VERSION 5.7 ;
  NOWIREEXTENSIONATPIN ON ;
  DIVIDERCHAR "/" ;
  BUSBITCHARS "[]" ;
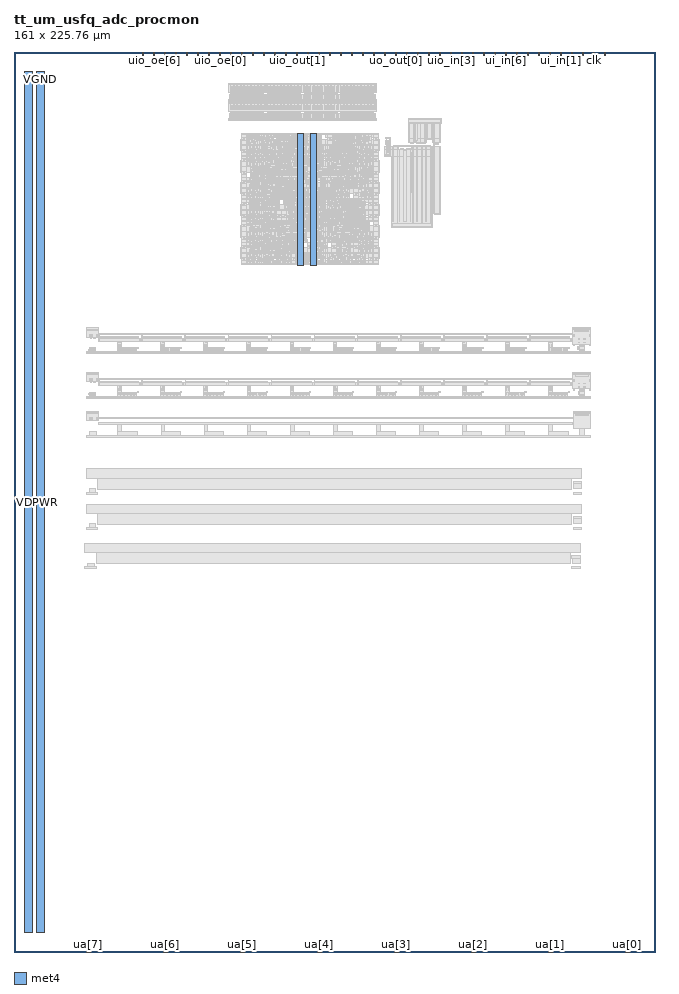
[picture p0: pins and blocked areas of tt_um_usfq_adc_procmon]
MACRO tt_um_usfq_adc_procmon
  CLASS BLOCK ;
  FOREIGN tt_um_usfq_adc_procmon ;
  ORIGIN 1.600 0.000 ;
  SIZE 161.000 BY 225.760 ;
  PIN VGND
    USE GROUND ;
    PORT
      LAYER met4 ;
        RECT 69.495 172.315 71.095 205.435 ;
    END
    PORT
      LAYER met4 ;
        RECT 4.000 5.000 6.000 220.760 ;
    END
  END VGND
  PIN VDPWR
    ANTENNAGATEAREA 171.431000 ;
    ANTENNADIFFAREA 286.977448 ;
    PORT
      LAYER met4 ;
        RECT 72.795 172.315 74.395 205.435 ;
    END
    PORT
      LAYER met4 ;
        RECT 1.000 5.000 3.000 220.760 ;
    END
  END VDPWR
  PIN uo_out[7]
    ANTENNADIFFAREA 0.222600 ;
    PORT
      LAYER met4 ;
        RECT 74.830 224.760 75.130 225.760 ;
    END
  END uo_out[7]
  PIN uo_out[6]
    ANTENNADIFFAREA 0.222600 ;
    PORT
      LAYER met4 ;
        RECT 77.590 224.760 77.890 225.760 ;
    END
  END uo_out[6]
  PIN uo_out[5]
    ANTENNADIFFAREA 0.222600 ;
    PORT
      LAYER met4 ;
        RECT 80.350 224.760 80.650 225.760 ;
    END
  END uo_out[5]
  PIN uo_out[4]
    ANTENNADIFFAREA 0.222600 ;
    PORT
      LAYER met4 ;
        RECT 83.110 224.760 83.410 225.760 ;
    END
  END uo_out[4]
  PIN uo_out[3]
    ANTENNADIFFAREA 0.222600 ;
    PORT
      LAYER met4 ;
        RECT 85.870 224.760 86.170 225.760 ;
    END
  END uo_out[3]
  PIN uo_out[2]
    ANTENNADIFFAREA 0.222600 ;
    PORT
      LAYER met4 ;
        RECT 88.630 224.760 88.930 225.760 ;
    END
  END uo_out[2]
  PIN uo_out[1]
    PORT
      LAYER met4 ;
        RECT 91.390 224.760 91.690 225.760 ;
    END
  END uo_out[1]
  PIN uo_out[0]
    PORT
      LAYER met4 ;
        RECT 94.150 224.760 94.450 225.760 ;
    END
  END uo_out[0]
  PIN uio_out[7]
    ANTENNADIFFAREA 4.233600 ;
    PORT
      LAYER met4 ;
        RECT 52.750 224.760 53.050 225.760 ;
    END
  END uio_out[7]
  PIN uio_out[6]
    ANTENNADIFFAREA 4.233600 ;
    PORT
      LAYER met4 ;
        RECT 55.510 224.760 55.810 225.760 ;
    END
  END uio_out[6]
  PIN uio_out[5]
    ANTENNADIFFAREA 4.233600 ;
    PORT
      LAYER met4 ;
        RECT 58.270 224.760 58.570 225.760 ;
    END
  END uio_out[5]
  PIN uio_out[4]
    ANTENNADIFFAREA 4.233600 ;
    PORT
      LAYER met4 ;
        RECT 61.030 224.760 61.330 225.760 ;
    END
  END uio_out[4]
  PIN uio_out[3]
    ANTENNADIFFAREA 4.233600 ;
    PORT
      LAYER met4 ;
        RECT 63.790 224.760 64.090 225.760 ;
    END
  END uio_out[3]
  PIN uio_out[2]
    ANTENNADIFFAREA 4.233600 ;
    PORT
      LAYER met4 ;
        RECT 66.550 224.760 66.850 225.760 ;
    END
  END uio_out[2]
  PIN uio_out[1]
    ANTENNADIFFAREA 4.936500 ;
    PORT
      LAYER met4 ;
        RECT 69.310 224.760 69.610 225.760 ;
    END
  END uio_out[1]
  PIN uio_out[0]
    ANTENNADIFFAREA 4.233600 ;
    PORT
      LAYER met4 ;
        RECT 72.070 224.760 72.370 225.760 ;
    END
  END uio_out[0]
  PIN uio_oe[7]
    ANTENNAGATEAREA 20.500000 ;
    ANTENNADIFFAREA 80.059700 ;
    PORT
      LAYER met4 ;
        RECT 30.670 224.760 30.970 225.760 ;
    END
  END uio_oe[7]
  PIN uio_oe[6]
    ANTENNAGATEAREA 20.500000 ;
    ANTENNADIFFAREA 80.059700 ;
    PORT
      LAYER met4 ;
        RECT 33.430 224.760 33.730 225.760 ;
    END
  END uio_oe[6]
  PIN uio_oe[5]
    ANTENNAGATEAREA 20.500000 ;
    ANTENNADIFFAREA 80.059700 ;
    PORT
      LAYER met4 ;
        RECT 36.190 224.760 36.490 225.760 ;
    END
  END uio_oe[5]
  PIN uio_oe[4]
    ANTENNAGATEAREA 20.500000 ;
    ANTENNADIFFAREA 80.059700 ;
    PORT
      LAYER met4 ;
        RECT 38.950 224.760 39.250 225.760 ;
    END
  END uio_oe[4]
  PIN uio_oe[3]
    ANTENNAGATEAREA 20.500000 ;
    ANTENNADIFFAREA 80.059700 ;
    PORT
      LAYER met4 ;
        RECT 41.710 224.760 42.010 225.760 ;
    END
  END uio_oe[3]
  PIN uio_oe[2]
    ANTENNAGATEAREA 20.500000 ;
    ANTENNADIFFAREA 80.059700 ;
    PORT
      LAYER met4 ;
        RECT 44.470 224.760 44.770 225.760 ;
    END
  END uio_oe[2]
  PIN uio_oe[1]
    ANTENNAGATEAREA 20.500000 ;
    ANTENNADIFFAREA 80.059700 ;
    PORT
      LAYER met4 ;
        RECT 47.230 224.760 47.530 225.760 ;
    END
  END uio_oe[1]
  PIN uio_oe[0]
    ANTENNAGATEAREA 20.500000 ;
    ANTENNADIFFAREA 80.059700 ;
    PORT
      LAYER met4 ;
        RECT 49.990 224.760 50.290 225.760 ;
    END
  END uio_oe[0]
  PIN uio_in[7]
    PORT
      LAYER met4 ;
        RECT 96.910 224.760 97.210 225.760 ;
    END
  END uio_in[7]
  PIN uio_in[6]
    PORT
      LAYER met4 ;
        RECT 99.670 224.760 99.970 225.760 ;
    END
  END uio_in[6]
  PIN uio_in[5]
    PORT
      LAYER met4 ;
        RECT 102.430 224.760 102.730 225.760 ;
    END
  END uio_in[5]
  PIN uio_in[4]
    PORT
      LAYER met4 ;
        RECT 105.190 224.760 105.490 225.760 ;
    END
  END uio_in[4]
  PIN uio_in[3]
    PORT
      LAYER met4 ;
        RECT 107.950 224.760 108.250 225.760 ;
    END
  END uio_in[3]
  PIN uio_in[2]
    PORT
      LAYER met4 ;
        RECT 110.710 224.760 111.010 225.760 ;
    END
  END uio_in[2]
  PIN uio_in[1]
    PORT
      LAYER met4 ;
        RECT 113.470 224.760 113.770 225.760 ;
    END
  END uio_in[1]
  PIN uio_in[0]
    PORT
      LAYER met4 ;
        RECT 116.230 224.760 116.530 225.760 ;
    END
  END uio_in[0]
  PIN ui_in[7]
    ANTENNAGATEAREA 1.431000 ;
    PORT
      LAYER met4 ;
        RECT 118.990 224.760 119.290 225.760 ;
    END
  END ui_in[7]
  PIN ui_in[6]
    PORT
      LAYER met4 ;
        RECT 121.750 224.760 122.050 225.760 ;
    END
  END ui_in[6]
  PIN ui_in[5]
    PORT
      LAYER met4 ;
        RECT 124.510 224.760 124.810 225.760 ;
    END
  END ui_in[5]
  PIN ui_in[4]
    PORT
      LAYER met4 ;
        RECT 127.270 224.760 127.570 225.760 ;
    END
  END ui_in[4]
  PIN ui_in[3]
    PORT
      LAYER met4 ;
        RECT 130.030 224.760 130.330 225.760 ;
    END
  END ui_in[3]
  PIN ui_in[2]
    PORT
      LAYER met4 ;
        RECT 132.790 224.760 133.090 225.760 ;
    END
  END ui_in[2]
  PIN ui_in[1]
    PORT
      LAYER met4 ;
        RECT 135.550 224.760 135.850 225.760 ;
    END
  END ui_in[1]
  PIN ui_in[0]
    PORT
      LAYER met4 ;
        RECT 138.310 224.760 138.610 225.760 ;
    END
  END ui_in[0]
  PIN ua[7]
    PORT
      LAYER met4 ;
        RECT 16.570 0.000 17.470 1.000 ;
    END
  END ua[7]
  PIN ua[5]
    PORT
      LAYER met4 ;
        RECT 55.210 0.000 56.110 1.000 ;
    END
  END ua[5]
  PIN ua[4]
    PORT
      LAYER met4 ;
        RECT 74.530 0.000 75.430 1.000 ;
    END
  END ua[4]
  PIN ua[3]
    PORT
      LAYER met4 ;
        RECT 93.850 0.000 94.750 1.000 ;
    END
  END ua[3]
  PIN ua[2]
    PORT
      LAYER met4 ;
        RECT 113.170 0.000 114.070 1.000 ;
    END
  END ua[2]
  PIN ua[1]
    ANTENNAGATEAREA 15.929999 ;
    PORT
      LAYER met4 ;
        RECT 132.490 0.000 133.390 1.000 ;
    END
  END ua[1]
  PIN ua[0]
    ANTENNAGATEAREA 16.056000 ;
    PORT
      LAYER met4 ;
        RECT 151.810 0.000 152.710 1.000 ;
    END
  END ua[0]
  PIN rst_n
    PORT
      LAYER met4 ;
        RECT 141.070 224.760 141.370 225.760 ;
    END
  END rst_n
  PIN ena
    PORT
      LAYER met4 ;
        RECT 146.590 224.760 146.890 225.760 ;
    END
  END ena
  PIN clk
    PORT
      LAYER met4 ;
        RECT 143.830 224.760 144.130 225.760 ;
    END
  END clk
  PIN ua[6]
    PORT
      LAYER met4 ;
        RECT 35.890 0.000 36.790 1.000 ;
    END
  END ua[6]
  OBS
      LAYER nwell ;
        RECT 52.250 215.580 89.410 217.955 ;
      LAYER pwell ;
        RECT 52.435 213.765 89.145 214.990 ;
        RECT 52.300 213.255 89.360 213.765 ;
      LAYER nwell ;
        RECT 52.250 210.870 89.410 213.245 ;
      LAYER pwell ;
        RECT 52.435 209.055 89.145 210.280 ;
        RECT 52.300 208.545 89.360 209.055 ;
        RECT 97.290 207.920 105.520 209.070 ;
        RECT 55.560 205.090 55.730 205.280 ;
        RECT 60.165 205.090 60.335 205.280 ;
        RECT 75.335 205.090 75.505 205.280 ;
        RECT 78.100 205.090 78.270 205.280 ;
        RECT 84.545 205.090 84.715 205.280 ;
        RECT 89.600 205.090 89.770 205.280 ;
        RECT 55.420 204.410 75.650 205.090 ;
        RECT 77.040 205.005 89.910 205.090 ;
        RECT 76.590 204.410 89.910 205.005 ;
        RECT 55.420 204.280 64.140 204.410 ;
        RECT 56.800 204.220 64.140 204.280 ;
        RECT 56.800 204.180 62.935 204.220 ;
        RECT 67.675 204.190 68.585 204.410 ;
        RECT 70.120 204.180 71.890 204.410 ;
        RECT 72.735 204.180 75.125 204.410 ;
        RECT 76.590 204.280 87.315 204.410 ;
        RECT 88.540 204.280 89.910 204.410 ;
        RECT 76.590 204.220 77.020 204.280 ;
        RECT 78.420 204.180 87.315 204.280 ;
        RECT 97.355 204.140 105.505 207.920 ;
      LAYER nwell ;
        RECT 55.225 201.060 90.105 203.890 ;
      LAYER pwell ;
        RECT 91.590 202.630 92.960 203.650 ;
        RECT 97.355 203.150 101.785 204.140 ;
        RECT 103.465 202.950 105.505 204.140 ;
      LAYER nwell ;
        RECT 91.405 201.340 94.885 202.040 ;
        RECT 98.125 201.340 103.255 202.040 ;
      LAYER pwell ;
        RECT 57.555 200.670 59.945 200.770 ;
        RECT 55.420 200.540 59.945 200.670 ;
        RECT 62.325 200.540 66.010 200.770 ;
        RECT 67.545 200.540 68.455 200.760 ;
        RECT 71.985 200.670 87.775 200.770 ;
        RECT 71.985 200.540 89.910 200.670 ;
        RECT 55.420 198.970 89.910 200.540 ;
      LAYER nwell ;
        RECT 91.405 199.665 103.255 201.340 ;
      LAYER pwell ;
        RECT 55.420 198.840 62.330 198.970 ;
        RECT 57.555 198.740 62.330 198.840 ;
        RECT 63.865 198.750 64.775 198.970 ;
        RECT 68.380 198.740 70.150 198.970 ;
        RECT 71.685 198.750 72.595 198.970 ;
        RECT 76.590 198.780 78.890 198.970 ;
        RECT 77.120 198.740 78.890 198.780 ;
        RECT 80.425 198.750 81.335 198.970 ;
        RECT 85.385 198.840 89.910 198.970 ;
        RECT 85.385 198.740 87.775 198.840 ;
      LAYER nwell ;
        RECT 55.225 195.620 90.105 198.450 ;
      LAYER pwell ;
        RECT 57.720 195.290 63.560 195.330 ;
        RECT 55.420 194.210 56.790 195.230 ;
        RECT 57.720 195.100 64.140 195.290 ;
        RECT 67.675 195.100 68.585 195.320 ;
        RECT 70.120 195.230 71.890 195.330 ;
        RECT 73.440 195.230 75.210 195.330 ;
        RECT 70.120 195.100 75.210 195.230 ;
        RECT 76.745 195.100 77.655 195.320 ;
        RECT 81.180 195.230 88.520 195.330 ;
        RECT 81.180 195.100 89.910 195.230 ;
        RECT 57.720 194.210 89.910 195.100 ;
        RECT 55.420 193.530 89.910 194.210 ;
        RECT 55.420 193.400 59.110 193.530 ;
        RECT 57.340 193.300 59.110 193.400 ;
        RECT 60.645 193.310 61.555 193.530 ;
        RECT 65.210 193.300 74.205 193.530 ;
        RECT 75.210 193.400 89.910 193.530 ;
        RECT 75.210 193.340 86.395 193.400 ;
        RECT 75.210 193.300 76.560 193.340 ;
        RECT 77.650 193.300 86.395 193.340 ;
      LAYER nwell ;
        RECT 55.225 190.180 90.105 193.010 ;
      LAYER pwell ;
        RECT 57.555 189.790 59.945 189.890 ;
        RECT 55.420 189.660 59.945 189.790 ;
        RECT 62.325 189.660 82.025 189.890 ;
        RECT 85.615 189.790 88.005 189.890 ;
        RECT 55.420 188.980 82.550 189.660 ;
        RECT 55.420 188.090 65.070 188.980 ;
        RECT 66.080 188.770 82.550 188.980 ;
        RECT 83.480 188.770 89.910 189.790 ;
        RECT 66.080 188.090 89.910 188.770 ;
        RECT 55.420 187.960 59.110 188.090 ;
        RECT 57.340 187.860 59.110 187.960 ;
        RECT 60.645 187.870 61.555 188.090 ;
        RECT 66.080 187.860 67.850 188.090 ;
        RECT 69.385 187.870 70.295 188.090 ;
        RECT 74.380 187.960 89.910 188.090 ;
        RECT 74.380 187.900 86.540 187.960 ;
        RECT 74.380 187.860 76.570 187.900 ;
        RECT 77.565 187.860 86.540 187.900 ;
      LAYER nwell ;
        RECT 55.225 184.740 90.105 187.570 ;
      LAYER pwell ;
        RECT 57.555 184.410 63.690 184.450 ;
        RECT 57.555 184.350 64.140 184.410 ;
        RECT 67.000 184.350 68.770 184.450 ;
        RECT 55.420 184.220 68.770 184.350 ;
        RECT 70.305 184.220 71.215 184.440 ;
        RECT 74.870 184.350 86.690 184.450 ;
        RECT 74.870 184.220 89.910 184.350 ;
        RECT 55.420 183.350 89.910 184.220 ;
        RECT 55.420 182.650 87.600 183.350 ;
        RECT 55.420 182.520 59.110 182.650 ;
        RECT 57.340 182.420 59.110 182.520 ;
        RECT 60.645 182.430 61.555 182.650 ;
        RECT 65.160 182.420 66.930 182.650 ;
        RECT 68.465 182.430 69.375 182.650 ;
        RECT 73.360 182.420 80.270 182.650 ;
        RECT 81.805 182.430 82.715 182.650 ;
        RECT 86.250 182.420 87.600 182.650 ;
        RECT 88.540 182.520 89.910 183.350 ;
      LAYER nwell ;
        RECT 55.225 179.300 90.105 182.130 ;
        RECT 93.125 181.730 103.255 199.665 ;
      LAYER pwell ;
        RECT 103.465 185.335 105.505 201.995 ;
        RECT 57.555 178.910 66.010 179.010 ;
        RECT 55.420 178.780 66.010 178.910 ;
        RECT 67.545 178.780 68.455 179.000 ;
        RECT 72.900 178.780 78.890 179.010 ;
        RECT 80.425 178.780 81.335 179.000 ;
        RECT 85.385 178.910 87.775 179.010 ;
        RECT 85.385 178.780 89.910 178.910 ;
        RECT 55.420 178.100 71.970 178.780 ;
        RECT 72.900 178.100 89.910 178.780 ;
        RECT 55.420 177.210 70.900 178.100 ;
        RECT 72.900 177.890 77.020 178.100 ;
        RECT 55.420 177.080 59.110 177.210 ;
        RECT 57.340 176.980 59.110 177.080 ;
        RECT 60.645 176.990 61.555 177.210 ;
        RECT 65.080 176.980 70.900 177.210 ;
        RECT 71.980 177.080 77.020 177.890 ;
        RECT 77.960 177.210 89.910 178.100 ;
        RECT 77.960 177.080 79.330 177.210 ;
        RECT 81.995 177.080 89.910 177.210 ;
        RECT 73.360 177.020 77.020 177.080 ;
        RECT 73.360 176.980 76.560 177.020 ;
        RECT 81.995 176.980 82.915 177.080 ;
        RECT 85.385 176.980 87.775 177.080 ;
      LAYER nwell ;
        RECT 55.225 173.860 90.105 176.690 ;
      LAYER pwell ;
        RECT 57.555 173.530 63.690 173.570 ;
        RECT 64.685 173.530 67.075 173.570 ;
        RECT 57.555 173.470 67.075 173.530 ;
        RECT 70.600 173.470 86.690 173.570 ;
        RECT 55.420 172.745 89.910 173.470 ;
        RECT 55.420 172.660 63.205 172.745 ;
        RECT 64.160 172.660 89.910 172.745 ;
        RECT 55.560 172.470 55.730 172.660 ;
        RECT 60.155 172.470 60.325 172.660 ;
        RECT 64.305 172.470 64.475 172.660 ;
        RECT 68.900 172.470 69.070 172.660 ;
        RECT 70.280 172.470 70.450 172.660 ;
        RECT 88.220 172.470 88.390 172.660 ;
        RECT 89.600 172.470 89.770 172.660 ;
      LAYER nwell ;
        RECT 16.640 154.240 19.475 156.540 ;
      LAYER pwell ;
        RECT 19.485 153.250 138.375 153.930 ;
        RECT 24.410 151.555 25.350 153.250 ;
        RECT 35.220 151.555 36.160 153.250 ;
        RECT 46.030 151.555 46.970 153.250 ;
        RECT 56.840 151.555 57.780 153.250 ;
        RECT 67.650 151.555 68.590 153.250 ;
        RECT 78.460 151.555 79.400 153.250 ;
        RECT 89.270 151.555 90.210 153.250 ;
        RECT 100.080 151.555 101.020 153.250 ;
        RECT 110.890 151.555 111.830 153.250 ;
        RECT 121.700 151.555 122.640 153.250 ;
        RECT 132.510 151.555 133.450 153.250 ;
      LAYER nwell ;
        RECT 138.585 152.440 143.075 156.540 ;
      LAYER pwell ;
        RECT 17.390 150.590 18.920 151.550 ;
        RECT 24.410 150.590 29.220 151.555 ;
        RECT 35.220 150.590 40.030 151.555 ;
        RECT 46.030 150.590 50.840 151.555 ;
        RECT 56.840 150.590 61.650 151.555 ;
        RECT 67.650 150.590 72.460 151.555 ;
        RECT 78.460 150.590 83.270 151.555 ;
        RECT 89.270 150.590 94.080 151.555 ;
        RECT 100.080 150.590 104.890 151.555 ;
        RECT 110.890 150.590 115.700 151.555 ;
        RECT 121.700 150.590 126.510 151.555 ;
        RECT 132.510 150.590 137.320 151.555 ;
        RECT 140.145 150.590 141.515 152.230 ;
        RECT 16.635 150.080 143.080 150.590 ;
      LAYER nwell ;
        RECT 16.665 143.065 19.500 145.365 ;
      LAYER pwell ;
        RECT 19.510 142.075 138.400 142.755 ;
        RECT 24.435 140.380 25.375 142.075 ;
        RECT 35.245 140.380 36.185 142.075 ;
        RECT 46.055 140.380 46.995 142.075 ;
        RECT 56.865 140.380 57.805 142.075 ;
        RECT 67.675 140.380 68.615 142.075 ;
        RECT 78.485 140.380 79.425 142.075 ;
        RECT 89.295 140.380 90.235 142.075 ;
        RECT 100.105 140.380 101.045 142.075 ;
        RECT 110.915 140.380 111.855 142.075 ;
        RECT 121.725 140.380 122.665 142.075 ;
        RECT 132.535 140.380 133.475 142.075 ;
      LAYER nwell ;
        RECT 138.610 141.265 143.100 145.365 ;
      LAYER pwell ;
        RECT 17.415 139.415 18.945 140.375 ;
        RECT 24.435 139.415 29.245 140.380 ;
        RECT 35.245 139.415 40.055 140.380 ;
        RECT 46.055 139.415 50.865 140.380 ;
        RECT 56.865 139.415 61.675 140.380 ;
        RECT 67.675 139.415 72.485 140.380 ;
        RECT 78.485 139.415 83.295 140.380 ;
        RECT 89.295 139.415 94.105 140.380 ;
        RECT 100.105 139.415 104.915 140.380 ;
        RECT 110.915 139.415 115.725 140.380 ;
        RECT 121.725 139.415 126.535 140.380 ;
        RECT 132.535 139.415 137.345 140.380 ;
        RECT 140.170 139.415 141.540 141.055 ;
        RECT 16.660 138.905 143.105 139.415 ;
      LAYER nwell ;
        RECT 16.695 133.230 19.530 135.530 ;
      LAYER pwell ;
        RECT 19.540 132.240 138.430 132.920 ;
        RECT 24.465 130.545 25.405 132.240 ;
        RECT 35.275 130.545 36.215 132.240 ;
        RECT 46.085 130.545 47.025 132.240 ;
        RECT 56.895 130.545 57.835 132.240 ;
        RECT 67.705 130.545 68.645 132.240 ;
        RECT 78.515 130.545 79.455 132.240 ;
        RECT 89.325 130.545 90.265 132.240 ;
        RECT 100.135 130.545 101.075 132.240 ;
        RECT 110.945 130.545 111.885 132.240 ;
        RECT 121.755 130.545 122.695 132.240 ;
        RECT 132.565 130.545 133.505 132.240 ;
      LAYER nwell ;
        RECT 138.640 131.430 143.130 135.530 ;
      LAYER pwell ;
        RECT 17.445 129.580 18.975 130.540 ;
        RECT 24.465 129.580 29.275 130.545 ;
        RECT 35.275 129.580 40.085 130.545 ;
        RECT 46.085 129.580 50.895 130.545 ;
        RECT 56.895 129.580 61.705 130.545 ;
        RECT 67.705 129.580 72.515 130.545 ;
        RECT 78.515 129.580 83.325 130.545 ;
        RECT 89.325 129.580 94.135 130.545 ;
        RECT 100.135 129.580 104.945 130.545 ;
        RECT 110.945 129.580 115.755 130.545 ;
        RECT 121.755 129.580 126.565 130.545 ;
        RECT 132.565 129.580 137.375 130.545 ;
        RECT 140.200 129.580 141.570 131.220 ;
        RECT 16.690 129.070 143.135 129.580 ;
      LAYER nwell ;
        RECT 16.580 118.890 140.870 121.190 ;
        RECT 19.375 118.740 140.870 118.890 ;
      LAYER pwell ;
        RECT 17.330 115.240 18.860 116.200 ;
      LAYER nwell ;
        RECT 19.375 115.990 138.365 118.740 ;
      LAYER pwell ;
        RECT 138.750 117.460 140.820 118.140 ;
        RECT 138.790 116.180 140.780 117.460 ;
        RECT 16.575 114.730 19.415 115.240 ;
        RECT 138.735 114.730 140.835 115.240 ;
      LAYER nwell ;
        RECT 16.565 110.075 140.855 112.375 ;
        RECT 19.360 109.925 140.855 110.075 ;
      LAYER pwell ;
        RECT 17.315 106.425 18.845 107.385 ;
      LAYER nwell ;
        RECT 19.360 107.175 138.350 109.925 ;
      LAYER pwell ;
        RECT 138.735 108.645 140.805 109.325 ;
        RECT 138.775 107.365 140.765 108.645 ;
        RECT 16.560 105.915 19.400 106.425 ;
        RECT 138.720 105.915 140.820 106.425 ;
      LAYER nwell ;
        RECT 16.195 100.240 140.485 102.540 ;
        RECT 18.990 100.090 140.485 100.240 ;
      LAYER pwell ;
        RECT 16.945 96.590 18.475 97.550 ;
      LAYER nwell ;
        RECT 18.990 97.340 137.980 100.090 ;
      LAYER pwell ;
        RECT 138.365 98.810 140.435 99.490 ;
        RECT 138.405 97.530 140.395 98.810 ;
        RECT 16.190 96.080 19.030 96.590 ;
        RECT 138.350 96.080 140.450 96.590 ;
      LAYER li1 ;
        RECT 52.430 217.525 89.230 217.775 ;
        RECT 52.605 215.930 52.775 217.525 ;
        RECT 53.035 215.930 53.205 217.060 ;
        RECT 53.465 215.930 53.635 217.525 ;
        RECT 53.895 215.930 54.065 217.060 ;
        RECT 54.325 215.930 54.495 217.525 ;
        RECT 54.755 215.930 54.925 217.060 ;
        RECT 55.185 215.930 55.355 217.525 ;
        RECT 55.615 215.930 55.785 217.060 ;
        RECT 56.045 215.930 56.215 217.525 ;
        RECT 56.475 215.930 56.645 217.060 ;
        RECT 56.905 215.930 57.075 217.525 ;
        RECT 57.335 215.930 57.505 217.060 ;
        RECT 57.765 215.930 57.935 217.525 ;
        RECT 58.195 215.930 58.365 217.060 ;
        RECT 58.625 215.930 58.795 217.525 ;
        RECT 59.055 215.930 59.225 217.060 ;
        RECT 59.485 215.930 59.655 217.525 ;
        RECT 59.915 215.930 60.085 217.060 ;
        RECT 60.345 215.930 60.515 217.525 ;
        RECT 60.775 215.930 60.945 217.060 ;
        RECT 61.205 215.930 61.375 217.525 ;
        RECT 61.805 215.930 61.975 217.525 ;
        RECT 62.235 215.930 62.405 217.060 ;
        RECT 62.665 215.930 62.835 217.525 ;
        RECT 63.095 215.930 63.265 217.060 ;
        RECT 63.525 215.930 63.695 217.525 ;
        RECT 63.955 215.930 64.125 217.060 ;
        RECT 64.385 215.930 64.555 217.525 ;
        RECT 64.815 215.930 64.985 217.060 ;
        RECT 65.245 215.930 65.415 217.525 ;
        RECT 65.675 215.930 65.845 217.060 ;
        RECT 66.105 215.930 66.275 217.525 ;
        RECT 66.535 215.930 66.705 217.060 ;
        RECT 66.965 215.930 67.135 217.525 ;
        RECT 67.395 215.930 67.565 217.060 ;
        RECT 67.825 215.930 67.995 217.525 ;
        RECT 68.255 215.930 68.425 217.060 ;
        RECT 68.685 215.930 68.855 217.525 ;
        RECT 69.115 215.930 69.285 217.060 ;
        RECT 69.545 215.930 69.715 217.525 ;
        RECT 69.975 215.930 70.145 217.060 ;
        RECT 70.405 215.930 70.575 217.525 ;
        RECT 71.005 215.930 71.175 217.525 ;
        RECT 71.435 215.930 71.605 217.060 ;
        RECT 71.865 215.930 72.035 217.525 ;
        RECT 72.295 215.930 72.465 217.060 ;
        RECT 72.725 215.930 72.895 217.525 ;
        RECT 73.155 215.930 73.325 217.060 ;
        RECT 73.585 215.930 73.755 217.525 ;
        RECT 74.015 215.930 74.185 217.060 ;
        RECT 74.445 215.930 74.615 217.525 ;
        RECT 74.875 215.930 75.045 217.060 ;
        RECT 75.305 215.930 75.475 217.525 ;
        RECT 75.735 215.930 75.905 217.060 ;
        RECT 76.165 215.930 76.335 217.525 ;
        RECT 76.595 215.930 76.765 217.060 ;
        RECT 77.025 215.930 77.195 217.525 ;
        RECT 77.455 215.930 77.625 217.060 ;
        RECT 77.885 215.930 78.055 217.525 ;
        RECT 78.315 215.930 78.485 217.060 ;
        RECT 78.745 215.930 78.915 217.525 ;
        RECT 79.175 215.930 79.345 217.060 ;
        RECT 79.605 215.930 79.775 217.525 ;
        RECT 80.205 215.930 80.375 217.525 ;
        RECT 80.635 215.930 80.805 217.060 ;
        RECT 81.065 215.930 81.235 217.525 ;
        RECT 81.495 215.930 81.665 217.060 ;
        RECT 81.925 215.930 82.095 217.525 ;
        RECT 82.355 215.930 82.525 217.060 ;
        RECT 82.785 215.930 82.955 217.525 ;
        RECT 83.215 215.930 83.385 217.060 ;
        RECT 83.645 215.930 83.815 217.525 ;
        RECT 84.075 215.930 84.245 217.060 ;
        RECT 84.505 215.930 84.675 217.525 ;
        RECT 84.935 215.930 85.105 217.060 ;
        RECT 85.365 215.930 85.535 217.525 ;
        RECT 85.795 215.930 85.965 217.060 ;
        RECT 86.225 215.930 86.395 217.525 ;
        RECT 86.655 215.930 86.825 217.060 ;
        RECT 87.085 215.930 87.255 217.525 ;
        RECT 87.515 215.930 87.685 217.060 ;
        RECT 87.945 215.930 88.115 217.525 ;
        RECT 88.375 215.930 88.545 217.060 ;
        RECT 88.805 215.930 88.975 217.525 ;
        RECT 52.800 215.390 61.025 215.560 ;
        RECT 62.000 215.390 70.225 215.560 ;
        RECT 71.200 215.390 79.425 215.560 ;
        RECT 80.400 215.390 88.625 215.560 ;
        RECT 52.955 215.050 54.145 215.220 ;
        RECT 62.155 215.050 63.345 215.220 ;
        RECT 71.355 215.050 72.545 215.220 ;
        RECT 80.555 215.050 81.745 215.220 ;
        RECT 52.605 213.635 52.775 214.860 ;
        RECT 53.035 214.100 53.205 214.860 ;
        RECT 53.465 213.635 53.635 214.860 ;
        RECT 53.895 214.100 54.065 214.860 ;
        RECT 54.325 213.635 54.495 214.860 ;
        RECT 54.755 214.100 54.925 214.860 ;
        RECT 55.185 213.635 55.355 214.860 ;
        RECT 55.615 214.100 55.785 214.860 ;
        RECT 56.045 213.635 56.215 214.860 ;
        RECT 56.475 214.100 56.645 214.860 ;
        RECT 56.905 213.635 57.075 214.860 ;
        RECT 57.335 214.100 57.505 214.860 ;
        RECT 57.765 213.635 57.935 214.860 ;
        RECT 58.195 214.100 58.365 214.860 ;
        RECT 58.625 213.635 58.795 214.860 ;
        RECT 59.055 214.100 59.225 214.860 ;
        RECT 59.485 213.635 59.655 214.860 ;
        RECT 59.915 214.100 60.085 214.860 ;
        RECT 60.345 213.635 60.515 214.860 ;
        RECT 60.775 214.100 60.945 214.860 ;
        RECT 61.205 213.635 61.375 214.860 ;
        RECT 61.805 213.635 61.975 214.860 ;
        RECT 62.235 214.100 62.405 214.860 ;
        RECT 62.665 213.635 62.835 214.860 ;
        RECT 63.095 214.100 63.265 214.860 ;
        RECT 63.525 213.635 63.695 214.860 ;
        RECT 63.955 214.100 64.125 214.860 ;
        RECT 64.385 213.635 64.555 214.860 ;
        RECT 64.815 214.100 64.985 214.860 ;
        RECT 65.245 213.635 65.415 214.860 ;
        RECT 65.675 214.100 65.845 214.860 ;
        RECT 66.105 213.635 66.275 214.860 ;
        RECT 66.535 214.100 66.705 214.860 ;
        RECT 66.965 213.635 67.135 214.860 ;
        RECT 67.395 214.100 67.565 214.860 ;
        RECT 67.825 213.635 67.995 214.860 ;
        RECT 68.255 214.100 68.425 214.860 ;
        RECT 68.685 213.635 68.855 214.860 ;
        RECT 69.115 214.100 69.285 214.860 ;
        RECT 69.545 213.635 69.715 214.860 ;
        RECT 69.975 214.100 70.145 214.860 ;
        RECT 70.405 213.635 70.575 214.860 ;
        RECT 71.005 213.635 71.175 214.860 ;
        RECT 71.435 214.100 71.605 214.860 ;
        RECT 71.865 213.635 72.035 214.860 ;
        RECT 72.295 214.100 72.465 214.860 ;
        RECT 72.725 213.635 72.895 214.860 ;
        RECT 73.155 214.100 73.325 214.860 ;
        RECT 73.585 213.635 73.755 214.860 ;
        RECT 74.015 214.100 74.185 214.860 ;
        RECT 74.445 213.635 74.615 214.860 ;
        RECT 74.875 214.100 75.045 214.860 ;
        RECT 75.305 213.635 75.475 214.860 ;
        RECT 75.735 214.100 75.905 214.860 ;
        RECT 76.165 213.635 76.335 214.860 ;
        RECT 76.595 214.100 76.765 214.860 ;
        RECT 77.025 213.635 77.195 214.860 ;
        RECT 77.455 214.100 77.625 214.860 ;
        RECT 77.885 213.635 78.055 214.860 ;
        RECT 78.315 214.100 78.485 214.860 ;
        RECT 78.745 213.635 78.915 214.860 ;
        RECT 79.175 214.100 79.345 214.860 ;
        RECT 79.605 213.635 79.775 214.860 ;
        RECT 80.205 213.635 80.375 214.860 ;
        RECT 80.635 214.100 80.805 214.860 ;
        RECT 81.065 213.635 81.235 214.860 ;
        RECT 81.495 214.100 81.665 214.860 ;
        RECT 81.925 213.635 82.095 214.860 ;
        RECT 82.355 214.100 82.525 214.860 ;
        RECT 82.785 213.635 82.955 214.860 ;
        RECT 83.215 214.100 83.385 214.860 ;
        RECT 83.645 213.635 83.815 214.860 ;
        RECT 84.075 214.100 84.245 214.860 ;
        RECT 84.505 213.635 84.675 214.860 ;
        RECT 84.935 214.100 85.105 214.860 ;
        RECT 85.365 213.635 85.535 214.860 ;
        RECT 85.795 214.100 85.965 214.860 ;
        RECT 86.225 213.635 86.395 214.860 ;
        RECT 86.655 214.100 86.825 214.860 ;
        RECT 87.085 213.635 87.255 214.860 ;
        RECT 87.515 214.100 87.685 214.860 ;
        RECT 87.945 213.635 88.115 214.860 ;
        RECT 88.375 214.100 88.545 214.860 ;
        RECT 88.805 213.635 88.975 214.860 ;
        RECT 52.430 213.385 89.230 213.635 ;
        RECT 52.430 212.815 89.230 213.065 ;
        RECT 52.605 211.220 52.775 212.815 ;
        RECT 53.035 211.220 53.205 212.350 ;
        RECT 53.465 211.220 53.635 212.815 ;
        RECT 53.895 211.220 54.065 212.350 ;
        RECT 54.325 211.220 54.495 212.815 ;
        RECT 54.755 211.220 54.925 212.350 ;
        RECT 55.185 211.220 55.355 212.815 ;
        RECT 55.615 211.220 55.785 212.350 ;
        RECT 56.045 211.220 56.215 212.815 ;
        RECT 56.475 211.220 56.645 212.350 ;
        RECT 56.905 211.220 57.075 212.815 ;
        RECT 57.335 211.220 57.505 212.350 ;
        RECT 57.765 211.220 57.935 212.815 ;
        RECT 58.195 211.220 58.365 212.350 ;
        RECT 58.625 211.220 58.795 212.815 ;
        RECT 59.055 211.220 59.225 212.350 ;
        RECT 59.485 211.220 59.655 212.815 ;
        RECT 59.915 211.220 60.085 212.350 ;
        RECT 60.345 211.220 60.515 212.815 ;
        RECT 60.775 211.220 60.945 212.350 ;
        RECT 61.205 211.220 61.375 212.815 ;
        RECT 61.805 211.220 61.975 212.815 ;
        RECT 62.235 211.220 62.405 212.350 ;
        RECT 62.665 211.220 62.835 212.815 ;
        RECT 63.095 211.220 63.265 212.350 ;
        RECT 63.525 211.220 63.695 212.815 ;
        RECT 63.955 211.220 64.125 212.350 ;
        RECT 64.385 211.220 64.555 212.815 ;
        RECT 64.815 211.220 64.985 212.350 ;
        RECT 65.245 211.220 65.415 212.815 ;
        RECT 65.675 211.220 65.845 212.350 ;
        RECT 66.105 211.220 66.275 212.815 ;
        RECT 66.535 211.220 66.705 212.350 ;
        RECT 66.965 211.220 67.135 212.815 ;
        RECT 67.395 211.220 67.565 212.350 ;
        RECT 67.825 211.220 67.995 212.815 ;
        RECT 68.255 211.220 68.425 212.350 ;
        RECT 68.685 211.220 68.855 212.815 ;
        RECT 69.115 211.220 69.285 212.350 ;
        RECT 69.545 211.220 69.715 212.815 ;
        RECT 69.975 211.220 70.145 212.350 ;
        RECT 70.405 211.220 70.575 212.815 ;
        RECT 71.005 211.220 71.175 212.815 ;
        RECT 71.435 211.220 71.605 212.350 ;
        RECT 71.865 211.220 72.035 212.815 ;
        RECT 72.295 211.220 72.465 212.350 ;
        RECT 72.725 211.220 72.895 212.815 ;
        RECT 73.155 211.220 73.325 212.350 ;
        RECT 73.585 211.220 73.755 212.815 ;
        RECT 74.015 211.220 74.185 212.350 ;
        RECT 74.445 211.220 74.615 212.815 ;
        RECT 74.875 211.220 75.045 212.350 ;
        RECT 75.305 211.220 75.475 212.815 ;
        RECT 75.735 211.220 75.905 212.350 ;
        RECT 76.165 211.220 76.335 212.815 ;
        RECT 76.595 211.220 76.765 212.350 ;
        RECT 77.025 211.220 77.195 212.815 ;
        RECT 77.455 211.220 77.625 212.350 ;
        RECT 77.885 211.220 78.055 212.815 ;
        RECT 78.315 211.220 78.485 212.350 ;
        RECT 78.745 211.220 78.915 212.815 ;
        RECT 79.175 211.220 79.345 212.350 ;
        RECT 79.605 211.220 79.775 212.815 ;
        RECT 80.205 211.220 80.375 212.815 ;
        RECT 80.635 211.220 80.805 212.350 ;
        RECT 81.065 211.220 81.235 212.815 ;
        RECT 81.495 211.220 81.665 212.350 ;
        RECT 81.925 211.220 82.095 212.815 ;
        RECT 82.355 211.220 82.525 212.350 ;
        RECT 82.785 211.220 82.955 212.815 ;
        RECT 83.215 211.220 83.385 212.350 ;
        RECT 83.645 211.220 83.815 212.815 ;
        RECT 84.075 211.220 84.245 212.350 ;
        RECT 84.505 211.220 84.675 212.815 ;
        RECT 84.935 211.220 85.105 212.350 ;
        RECT 85.365 211.220 85.535 212.815 ;
        RECT 85.795 211.220 85.965 212.350 ;
        RECT 86.225 211.220 86.395 212.815 ;
        RECT 86.655 211.220 86.825 212.350 ;
        RECT 87.085 211.220 87.255 212.815 ;
        RECT 87.515 211.220 87.685 212.350 ;
        RECT 87.945 211.220 88.115 212.815 ;
        RECT 88.375 211.220 88.545 212.350 ;
        RECT 88.805 211.220 88.975 212.815 ;
        RECT 52.800 210.680 61.025 210.850 ;
        RECT 62.000 210.680 70.225 210.850 ;
        RECT 71.200 210.680 79.425 210.850 ;
        RECT 80.400 210.680 88.625 210.850 ;
        RECT 52.955 210.340 54.145 210.510 ;
        RECT 62.155 210.340 63.345 210.510 ;
        RECT 71.355 210.340 72.545 210.510 ;
        RECT 80.555 210.340 81.745 210.510 ;
        RECT 52.605 208.925 52.775 210.150 ;
        RECT 53.035 209.390 53.205 210.150 ;
        RECT 53.465 208.925 53.635 210.150 ;
        RECT 53.895 209.390 54.065 210.150 ;
        RECT 54.325 208.925 54.495 210.150 ;
        RECT 54.755 209.390 54.925 210.150 ;
        RECT 55.185 208.925 55.355 210.150 ;
        RECT 55.615 209.390 55.785 210.150 ;
        RECT 56.045 208.925 56.215 210.150 ;
        RECT 56.475 209.390 56.645 210.150 ;
        RECT 56.905 208.925 57.075 210.150 ;
        RECT 57.335 209.390 57.505 210.150 ;
        RECT 57.765 208.925 57.935 210.150 ;
        RECT 58.195 209.390 58.365 210.150 ;
        RECT 58.625 208.925 58.795 210.150 ;
        RECT 59.055 209.390 59.225 210.150 ;
        RECT 59.485 208.925 59.655 210.150 ;
        RECT 59.915 209.390 60.085 210.150 ;
        RECT 60.345 208.925 60.515 210.150 ;
        RECT 60.775 209.390 60.945 210.150 ;
        RECT 61.205 208.925 61.375 210.150 ;
        RECT 61.805 208.925 61.975 210.150 ;
        RECT 62.235 209.390 62.405 210.150 ;
        RECT 62.665 208.925 62.835 210.150 ;
        RECT 63.095 209.390 63.265 210.150 ;
        RECT 63.525 208.925 63.695 210.150 ;
        RECT 63.955 209.390 64.125 210.150 ;
        RECT 64.385 208.925 64.555 210.150 ;
        RECT 64.815 209.390 64.985 210.150 ;
        RECT 65.245 208.925 65.415 210.150 ;
        RECT 65.675 209.390 65.845 210.150 ;
        RECT 66.105 208.925 66.275 210.150 ;
        RECT 66.535 209.390 66.705 210.150 ;
        RECT 66.965 208.925 67.135 210.150 ;
        RECT 67.395 209.390 67.565 210.150 ;
        RECT 67.825 208.925 67.995 210.150 ;
        RECT 68.255 209.390 68.425 210.150 ;
        RECT 68.685 208.925 68.855 210.150 ;
        RECT 69.115 209.390 69.285 210.150 ;
        RECT 69.545 208.925 69.715 210.150 ;
        RECT 69.975 209.390 70.145 210.150 ;
        RECT 70.405 208.925 70.575 210.150 ;
        RECT 71.005 208.925 71.175 210.150 ;
        RECT 71.435 209.390 71.605 210.150 ;
        RECT 71.865 208.925 72.035 210.150 ;
        RECT 72.295 209.390 72.465 210.150 ;
        RECT 72.725 208.925 72.895 210.150 ;
        RECT 73.155 209.390 73.325 210.150 ;
        RECT 73.585 208.925 73.755 210.150 ;
        RECT 74.015 209.390 74.185 210.150 ;
        RECT 74.445 208.925 74.615 210.150 ;
        RECT 74.875 209.390 75.045 210.150 ;
        RECT 75.305 208.925 75.475 210.150 ;
        RECT 75.735 209.390 75.905 210.150 ;
        RECT 76.165 208.925 76.335 210.150 ;
        RECT 76.595 209.390 76.765 210.150 ;
        RECT 77.025 208.925 77.195 210.150 ;
        RECT 77.455 209.390 77.625 210.150 ;
        RECT 77.885 208.925 78.055 210.150 ;
        RECT 78.315 209.390 78.485 210.150 ;
        RECT 78.745 208.925 78.915 210.150 ;
        RECT 79.175 209.390 79.345 210.150 ;
        RECT 79.605 208.925 79.775 210.150 ;
        RECT 80.205 208.925 80.375 210.150 ;
        RECT 80.635 209.390 80.805 210.150 ;
        RECT 81.065 208.925 81.235 210.150 ;
        RECT 81.495 209.390 81.665 210.150 ;
        RECT 81.925 208.925 82.095 210.150 ;
        RECT 82.355 209.390 82.525 210.150 ;
        RECT 82.785 208.925 82.955 210.150 ;
        RECT 83.215 209.390 83.385 210.150 ;
        RECT 83.645 208.925 83.815 210.150 ;
        RECT 84.075 209.390 84.245 210.150 ;
        RECT 84.505 208.925 84.675 210.150 ;
        RECT 84.935 209.390 85.105 210.150 ;
        RECT 85.365 208.925 85.535 210.150 ;
        RECT 85.795 209.390 85.965 210.150 ;
        RECT 86.225 208.925 86.395 210.150 ;
        RECT 86.655 209.390 86.825 210.150 ;
        RECT 87.085 208.925 87.255 210.150 ;
        RECT 87.515 209.390 87.685 210.150 ;
        RECT 87.945 208.925 88.115 210.150 ;
        RECT 88.375 209.390 88.545 210.150 ;
        RECT 88.805 208.925 88.975 210.150 ;
        RECT 52.430 208.675 89.230 208.925 ;
        RECT 97.460 208.050 105.350 208.940 ;
        RECT 97.525 207.665 97.695 207.780 ;
        RECT 97.525 205.535 97.700 207.665 ;
        RECT 55.415 205.110 89.915 205.280 ;
        RECT 55.500 204.360 56.710 205.110 ;
        RECT 55.500 203.820 56.020 204.360 ;
        RECT 56.900 204.310 57.140 205.110 ;
        RECT 56.190 203.650 56.710 204.190 ;
        RECT 55.500 202.560 56.710 203.650 ;
        RECT 56.885 202.560 57.140 203.560 ;
        RECT 57.325 202.730 57.570 204.940 ;
        RECT 57.740 204.730 58.070 205.110 ;
        RECT 58.260 204.560 58.590 204.940 ;
        RECT 59.140 204.730 59.470 205.110 ;
        RECT 57.740 204.355 58.590 204.560 ;
        RECT 58.760 204.560 58.970 204.730 ;
        RECT 59.640 204.560 59.915 204.700 ;
        RECT 58.760 204.370 59.915 204.560 ;
        RECT 60.100 204.460 60.425 204.940 ;
        RECT 60.595 204.630 60.925 205.110 ;
        RECT 57.740 203.865 58.070 204.355 ;
        RECT 60.100 204.290 61.020 204.460 ;
        RECT 61.190 204.340 61.660 204.940 ;
        RECT 57.900 203.410 58.070 203.865 ;
        RECT 58.240 203.580 58.650 204.185 ;
        RECT 58.820 203.795 59.405 204.170 ;
        RECT 59.200 203.750 59.405 203.795 ;
        RECT 59.200 203.580 59.410 203.750 ;
        RECT 59.660 203.745 59.920 204.200 ;
        RECT 60.670 204.170 61.020 204.290 ;
        RECT 60.100 203.875 60.500 204.120 ;
        RECT 60.670 203.900 61.120 204.170 ;
        RECT 61.485 204.120 61.660 204.340 ;
        RECT 61.830 204.460 62.080 204.940 ;
        RECT 62.255 204.630 62.860 205.110 ;
        RECT 63.030 204.555 63.610 204.940 ;
        RECT 61.830 204.290 62.780 204.460 ;
        RECT 62.610 204.205 62.780 204.290 ;
        RECT 61.485 203.945 62.435 204.120 ;
        RECT 60.670 203.705 61.020 203.900 ;
        RECT 57.900 203.190 59.020 203.410 ;
        RECT 59.200 203.210 59.405 203.580 ;
        RECT 57.740 202.560 58.590 203.010 ;
        RECT 58.760 202.730 59.020 203.190 ;
        RECT 59.590 202.560 59.915 203.545 ;
        RECT 60.100 203.535 61.020 203.705 ;
        RECT 60.100 202.730 60.445 203.535 ;
        RECT 61.485 203.405 61.660 203.945 ;
        RECT 62.610 203.870 63.065 204.205 ;
        RECT 62.610 203.700 62.780 203.870 ;
        RECT 60.615 202.560 60.940 203.365 ;
        RECT 61.210 202.730 61.660 203.405 ;
        RECT 61.830 203.530 62.780 203.700 ;
        RECT 63.245 203.630 63.610 204.555 ;
        RECT 63.780 204.385 64.070 205.110 ;
        RECT 64.330 204.560 64.500 204.850 ;
        RECT 64.670 204.730 65.000 205.110 ;
        RECT 64.330 204.390 64.995 204.560 ;
        RECT 61.830 202.730 62.080 203.530 ;
        RECT 62.250 202.560 62.860 203.360 ;
        RECT 63.050 202.730 63.610 203.630 ;
        RECT 63.780 202.560 64.070 203.725 ;
        RECT 64.245 203.570 64.595 204.220 ;
        RECT 64.765 203.400 64.995 204.390 ;
        RECT 64.330 203.230 64.995 203.400 ;
        RECT 64.330 202.730 64.500 203.230 ;
        RECT 64.670 202.560 65.000 203.060 ;
        RECT 65.170 202.730 65.355 204.850 ;
        RECT 65.610 204.650 65.860 205.110 ;
        RECT 66.030 204.660 66.365 204.830 ;
        RECT 66.560 204.660 67.235 204.830 ;
        RECT 66.030 204.520 66.200 204.660 ;
        RECT 65.525 203.530 65.805 204.480 ;
        RECT 65.975 204.390 66.200 204.520 ;
        RECT 65.975 203.285 66.145 204.390 ;
        RECT 66.370 204.240 66.895 204.460 ;
        RECT 66.315 203.475 66.555 204.070 ;
        RECT 66.725 203.540 66.895 204.240 ;
        RECT 67.065 203.880 67.235 204.660 ;
        RECT 67.555 204.610 67.925 205.110 ;
        RECT 68.105 204.660 68.510 204.830 ;
        RECT 68.680 204.660 69.465 204.830 ;
        RECT 68.105 204.430 68.275 204.660 ;
        RECT 67.445 204.130 68.275 204.430 ;
        RECT 68.660 204.160 69.125 204.490 ;
        RECT 67.445 204.100 67.645 204.130 ;
        RECT 67.765 203.880 67.935 203.950 ;
        RECT 67.065 203.710 67.935 203.880 ;
        RECT 67.425 203.620 67.935 203.710 ;
        RECT 65.975 203.155 66.280 203.285 ;
        RECT 66.725 203.175 67.255 203.540 ;
        RECT 65.595 202.560 65.860 203.020 ;
        RECT 66.030 202.730 66.280 203.155 ;
        RECT 67.425 203.005 67.595 203.620 ;
        RECT 66.490 202.835 67.595 203.005 ;
        RECT 67.765 202.560 67.935 203.360 ;
        RECT 68.105 203.060 68.275 204.130 ;
        RECT 68.445 203.230 68.635 203.950 ;
        RECT 68.805 203.200 69.125 204.160 ;
        RECT 69.295 204.200 69.465 204.660 ;
        RECT 69.740 204.580 69.950 205.110 ;
        RECT 70.210 204.370 70.540 204.895 ;
        RECT 70.710 204.500 70.880 205.110 ;
        RECT 71.050 204.455 71.380 204.890 ;
        RECT 71.550 204.595 71.720 205.110 ;
        RECT 72.060 204.555 72.640 204.940 ;
        RECT 72.810 204.630 73.415 205.110 ;
        RECT 71.050 204.370 71.430 204.455 ;
        RECT 70.340 204.200 70.540 204.370 ;
        RECT 71.205 204.330 71.430 204.370 ;
        RECT 69.295 203.870 70.170 204.200 ;
        RECT 70.340 203.870 71.090 204.200 ;
        RECT 68.105 202.730 68.355 203.060 ;
        RECT 69.295 203.030 69.465 203.870 ;
        RECT 70.340 203.665 70.530 203.870 ;
        RECT 71.260 203.750 71.430 204.330 ;
        RECT 71.215 203.700 71.430 203.750 ;
        RECT 69.635 203.290 70.530 203.665 ;
        RECT 71.040 203.620 71.430 203.700 ;
        RECT 72.060 203.630 72.425 204.555 ;
        RECT 73.590 204.460 73.840 204.940 ;
        RECT 72.890 204.290 73.840 204.460 ;
        RECT 74.010 204.340 74.480 204.940 ;
        RECT 74.745 204.630 75.075 205.110 ;
        RECT 75.245 204.460 75.570 204.940 ;
        RECT 72.890 204.205 73.060 204.290 ;
        RECT 72.605 203.870 73.060 204.205 ;
        RECT 74.010 204.120 74.185 204.340 ;
        RECT 74.650 204.290 75.570 204.460 ;
        RECT 76.660 204.385 76.950 205.110 ;
        RECT 77.120 204.360 78.330 205.110 ;
        RECT 78.520 204.720 79.695 204.940 ;
        RECT 74.650 204.170 75.000 204.290 ;
        RECT 73.235 203.945 74.185 204.120 ;
        RECT 72.890 203.700 73.060 203.870 ;
        RECT 68.580 202.860 69.465 203.030 ;
        RECT 69.645 202.560 69.960 203.060 ;
        RECT 70.190 202.730 70.530 203.290 ;
        RECT 70.700 202.560 70.870 203.570 ;
        RECT 71.040 202.775 71.370 203.620 ;
        RECT 71.540 202.560 71.710 203.475 ;
        RECT 72.060 202.730 72.620 203.630 ;
        RECT 72.890 203.530 73.840 203.700 ;
        RECT 72.810 202.560 73.420 203.360 ;
        RECT 73.590 202.730 73.840 203.530 ;
        RECT 74.010 203.405 74.185 203.945 ;
        RECT 74.550 203.900 75.000 204.170 ;
        RECT 74.650 203.705 75.000 203.900 ;
        RECT 75.170 203.875 75.570 204.120 ;
        RECT 74.650 203.535 75.570 203.705 ;
        RECT 74.010 202.730 74.460 203.405 ;
        RECT 74.730 202.560 75.055 203.365 ;
        RECT 75.225 202.730 75.570 203.535 ;
        RECT 76.660 202.560 76.950 203.725 ;
        RECT 77.120 203.650 77.640 204.190 ;
        RECT 77.810 203.820 78.330 204.360 ;
        RECT 78.500 204.300 79.275 204.550 ;
        RECT 79.445 204.470 79.695 204.720 ;
        RECT 79.865 204.640 80.035 205.110 ;
        RECT 80.205 204.470 80.535 204.940 ;
        RECT 77.120 202.560 78.330 203.650 ;
        RECT 78.500 203.410 78.730 204.300 ;
        RECT 79.445 204.290 80.535 204.470 ;
        RECT 80.845 204.290 81.015 205.110 ;
        RECT 81.185 204.470 81.515 204.940 ;
        RECT 81.685 204.640 81.855 205.110 ;
        RECT 82.025 204.470 82.390 204.940 ;
        RECT 82.560 204.640 82.730 205.110 ;
        RECT 83.000 204.720 84.310 204.890 ;
        RECT 83.420 204.470 83.750 204.550 ;
        RECT 81.185 204.290 83.750 204.470 ;
        RECT 78.900 203.910 79.375 204.120 ;
        RECT 79.670 203.920 81.120 204.120 ;
        RECT 79.205 203.750 79.375 203.910 ;
        RECT 81.345 203.910 82.370 204.120 ;
        RECT 83.050 203.950 83.710 204.120 ;
        RECT 81.345 203.750 81.515 203.910 ;
        RECT 79.205 203.580 81.515 203.750 ;
        RECT 83.050 203.740 83.220 203.950 ;
        RECT 83.920 203.780 84.310 204.720 ;
        RECT 84.480 204.460 84.805 204.940 ;
        RECT 84.975 204.630 85.305 205.110 ;
        RECT 84.480 204.290 85.400 204.460 ;
        RECT 85.570 204.340 86.040 204.940 ;
        RECT 85.050 204.170 85.400 204.290 ;
        RECT 84.480 203.875 84.880 204.120 ;
        RECT 85.050 203.900 85.500 204.170 ;
        RECT 85.865 204.120 86.040 204.340 ;
        RECT 86.210 204.460 86.460 204.940 ;
        RECT 86.635 204.630 87.240 205.110 ;
        RECT 87.410 204.555 87.990 204.940 ;
        RECT 86.210 204.290 87.160 204.460 ;
        RECT 86.990 204.205 87.160 204.290 ;
        RECT 85.865 203.945 86.815 204.120 ;
        RECT 81.725 203.570 83.220 203.740 ;
        RECT 83.460 203.570 84.310 203.780 ;
        RECT 85.050 203.705 85.400 203.900 ;
        RECT 81.725 203.410 81.895 203.570 ;
        RECT 78.500 203.240 81.895 203.410 ;
        RECT 83.460 203.400 83.710 203.570 ;
        RECT 84.480 203.535 85.400 203.705 ;
        RECT 78.500 203.230 80.495 203.240 ;
        RECT 78.500 202.730 78.815 203.230 ;
        RECT 78.985 202.560 79.235 203.060 ;
        RECT 79.405 202.730 79.655 203.230 ;
        RECT 79.825 202.560 80.075 203.060 ;
        RECT 80.245 202.730 80.495 203.230 ;
        RECT 82.140 203.230 83.710 203.400 ;
        RECT 82.140 203.070 82.350 203.230 ;
        RECT 83.460 203.070 83.710 203.230 ;
        RECT 80.805 202.730 81.055 203.070 ;
        RECT 81.225 202.560 81.475 203.060 ;
        RECT 81.645 202.900 81.970 203.070 ;
        RECT 82.520 202.900 82.770 203.060 ;
        RECT 81.645 202.730 82.770 202.900 ;
        RECT 83.040 202.560 83.290 203.060 ;
        RECT 83.880 202.560 84.310 203.400 ;
        RECT 84.480 202.730 84.825 203.535 ;
        RECT 85.865 203.405 86.040 203.945 ;
        RECT 86.990 203.870 87.445 204.205 ;
        RECT 86.990 203.700 87.160 203.870 ;
        RECT 84.995 202.560 85.320 203.365 ;
        RECT 85.590 202.730 86.040 203.405 ;
        RECT 86.210 203.530 87.160 203.700 ;
        RECT 87.625 203.630 87.990 204.555 ;
        RECT 88.620 204.360 89.830 205.110 ;
        RECT 86.210 202.730 86.460 203.530 ;
        RECT 86.630 202.560 87.240 203.360 ;
        RECT 87.430 202.730 87.990 203.630 ;
        RECT 88.620 203.650 89.140 204.190 ;
        RECT 89.310 203.820 89.830 204.360 ;
        RECT 91.585 203.985 92.965 204.235 ;
        RECT 88.620 202.560 89.830 203.650 ;
        RECT 91.760 202.760 91.930 203.985 ;
        RECT 92.190 202.760 92.360 203.520 ;
        RECT 92.620 202.760 92.790 203.985 ;
        RECT 97.525 203.280 97.695 205.535 ;
        RECT 98.655 203.280 98.825 208.050 ;
        RECT 99.185 207.705 99.355 207.780 ;
        RECT 99.185 203.575 99.515 207.705 ;
        RECT 99.185 203.280 99.355 203.575 ;
        RECT 100.315 203.280 100.485 208.050 ;
        RECT 101.445 203.070 101.615 207.780 ;
        RECT 101.975 207.655 102.145 207.780 ;
        RECT 101.975 204.445 102.175 207.655 ;
        RECT 101.975 204.270 102.145 204.445 ;
        RECT 103.105 204.270 103.275 208.050 ;
        RECT 103.635 204.095 103.805 207.780 ;
        RECT 102.905 204.060 103.805 204.095 ;
        RECT 102.200 203.830 103.805 204.060 ;
        RECT 102.905 203.765 103.805 203.830 ;
        RECT 97.750 202.840 98.600 203.070 ;
        RECT 99.410 202.840 101.615 203.070 ;
        RECT 103.635 202.860 103.805 203.765 ;
        RECT 105.165 203.080 105.335 208.050 ;
        RECT 103.635 202.630 104.975 202.860 ;
        RECT 55.415 202.390 89.915 202.560 ;
        RECT 91.955 202.400 92.870 202.570 ;
        RECT 55.500 201.300 56.710 202.390 ;
        RECT 55.500 200.590 56.020 201.130 ;
        RECT 56.190 200.760 56.710 201.300 ;
        RECT 56.880 201.320 57.440 202.220 ;
        RECT 57.630 201.590 58.240 202.390 ;
        RECT 58.410 201.420 58.660 202.220 ;
        RECT 55.500 199.840 56.710 200.590 ;
        RECT 56.880 200.395 57.245 201.320 ;
        RECT 57.710 201.250 58.660 201.420 ;
        RECT 58.830 201.545 59.280 202.220 ;
        RECT 59.550 201.585 59.875 202.390 ;
        RECT 57.710 201.080 57.880 201.250 ;
        RECT 57.425 200.745 57.880 201.080 ;
        RECT 58.830 201.005 59.005 201.545 ;
        RECT 60.045 201.415 60.390 202.220 ;
        RECT 60.650 201.770 60.820 202.200 ;
        RECT 60.990 201.940 61.320 202.390 ;
        RECT 60.650 201.540 61.330 201.770 ;
        RECT 59.470 201.245 60.390 201.415 ;
        RECT 59.470 201.050 59.820 201.245 ;
        RECT 58.055 200.830 59.005 201.005 ;
        RECT 57.710 200.660 57.880 200.745 ;
        RECT 57.710 200.490 58.660 200.660 ;
        RECT 56.880 200.010 57.460 200.395 ;
        RECT 57.630 199.840 58.235 200.320 ;
        RECT 58.410 200.010 58.660 200.490 ;
        RECT 58.830 200.610 59.005 200.830 ;
        RECT 59.370 200.780 59.820 201.050 ;
        RECT 59.990 200.830 60.390 201.075 ;
        RECT 59.470 200.660 59.820 200.780 ;
        RECT 60.625 200.690 60.925 201.370 ;
        RECT 58.830 200.010 59.300 200.610 ;
        RECT 59.470 200.490 60.390 200.660 ;
        RECT 60.620 200.520 60.925 200.690 ;
        RECT 61.095 200.890 61.330 201.540 ;
        RECT 61.520 201.230 61.805 202.175 ;
        RECT 61.985 201.920 62.670 202.390 ;
        RECT 61.980 201.400 62.675 201.710 ;
        RECT 62.850 201.335 63.155 202.120 ;
        RECT 63.340 201.435 63.610 202.390 ;
        RECT 61.520 201.080 62.380 201.230 ;
        RECT 61.520 201.060 62.810 201.080 ;
        RECT 61.095 200.560 61.650 200.890 ;
        RECT 61.820 200.700 62.810 201.060 ;
        RECT 59.565 199.840 59.895 200.320 ;
        RECT 60.065 200.010 60.390 200.490 ;
        RECT 61.095 200.410 61.310 200.560 ;
        RECT 60.570 199.840 60.900 200.345 ;
        RECT 61.070 200.035 61.310 200.410 ;
        RECT 61.820 200.365 61.990 200.700 ;
        RECT 62.980 200.530 63.155 201.335 ;
        RECT 63.780 201.225 64.070 202.390 ;
        RECT 64.420 201.475 64.590 202.390 ;
        RECT 64.760 201.330 65.090 202.175 ;
        RECT 65.260 201.380 65.430 202.390 ;
        RECT 65.600 201.660 65.940 202.220 ;
        RECT 66.170 201.890 66.485 202.390 ;
        RECT 66.665 201.920 67.550 202.090 ;
        RECT 64.700 201.250 65.090 201.330 ;
        RECT 65.600 201.285 66.495 201.660 ;
        RECT 64.700 201.200 64.915 201.250 ;
        RECT 64.700 200.620 64.870 201.200 ;
        RECT 65.600 201.080 65.790 201.285 ;
        RECT 66.665 201.080 66.835 201.920 ;
        RECT 67.775 201.890 68.025 202.220 ;
        RECT 65.040 200.750 65.790 201.080 ;
        RECT 65.960 200.750 66.835 201.080 ;
        RECT 64.700 200.580 64.925 200.620 ;
        RECT 65.590 200.580 65.790 200.750 ;
        RECT 61.590 200.170 61.990 200.365 ;
        RECT 61.590 200.025 61.760 200.170 ;
        RECT 62.350 199.840 62.750 200.335 ;
        RECT 62.920 200.010 63.155 200.530 ;
        RECT 63.340 199.840 63.610 200.475 ;
        RECT 63.780 199.840 64.070 200.565 ;
        RECT 64.700 200.495 65.080 200.580 ;
        RECT 64.410 199.840 64.580 200.355 ;
        RECT 64.750 200.060 65.080 200.495 ;
        RECT 65.250 199.840 65.420 200.450 ;
        RECT 65.590 200.055 65.920 200.580 ;
        RECT 66.180 199.840 66.390 200.370 ;
        RECT 66.665 200.290 66.835 200.750 ;
        RECT 67.005 200.790 67.325 201.750 ;
        RECT 67.495 201.000 67.685 201.720 ;
        RECT 67.855 200.820 68.025 201.890 ;
        RECT 68.195 201.590 68.365 202.390 ;
        RECT 68.535 201.945 69.640 202.115 ;
        RECT 68.535 201.330 68.705 201.945 ;
        RECT 69.850 201.795 70.100 202.220 ;
        RECT 70.270 201.930 70.535 202.390 ;
        RECT 68.875 201.410 69.405 201.775 ;
        RECT 69.850 201.665 70.155 201.795 ;
        RECT 68.195 201.240 68.705 201.330 ;
        RECT 68.195 201.070 69.065 201.240 ;
        RECT 68.195 201.000 68.365 201.070 ;
        RECT 68.485 200.820 68.685 200.850 ;
        RECT 67.005 200.460 67.470 200.790 ;
        RECT 67.855 200.520 68.685 200.820 ;
        RECT 67.855 200.290 68.025 200.520 ;
        RECT 66.665 200.120 67.450 200.290 ;
        RECT 67.620 200.120 68.025 200.290 ;
        RECT 68.205 199.840 68.575 200.340 ;
        RECT 68.895 200.290 69.065 201.070 ;
        RECT 69.235 200.710 69.405 201.410 ;
        RECT 69.575 200.880 69.815 201.475 ;
        RECT 69.235 200.490 69.760 200.710 ;
        RECT 69.985 200.560 70.155 201.665 ;
        RECT 69.930 200.430 70.155 200.560 ;
        RECT 70.325 200.470 70.605 201.420 ;
        RECT 69.930 200.290 70.100 200.430 ;
        RECT 68.895 200.120 69.570 200.290 ;
        RECT 69.765 200.120 70.100 200.290 ;
        RECT 70.270 199.840 70.520 200.300 ;
        RECT 70.775 200.100 70.960 202.220 ;
        RECT 71.130 201.890 71.460 202.390 ;
        RECT 71.630 201.720 71.800 202.220 ;
        RECT 71.135 201.550 71.800 201.720 ;
        RECT 71.135 200.560 71.365 201.550 ;
        RECT 72.155 201.420 72.325 201.670 ;
        RECT 72.560 201.630 72.890 202.390 ;
        RECT 71.535 200.730 71.885 201.380 ;
        RECT 72.155 201.250 72.840 201.420 ;
        RECT 72.060 200.750 72.500 201.080 ;
        RECT 72.670 201.000 72.840 201.250 ;
        RECT 73.060 201.370 73.230 202.220 ;
        RECT 73.445 201.550 73.695 202.390 ;
        RECT 73.930 202.050 75.010 202.220 ;
        RECT 73.930 201.550 74.210 202.050 ;
        RECT 74.380 201.370 74.625 201.880 ;
        RECT 73.060 201.200 74.625 201.370 ;
        RECT 74.840 201.420 75.010 202.050 ;
        RECT 75.180 201.590 75.510 202.390 ;
        RECT 75.680 201.420 75.955 202.220 ;
        RECT 74.840 201.210 75.955 201.420 ;
        RECT 76.660 201.250 76.920 202.390 ;
        RECT 77.090 201.420 77.420 202.220 ;
        RECT 77.590 201.590 77.760 202.390 ;
        RECT 77.930 201.420 78.260 202.220 ;
        RECT 78.430 201.590 78.685 202.390 ;
        RECT 78.960 201.720 79.275 202.220 ;
        RECT 79.445 201.890 79.695 202.390 ;
        RECT 79.865 201.720 80.115 202.220 ;
        RECT 80.285 201.890 80.535 202.390 ;
        RECT 80.705 201.720 80.955 202.220 ;
        RECT 81.265 201.880 81.515 202.220 ;
        RECT 81.685 201.890 81.935 202.390 ;
        RECT 82.105 202.050 83.230 202.220 ;
        RECT 82.105 201.880 82.430 202.050 ;
        RECT 82.980 201.890 83.230 202.050 ;
        RECT 83.500 201.890 83.750 202.390 ;
        RECT 78.960 201.710 80.955 201.720 ;
        RECT 82.600 201.720 82.810 201.880 ;
        RECT 83.920 201.720 84.170 201.880 ;
        RECT 78.960 201.540 82.355 201.710 ;
        RECT 82.600 201.550 84.170 201.720 ;
        RECT 84.340 201.550 84.770 202.390 ;
        RECT 77.090 201.250 78.790 201.420 ;
        RECT 72.670 200.830 73.310 201.000 ;
        RECT 72.670 200.580 72.840 200.830 ;
        RECT 73.500 200.660 73.755 201.200 ;
        RECT 73.925 200.830 75.065 201.030 ;
        RECT 75.235 200.830 76.030 201.030 ;
        RECT 76.660 200.830 77.420 201.080 ;
        RECT 77.590 200.830 78.340 201.080 ;
        RECT 78.510 200.660 78.790 201.250 ;
        RECT 71.135 200.390 71.800 200.560 ;
        RECT 71.130 199.840 71.460 200.220 ;
        RECT 71.630 200.100 71.800 200.390 ;
        RECT 72.155 199.840 72.325 200.580 ;
        RECT 72.575 200.200 72.840 200.580 ;
        RECT 73.050 200.230 73.330 200.660 ;
        RECT 73.500 200.400 73.830 200.660 ;
        RECT 74.000 200.480 75.955 200.660 ;
        RECT 74.000 200.230 74.250 200.480 ;
        RECT 73.050 200.010 74.250 200.230 ;
        RECT 74.420 199.840 74.590 200.310 ;
        RECT 74.760 200.010 75.090 200.480 ;
        RECT 75.260 199.840 75.430 200.310 ;
        RECT 75.600 200.020 75.955 200.480 ;
        RECT 76.660 200.470 77.760 200.640 ;
        RECT 76.660 200.010 77.000 200.470 ;
        RECT 77.170 199.840 77.340 200.300 ;
        RECT 77.510 200.220 77.760 200.470 ;
        RECT 77.930 200.410 78.790 200.660 ;
        RECT 78.960 200.650 79.190 201.540 ;
        RECT 82.185 201.380 82.355 201.540 ;
        RECT 83.920 201.380 84.170 201.550 ;
        RECT 84.940 201.415 85.285 202.220 ;
        RECT 85.455 201.585 85.780 202.390 ;
        RECT 86.050 201.545 86.500 202.220 ;
        RECT 79.665 201.200 81.975 201.370 ;
        RECT 82.185 201.210 83.680 201.380 ;
        RECT 79.665 201.040 79.835 201.200 ;
        RECT 79.360 200.830 79.835 201.040 ;
        RECT 81.805 201.040 81.975 201.200 ;
        RECT 80.130 200.830 81.580 201.030 ;
        RECT 81.805 200.830 82.830 201.040 ;
        RECT 83.510 201.000 83.680 201.210 ;
        RECT 83.920 201.170 84.770 201.380 ;
        RECT 84.940 201.245 85.860 201.415 ;
        RECT 83.510 200.830 84.170 201.000 ;
        RECT 78.960 200.400 79.735 200.650 ;
        RECT 79.905 200.480 80.995 200.660 ;
        RECT 78.350 200.220 78.680 200.240 ;
        RECT 79.905 200.230 80.155 200.480 ;
        RECT 77.510 200.010 78.680 200.220 ;
        RECT 78.980 200.010 80.155 200.230 ;
        RECT 80.325 199.840 80.495 200.310 ;
        RECT 80.665 200.010 80.995 200.480 ;
        RECT 81.305 199.840 81.475 200.660 ;
        RECT 81.645 200.480 84.210 200.660 ;
        RECT 81.645 200.010 81.975 200.480 ;
        RECT 82.145 199.840 82.315 200.310 ;
        RECT 82.485 200.010 82.850 200.480 ;
        RECT 83.880 200.400 84.210 200.480 ;
        RECT 83.020 199.840 83.190 200.310 ;
        RECT 84.380 200.230 84.770 201.170 ;
        RECT 84.940 200.830 85.340 201.075 ;
        RECT 85.510 201.050 85.860 201.245 ;
        RECT 85.510 200.780 85.960 201.050 ;
        RECT 86.325 201.005 86.500 201.545 ;
        RECT 86.670 201.420 86.920 202.220 ;
        RECT 87.090 201.590 87.700 202.390 ;
        RECT 86.670 201.250 87.620 201.420 ;
        RECT 87.890 201.320 88.450 202.220 ;
        RECT 87.450 201.080 87.620 201.250 ;
        RECT 86.325 200.830 87.275 201.005 ;
        RECT 85.510 200.660 85.860 200.780 ;
        RECT 83.460 200.060 84.770 200.230 ;
        RECT 84.940 200.490 85.860 200.660 ;
        RECT 86.325 200.610 86.500 200.830 ;
        RECT 87.450 200.745 87.905 201.080 ;
        RECT 87.450 200.660 87.620 200.745 ;
        RECT 84.940 200.010 85.265 200.490 ;
        RECT 85.435 199.840 85.765 200.320 ;
        RECT 86.030 200.010 86.500 200.610 ;
        RECT 86.670 200.490 87.620 200.660 ;
        RECT 86.670 200.010 86.920 200.490 ;
        RECT 88.085 200.395 88.450 201.320 ;
        RECT 88.620 201.300 89.830 202.390 ;
        RECT 93.590 202.070 102.810 202.300 ;
        RECT 88.620 200.760 89.140 201.300 ;
        RECT 89.310 200.590 89.830 201.130 ;
        RECT 87.095 199.840 87.700 200.320 ;
        RECT 87.870 200.010 88.450 200.395 ;
        RECT 88.620 199.840 89.830 200.590 ;
        RECT 91.760 200.095 91.930 201.690 ;
        RECT 92.190 200.560 92.360 201.690 ;
        RECT 92.620 200.095 92.790 201.690 ;
        RECT 93.365 200.775 93.535 201.860 ;
        RECT 91.585 199.845 92.965 200.095 ;
        RECT 55.415 199.670 89.915 199.840 ;
        RECT 55.500 198.920 56.710 199.670 ;
        RECT 56.880 199.115 57.460 199.500 ;
        RECT 57.630 199.190 58.235 199.670 ;
        RECT 55.500 198.380 56.020 198.920 ;
        RECT 56.190 198.210 56.710 198.750 ;
        RECT 55.500 197.120 56.710 198.210 ;
        RECT 56.880 198.190 57.245 199.115 ;
        RECT 58.410 199.020 58.660 199.500 ;
        RECT 57.710 198.850 58.660 199.020 ;
        RECT 58.830 198.900 59.300 199.500 ;
        RECT 59.565 199.190 59.895 199.670 ;
        RECT 60.065 199.020 60.390 199.500 ;
        RECT 60.730 199.155 60.900 199.670 ;
        RECT 57.710 198.765 57.880 198.850 ;
        RECT 57.425 198.430 57.880 198.765 ;
        RECT 58.830 198.680 59.005 198.900 ;
        RECT 59.470 198.850 60.390 199.020 ;
        RECT 61.070 199.015 61.400 199.450 ;
        RECT 61.570 199.060 61.740 199.670 ;
        RECT 61.020 198.930 61.400 199.015 ;
        RECT 61.910 198.930 62.240 199.455 ;
        RECT 62.500 199.140 62.710 199.670 ;
        RECT 62.985 199.220 63.770 199.390 ;
        RECT 63.940 199.220 64.345 199.390 ;
        RECT 61.020 198.890 61.245 198.930 ;
        RECT 59.470 198.730 59.820 198.850 ;
        RECT 58.055 198.505 59.005 198.680 ;
        RECT 57.710 198.260 57.880 198.430 ;
        RECT 56.880 197.290 57.440 198.190 ;
        RECT 57.710 198.090 58.660 198.260 ;
        RECT 57.630 197.120 58.240 197.920 ;
        RECT 58.410 197.290 58.660 198.090 ;
        RECT 58.830 197.965 59.005 198.505 ;
        RECT 59.370 198.460 59.820 198.730 ;
        RECT 59.470 198.265 59.820 198.460 ;
        RECT 59.990 198.435 60.390 198.680 ;
        RECT 61.020 198.310 61.190 198.890 ;
        RECT 61.910 198.760 62.110 198.930 ;
        RECT 62.985 198.760 63.155 199.220 ;
        RECT 61.360 198.430 62.110 198.760 ;
        RECT 62.280 198.430 63.155 198.760 ;
        RECT 59.470 198.095 60.390 198.265 ;
        RECT 61.020 198.260 61.235 198.310 ;
        RECT 61.020 198.180 61.410 198.260 ;
        RECT 58.830 197.290 59.280 197.965 ;
        RECT 59.550 197.120 59.875 197.925 ;
        RECT 60.045 197.290 60.390 198.095 ;
        RECT 60.740 197.120 60.910 198.035 ;
        RECT 61.080 197.335 61.410 198.180 ;
        RECT 61.920 198.225 62.110 198.430 ;
        RECT 61.580 197.120 61.750 198.130 ;
        RECT 61.920 197.850 62.815 198.225 ;
        RECT 61.920 197.290 62.260 197.850 ;
        RECT 62.490 197.120 62.805 197.620 ;
        RECT 62.985 197.590 63.155 198.430 ;
        RECT 63.325 198.720 63.790 199.050 ;
        RECT 64.175 198.990 64.345 199.220 ;
        RECT 64.525 199.170 64.895 199.670 ;
        RECT 65.215 199.220 65.890 199.390 ;
        RECT 66.085 199.220 66.420 199.390 ;
        RECT 63.325 197.760 63.645 198.720 ;
        RECT 64.175 198.690 65.005 198.990 ;
        RECT 63.815 197.790 64.005 198.510 ;
        RECT 64.175 197.620 64.345 198.690 ;
        RECT 64.805 198.660 65.005 198.690 ;
        RECT 64.515 198.440 64.685 198.510 ;
        RECT 65.215 198.440 65.385 199.220 ;
        RECT 66.250 199.080 66.420 199.220 ;
        RECT 66.590 199.210 66.840 199.670 ;
        RECT 64.515 198.270 65.385 198.440 ;
        RECT 65.555 198.800 66.080 199.020 ;
        RECT 66.250 198.950 66.475 199.080 ;
        RECT 64.515 198.180 65.025 198.270 ;
        RECT 62.985 197.420 63.870 197.590 ;
        RECT 64.095 197.290 64.345 197.620 ;
        RECT 64.515 197.120 64.685 197.920 ;
        RECT 64.855 197.565 65.025 198.180 ;
        RECT 65.555 198.100 65.725 198.800 ;
        RECT 65.195 197.735 65.725 198.100 ;
        RECT 65.895 198.035 66.135 198.630 ;
        RECT 66.305 197.845 66.475 198.950 ;
        RECT 66.645 198.090 66.925 199.040 ;
        RECT 66.170 197.715 66.475 197.845 ;
        RECT 64.855 197.395 65.960 197.565 ;
        RECT 66.170 197.290 66.420 197.715 ;
        RECT 66.590 197.120 66.855 197.580 ;
        RECT 67.095 197.290 67.280 199.410 ;
        RECT 67.450 199.290 67.780 199.670 ;
        RECT 67.950 199.120 68.120 199.410 ;
        RECT 68.550 199.155 68.720 199.670 ;
        RECT 67.455 198.950 68.120 199.120 ;
        RECT 68.890 199.015 69.220 199.450 ;
        RECT 69.390 199.060 69.560 199.670 ;
        RECT 67.455 197.960 67.685 198.950 ;
        RECT 68.840 198.930 69.220 199.015 ;
        RECT 69.730 198.930 70.060 199.455 ;
        RECT 70.320 199.140 70.530 199.670 ;
        RECT 70.805 199.220 71.590 199.390 ;
        RECT 71.760 199.220 72.165 199.390 ;
        RECT 68.840 198.890 69.065 198.930 ;
        RECT 67.855 198.130 68.205 198.780 ;
        RECT 68.840 198.310 69.010 198.890 ;
        RECT 69.730 198.760 69.930 198.930 ;
        RECT 70.805 198.760 70.975 199.220 ;
        RECT 69.180 198.430 69.930 198.760 ;
        RECT 70.100 198.430 70.975 198.760 ;
        RECT 68.840 198.260 69.055 198.310 ;
        RECT 68.840 198.180 69.230 198.260 ;
        RECT 67.455 197.790 68.120 197.960 ;
        RECT 67.450 197.120 67.780 197.620 ;
        RECT 67.950 197.290 68.120 197.790 ;
        RECT 68.560 197.120 68.730 198.035 ;
        RECT 68.900 197.335 69.230 198.180 ;
        RECT 69.740 198.225 69.930 198.430 ;
        RECT 69.400 197.120 69.570 198.130 ;
        RECT 69.740 197.850 70.635 198.225 ;
        RECT 69.740 197.290 70.080 197.850 ;
        RECT 70.310 197.120 70.625 197.620 ;
        RECT 70.805 197.590 70.975 198.430 ;
        RECT 71.145 198.720 71.610 199.050 ;
        RECT 71.995 198.990 72.165 199.220 ;
        RECT 72.345 199.170 72.715 199.670 ;
        RECT 73.035 199.220 73.710 199.390 ;
        RECT 73.905 199.220 74.240 199.390 ;
        RECT 71.145 197.760 71.465 198.720 ;
        RECT 71.995 198.690 72.825 198.990 ;
        RECT 71.635 197.790 71.825 198.510 ;
        RECT 71.995 197.620 72.165 198.690 ;
        RECT 72.625 198.660 72.825 198.690 ;
        RECT 72.335 198.440 72.505 198.510 ;
        RECT 73.035 198.440 73.205 199.220 ;
        RECT 74.070 199.080 74.240 199.220 ;
        RECT 74.410 199.210 74.660 199.670 ;
        RECT 72.335 198.270 73.205 198.440 ;
        RECT 73.375 198.800 73.900 199.020 ;
        RECT 74.070 198.950 74.295 199.080 ;
        RECT 72.335 198.180 72.845 198.270 ;
        RECT 70.805 197.420 71.690 197.590 ;
        RECT 71.915 197.290 72.165 197.620 ;
        RECT 72.335 197.120 72.505 197.920 ;
        RECT 72.675 197.565 72.845 198.180 ;
        RECT 73.375 198.100 73.545 198.800 ;
        RECT 73.015 197.735 73.545 198.100 ;
        RECT 73.715 198.035 73.955 198.630 ;
        RECT 74.125 197.845 74.295 198.950 ;
        RECT 74.465 198.090 74.745 199.040 ;
        RECT 73.990 197.715 74.295 197.845 ;
        RECT 72.675 197.395 73.780 197.565 ;
        RECT 73.990 197.290 74.240 197.715 ;
        RECT 74.410 197.120 74.675 197.580 ;
        RECT 74.915 197.290 75.100 199.410 ;
        RECT 75.270 199.290 75.600 199.670 ;
        RECT 75.770 199.120 75.940 199.410 ;
        RECT 75.275 198.950 75.940 199.120 ;
        RECT 75.275 197.960 75.505 198.950 ;
        RECT 76.660 198.945 76.950 199.670 ;
        RECT 77.290 199.155 77.460 199.670 ;
        RECT 77.630 199.015 77.960 199.450 ;
        RECT 78.130 199.060 78.300 199.670 ;
        RECT 77.580 198.930 77.960 199.015 ;
        RECT 78.470 198.930 78.800 199.455 ;
        RECT 79.060 199.140 79.270 199.670 ;
        RECT 79.545 199.220 80.330 199.390 ;
        RECT 80.500 199.220 80.905 199.390 ;
        RECT 77.580 198.890 77.805 198.930 ;
        RECT 75.675 198.130 76.025 198.780 ;
        RECT 77.580 198.310 77.750 198.890 ;
        RECT 78.470 198.760 78.670 198.930 ;
        RECT 79.545 198.760 79.715 199.220 ;
        RECT 77.920 198.430 78.670 198.760 ;
        RECT 78.840 198.430 79.715 198.760 ;
        RECT 75.275 197.790 75.940 197.960 ;
        RECT 75.270 197.120 75.600 197.620 ;
        RECT 75.770 197.290 75.940 197.790 ;
        RECT 76.660 197.120 76.950 198.285 ;
        RECT 77.580 198.260 77.795 198.310 ;
        RECT 77.580 198.180 77.970 198.260 ;
        RECT 77.300 197.120 77.470 198.035 ;
        RECT 77.640 197.335 77.970 198.180 ;
        RECT 78.480 198.225 78.670 198.430 ;
        RECT 78.140 197.120 78.310 198.130 ;
        RECT 78.480 197.850 79.375 198.225 ;
        RECT 78.480 197.290 78.820 197.850 ;
        RECT 79.050 197.120 79.365 197.620 ;
        RECT 79.545 197.590 79.715 198.430 ;
        RECT 79.885 198.720 80.350 199.050 ;
        RECT 80.735 198.990 80.905 199.220 ;
        RECT 81.085 199.170 81.455 199.670 ;
        RECT 81.775 199.220 82.450 199.390 ;
        RECT 82.645 199.220 82.980 199.390 ;
        RECT 79.885 197.760 80.205 198.720 ;
        RECT 80.735 198.690 81.565 198.990 ;
        RECT 80.375 197.790 80.565 198.510 ;
        RECT 80.735 197.620 80.905 198.690 ;
        RECT 81.365 198.660 81.565 198.690 ;
        RECT 81.075 198.440 81.245 198.510 ;
        RECT 81.775 198.440 81.945 199.220 ;
        RECT 82.810 199.080 82.980 199.220 ;
        RECT 83.150 199.210 83.400 199.670 ;
        RECT 81.075 198.270 81.945 198.440 ;
        RECT 82.115 198.800 82.640 199.020 ;
        RECT 82.810 198.950 83.035 199.080 ;
        RECT 81.075 198.180 81.585 198.270 ;
        RECT 79.545 197.420 80.430 197.590 ;
        RECT 80.655 197.290 80.905 197.620 ;
        RECT 81.075 197.120 81.245 197.920 ;
        RECT 81.415 197.565 81.585 198.180 ;
        RECT 82.115 198.100 82.285 198.800 ;
        RECT 81.755 197.735 82.285 198.100 ;
        RECT 82.455 198.035 82.695 198.630 ;
        RECT 82.865 197.845 83.035 198.950 ;
        RECT 83.205 198.090 83.485 199.040 ;
        RECT 82.730 197.715 83.035 197.845 ;
        RECT 81.415 197.395 82.520 197.565 ;
        RECT 82.730 197.290 82.980 197.715 ;
        RECT 83.150 197.120 83.415 197.580 ;
        RECT 83.655 197.290 83.840 199.410 ;
        RECT 84.010 199.290 84.340 199.670 ;
        RECT 84.510 199.120 84.680 199.410 ;
        RECT 84.015 198.950 84.680 199.120 ;
        RECT 84.940 199.020 85.265 199.500 ;
        RECT 85.435 199.190 85.765 199.670 ;
        RECT 84.015 197.960 84.245 198.950 ;
        RECT 84.940 198.850 85.860 199.020 ;
        RECT 86.030 198.900 86.500 199.500 ;
        RECT 84.415 198.130 84.765 198.780 ;
        RECT 85.510 198.730 85.860 198.850 ;
        RECT 84.940 198.435 85.340 198.680 ;
        RECT 85.510 198.460 85.960 198.730 ;
        RECT 86.325 198.680 86.500 198.900 ;
        RECT 86.670 199.020 86.920 199.500 ;
        RECT 87.095 199.190 87.700 199.670 ;
        RECT 87.870 199.115 88.450 199.500 ;
        RECT 86.670 198.850 87.620 199.020 ;
        RECT 87.450 198.765 87.620 198.850 ;
        RECT 86.325 198.505 87.275 198.680 ;
        RECT 85.510 198.265 85.860 198.460 ;
        RECT 84.940 198.095 85.860 198.265 ;
        RECT 84.015 197.790 84.680 197.960 ;
        RECT 84.010 197.120 84.340 197.620 ;
        RECT 84.510 197.290 84.680 197.790 ;
        RECT 84.940 197.290 85.285 198.095 ;
        RECT 86.325 197.965 86.500 198.505 ;
        RECT 87.450 198.430 87.905 198.765 ;
        RECT 87.450 198.260 87.620 198.430 ;
        RECT 85.455 197.120 85.780 197.925 ;
        RECT 86.050 197.290 86.500 197.965 ;
        RECT 86.670 198.090 87.620 198.260 ;
        RECT 88.085 198.190 88.450 199.115 ;
        RECT 88.620 198.920 89.830 199.670 ;
        RECT 86.670 197.290 86.920 198.090 ;
        RECT 87.090 197.120 87.700 197.920 ;
        RECT 87.890 197.290 88.450 198.190 ;
        RECT 88.620 198.210 89.140 198.750 ;
        RECT 89.310 198.380 89.830 198.920 ;
        RECT 88.620 197.120 89.830 198.210 ;
        RECT 55.415 196.950 89.915 197.120 ;
        RECT 55.500 195.860 56.710 196.950 ;
        RECT 55.500 195.150 56.020 195.690 ;
        RECT 56.190 195.320 56.710 195.860 ;
        RECT 57.800 196.280 58.115 196.780 ;
        RECT 58.285 196.450 58.535 196.950 ;
        RECT 58.705 196.280 58.955 196.780 ;
        RECT 59.125 196.450 59.375 196.950 ;
        RECT 59.545 196.280 59.795 196.780 ;
        RECT 60.105 196.440 60.355 196.780 ;
        RECT 60.525 196.450 60.775 196.950 ;
        RECT 60.945 196.610 62.070 196.780 ;
        RECT 60.945 196.440 61.270 196.610 ;
        RECT 61.820 196.450 62.070 196.610 ;
        RECT 62.340 196.450 62.590 196.950 ;
        RECT 57.800 196.270 59.795 196.280 ;
        RECT 61.440 196.280 61.650 196.440 ;
        RECT 62.760 196.280 63.010 196.440 ;
        RECT 57.800 196.100 61.195 196.270 ;
        RECT 61.440 196.110 63.010 196.280 ;
        RECT 63.180 196.110 63.610 196.950 ;
        RECT 57.800 195.210 58.030 196.100 ;
        RECT 61.025 195.940 61.195 196.100 ;
        RECT 62.760 195.940 63.010 196.110 ;
        RECT 58.505 195.760 60.815 195.930 ;
        RECT 61.025 195.770 62.520 195.940 ;
        RECT 58.505 195.600 58.675 195.760 ;
        RECT 58.200 195.390 58.675 195.600 ;
        RECT 60.645 195.600 60.815 195.760 ;
        RECT 58.970 195.390 60.420 195.590 ;
        RECT 60.645 195.390 61.670 195.600 ;
        RECT 62.350 195.560 62.520 195.770 ;
        RECT 62.760 195.730 63.610 195.940 ;
        RECT 63.780 195.785 64.070 196.950 ;
        RECT 64.330 196.280 64.500 196.780 ;
        RECT 64.670 196.450 65.000 196.950 ;
        RECT 64.330 196.110 64.995 196.280 ;
        RECT 62.350 195.390 63.010 195.560 ;
        RECT 55.500 194.400 56.710 195.150 ;
        RECT 57.800 194.960 58.575 195.210 ;
        RECT 58.745 195.040 59.835 195.220 ;
        RECT 58.745 194.790 58.995 195.040 ;
        RECT 57.820 194.570 58.995 194.790 ;
        RECT 59.165 194.400 59.335 194.870 ;
        RECT 59.505 194.570 59.835 195.040 ;
        RECT 60.145 194.400 60.315 195.220 ;
        RECT 60.485 195.040 63.050 195.220 ;
        RECT 60.485 194.570 60.815 195.040 ;
        RECT 60.985 194.400 61.155 194.870 ;
        RECT 61.325 194.570 61.690 195.040 ;
        RECT 62.720 194.960 63.050 195.040 ;
        RECT 61.860 194.400 62.030 194.870 ;
        RECT 63.220 194.790 63.610 195.730 ;
        RECT 64.245 195.290 64.595 195.940 ;
        RECT 62.300 194.620 63.610 194.790 ;
        RECT 63.780 194.400 64.070 195.125 ;
        RECT 64.765 195.120 64.995 196.110 ;
        RECT 64.330 194.950 64.995 195.120 ;
        RECT 64.330 194.660 64.500 194.950 ;
        RECT 64.670 194.400 65.000 194.780 ;
        RECT 65.170 194.660 65.355 196.780 ;
        RECT 65.595 196.490 65.860 196.950 ;
        RECT 66.030 196.355 66.280 196.780 ;
        RECT 66.490 196.505 67.595 196.675 ;
        RECT 65.975 196.225 66.280 196.355 ;
        RECT 65.525 195.030 65.805 195.980 ;
        RECT 65.975 195.120 66.145 196.225 ;
        RECT 66.315 195.440 66.555 196.035 ;
        RECT 66.725 195.970 67.255 196.335 ;
        RECT 66.725 195.270 66.895 195.970 ;
        RECT 67.425 195.890 67.595 196.505 ;
        RECT 67.765 196.150 67.935 196.950 ;
        RECT 68.105 196.450 68.355 196.780 ;
        RECT 68.580 196.480 69.465 196.650 ;
        RECT 67.425 195.800 67.935 195.890 ;
        RECT 65.975 194.990 66.200 195.120 ;
        RECT 66.370 195.050 66.895 195.270 ;
        RECT 67.065 195.630 67.935 195.800 ;
        RECT 65.610 194.400 65.860 194.860 ;
        RECT 66.030 194.850 66.200 194.990 ;
        RECT 67.065 194.850 67.235 195.630 ;
        RECT 67.765 195.560 67.935 195.630 ;
        RECT 67.445 195.380 67.645 195.410 ;
        RECT 68.105 195.380 68.275 196.450 ;
        RECT 68.445 195.560 68.635 196.280 ;
        RECT 67.445 195.080 68.275 195.380 ;
        RECT 68.805 195.350 69.125 196.310 ;
        RECT 66.030 194.680 66.365 194.850 ;
        RECT 66.560 194.680 67.235 194.850 ;
        RECT 67.555 194.400 67.925 194.900 ;
        RECT 68.105 194.850 68.275 195.080 ;
        RECT 68.660 195.020 69.125 195.350 ;
        RECT 69.295 195.640 69.465 196.480 ;
        RECT 69.645 196.450 69.960 196.950 ;
        RECT 70.190 196.220 70.530 196.780 ;
        RECT 69.635 195.845 70.530 196.220 ;
        RECT 70.700 195.940 70.870 196.950 ;
        RECT 70.340 195.640 70.530 195.845 ;
        RECT 71.040 195.890 71.370 196.735 ;
        RECT 71.540 196.035 71.710 196.950 ;
        RECT 71.040 195.810 71.430 195.890 ;
        RECT 71.215 195.760 71.430 195.810 ;
        RECT 69.295 195.310 70.170 195.640 ;
        RECT 70.340 195.310 71.090 195.640 ;
        RECT 69.295 194.850 69.465 195.310 ;
        RECT 70.340 195.140 70.540 195.310 ;
        RECT 71.260 195.180 71.430 195.760 ;
        RECT 72.060 195.860 73.270 196.950 ;
        RECT 73.620 196.035 73.790 196.950 ;
        RECT 73.960 195.890 74.290 196.735 ;
        RECT 74.460 195.940 74.630 196.950 ;
        RECT 74.800 196.220 75.140 196.780 ;
        RECT 75.370 196.450 75.685 196.950 ;
        RECT 75.865 196.480 76.750 196.650 ;
        RECT 72.060 195.320 72.580 195.860 ;
        RECT 73.900 195.810 74.290 195.890 ;
        RECT 74.800 195.845 75.695 196.220 ;
        RECT 73.900 195.760 74.115 195.810 ;
        RECT 71.205 195.140 71.430 195.180 ;
        RECT 72.750 195.150 73.270 195.690 ;
        RECT 68.105 194.680 68.510 194.850 ;
        RECT 68.680 194.680 69.465 194.850 ;
        RECT 69.740 194.400 69.950 194.930 ;
        RECT 70.210 194.615 70.540 195.140 ;
        RECT 71.050 195.055 71.430 195.140 ;
        RECT 70.710 194.400 70.880 195.010 ;
        RECT 71.050 194.620 71.380 195.055 ;
        RECT 71.550 194.400 71.720 194.915 ;
        RECT 72.060 194.400 73.270 195.150 ;
        RECT 73.900 195.180 74.070 195.760 ;
        RECT 74.800 195.640 74.990 195.845 ;
        RECT 75.865 195.640 76.035 196.480 ;
        RECT 76.975 196.450 77.225 196.780 ;
        RECT 74.240 195.310 74.990 195.640 ;
        RECT 75.160 195.310 76.035 195.640 ;
        RECT 73.900 195.140 74.125 195.180 ;
        RECT 74.790 195.140 74.990 195.310 ;
        RECT 73.900 195.055 74.280 195.140 ;
        RECT 73.610 194.400 73.780 194.915 ;
        RECT 73.950 194.620 74.280 195.055 ;
        RECT 74.450 194.400 74.620 195.010 ;
        RECT 74.790 194.615 75.120 195.140 ;
        RECT 75.380 194.400 75.590 194.930 ;
        RECT 75.865 194.850 76.035 195.310 ;
        RECT 76.205 195.350 76.525 196.310 ;
        RECT 76.695 195.560 76.885 196.280 ;
        RECT 77.055 195.380 77.225 196.450 ;
        RECT 77.395 196.150 77.565 196.950 ;
        RECT 77.735 196.505 78.840 196.675 ;
        RECT 77.735 195.890 77.905 196.505 ;
        RECT 79.050 196.355 79.300 196.780 ;
        RECT 79.470 196.490 79.735 196.950 ;
        RECT 78.075 195.970 78.605 196.335 ;
        RECT 79.050 196.225 79.355 196.355 ;
        RECT 77.395 195.800 77.905 195.890 ;
        RECT 77.395 195.630 78.265 195.800 ;
        RECT 77.395 195.560 77.565 195.630 ;
        RECT 77.685 195.380 77.885 195.410 ;
        RECT 76.205 195.020 76.670 195.350 ;
        RECT 77.055 195.080 77.885 195.380 ;
        RECT 77.055 194.850 77.225 195.080 ;
        RECT 75.865 194.680 76.650 194.850 ;
        RECT 76.820 194.680 77.225 194.850 ;
        RECT 77.405 194.400 77.775 194.900 ;
        RECT 78.095 194.850 78.265 195.630 ;
        RECT 78.435 195.270 78.605 195.970 ;
        RECT 78.775 195.440 79.015 196.035 ;
        RECT 78.435 195.050 78.960 195.270 ;
        RECT 79.185 195.120 79.355 196.225 ;
        RECT 79.130 194.990 79.355 195.120 ;
        RECT 79.525 195.030 79.805 195.980 ;
        RECT 79.130 194.850 79.300 194.990 ;
        RECT 78.095 194.680 78.770 194.850 ;
        RECT 78.965 194.680 79.300 194.850 ;
        RECT 79.470 194.400 79.720 194.860 ;
        RECT 79.975 194.660 80.160 196.780 ;
        RECT 80.330 196.450 80.660 196.950 ;
        RECT 80.830 196.280 81.000 196.780 ;
        RECT 80.335 196.110 81.000 196.280 ;
        RECT 80.335 195.120 80.565 196.110 ;
        RECT 81.260 195.980 81.550 196.780 ;
        RECT 81.720 196.150 81.955 196.950 ;
        RECT 82.140 196.610 83.675 196.780 ;
        RECT 82.140 195.980 82.470 196.610 ;
        RECT 80.735 195.290 81.085 195.940 ;
        RECT 81.260 195.810 82.470 195.980 ;
        RECT 81.260 195.310 81.505 195.640 ;
        RECT 81.675 195.140 81.845 195.810 ;
        RECT 82.640 195.640 82.875 196.385 ;
        RECT 82.015 195.310 82.415 195.640 ;
        RECT 82.585 195.310 82.875 195.640 ;
        RECT 83.065 195.640 83.335 196.385 ;
        RECT 83.505 195.980 83.675 196.610 ;
        RECT 83.845 196.150 84.240 196.950 ;
        RECT 83.505 195.810 84.240 195.980 ;
        RECT 83.065 195.310 83.395 195.640 ;
        RECT 83.565 195.310 83.900 195.640 ;
        RECT 84.070 195.310 84.240 195.810 ;
        RECT 84.410 195.630 84.765 196.780 ;
        RECT 84.935 195.800 85.230 196.950 ;
        RECT 85.425 195.980 85.725 196.175 ;
        RECT 85.895 196.150 86.150 196.950 ;
        RECT 86.350 196.320 86.680 196.780 ;
        RECT 86.850 196.490 87.425 196.950 ;
        RECT 87.595 196.320 87.950 196.780 ;
        RECT 86.350 196.150 87.950 196.320 ;
        RECT 86.840 196.100 87.125 196.150 ;
        RECT 85.425 195.810 86.675 195.980 ;
        RECT 84.410 195.370 85.230 195.630 ;
        RECT 84.410 195.310 84.765 195.370 ;
        RECT 80.335 194.950 81.000 195.120 ;
        RECT 80.330 194.400 80.660 194.780 ;
        RECT 80.830 194.660 81.000 194.950 ;
        RECT 81.260 194.570 81.845 195.140 ;
        RECT 82.095 194.970 83.480 195.140 ;
        RECT 82.095 194.625 82.425 194.970 ;
        RECT 82.640 194.400 83.015 194.800 ;
        RECT 83.195 194.625 83.480 194.970 ;
        RECT 83.650 194.400 84.320 195.140 ;
        RECT 84.490 194.570 84.765 195.310 ;
        RECT 84.935 194.400 85.230 195.200 ;
        RECT 85.425 195.155 85.595 195.810 ;
        RECT 85.770 195.310 86.115 195.640 ;
        RECT 86.345 195.390 86.675 195.810 ;
        RECT 86.845 195.220 87.125 196.100 ;
        RECT 87.305 195.590 87.495 195.970 ;
        RECT 87.675 195.810 87.950 196.150 ;
        RECT 88.120 195.810 88.450 196.950 ;
        RECT 88.620 195.860 89.830 196.950 ;
        RECT 87.300 195.420 88.450 195.590 ;
        RECT 87.305 195.390 88.450 195.420 ;
        RECT 88.620 195.320 89.140 195.860 ;
        RECT 85.425 194.825 85.660 195.155 ;
        RECT 85.830 194.400 86.160 195.140 ;
        RECT 86.395 194.780 86.670 195.220 ;
        RECT 86.845 195.120 87.170 195.220 ;
        RECT 86.840 194.950 87.170 195.120 ;
        RECT 87.340 195.010 88.450 195.220 ;
        RECT 89.310 195.150 89.830 195.690 ;
        RECT 87.340 194.780 87.590 195.010 ;
        RECT 86.395 194.570 87.590 194.780 ;
        RECT 87.760 194.400 87.930 194.840 ;
        RECT 88.100 194.570 88.450 195.010 ;
        RECT 88.620 194.400 89.830 195.150 ;
        RECT 55.415 194.230 89.915 194.400 ;
        RECT 55.500 193.480 56.710 194.230 ;
        RECT 57.510 193.715 57.680 194.230 ;
        RECT 57.850 193.575 58.180 194.010 ;
        RECT 58.350 193.620 58.520 194.230 ;
        RECT 57.800 193.490 58.180 193.575 ;
        RECT 58.690 193.490 59.020 194.015 ;
        RECT 59.280 193.700 59.490 194.230 ;
        RECT 59.765 193.780 60.550 193.950 ;
        RECT 60.720 193.780 61.125 193.950 ;
        RECT 55.500 192.940 56.020 193.480 ;
        RECT 57.800 193.450 58.025 193.490 ;
        RECT 56.190 192.770 56.710 193.310 ;
        RECT 55.500 191.680 56.710 192.770 ;
        RECT 57.800 192.870 57.970 193.450 ;
        RECT 58.690 193.320 58.890 193.490 ;
        RECT 59.765 193.320 59.935 193.780 ;
        RECT 58.140 192.990 58.890 193.320 ;
        RECT 59.060 192.990 59.935 193.320 ;
        RECT 57.800 192.820 58.015 192.870 ;
        RECT 57.800 192.740 58.190 192.820 ;
        RECT 57.520 191.680 57.690 192.595 ;
        RECT 57.860 191.895 58.190 192.740 ;
        RECT 58.700 192.785 58.890 192.990 ;
        RECT 58.360 191.680 58.530 192.690 ;
        RECT 58.700 192.410 59.595 192.785 ;
        RECT 58.700 191.850 59.040 192.410 ;
        RECT 59.270 191.680 59.585 192.180 ;
        RECT 59.765 192.150 59.935 192.990 ;
        RECT 60.105 193.280 60.570 193.610 ;
        RECT 60.955 193.550 61.125 193.780 ;
        RECT 61.305 193.730 61.675 194.230 ;
        RECT 61.995 193.780 62.670 193.950 ;
        RECT 62.865 193.780 63.200 193.950 ;
        RECT 60.105 192.320 60.425 193.280 ;
        RECT 60.955 193.250 61.785 193.550 ;
        RECT 60.595 192.350 60.785 193.070 ;
        RECT 60.955 192.180 61.125 193.250 ;
        RECT 61.585 193.220 61.785 193.250 ;
        RECT 61.295 193.000 61.465 193.070 ;
        RECT 61.995 193.000 62.165 193.780 ;
        RECT 63.030 193.640 63.200 193.780 ;
        RECT 63.370 193.770 63.620 194.230 ;
        RECT 61.295 192.830 62.165 193.000 ;
        RECT 62.335 193.360 62.860 193.580 ;
        RECT 63.030 193.510 63.255 193.640 ;
        RECT 61.295 192.740 61.805 192.830 ;
        RECT 59.765 191.980 60.650 192.150 ;
        RECT 60.875 191.850 61.125 192.180 ;
        RECT 61.295 191.680 61.465 192.480 ;
        RECT 61.635 192.125 61.805 192.740 ;
        RECT 62.335 192.660 62.505 193.360 ;
        RECT 61.975 192.295 62.505 192.660 ;
        RECT 62.675 192.595 62.915 193.190 ;
        RECT 63.085 192.405 63.255 193.510 ;
        RECT 63.425 192.650 63.705 193.600 ;
        RECT 62.950 192.275 63.255 192.405 ;
        RECT 61.635 191.955 62.740 192.125 ;
        RECT 62.950 191.850 63.200 192.275 ;
        RECT 63.370 191.680 63.635 192.140 ;
        RECT 63.875 191.850 64.060 193.970 ;
        RECT 64.230 193.850 64.560 194.230 ;
        RECT 64.730 193.680 64.900 193.970 ;
        RECT 64.235 193.510 64.900 193.680 ;
        RECT 65.160 193.840 66.470 194.010 ;
        RECT 64.235 192.520 64.465 193.510 ;
        RECT 64.635 192.690 64.985 193.340 ;
        RECT 65.160 192.900 65.550 193.840 ;
        RECT 66.740 193.760 66.910 194.230 ;
        RECT 65.720 193.590 66.050 193.670 ;
        RECT 67.080 193.590 67.445 194.060 ;
        RECT 67.615 193.760 67.785 194.230 ;
        RECT 67.955 193.590 68.285 194.060 ;
        RECT 65.720 193.410 68.285 193.590 ;
        RECT 68.455 193.410 68.625 194.230 ;
        RECT 68.935 193.590 69.265 194.060 ;
        RECT 69.435 193.760 69.605 194.230 ;
        RECT 69.775 193.840 70.950 194.060 ;
        RECT 69.775 193.590 70.025 193.840 ;
        RECT 71.140 193.675 71.720 194.060 ;
        RECT 71.890 193.750 72.495 194.230 ;
        RECT 68.935 193.410 70.025 193.590 ;
        RECT 70.195 193.420 70.970 193.670 ;
        RECT 65.760 193.070 66.420 193.240 ;
        RECT 65.160 192.690 66.010 192.900 ;
        RECT 66.250 192.860 66.420 193.070 ;
        RECT 67.100 193.030 68.125 193.240 ;
        RECT 68.350 193.040 69.800 193.240 ;
        RECT 67.955 192.870 68.125 193.030 ;
        RECT 70.095 193.030 70.570 193.240 ;
        RECT 70.095 192.870 70.265 193.030 ;
        RECT 66.250 192.690 67.745 192.860 ;
        RECT 67.955 192.700 70.265 192.870 ;
        RECT 65.760 192.520 66.010 192.690 ;
        RECT 67.575 192.530 67.745 192.690 ;
        RECT 70.740 192.530 70.970 193.420 ;
        RECT 64.235 192.350 64.900 192.520 ;
        RECT 64.230 191.680 64.560 192.180 ;
        RECT 64.730 191.850 64.900 192.350 ;
        RECT 65.160 191.680 65.590 192.520 ;
        RECT 65.760 192.350 67.330 192.520 ;
        RECT 67.575 192.360 70.970 192.530 ;
        RECT 65.760 192.190 66.010 192.350 ;
        RECT 67.120 192.190 67.330 192.350 ;
        RECT 68.975 192.350 70.970 192.360 ;
        RECT 66.180 191.680 66.430 192.180 ;
        RECT 66.700 192.020 66.950 192.180 ;
        RECT 67.500 192.020 67.825 192.190 ;
        RECT 66.700 191.850 67.825 192.020 ;
        RECT 67.995 191.680 68.245 192.180 ;
        RECT 68.415 191.850 68.665 192.190 ;
        RECT 68.975 191.850 69.225 192.350 ;
        RECT 69.395 191.680 69.645 192.180 ;
        RECT 69.815 191.850 70.065 192.350 ;
        RECT 70.235 191.680 70.485 192.180 ;
        RECT 70.655 191.850 70.970 192.350 ;
        RECT 71.140 192.750 71.505 193.675 ;
        RECT 72.670 193.580 72.920 194.060 ;
        RECT 71.970 193.410 72.920 193.580 ;
        RECT 73.090 193.460 73.560 194.060 ;
        RECT 73.825 193.750 74.155 194.230 ;
        RECT 74.325 193.580 74.650 194.060 ;
        RECT 71.970 193.325 72.140 193.410 ;
        RECT 71.685 192.990 72.140 193.325 ;
        RECT 73.090 193.240 73.265 193.460 ;
        RECT 73.730 193.410 74.650 193.580 ;
        RECT 75.340 193.410 75.550 194.230 ;
        RECT 75.720 193.430 76.050 194.060 ;
        RECT 73.730 193.290 74.080 193.410 ;
        RECT 72.315 193.065 73.265 193.240 ;
        RECT 71.970 192.820 72.140 192.990 ;
        RECT 71.140 191.850 71.700 192.750 ;
        RECT 71.970 192.650 72.920 192.820 ;
        RECT 71.890 191.680 72.500 192.480 ;
        RECT 72.670 191.850 72.920 192.650 ;
        RECT 73.090 192.525 73.265 193.065 ;
        RECT 73.630 193.020 74.080 193.290 ;
        RECT 73.730 192.825 74.080 193.020 ;
        RECT 74.250 192.995 74.650 193.240 ;
        RECT 75.720 192.830 75.970 193.430 ;
        RECT 76.220 193.410 76.450 194.230 ;
        RECT 76.660 193.505 76.950 194.230 ;
        RECT 77.820 193.760 77.990 194.230 ;
        RECT 78.660 193.760 78.830 194.230 ;
        RECT 79.095 193.840 80.325 194.060 ;
        RECT 78.160 193.590 78.490 193.670 ;
        RECT 79.520 193.590 79.850 193.670 ;
        RECT 77.580 193.410 79.850 193.590 ;
        RECT 80.075 193.590 80.325 193.840 ;
        RECT 80.495 193.760 80.665 194.230 ;
        RECT 80.835 193.590 81.165 194.060 ;
        RECT 81.435 193.760 81.605 194.230 ;
        RECT 80.075 193.410 81.165 193.590 ;
        RECT 81.775 193.590 82.105 194.060 ;
        RECT 82.275 193.760 82.445 194.230 ;
        RECT 82.615 193.590 82.945 194.060 ;
        RECT 83.115 193.760 83.285 194.230 ;
        RECT 81.775 193.410 83.355 193.590 ;
        RECT 83.560 193.580 83.885 194.060 ;
        RECT 84.055 193.750 84.385 194.230 ;
        RECT 83.560 193.410 84.480 193.580 ;
        RECT 84.650 193.460 85.120 194.060 ;
        RECT 76.140 192.990 76.470 193.240 ;
        RECT 77.580 192.900 77.990 193.410 ;
        RECT 79.020 193.380 79.190 193.410 ;
        RECT 78.200 193.070 78.860 193.240 ;
        RECT 73.730 192.655 74.650 192.825 ;
        RECT 73.090 191.850 73.540 192.525 ;
        RECT 73.810 191.680 74.135 192.485 ;
        RECT 74.305 191.850 74.650 192.655 ;
        RECT 75.340 191.680 75.550 192.820 ;
        RECT 75.720 191.850 76.050 192.830 ;
        RECT 76.220 191.680 76.450 192.820 ;
        RECT 76.660 191.680 76.950 192.845 ;
        RECT 77.580 192.690 78.450 192.900 ;
        RECT 78.690 192.870 78.860 193.070 ;
        RECT 79.385 193.040 80.055 193.240 ;
        RECT 80.245 193.040 81.765 193.240 ;
        RECT 81.935 193.040 82.430 193.240 ;
        RECT 82.600 193.040 82.930 193.240 ;
        RECT 81.595 192.870 81.765 193.040 ;
        RECT 82.600 192.870 82.770 193.040 ;
        RECT 78.690 192.700 81.425 192.870 ;
        RECT 81.595 192.700 82.770 192.870 ;
        RECT 77.780 192.020 78.030 192.520 ;
        RECT 78.200 192.190 78.450 192.690 ;
        RECT 81.255 192.530 81.425 192.700 ;
        RECT 83.185 192.530 83.355 193.410 ;
        RECT 84.130 193.290 84.480 193.410 ;
        RECT 83.560 192.995 83.960 193.240 ;
        RECT 84.130 193.020 84.580 193.290 ;
        RECT 84.945 193.240 85.120 193.460 ;
        RECT 85.290 193.580 85.540 194.060 ;
        RECT 85.715 193.750 86.320 194.230 ;
        RECT 86.490 193.675 87.070 194.060 ;
        RECT 85.290 193.410 86.240 193.580 ;
        RECT 86.070 193.325 86.240 193.410 ;
        RECT 84.945 193.065 85.895 193.240 ;
        RECT 84.130 192.825 84.480 193.020 ;
        RECT 78.620 192.360 81.085 192.530 ;
        RECT 81.255 192.360 83.355 192.530 ;
        RECT 83.560 192.655 84.480 192.825 ;
        RECT 78.620 192.020 79.390 192.360 ;
        RECT 77.780 191.850 79.390 192.020 ;
        RECT 79.560 191.680 79.865 192.180 ;
        RECT 80.035 191.850 80.285 192.360 ;
        RECT 80.875 192.190 81.085 192.360 ;
        RECT 81.815 192.190 82.065 192.360 ;
        RECT 80.455 191.680 80.705 192.180 ;
        RECT 80.875 191.850 81.190 192.190 ;
        RECT 82.240 192.180 82.410 192.190 ;
        RECT 83.160 192.180 83.330 192.190 ;
        RECT 81.395 192.020 81.645 192.180 ;
        RECT 82.235 192.020 82.485 192.180 ;
        RECT 81.395 191.850 82.485 192.020 ;
        RECT 82.655 191.680 82.905 192.180 ;
        RECT 83.075 191.850 83.355 192.180 ;
        RECT 83.560 191.850 83.905 192.655 ;
        RECT 84.945 192.525 85.120 193.065 ;
        RECT 86.070 192.990 86.525 193.325 ;
        RECT 86.070 192.820 86.240 192.990 ;
        RECT 84.075 191.680 84.400 192.485 ;
        RECT 84.670 191.850 85.120 192.525 ;
        RECT 85.290 192.650 86.240 192.820 ;
        RECT 86.705 192.750 87.070 193.675 ;
        RECT 87.240 193.480 88.450 194.230 ;
        RECT 88.620 193.480 89.830 194.230 ;
        RECT 85.290 191.850 85.540 192.650 ;
        RECT 85.710 191.680 86.320 192.480 ;
        RECT 86.510 191.850 87.070 192.750 ;
        RECT 87.240 192.770 87.760 193.310 ;
        RECT 87.930 192.940 88.450 193.480 ;
        RECT 88.620 192.770 89.140 193.310 ;
        RECT 89.310 192.940 89.830 193.480 ;
        RECT 87.240 191.680 88.450 192.770 ;
        RECT 88.620 191.680 89.830 192.770 ;
        RECT 55.415 191.510 89.915 191.680 ;
        RECT 55.500 190.420 56.710 191.510 ;
        RECT 55.500 189.710 56.020 190.250 ;
        RECT 56.190 189.880 56.710 190.420 ;
        RECT 56.880 190.440 57.440 191.340 ;
        RECT 57.630 190.710 58.240 191.510 ;
        RECT 58.410 190.540 58.660 191.340 ;
        RECT 55.500 188.960 56.710 189.710 ;
        RECT 56.880 189.515 57.245 190.440 ;
        RECT 57.710 190.370 58.660 190.540 ;
        RECT 58.830 190.665 59.280 191.340 ;
        RECT 59.550 190.705 59.875 191.510 ;
        RECT 57.710 190.200 57.880 190.370 ;
        RECT 57.425 189.865 57.880 190.200 ;
        RECT 58.830 190.125 59.005 190.665 ;
        RECT 60.045 190.535 60.390 191.340 ;
        RECT 60.650 190.890 60.820 191.320 ;
        RECT 60.990 191.060 61.320 191.510 ;
        RECT 60.650 190.660 61.330 190.890 ;
        RECT 59.470 190.365 60.390 190.535 ;
        RECT 59.470 190.170 59.820 190.365 ;
        RECT 60.620 190.320 60.925 190.490 ;
        RECT 58.055 189.950 59.005 190.125 ;
        RECT 57.710 189.780 57.880 189.865 ;
        RECT 57.710 189.610 58.660 189.780 ;
        RECT 56.880 189.130 57.460 189.515 ;
        RECT 57.630 188.960 58.235 189.440 ;
        RECT 58.410 189.130 58.660 189.610 ;
        RECT 58.830 189.730 59.005 189.950 ;
        RECT 59.370 189.900 59.820 190.170 ;
        RECT 59.990 189.950 60.390 190.195 ;
        RECT 59.470 189.780 59.820 189.900 ;
        RECT 58.830 189.130 59.300 189.730 ;
        RECT 59.470 189.610 60.390 189.780 ;
        RECT 60.625 189.640 60.925 190.320 ;
        RECT 61.095 190.010 61.330 190.660 ;
        RECT 61.520 190.350 61.805 191.295 ;
        RECT 61.985 191.040 62.670 191.510 ;
        RECT 61.980 190.520 62.675 190.830 ;
        RECT 62.850 190.455 63.155 191.240 ;
        RECT 63.340 190.555 63.610 191.510 ;
        RECT 61.520 190.200 62.380 190.350 ;
        RECT 61.520 190.180 62.810 190.200 ;
        RECT 61.095 189.680 61.650 190.010 ;
        RECT 61.820 189.820 62.810 190.180 ;
        RECT 59.565 188.960 59.895 189.440 ;
        RECT 60.065 189.130 60.390 189.610 ;
        RECT 61.095 189.530 61.310 189.680 ;
        RECT 60.570 188.960 60.900 189.465 ;
        RECT 61.070 189.155 61.310 189.530 ;
        RECT 61.820 189.485 61.990 189.820 ;
        RECT 62.980 189.650 63.155 190.455 ;
        RECT 63.780 190.345 64.070 191.510 ;
        RECT 64.275 191.010 64.555 191.340 ;
        RECT 64.725 191.010 64.975 191.510 ;
        RECT 65.145 191.170 66.235 191.340 ;
        RECT 65.145 191.010 65.395 191.170 ;
        RECT 65.985 191.010 66.235 191.170 ;
        RECT 64.300 191.000 64.470 191.010 ;
        RECT 65.220 191.000 65.390 191.010 ;
        RECT 66.440 191.000 66.755 191.340 ;
        RECT 66.925 191.010 67.175 191.510 ;
        RECT 65.565 190.830 65.815 191.000 ;
        RECT 66.545 190.830 66.755 191.000 ;
        RECT 67.345 190.830 67.595 191.340 ;
        RECT 67.765 191.010 68.070 191.510 ;
        RECT 68.240 191.170 69.850 191.340 ;
        RECT 68.240 190.830 69.010 191.170 ;
        RECT 64.275 190.660 66.375 190.830 ;
        RECT 66.545 190.660 69.010 190.830 ;
        RECT 64.275 189.780 64.445 190.660 ;
        RECT 66.205 190.490 66.375 190.660 ;
        RECT 69.180 190.500 69.430 191.000 ;
        RECT 69.600 190.670 69.850 191.170 ;
        RECT 70.260 191.170 71.400 191.340 ;
        RECT 70.260 190.710 70.560 191.170 ;
        RECT 70.730 190.540 71.060 191.000 ;
        RECT 64.860 190.320 66.035 190.490 ;
        RECT 66.205 190.320 68.940 190.490 ;
        RECT 64.860 190.150 65.030 190.320 ;
        RECT 65.865 190.150 66.035 190.320 ;
        RECT 64.700 189.950 65.030 190.150 ;
        RECT 65.200 189.950 65.695 190.150 ;
        RECT 65.865 189.950 67.385 190.150 ;
        RECT 67.575 189.950 68.245 190.150 ;
        RECT 68.770 190.120 68.940 190.320 ;
        RECT 69.180 190.290 70.050 190.500 ;
        RECT 68.770 189.950 69.430 190.120 ;
        RECT 69.640 189.780 70.050 190.290 ;
        RECT 61.590 189.290 61.990 189.485 ;
        RECT 61.590 189.145 61.760 189.290 ;
        RECT 62.350 188.960 62.750 189.455 ;
        RECT 62.920 189.130 63.155 189.650 ;
        RECT 63.340 188.960 63.610 189.595 ;
        RECT 63.780 188.960 64.070 189.685 ;
        RECT 64.275 189.600 65.855 189.780 ;
        RECT 64.345 188.960 64.515 189.430 ;
        RECT 64.685 189.130 65.015 189.600 ;
        RECT 65.185 188.960 65.355 189.430 ;
        RECT 65.525 189.130 65.855 189.600 ;
        RECT 66.465 189.600 67.555 189.780 ;
        RECT 66.025 188.960 66.195 189.430 ;
        RECT 66.465 189.130 66.795 189.600 ;
        RECT 66.965 188.960 67.135 189.430 ;
        RECT 67.305 189.350 67.555 189.600 ;
        RECT 67.780 189.600 70.050 189.780 ;
        RECT 70.300 190.320 71.060 190.540 ;
        RECT 71.230 190.540 71.400 191.170 ;
        RECT 71.570 190.710 71.900 191.510 ;
        RECT 72.070 190.540 72.345 191.340 ;
        RECT 73.180 191.170 74.790 191.340 ;
        RECT 73.180 190.670 73.430 191.170 ;
        RECT 71.230 190.330 72.345 190.540 ;
        RECT 73.600 190.500 73.850 191.000 ;
        RECT 74.020 190.830 74.790 191.170 ;
        RECT 74.960 191.010 75.265 191.510 ;
        RECT 75.435 190.830 75.685 191.340 ;
        RECT 75.855 191.010 76.105 191.510 ;
        RECT 76.275 191.000 76.590 191.340 ;
        RECT 76.795 191.170 77.885 191.340 ;
        RECT 76.795 191.010 77.045 191.170 ;
        RECT 77.635 191.010 77.885 191.170 ;
        RECT 78.055 191.010 78.305 191.510 ;
        RECT 78.475 191.010 78.755 191.340 ;
        RECT 77.640 191.000 77.810 191.010 ;
        RECT 78.560 191.000 78.730 191.010 ;
        RECT 76.275 190.830 76.485 191.000 ;
        RECT 77.215 190.830 77.465 191.000 ;
        RECT 74.020 190.660 76.485 190.830 ;
        RECT 76.655 190.660 78.755 190.830 ;
        RECT 70.300 189.780 70.515 190.320 ;
        RECT 72.980 190.290 73.850 190.500 ;
        RECT 76.655 190.490 76.825 190.660 ;
        RECT 74.090 190.320 76.825 190.490 ;
        RECT 76.995 190.320 78.170 190.490 ;
        RECT 70.685 189.950 71.455 190.150 ;
        RECT 71.625 189.950 72.345 190.150 ;
        RECT 72.980 189.780 73.390 190.290 ;
        RECT 74.090 190.120 74.260 190.320 ;
        RECT 76.995 190.150 77.165 190.320 ;
        RECT 78.000 190.150 78.170 190.320 ;
        RECT 73.600 189.950 74.260 190.120 ;
        RECT 74.785 189.950 75.455 190.150 ;
        RECT 75.645 189.950 77.165 190.150 ;
        RECT 77.335 189.950 77.830 190.150 ;
        RECT 78.000 189.950 78.330 190.150 ;
        RECT 78.585 189.780 78.755 190.660 ;
        RECT 70.300 189.610 71.900 189.780 ;
        RECT 70.730 189.600 71.900 189.610 ;
        RECT 67.780 189.520 68.110 189.600 ;
        RECT 69.140 189.520 69.470 189.600 ;
        RECT 67.305 189.130 68.535 189.350 ;
        RECT 68.800 188.960 68.970 189.430 ;
        RECT 69.640 188.960 69.810 189.430 ;
        RECT 70.270 188.960 70.560 189.430 ;
        RECT 70.730 189.130 71.060 189.600 ;
        RECT 71.230 188.960 71.400 189.430 ;
        RECT 71.570 189.130 71.900 189.600 ;
        RECT 72.070 188.960 72.345 189.780 ;
        RECT 72.980 189.600 75.250 189.780 ;
        RECT 73.560 189.520 73.890 189.600 ;
        RECT 74.920 189.520 75.250 189.600 ;
        RECT 75.475 189.600 76.565 189.780 ;
        RECT 73.220 188.960 73.390 189.430 ;
        RECT 74.060 188.960 74.230 189.430 ;
        RECT 75.475 189.350 75.725 189.600 ;
        RECT 74.495 189.130 75.725 189.350 ;
        RECT 75.895 188.960 76.065 189.430 ;
        RECT 76.235 189.130 76.565 189.600 ;
        RECT 77.175 189.600 78.755 189.780 ;
        RECT 78.960 190.440 79.520 191.340 ;
        RECT 79.710 190.710 80.320 191.510 ;
        RECT 80.490 190.540 80.740 191.340 ;
        RECT 76.835 188.960 77.005 189.430 ;
        RECT 77.175 189.130 77.505 189.600 ;
        RECT 77.675 188.960 77.845 189.430 ;
        RECT 78.015 189.130 78.345 189.600 ;
        RECT 78.960 189.515 79.325 190.440 ;
        RECT 79.790 190.370 80.740 190.540 ;
        RECT 80.910 190.665 81.360 191.340 ;
        RECT 81.630 190.705 81.955 191.510 ;
        RECT 79.790 190.200 79.960 190.370 ;
        RECT 79.505 189.865 79.960 190.200 ;
        RECT 80.910 190.125 81.085 190.665 ;
        RECT 82.125 190.535 82.470 191.340 ;
        RECT 81.550 190.365 82.470 190.535 ;
        RECT 83.560 190.420 84.770 191.510 ;
        RECT 84.940 190.440 85.500 191.340 ;
        RECT 85.690 190.710 86.300 191.510 ;
        RECT 86.470 190.540 86.720 191.340 ;
        RECT 81.550 190.170 81.900 190.365 ;
        RECT 80.135 189.950 81.085 190.125 ;
        RECT 79.790 189.780 79.960 189.865 ;
        RECT 79.790 189.610 80.740 189.780 ;
        RECT 78.515 188.960 78.685 189.430 ;
        RECT 78.960 189.130 79.540 189.515 ;
        RECT 79.710 188.960 80.315 189.440 ;
        RECT 80.490 189.130 80.740 189.610 ;
        RECT 80.910 189.730 81.085 189.950 ;
        RECT 81.450 189.900 81.900 190.170 ;
        RECT 82.070 189.950 82.470 190.195 ;
        RECT 81.550 189.780 81.900 189.900 ;
        RECT 83.560 189.880 84.080 190.420 ;
        RECT 80.910 189.130 81.380 189.730 ;
        RECT 81.550 189.610 82.470 189.780 ;
        RECT 84.250 189.710 84.770 190.250 ;
        RECT 81.645 188.960 81.975 189.440 ;
        RECT 82.145 189.130 82.470 189.610 ;
        RECT 83.560 188.960 84.770 189.710 ;
        RECT 84.940 189.515 85.305 190.440 ;
        RECT 85.770 190.370 86.720 190.540 ;
        RECT 86.890 190.665 87.340 191.340 ;
        RECT 87.610 190.705 87.935 191.510 ;
        RECT 85.770 190.200 85.940 190.370 ;
        RECT 85.485 189.865 85.940 190.200 ;
        RECT 86.890 190.125 87.065 190.665 ;
        RECT 88.105 190.535 88.450 191.340 ;
        RECT 87.530 190.365 88.450 190.535 ;
        RECT 88.620 190.420 89.830 191.510 ;
        RECT 87.530 190.170 87.880 190.365 ;
        RECT 86.115 189.950 87.065 190.125 ;
        RECT 85.770 189.780 85.940 189.865 ;
        RECT 85.770 189.610 86.720 189.780 ;
        RECT 84.940 189.130 85.520 189.515 ;
        RECT 85.690 188.960 86.295 189.440 ;
        RECT 86.470 189.130 86.720 189.610 ;
        RECT 86.890 189.730 87.065 189.950 ;
        RECT 87.430 189.900 87.880 190.170 ;
        RECT 88.050 189.950 88.450 190.195 ;
        RECT 87.530 189.780 87.880 189.900 ;
        RECT 88.620 189.880 89.140 190.420 ;
        RECT 86.890 189.130 87.360 189.730 ;
        RECT 87.530 189.610 88.450 189.780 ;
        RECT 89.310 189.710 89.830 190.250 ;
        RECT 87.625 188.960 87.955 189.440 ;
        RECT 88.125 189.130 88.450 189.610 ;
        RECT 88.620 188.960 89.830 189.710 ;
        RECT 55.415 188.790 89.915 188.960 ;
        RECT 55.500 188.040 56.710 188.790 ;
        RECT 57.510 188.275 57.680 188.790 ;
        RECT 57.850 188.135 58.180 188.570 ;
        RECT 58.350 188.180 58.520 188.790 ;
        RECT 57.800 188.050 58.180 188.135 ;
        RECT 58.690 188.050 59.020 188.575 ;
        RECT 59.280 188.260 59.490 188.790 ;
        RECT 59.765 188.340 60.550 188.510 ;
        RECT 60.720 188.340 61.125 188.510 ;
        RECT 55.500 187.500 56.020 188.040 ;
        RECT 57.800 188.010 58.025 188.050 ;
        RECT 56.190 187.330 56.710 187.870 ;
        RECT 55.500 186.240 56.710 187.330 ;
        RECT 57.800 187.430 57.970 188.010 ;
        RECT 58.690 187.880 58.890 188.050 ;
        RECT 59.765 187.880 59.935 188.340 ;
        RECT 58.140 187.550 58.890 187.880 ;
        RECT 59.060 187.550 59.935 187.880 ;
        RECT 57.800 187.380 58.015 187.430 ;
        RECT 57.800 187.300 58.190 187.380 ;
        RECT 57.520 186.240 57.690 187.155 ;
        RECT 57.860 186.455 58.190 187.300 ;
        RECT 58.700 187.345 58.890 187.550 ;
        RECT 58.360 186.240 58.530 187.250 ;
        RECT 58.700 186.970 59.595 187.345 ;
        RECT 58.700 186.410 59.040 186.970 ;
        RECT 59.270 186.240 59.585 186.740 ;
        RECT 59.765 186.710 59.935 187.550 ;
        RECT 60.105 187.840 60.570 188.170 ;
        RECT 60.955 188.110 61.125 188.340 ;
        RECT 61.305 188.290 61.675 188.790 ;
        RECT 61.995 188.340 62.670 188.510 ;
        RECT 62.865 188.340 63.200 188.510 ;
        RECT 60.105 186.880 60.425 187.840 ;
        RECT 60.955 187.810 61.785 188.110 ;
        RECT 60.595 186.910 60.785 187.630 ;
        RECT 60.955 186.740 61.125 187.810 ;
        RECT 61.585 187.780 61.785 187.810 ;
        RECT 61.295 187.560 61.465 187.630 ;
        RECT 61.995 187.560 62.165 188.340 ;
        RECT 63.030 188.200 63.200 188.340 ;
        RECT 63.370 188.330 63.620 188.790 ;
        RECT 61.295 187.390 62.165 187.560 ;
        RECT 62.335 187.920 62.860 188.140 ;
        RECT 63.030 188.070 63.255 188.200 ;
        RECT 61.295 187.300 61.805 187.390 ;
        RECT 59.765 186.540 60.650 186.710 ;
        RECT 60.875 186.410 61.125 186.740 ;
        RECT 61.295 186.240 61.465 187.040 ;
        RECT 61.635 186.685 61.805 187.300 ;
        RECT 62.335 187.220 62.505 187.920 ;
        RECT 61.975 186.855 62.505 187.220 ;
        RECT 62.675 187.155 62.915 187.750 ;
        RECT 63.085 186.965 63.255 188.070 ;
        RECT 63.425 187.210 63.705 188.160 ;
        RECT 62.950 186.835 63.255 186.965 ;
        RECT 61.635 186.515 62.740 186.685 ;
        RECT 62.950 186.410 63.200 186.835 ;
        RECT 63.370 186.240 63.635 186.700 ;
        RECT 63.875 186.410 64.060 188.530 ;
        RECT 64.230 188.410 64.560 188.790 ;
        RECT 64.730 188.240 64.900 188.530 ;
        RECT 66.250 188.275 66.420 188.790 ;
        RECT 64.235 188.070 64.900 188.240 ;
        RECT 66.590 188.135 66.920 188.570 ;
        RECT 67.090 188.180 67.260 188.790 ;
        RECT 64.235 187.080 64.465 188.070 ;
        RECT 66.540 188.050 66.920 188.135 ;
        RECT 67.430 188.050 67.760 188.575 ;
        RECT 68.020 188.260 68.230 188.790 ;
        RECT 68.505 188.340 69.290 188.510 ;
        RECT 69.460 188.340 69.865 188.510 ;
        RECT 66.540 188.010 66.765 188.050 ;
        RECT 64.635 187.250 64.985 187.900 ;
        RECT 66.540 187.430 66.710 188.010 ;
        RECT 67.430 187.880 67.630 188.050 ;
        RECT 68.505 187.880 68.675 188.340 ;
        RECT 66.880 187.550 67.630 187.880 ;
        RECT 67.800 187.550 68.675 187.880 ;
        RECT 66.540 187.380 66.755 187.430 ;
        RECT 66.540 187.300 66.930 187.380 ;
        RECT 64.235 186.910 64.900 187.080 ;
        RECT 64.230 186.240 64.560 186.740 ;
        RECT 64.730 186.410 64.900 186.910 ;
        RECT 66.260 186.240 66.430 187.155 ;
        RECT 66.600 186.455 66.930 187.300 ;
        RECT 67.440 187.345 67.630 187.550 ;
        RECT 67.100 186.240 67.270 187.250 ;
        RECT 67.440 186.970 68.335 187.345 ;
        RECT 67.440 186.410 67.780 186.970 ;
        RECT 68.010 186.240 68.325 186.740 ;
        RECT 68.505 186.710 68.675 187.550 ;
        RECT 68.845 187.840 69.310 188.170 ;
        RECT 69.695 188.110 69.865 188.340 ;
        RECT 70.045 188.290 70.415 188.790 ;
        RECT 70.735 188.340 71.410 188.510 ;
        RECT 71.605 188.340 71.940 188.510 ;
        RECT 68.845 186.880 69.165 187.840 ;
        RECT 69.695 187.810 70.525 188.110 ;
        RECT 69.335 186.910 69.525 187.630 ;
        RECT 69.695 186.740 69.865 187.810 ;
        RECT 70.325 187.780 70.525 187.810 ;
        RECT 70.035 187.560 70.205 187.630 ;
        RECT 70.735 187.560 70.905 188.340 ;
        RECT 71.770 188.200 71.940 188.340 ;
        RECT 72.110 188.330 72.360 188.790 ;
        RECT 70.035 187.390 70.905 187.560 ;
        RECT 71.075 187.920 71.600 188.140 ;
        RECT 71.770 188.070 71.995 188.200 ;
        RECT 70.035 187.300 70.545 187.390 ;
        RECT 68.505 186.540 69.390 186.710 ;
        RECT 69.615 186.410 69.865 186.740 ;
        RECT 70.035 186.240 70.205 187.040 ;
        RECT 70.375 186.685 70.545 187.300 ;
        RECT 71.075 187.220 71.245 187.920 ;
        RECT 70.715 186.855 71.245 187.220 ;
        RECT 71.415 187.155 71.655 187.750 ;
        RECT 71.825 186.965 71.995 188.070 ;
        RECT 72.165 187.210 72.445 188.160 ;
        RECT 71.690 186.835 71.995 186.965 ;
        RECT 70.375 186.515 71.480 186.685 ;
        RECT 71.690 186.410 71.940 186.835 ;
        RECT 72.110 186.240 72.375 186.700 ;
        RECT 72.615 186.410 72.800 188.530 ;
        RECT 72.970 188.410 73.300 188.790 ;
        RECT 73.470 188.240 73.640 188.530 ;
        RECT 74.470 188.410 75.640 188.620 ;
        RECT 74.470 188.390 74.800 188.410 ;
        RECT 72.975 188.070 73.640 188.240 ;
        RECT 72.975 187.080 73.205 188.070 ;
        RECT 74.360 187.970 75.220 188.220 ;
        RECT 75.390 188.160 75.640 188.410 ;
        RECT 75.810 188.330 75.980 188.790 ;
        RECT 76.150 188.160 76.490 188.620 ;
        RECT 75.390 187.990 76.490 188.160 ;
        RECT 76.660 188.065 76.950 188.790 ;
        RECT 77.120 188.140 77.445 188.620 ;
        RECT 77.615 188.310 77.945 188.790 ;
        RECT 77.120 187.970 78.040 188.140 ;
        RECT 78.210 188.020 78.680 188.620 ;
        RECT 73.375 187.250 73.725 187.900 ;
        RECT 74.360 187.380 74.640 187.970 ;
        RECT 77.690 187.850 78.040 187.970 ;
        RECT 74.810 187.550 75.560 187.800 ;
        RECT 75.730 187.550 76.490 187.800 ;
        RECT 77.120 187.555 77.520 187.800 ;
        RECT 77.690 187.580 78.140 187.850 ;
        RECT 78.505 187.800 78.680 188.020 ;
        RECT 78.850 188.140 79.100 188.620 ;
        RECT 79.275 188.310 79.880 188.790 ;
        RECT 80.050 188.235 80.630 188.620 ;
        RECT 80.905 188.320 81.075 188.790 ;
        RECT 78.850 187.970 79.800 188.140 ;
        RECT 79.630 187.885 79.800 187.970 ;
        RECT 78.505 187.625 79.455 187.800 ;
        RECT 74.360 187.210 76.060 187.380 ;
        RECT 72.975 186.910 73.640 187.080 ;
        RECT 72.970 186.240 73.300 186.740 ;
        RECT 73.470 186.410 73.640 186.910 ;
        RECT 74.465 186.240 74.720 187.040 ;
        RECT 74.890 186.410 75.220 187.210 ;
        RECT 75.390 186.240 75.560 187.040 ;
        RECT 75.730 186.410 76.060 187.210 ;
        RECT 76.230 186.240 76.490 187.380 ;
        RECT 76.660 186.240 76.950 187.405 ;
        RECT 77.690 187.385 78.040 187.580 ;
        RECT 77.120 187.215 78.040 187.385 ;
        RECT 77.120 186.410 77.465 187.215 ;
        RECT 78.505 187.085 78.680 187.625 ;
        RECT 79.630 187.550 80.085 187.885 ;
        RECT 79.630 187.380 79.800 187.550 ;
        RECT 77.635 186.240 77.960 187.045 ;
        RECT 78.230 186.410 78.680 187.085 ;
        RECT 78.850 187.210 79.800 187.380 ;
        RECT 80.265 187.310 80.630 188.235 ;
        RECT 81.245 188.150 81.575 188.620 ;
        RECT 81.745 188.320 81.915 188.790 ;
        RECT 82.085 188.150 82.415 188.620 ;
        RECT 82.585 188.320 82.755 188.790 ;
        RECT 78.850 186.410 79.100 187.210 ;
        RECT 79.270 186.240 79.880 187.040 ;
        RECT 80.070 186.410 80.630 187.310 ;
        RECT 80.835 187.970 82.415 188.150 ;
        RECT 83.025 188.150 83.355 188.620 ;
        RECT 83.525 188.320 83.695 188.790 ;
        RECT 83.865 188.400 85.095 188.620 ;
        RECT 83.865 188.150 84.115 188.400 ;
        RECT 85.360 188.320 85.530 188.790 ;
        RECT 86.200 188.320 86.370 188.790 ;
        RECT 83.025 187.970 84.115 188.150 ;
        RECT 84.340 188.150 84.670 188.230 ;
        RECT 85.700 188.150 86.030 188.230 ;
        RECT 84.340 187.970 86.610 188.150 ;
        RECT 87.240 188.040 88.450 188.790 ;
        RECT 88.620 188.040 89.830 188.790 ;
        RECT 80.835 187.090 81.005 187.970 ;
        RECT 81.260 187.600 81.590 187.800 ;
        RECT 81.760 187.600 82.255 187.800 ;
        RECT 82.425 187.600 83.945 187.800 ;
        RECT 84.135 187.600 84.805 187.800 ;
        RECT 85.330 187.630 85.990 187.800 ;
        RECT 81.420 187.430 81.590 187.600 ;
        RECT 82.425 187.430 82.595 187.600 ;
        RECT 85.330 187.430 85.500 187.630 ;
        RECT 86.200 187.460 86.610 187.970 ;
        RECT 81.420 187.260 82.595 187.430 ;
        RECT 82.765 187.260 85.500 187.430 ;
        RECT 82.765 187.090 82.935 187.260 ;
        RECT 85.740 187.250 86.610 187.460 ;
        RECT 87.240 187.330 87.760 187.870 ;
        RECT 87.930 187.500 88.450 188.040 ;
        RECT 88.620 187.330 89.140 187.870 ;
        RECT 89.310 187.500 89.830 188.040 ;
        RECT 80.835 186.920 82.935 187.090 ;
        RECT 83.105 186.920 85.570 187.090 ;
        RECT 82.125 186.750 82.375 186.920 ;
        RECT 83.105 186.750 83.315 186.920 ;
        RECT 80.860 186.740 81.030 186.750 ;
        RECT 81.780 186.740 81.950 186.750 ;
        RECT 80.835 186.410 81.115 186.740 ;
        RECT 81.285 186.240 81.535 186.740 ;
        RECT 81.705 186.580 81.955 186.740 ;
        RECT 82.545 186.580 82.795 186.740 ;
        RECT 81.705 186.410 82.795 186.580 ;
        RECT 83.000 186.410 83.315 186.750 ;
        RECT 83.485 186.240 83.735 186.740 ;
        RECT 83.905 186.410 84.155 186.920 ;
        RECT 84.325 186.240 84.630 186.740 ;
        RECT 84.800 186.580 85.570 186.920 ;
        RECT 85.740 186.750 85.990 187.250 ;
        RECT 86.160 186.580 86.410 187.080 ;
        RECT 84.800 186.410 86.410 186.580 ;
        RECT 87.240 186.240 88.450 187.330 ;
        RECT 88.620 186.240 89.830 187.330 ;
        RECT 55.415 186.070 89.915 186.240 ;
        RECT 55.500 184.980 56.710 186.070 ;
        RECT 55.500 184.270 56.020 184.810 ;
        RECT 56.190 184.440 56.710 184.980 ;
        RECT 56.880 185.000 57.440 185.900 ;
        RECT 57.630 185.270 58.240 186.070 ;
        RECT 58.410 185.100 58.660 185.900 ;
        RECT 55.500 183.520 56.710 184.270 ;
        RECT 56.880 184.075 57.245 185.000 ;
        RECT 57.710 184.930 58.660 185.100 ;
        RECT 58.830 185.225 59.280 185.900 ;
        RECT 59.550 185.265 59.875 186.070 ;
        RECT 57.710 184.760 57.880 184.930 ;
        RECT 57.425 184.425 57.880 184.760 ;
        RECT 58.830 184.685 59.005 185.225 ;
        RECT 60.045 185.095 60.390 185.900 ;
        RECT 59.470 184.925 60.390 185.095 ;
        RECT 60.560 184.930 60.890 186.070 ;
        RECT 61.060 185.440 61.415 185.900 ;
        RECT 61.585 185.610 62.160 186.070 ;
        RECT 62.330 185.440 62.660 185.900 ;
        RECT 61.060 185.270 62.660 185.440 ;
        RECT 62.860 185.270 63.115 186.070 ;
        RECT 61.060 184.930 61.335 185.270 ;
        RECT 61.515 185.050 61.705 185.090 ;
        RECT 59.470 184.730 59.820 184.925 ;
        RECT 61.515 184.880 61.710 185.050 ;
        RECT 58.055 184.510 59.005 184.685 ;
        RECT 57.710 184.340 57.880 184.425 ;
        RECT 57.710 184.170 58.660 184.340 ;
        RECT 56.880 183.690 57.460 184.075 ;
        RECT 57.630 183.520 58.235 184.000 ;
        RECT 58.410 183.690 58.660 184.170 ;
        RECT 58.830 184.290 59.005 184.510 ;
        RECT 59.370 184.460 59.820 184.730 ;
        RECT 59.990 184.510 60.390 184.755 ;
        RECT 61.515 184.710 61.705 184.880 ;
        RECT 60.560 184.510 61.705 184.710 ;
        RECT 59.470 184.340 59.820 184.460 ;
        RECT 61.885 184.370 62.165 185.270 ;
        RECT 63.285 185.100 63.585 185.295 ;
        RECT 62.335 184.930 63.585 185.100 ;
        RECT 62.335 184.510 62.665 184.930 ;
        RECT 62.895 184.430 63.240 184.760 ;
        RECT 61.885 184.340 62.170 184.370 ;
        RECT 58.830 183.690 59.300 184.290 ;
        RECT 59.470 184.170 60.390 184.340 ;
        RECT 59.565 183.520 59.895 184.000 ;
        RECT 60.065 183.690 60.390 184.170 ;
        RECT 60.560 184.130 61.670 184.340 ;
        RECT 60.560 183.690 60.910 184.130 ;
        RECT 61.080 183.520 61.250 183.960 ;
        RECT 61.420 183.900 61.670 184.130 ;
        RECT 61.840 184.070 62.170 184.340 ;
        RECT 62.340 183.900 62.615 184.340 ;
        RECT 63.415 184.275 63.585 184.930 ;
        RECT 63.780 184.905 64.070 186.070 ;
        RECT 64.240 184.980 65.450 186.070 ;
        RECT 65.620 184.980 66.830 186.070 ;
        RECT 67.180 185.155 67.350 186.070 ;
        RECT 67.520 185.010 67.850 185.855 ;
        RECT 68.020 185.060 68.190 186.070 ;
        RECT 68.360 185.340 68.700 185.900 ;
        RECT 68.930 185.570 69.245 186.070 ;
        RECT 69.425 185.600 70.310 185.770 ;
        RECT 64.240 184.440 64.760 184.980 ;
        RECT 61.420 183.690 62.615 183.900 ;
        RECT 62.850 183.520 63.180 184.260 ;
        RECT 63.350 183.945 63.585 184.275 ;
        RECT 64.930 184.270 65.450 184.810 ;
        RECT 65.620 184.440 66.140 184.980 ;
        RECT 67.460 184.930 67.850 185.010 ;
        RECT 68.360 184.965 69.255 185.340 ;
        RECT 67.460 184.880 67.675 184.930 ;
        RECT 66.310 184.270 66.830 184.810 ;
        RECT 63.780 183.520 64.070 184.245 ;
        RECT 64.240 183.520 65.450 184.270 ;
        RECT 65.620 183.520 66.830 184.270 ;
        RECT 67.460 184.300 67.630 184.880 ;
        RECT 68.360 184.760 68.550 184.965 ;
        RECT 69.425 184.760 69.595 185.600 ;
        RECT 70.535 185.570 70.785 185.900 ;
        RECT 67.800 184.430 68.550 184.760 ;
        RECT 68.720 184.430 69.595 184.760 ;
        RECT 67.460 184.260 67.685 184.300 ;
        RECT 68.350 184.260 68.550 184.430 ;
        RECT 67.460 184.175 67.840 184.260 ;
        RECT 67.170 183.520 67.340 184.035 ;
        RECT 67.510 183.740 67.840 184.175 ;
        RECT 68.010 183.520 68.180 184.130 ;
        RECT 68.350 183.735 68.680 184.260 ;
        RECT 68.940 183.520 69.150 184.050 ;
        RECT 69.425 183.970 69.595 184.430 ;
        RECT 69.765 184.470 70.085 185.430 ;
        RECT 70.255 184.680 70.445 185.400 ;
        RECT 70.615 184.500 70.785 185.570 ;
        RECT 70.955 185.270 71.125 186.070 ;
        RECT 71.295 185.625 72.400 185.795 ;
        RECT 71.295 185.010 71.465 185.625 ;
        RECT 72.610 185.475 72.860 185.900 ;
        RECT 73.030 185.610 73.295 186.070 ;
        RECT 71.635 185.090 72.165 185.455 ;
        RECT 72.610 185.345 72.915 185.475 ;
        RECT 70.955 184.920 71.465 185.010 ;
        RECT 70.955 184.750 71.825 184.920 ;
        RECT 70.955 184.680 71.125 184.750 ;
        RECT 71.245 184.500 71.445 184.530 ;
        RECT 69.765 184.140 70.230 184.470 ;
        RECT 70.615 184.200 71.445 184.500 ;
        RECT 70.615 183.970 70.785 184.200 ;
        RECT 69.425 183.800 70.210 183.970 ;
        RECT 70.380 183.800 70.785 183.970 ;
        RECT 70.965 183.520 71.335 184.020 ;
        RECT 71.655 183.970 71.825 184.750 ;
        RECT 71.995 184.390 72.165 185.090 ;
        RECT 72.335 184.560 72.575 185.155 ;
        RECT 71.995 184.170 72.520 184.390 ;
        RECT 72.745 184.240 72.915 185.345 ;
        RECT 72.690 184.110 72.915 184.240 ;
        RECT 73.085 184.150 73.365 185.100 ;
        RECT 72.690 183.970 72.860 184.110 ;
        RECT 71.655 183.800 72.330 183.970 ;
        RECT 72.525 183.800 72.860 183.970 ;
        RECT 73.030 183.520 73.280 183.980 ;
        RECT 73.535 183.780 73.720 185.900 ;
        RECT 73.890 185.570 74.220 186.070 ;
        RECT 74.390 185.400 74.560 185.900 ;
        RECT 73.895 185.230 74.560 185.400 ;
        RECT 74.820 185.230 75.250 186.070 ;
        RECT 75.840 185.570 76.090 186.070 ;
        RECT 76.360 185.730 77.485 185.900 ;
        RECT 76.360 185.570 76.610 185.730 ;
        RECT 77.160 185.560 77.485 185.730 ;
        RECT 77.655 185.570 77.905 186.070 ;
        RECT 78.075 185.560 78.325 185.900 ;
        RECT 75.420 185.400 75.670 185.560 ;
        RECT 76.780 185.400 76.990 185.560 ;
        RECT 75.420 185.230 76.990 185.400 ;
        RECT 78.635 185.400 78.885 185.900 ;
        RECT 79.055 185.570 79.305 186.070 ;
        RECT 79.475 185.400 79.725 185.900 ;
        RECT 79.895 185.570 80.145 186.070 ;
        RECT 80.315 185.400 80.630 185.900 ;
        RECT 78.635 185.390 80.630 185.400 ;
        RECT 73.895 184.240 74.125 185.230 ;
        RECT 75.420 185.060 75.670 185.230 ;
        RECT 77.235 185.220 80.630 185.390 ;
        RECT 80.800 185.230 81.230 186.070 ;
        RECT 81.820 185.570 82.070 186.070 ;
        RECT 82.340 185.730 83.465 185.900 ;
        RECT 82.340 185.570 82.590 185.730 ;
        RECT 83.140 185.560 83.465 185.730 ;
        RECT 83.635 185.570 83.885 186.070 ;
        RECT 84.055 185.560 84.305 185.900 ;
        RECT 81.400 185.400 81.650 185.560 ;
        RECT 82.760 185.400 82.970 185.560 ;
        RECT 81.400 185.230 82.970 185.400 ;
        RECT 84.615 185.400 84.865 185.900 ;
        RECT 85.035 185.570 85.285 186.070 ;
        RECT 85.455 185.400 85.705 185.900 ;
        RECT 85.875 185.570 86.125 186.070 ;
        RECT 86.295 185.400 86.610 185.900 ;
        RECT 84.615 185.390 86.610 185.400 ;
        RECT 77.235 185.060 77.405 185.220 ;
        RECT 74.295 184.410 74.645 185.060 ;
        RECT 74.820 184.850 75.670 185.060 ;
        RECT 75.910 184.890 77.405 185.060 ;
        RECT 73.895 184.070 74.560 184.240 ;
        RECT 73.890 183.520 74.220 183.900 ;
        RECT 74.390 183.780 74.560 184.070 ;
        RECT 74.820 183.910 75.210 184.850 ;
        RECT 75.910 184.680 76.080 184.890 ;
        RECT 77.615 184.880 79.925 185.050 ;
        RECT 77.615 184.720 77.785 184.880 ;
        RECT 75.420 184.510 76.080 184.680 ;
        RECT 76.760 184.510 77.785 184.720 ;
        RECT 79.755 184.720 79.925 184.880 ;
        RECT 78.010 184.510 79.460 184.710 ;
        RECT 79.755 184.510 80.230 184.720 ;
        RECT 75.380 184.160 77.945 184.340 ;
        RECT 75.380 184.080 75.710 184.160 ;
        RECT 74.820 183.740 76.130 183.910 ;
        RECT 76.400 183.520 76.570 183.990 ;
        RECT 76.740 183.690 77.105 184.160 ;
        RECT 77.275 183.520 77.445 183.990 ;
        RECT 77.615 183.690 77.945 184.160 ;
        RECT 78.115 183.520 78.285 184.340 ;
        RECT 78.595 184.160 79.685 184.340 ;
        RECT 80.400 184.330 80.630 185.220 ;
        RECT 81.400 185.060 81.650 185.230 ;
        RECT 83.215 185.220 86.610 185.390 ;
        RECT 83.215 185.060 83.385 185.220 ;
        RECT 78.595 183.690 78.925 184.160 ;
        RECT 79.095 183.520 79.265 183.990 ;
        RECT 79.435 183.910 79.685 184.160 ;
        RECT 79.855 184.080 80.630 184.330 ;
        RECT 80.800 184.850 81.650 185.060 ;
        RECT 81.890 184.890 83.385 185.060 ;
        RECT 80.800 183.910 81.190 184.850 ;
        RECT 81.890 184.680 82.060 184.890 ;
        RECT 83.595 184.880 85.905 185.050 ;
        RECT 83.595 184.720 83.765 184.880 ;
        RECT 81.400 184.510 82.060 184.680 ;
        RECT 82.740 184.510 83.765 184.720 ;
        RECT 85.735 184.720 85.905 184.880 ;
        RECT 83.990 184.510 85.440 184.710 ;
        RECT 85.735 184.510 86.210 184.720 ;
        RECT 81.360 184.160 83.925 184.340 ;
        RECT 81.360 184.080 81.690 184.160 ;
        RECT 79.435 183.690 80.610 183.910 ;
        RECT 80.800 183.740 82.110 183.910 ;
        RECT 82.380 183.520 82.550 183.990 ;
        RECT 82.720 183.690 83.085 184.160 ;
        RECT 83.255 183.520 83.425 183.990 ;
        RECT 83.595 183.690 83.925 184.160 ;
        RECT 84.095 183.520 84.265 184.340 ;
        RECT 84.575 184.160 85.665 184.340 ;
        RECT 86.380 184.330 86.610 185.220 ;
        RECT 87.240 184.980 88.450 186.070 ;
        RECT 88.620 184.980 89.830 186.070 ;
        RECT 87.240 184.440 87.760 184.980 ;
        RECT 84.575 183.690 84.905 184.160 ;
        RECT 85.075 183.520 85.245 183.990 ;
        RECT 85.415 183.910 85.665 184.160 ;
        RECT 85.835 184.080 86.610 184.330 ;
        RECT 87.930 184.270 88.450 184.810 ;
        RECT 88.620 184.440 89.140 184.980 ;
        RECT 89.310 184.270 89.830 184.810 ;
        RECT 85.415 183.690 86.590 183.910 ;
        RECT 87.240 183.520 88.450 184.270 ;
        RECT 88.620 183.520 89.830 184.270 ;
        RECT 93.365 184.605 93.550 200.775 ;
        RECT 55.415 183.350 89.915 183.520 ;
        RECT 55.500 182.600 56.710 183.350 ;
        RECT 57.510 182.835 57.680 183.350 ;
        RECT 57.850 182.695 58.180 183.130 ;
        RECT 58.350 182.740 58.520 183.350 ;
        RECT 57.800 182.610 58.180 182.695 ;
        RECT 58.690 182.610 59.020 183.135 ;
        RECT 59.280 182.820 59.490 183.350 ;
        RECT 59.765 182.900 60.550 183.070 ;
        RECT 60.720 182.900 61.125 183.070 ;
        RECT 55.500 182.060 56.020 182.600 ;
        RECT 57.800 182.570 58.025 182.610 ;
        RECT 56.190 181.890 56.710 182.430 ;
        RECT 55.500 180.800 56.710 181.890 ;
        RECT 57.800 181.990 57.970 182.570 ;
        RECT 58.690 182.440 58.890 182.610 ;
        RECT 59.765 182.440 59.935 182.900 ;
        RECT 58.140 182.110 58.890 182.440 ;
        RECT 59.060 182.110 59.935 182.440 ;
        RECT 57.800 181.940 58.015 181.990 ;
        RECT 57.800 181.860 58.190 181.940 ;
        RECT 57.520 180.800 57.690 181.715 ;
        RECT 57.860 181.015 58.190 181.860 ;
        RECT 58.700 181.905 58.890 182.110 ;
        RECT 58.360 180.800 58.530 181.810 ;
        RECT 58.700 181.530 59.595 181.905 ;
        RECT 58.700 180.970 59.040 181.530 ;
        RECT 59.270 180.800 59.585 181.300 ;
        RECT 59.765 181.270 59.935 182.110 ;
        RECT 60.105 182.400 60.570 182.730 ;
        RECT 60.955 182.670 61.125 182.900 ;
        RECT 61.305 182.850 61.675 183.350 ;
        RECT 61.995 182.900 62.670 183.070 ;
        RECT 62.865 182.900 63.200 183.070 ;
        RECT 60.105 181.440 60.425 182.400 ;
        RECT 60.955 182.370 61.785 182.670 ;
        RECT 60.595 181.470 60.785 182.190 ;
        RECT 60.955 181.300 61.125 182.370 ;
        RECT 61.585 182.340 61.785 182.370 ;
        RECT 61.295 182.120 61.465 182.190 ;
        RECT 61.995 182.120 62.165 182.900 ;
        RECT 63.030 182.760 63.200 182.900 ;
        RECT 63.370 182.890 63.620 183.350 ;
        RECT 61.295 181.950 62.165 182.120 ;
        RECT 62.335 182.480 62.860 182.700 ;
        RECT 63.030 182.630 63.255 182.760 ;
        RECT 61.295 181.860 61.805 181.950 ;
        RECT 59.765 181.100 60.650 181.270 ;
        RECT 60.875 180.970 61.125 181.300 ;
        RECT 61.295 180.800 61.465 181.600 ;
        RECT 61.635 181.245 61.805 181.860 ;
        RECT 62.335 181.780 62.505 182.480 ;
        RECT 61.975 181.415 62.505 181.780 ;
        RECT 62.675 181.715 62.915 182.310 ;
        RECT 63.085 181.525 63.255 182.630 ;
        RECT 63.425 181.770 63.705 182.720 ;
        RECT 62.950 181.395 63.255 181.525 ;
        RECT 61.635 181.075 62.740 181.245 ;
        RECT 62.950 180.970 63.200 181.395 ;
        RECT 63.370 180.800 63.635 181.260 ;
        RECT 63.875 180.970 64.060 183.090 ;
        RECT 64.230 182.970 64.560 183.350 ;
        RECT 64.730 182.800 64.900 183.090 ;
        RECT 65.330 182.835 65.500 183.350 ;
        RECT 64.235 182.630 64.900 182.800 ;
        RECT 65.670 182.695 66.000 183.130 ;
        RECT 66.170 182.740 66.340 183.350 ;
        RECT 64.235 181.640 64.465 182.630 ;
        RECT 65.620 182.610 66.000 182.695 ;
        RECT 66.510 182.610 66.840 183.135 ;
        RECT 67.100 182.820 67.310 183.350 ;
        RECT 67.585 182.900 68.370 183.070 ;
        RECT 68.540 182.900 68.945 183.070 ;
        RECT 65.620 182.570 65.845 182.610 ;
        RECT 64.635 181.810 64.985 182.460 ;
        RECT 65.620 181.990 65.790 182.570 ;
        RECT 66.510 182.440 66.710 182.610 ;
        RECT 67.585 182.440 67.755 182.900 ;
        RECT 65.960 182.110 66.710 182.440 ;
        RECT 66.880 182.110 67.755 182.440 ;
        RECT 65.620 181.940 65.835 181.990 ;
        RECT 65.620 181.860 66.010 181.940 ;
        RECT 64.235 181.470 64.900 181.640 ;
        RECT 64.230 180.800 64.560 181.300 ;
        RECT 64.730 180.970 64.900 181.470 ;
        RECT 65.340 180.800 65.510 181.715 ;
        RECT 65.680 181.015 66.010 181.860 ;
        RECT 66.520 181.905 66.710 182.110 ;
        RECT 66.180 180.800 66.350 181.810 ;
        RECT 66.520 181.530 67.415 181.905 ;
        RECT 66.520 180.970 66.860 181.530 ;
        RECT 67.090 180.800 67.405 181.300 ;
        RECT 67.585 181.270 67.755 182.110 ;
        RECT 67.925 182.400 68.390 182.730 ;
        RECT 68.775 182.670 68.945 182.900 ;
        RECT 69.125 182.850 69.495 183.350 ;
        RECT 69.815 182.900 70.490 183.070 ;
        RECT 70.685 182.900 71.020 183.070 ;
        RECT 67.925 181.440 68.245 182.400 ;
        RECT 68.775 182.370 69.605 182.670 ;
        RECT 68.415 181.470 68.605 182.190 ;
        RECT 68.775 181.300 68.945 182.370 ;
        RECT 69.405 182.340 69.605 182.370 ;
        RECT 69.115 182.120 69.285 182.190 ;
        RECT 69.815 182.120 69.985 182.900 ;
        RECT 70.850 182.760 71.020 182.900 ;
        RECT 71.190 182.890 71.440 183.350 ;
        RECT 69.115 181.950 69.985 182.120 ;
        RECT 70.155 182.480 70.680 182.700 ;
        RECT 70.850 182.630 71.075 182.760 ;
        RECT 69.115 181.860 69.625 181.950 ;
        RECT 67.585 181.100 68.470 181.270 ;
        RECT 68.695 180.970 68.945 181.300 ;
        RECT 69.115 180.800 69.285 181.600 ;
        RECT 69.455 181.245 69.625 181.860 ;
        RECT 70.155 181.780 70.325 182.480 ;
        RECT 69.795 181.415 70.325 181.780 ;
        RECT 70.495 181.715 70.735 182.310 ;
        RECT 70.905 181.525 71.075 182.630 ;
        RECT 71.245 181.770 71.525 182.720 ;
        RECT 70.770 181.395 71.075 181.525 ;
        RECT 69.455 181.075 70.560 181.245 ;
        RECT 70.770 180.970 71.020 181.395 ;
        RECT 71.190 180.800 71.455 181.260 ;
        RECT 71.695 180.970 71.880 183.090 ;
        RECT 72.050 182.970 72.380 183.350 ;
        RECT 72.550 182.800 72.720 183.090 ;
        RECT 72.055 182.630 72.720 182.800 ;
        RECT 72.055 181.640 72.285 182.630 ;
        RECT 73.465 182.595 73.700 182.925 ;
        RECT 73.870 182.610 74.200 183.350 ;
        RECT 74.435 182.970 75.630 183.180 ;
        RECT 72.455 181.810 72.805 182.460 ;
        RECT 73.465 181.940 73.635 182.595 ;
        RECT 74.435 182.530 74.710 182.970 ;
        RECT 74.880 182.630 75.210 182.800 ;
        RECT 74.885 182.530 75.210 182.630 ;
        RECT 75.380 182.740 75.630 182.970 ;
        RECT 75.800 182.910 75.970 183.350 ;
        RECT 76.140 182.740 76.490 183.180 ;
        RECT 75.380 182.530 76.490 182.740 ;
        RECT 76.660 182.625 76.950 183.350 ;
        RECT 77.180 182.530 77.390 183.350 ;
        RECT 77.560 182.550 77.890 183.180 ;
        RECT 73.810 182.110 74.155 182.440 ;
        RECT 74.385 181.940 74.715 182.360 ;
        RECT 73.465 181.770 74.715 181.940 ;
        RECT 72.055 181.470 72.720 181.640 ;
        RECT 73.465 181.575 73.765 181.770 ;
        RECT 74.885 181.650 75.165 182.530 ;
        RECT 75.345 182.330 76.490 182.360 ;
        RECT 75.340 182.160 76.490 182.330 ;
        RECT 75.345 181.780 75.535 182.160 ;
        RECT 74.880 181.600 75.165 181.650 ;
        RECT 75.715 181.600 75.990 181.940 ;
        RECT 72.050 180.800 72.380 181.300 ;
        RECT 72.550 180.970 72.720 181.470 ;
        RECT 73.935 180.800 74.190 181.600 ;
        RECT 74.390 181.430 75.990 181.600 ;
        RECT 74.390 180.970 74.720 181.430 ;
        RECT 74.890 180.800 75.465 181.260 ;
        RECT 75.635 180.970 75.990 181.430 ;
        RECT 76.160 180.800 76.490 181.940 ;
        RECT 76.660 180.800 76.950 181.965 ;
        RECT 77.560 181.950 77.810 182.550 ;
        RECT 78.060 182.530 78.290 183.350 ;
        RECT 78.670 182.835 78.840 183.350 ;
        RECT 79.010 182.695 79.340 183.130 ;
        RECT 79.510 182.740 79.680 183.350 ;
        RECT 78.960 182.610 79.340 182.695 ;
        RECT 79.850 182.610 80.180 183.135 ;
        RECT 80.440 182.820 80.650 183.350 ;
        RECT 80.925 182.900 81.710 183.070 ;
        RECT 81.880 182.900 82.285 183.070 ;
        RECT 78.960 182.570 79.185 182.610 ;
        RECT 77.980 182.110 78.310 182.360 ;
        RECT 78.960 181.990 79.130 182.570 ;
        RECT 79.850 182.440 80.050 182.610 ;
        RECT 80.925 182.440 81.095 182.900 ;
        RECT 79.300 182.110 80.050 182.440 ;
        RECT 80.220 182.110 81.095 182.440 ;
        RECT 77.180 180.800 77.390 181.940 ;
        RECT 77.560 180.970 77.890 181.950 ;
        RECT 78.960 181.940 79.175 181.990 ;
        RECT 78.060 180.800 78.290 181.940 ;
        RECT 78.960 181.860 79.350 181.940 ;
        RECT 78.680 180.800 78.850 181.715 ;
        RECT 79.020 181.015 79.350 181.860 ;
        RECT 79.860 181.905 80.050 182.110 ;
        RECT 79.520 180.800 79.690 181.810 ;
        RECT 79.860 181.530 80.755 181.905 ;
        RECT 79.860 180.970 80.200 181.530 ;
        RECT 80.430 180.800 80.745 181.300 ;
        RECT 80.925 181.270 81.095 182.110 ;
        RECT 81.265 182.400 81.730 182.730 ;
        RECT 82.115 182.670 82.285 182.900 ;
        RECT 82.465 182.850 82.835 183.350 ;
        RECT 83.155 182.900 83.830 183.070 ;
        RECT 84.025 182.900 84.360 183.070 ;
        RECT 81.265 181.440 81.585 182.400 ;
        RECT 82.115 182.370 82.945 182.670 ;
        RECT 81.755 181.470 81.945 182.190 ;
        RECT 82.115 181.300 82.285 182.370 ;
        RECT 82.745 182.340 82.945 182.370 ;
        RECT 82.455 182.120 82.625 182.190 ;
        RECT 83.155 182.120 83.325 182.900 ;
        RECT 84.190 182.760 84.360 182.900 ;
        RECT 84.530 182.890 84.780 183.350 ;
        RECT 82.455 181.950 83.325 182.120 ;
        RECT 83.495 182.480 84.020 182.700 ;
        RECT 84.190 182.630 84.415 182.760 ;
        RECT 82.455 181.860 82.965 181.950 ;
        RECT 80.925 181.100 81.810 181.270 ;
        RECT 82.035 180.970 82.285 181.300 ;
        RECT 82.455 180.800 82.625 181.600 ;
        RECT 82.795 181.245 82.965 181.860 ;
        RECT 83.495 181.780 83.665 182.480 ;
        RECT 83.135 181.415 83.665 181.780 ;
        RECT 83.835 181.715 84.075 182.310 ;
        RECT 84.245 181.525 84.415 182.630 ;
        RECT 84.585 181.770 84.865 182.720 ;
        RECT 84.110 181.395 84.415 181.525 ;
        RECT 82.795 181.075 83.900 181.245 ;
        RECT 84.110 180.970 84.360 181.395 ;
        RECT 84.530 180.800 84.795 181.260 ;
        RECT 85.035 180.970 85.220 183.090 ;
        RECT 85.390 182.970 85.720 183.350 ;
        RECT 85.890 182.800 86.060 183.090 ;
        RECT 85.395 182.630 86.060 182.800 ;
        RECT 85.395 181.640 85.625 182.630 ;
        RECT 86.360 182.530 86.590 183.350 ;
        RECT 86.760 182.550 87.090 183.180 ;
        RECT 85.795 181.810 86.145 182.460 ;
        RECT 86.340 182.110 86.670 182.360 ;
        RECT 86.840 181.950 87.090 182.550 ;
        RECT 87.260 182.530 87.470 183.350 ;
        RECT 88.620 182.600 89.830 183.350 ;
        RECT 93.365 183.160 93.535 184.605 ;
        RECT 94.495 182.800 94.665 201.860 ;
        RECT 95.250 201.370 96.100 201.600 ;
        RECT 96.910 201.370 97.760 201.600 ;
        RECT 95.025 200.515 95.195 201.160 ;
        RECT 95.005 190.465 95.195 200.515 ;
        RECT 95.025 183.160 95.195 190.465 ;
        RECT 96.155 183.160 96.855 201.160 ;
        RECT 97.815 200.515 97.985 201.160 ;
        RECT 97.815 190.465 98.025 200.515 ;
        RECT 97.815 183.160 97.985 190.465 ;
        RECT 98.345 182.800 98.515 201.860 ;
        RECT 99.475 200.640 99.645 201.860 ;
        RECT 99.445 184.470 99.645 200.640 ;
        RECT 99.475 183.160 99.645 184.470 ;
        RECT 100.605 182.800 100.775 201.860 ;
        RECT 101.735 183.160 101.905 202.070 ;
        RECT 102.865 182.800 103.035 201.860 ;
        RECT 103.635 185.465 103.805 202.630 ;
        RECT 105.165 185.305 105.335 201.865 ;
        RECT 103.995 184.975 105.335 185.305 ;
        RECT 85.395 181.470 86.060 181.640 ;
        RECT 85.390 180.800 85.720 181.300 ;
        RECT 85.890 180.970 86.060 181.470 ;
        RECT 86.360 180.800 86.590 181.940 ;
        RECT 86.760 180.970 87.090 181.950 ;
        RECT 87.260 180.800 87.470 181.940 ;
        RECT 88.620 181.890 89.140 182.430 ;
        RECT 89.310 182.060 89.830 182.600 ;
        RECT 93.345 181.910 103.035 182.800 ;
        RECT 88.620 180.800 89.830 181.890 ;
        RECT 55.415 180.630 89.915 180.800 ;
        RECT 55.500 179.540 56.710 180.630 ;
        RECT 55.500 178.830 56.020 179.370 ;
        RECT 56.190 179.000 56.710 179.540 ;
        RECT 56.880 179.560 57.440 180.460 ;
        RECT 57.630 179.830 58.240 180.630 ;
        RECT 58.410 179.660 58.660 180.460 ;
        RECT 55.500 178.080 56.710 178.830 ;
        RECT 56.880 178.635 57.245 179.560 ;
        RECT 57.710 179.490 58.660 179.660 ;
        RECT 58.830 179.785 59.280 180.460 ;
        RECT 59.550 179.825 59.875 180.630 ;
        RECT 57.710 179.320 57.880 179.490 ;
        RECT 57.425 178.985 57.880 179.320 ;
        RECT 58.830 179.245 59.005 179.785 ;
        RECT 60.045 179.655 60.390 180.460 ;
        RECT 59.470 179.485 60.390 179.655 ;
        RECT 60.560 179.490 60.890 180.630 ;
        RECT 61.060 180.000 61.415 180.460 ;
        RECT 61.585 180.170 62.160 180.630 ;
        RECT 62.330 180.000 62.660 180.460 ;
        RECT 61.060 179.830 62.660 180.000 ;
        RECT 62.860 179.830 63.115 180.630 ;
        RECT 61.060 179.490 61.335 179.830 ;
        RECT 61.515 179.610 61.705 179.650 ;
        RECT 59.470 179.290 59.820 179.485 ;
        RECT 61.515 179.440 61.710 179.610 ;
        RECT 58.055 179.070 59.005 179.245 ;
        RECT 57.710 178.900 57.880 178.985 ;
        RECT 57.710 178.730 58.660 178.900 ;
        RECT 56.880 178.250 57.460 178.635 ;
        RECT 57.630 178.080 58.235 178.560 ;
        RECT 58.410 178.250 58.660 178.730 ;
        RECT 58.830 178.850 59.005 179.070 ;
        RECT 59.370 179.020 59.820 179.290 ;
        RECT 59.990 179.070 60.390 179.315 ;
        RECT 61.515 179.270 61.705 179.440 ;
        RECT 60.560 179.070 61.705 179.270 ;
        RECT 59.470 178.900 59.820 179.020 ;
        RECT 61.885 178.900 62.165 179.830 ;
        RECT 63.285 179.660 63.585 179.855 ;
        RECT 62.335 179.490 63.585 179.660 ;
        RECT 62.335 179.070 62.665 179.490 ;
        RECT 62.895 178.990 63.240 179.320 ;
        RECT 58.830 178.250 59.300 178.850 ;
        RECT 59.470 178.730 60.390 178.900 ;
        RECT 59.565 178.080 59.895 178.560 ;
        RECT 60.065 178.250 60.390 178.730 ;
        RECT 60.560 178.690 61.670 178.900 ;
        RECT 60.560 178.250 60.910 178.690 ;
        RECT 61.080 178.080 61.250 178.520 ;
        RECT 61.420 178.460 61.670 178.690 ;
        RECT 61.840 178.800 62.165 178.900 ;
        RECT 61.840 178.630 62.170 178.800 ;
        RECT 62.340 178.460 62.615 178.900 ;
        RECT 63.415 178.835 63.585 179.490 ;
        RECT 63.780 179.465 64.070 180.630 ;
        RECT 64.420 179.715 64.590 180.630 ;
        RECT 64.760 179.570 65.090 180.415 ;
        RECT 65.260 179.620 65.430 180.630 ;
        RECT 65.600 179.900 65.940 180.460 ;
        RECT 66.170 180.130 66.485 180.630 ;
        RECT 66.665 180.160 67.550 180.330 ;
        RECT 64.700 179.490 65.090 179.570 ;
        RECT 65.600 179.525 66.495 179.900 ;
        RECT 61.420 178.250 62.615 178.460 ;
        RECT 62.850 178.080 63.180 178.820 ;
        RECT 63.350 178.505 63.585 178.835 ;
        RECT 64.700 179.440 64.915 179.490 ;
        RECT 64.700 178.860 64.870 179.440 ;
        RECT 65.600 179.320 65.790 179.525 ;
        RECT 66.665 179.320 66.835 180.160 ;
        RECT 67.775 180.130 68.025 180.460 ;
        RECT 65.040 178.990 65.790 179.320 ;
        RECT 65.960 178.990 66.835 179.320 ;
        RECT 64.700 178.820 64.925 178.860 ;
        RECT 65.590 178.820 65.790 178.990 ;
        RECT 63.780 178.080 64.070 178.805 ;
        RECT 64.700 178.735 65.080 178.820 ;
        RECT 64.410 178.080 64.580 178.595 ;
        RECT 64.750 178.300 65.080 178.735 ;
        RECT 65.250 178.080 65.420 178.690 ;
        RECT 65.590 178.295 65.920 178.820 ;
        RECT 66.180 178.080 66.390 178.610 ;
        RECT 66.665 178.530 66.835 178.990 ;
        RECT 67.005 179.030 67.325 179.990 ;
        RECT 67.495 179.240 67.685 179.960 ;
        RECT 67.855 179.060 68.025 180.130 ;
        RECT 68.195 179.830 68.365 180.630 ;
        RECT 68.535 180.185 69.640 180.355 ;
        RECT 68.535 179.570 68.705 180.185 ;
        RECT 69.850 180.035 70.100 180.460 ;
        RECT 70.270 180.170 70.535 180.630 ;
        RECT 68.875 179.650 69.405 180.015 ;
        RECT 69.850 179.905 70.155 180.035 ;
        RECT 68.195 179.480 68.705 179.570 ;
        RECT 68.195 179.310 69.065 179.480 ;
        RECT 68.195 179.240 68.365 179.310 ;
        RECT 68.485 179.060 68.685 179.090 ;
        RECT 67.005 178.700 67.470 179.030 ;
        RECT 67.855 178.760 68.685 179.060 ;
        RECT 67.855 178.530 68.025 178.760 ;
        RECT 66.665 178.360 67.450 178.530 ;
        RECT 67.620 178.360 68.025 178.530 ;
        RECT 68.205 178.080 68.575 178.580 ;
        RECT 68.895 178.530 69.065 179.310 ;
        RECT 69.235 178.950 69.405 179.650 ;
        RECT 69.575 179.120 69.815 179.715 ;
        RECT 69.235 178.730 69.760 178.950 ;
        RECT 69.985 178.800 70.155 179.905 ;
        RECT 69.930 178.670 70.155 178.800 ;
        RECT 70.325 178.710 70.605 179.660 ;
        RECT 69.930 178.530 70.100 178.670 ;
        RECT 68.895 178.360 69.570 178.530 ;
        RECT 69.765 178.360 70.100 178.530 ;
        RECT 70.270 178.080 70.520 178.540 ;
        RECT 70.775 178.340 70.960 180.460 ;
        RECT 71.130 180.130 71.460 180.630 ;
        RECT 71.630 179.960 71.800 180.460 ;
        RECT 71.135 179.790 71.800 179.960 ;
        RECT 71.135 178.800 71.365 179.790 ;
        RECT 72.980 179.660 73.270 180.460 ;
        RECT 73.440 179.830 73.675 180.630 ;
        RECT 73.860 180.290 75.395 180.460 ;
        RECT 73.860 179.660 74.190 180.290 ;
        RECT 71.535 178.970 71.885 179.620 ;
        RECT 72.980 179.490 74.190 179.660 ;
        RECT 72.980 178.990 73.225 179.320 ;
        RECT 73.395 178.820 73.565 179.490 ;
        RECT 74.360 179.320 74.595 180.065 ;
        RECT 73.735 178.990 74.135 179.320 ;
        RECT 74.305 178.990 74.595 179.320 ;
        RECT 74.785 179.320 75.055 180.065 ;
        RECT 75.225 179.660 75.395 180.290 ;
        RECT 75.565 179.830 75.960 180.630 ;
        RECT 75.225 179.490 75.960 179.660 ;
        RECT 74.785 178.990 75.115 179.320 ;
        RECT 75.285 178.990 75.620 179.320 ;
        RECT 75.790 178.990 75.960 179.490 ;
        RECT 76.130 179.310 76.485 180.460 ;
        RECT 76.655 179.480 76.950 180.630 ;
        RECT 77.300 179.715 77.470 180.630 ;
        RECT 77.640 179.570 77.970 180.415 ;
        RECT 78.140 179.620 78.310 180.630 ;
        RECT 78.480 179.900 78.820 180.460 ;
        RECT 79.050 180.130 79.365 180.630 ;
        RECT 79.545 180.160 80.430 180.330 ;
        RECT 77.580 179.490 77.970 179.570 ;
        RECT 78.480 179.525 79.375 179.900 ;
        RECT 77.580 179.440 77.795 179.490 ;
        RECT 76.130 179.050 76.950 179.310 ;
        RECT 76.130 178.990 76.485 179.050 ;
        RECT 71.135 178.630 71.800 178.800 ;
        RECT 71.130 178.080 71.460 178.460 ;
        RECT 71.630 178.340 71.800 178.630 ;
        RECT 72.980 178.250 73.565 178.820 ;
        RECT 73.815 178.650 75.200 178.820 ;
        RECT 73.815 178.305 74.145 178.650 ;
        RECT 74.360 178.080 74.735 178.480 ;
        RECT 74.915 178.305 75.200 178.650 ;
        RECT 75.370 178.080 76.040 178.820 ;
        RECT 76.210 178.250 76.485 178.990 ;
        RECT 76.655 178.080 76.950 178.880 ;
        RECT 77.580 178.860 77.750 179.440 ;
        RECT 78.480 179.320 78.670 179.525 ;
        RECT 79.545 179.320 79.715 180.160 ;
        RECT 80.655 180.130 80.905 180.460 ;
        RECT 77.920 178.990 78.670 179.320 ;
        RECT 78.840 178.990 79.715 179.320 ;
        RECT 77.580 178.820 77.805 178.860 ;
        RECT 78.470 178.820 78.670 178.990 ;
        RECT 77.580 178.735 77.960 178.820 ;
        RECT 77.290 178.080 77.460 178.595 ;
        RECT 77.630 178.300 77.960 178.735 ;
        RECT 78.130 178.080 78.300 178.690 ;
        RECT 78.470 178.295 78.800 178.820 ;
        RECT 79.060 178.080 79.270 178.610 ;
        RECT 79.545 178.530 79.715 178.990 ;
        RECT 79.885 179.030 80.205 179.990 ;
        RECT 80.375 179.240 80.565 179.960 ;
        RECT 80.735 179.060 80.905 180.130 ;
        RECT 81.075 179.830 81.245 180.630 ;
        RECT 81.415 180.185 82.520 180.355 ;
        RECT 81.415 179.570 81.585 180.185 ;
        RECT 82.730 180.035 82.980 180.460 ;
        RECT 83.150 180.170 83.415 180.630 ;
        RECT 81.755 179.650 82.285 180.015 ;
        RECT 82.730 179.905 83.035 180.035 ;
        RECT 81.075 179.480 81.585 179.570 ;
        RECT 81.075 179.310 81.945 179.480 ;
        RECT 81.075 179.240 81.245 179.310 ;
        RECT 81.365 179.060 81.565 179.090 ;
        RECT 79.885 178.700 80.350 179.030 ;
        RECT 80.735 178.760 81.565 179.060 ;
        RECT 80.735 178.530 80.905 178.760 ;
        RECT 79.545 178.360 80.330 178.530 ;
        RECT 80.500 178.360 80.905 178.530 ;
        RECT 81.085 178.080 81.455 178.580 ;
        RECT 81.775 178.530 81.945 179.310 ;
        RECT 82.115 178.950 82.285 179.650 ;
        RECT 82.455 179.120 82.695 179.715 ;
        RECT 82.115 178.730 82.640 178.950 ;
        RECT 82.865 178.800 83.035 179.905 ;
        RECT 82.810 178.670 83.035 178.800 ;
        RECT 83.205 178.710 83.485 179.660 ;
        RECT 82.810 178.530 82.980 178.670 ;
        RECT 81.775 178.360 82.450 178.530 ;
        RECT 82.645 178.360 82.980 178.530 ;
        RECT 83.150 178.080 83.400 178.540 ;
        RECT 83.655 178.340 83.840 180.460 ;
        RECT 84.010 180.130 84.340 180.630 ;
        RECT 84.510 179.960 84.680 180.460 ;
        RECT 84.015 179.790 84.680 179.960 ;
        RECT 84.015 178.800 84.245 179.790 ;
        RECT 84.940 179.655 85.285 180.460 ;
        RECT 85.455 179.825 85.780 180.630 ;
        RECT 86.050 179.785 86.500 180.460 ;
        RECT 84.415 178.970 84.765 179.620 ;
        RECT 84.940 179.485 85.860 179.655 ;
        RECT 84.940 179.070 85.340 179.315 ;
        RECT 85.510 179.290 85.860 179.485 ;
        RECT 85.510 179.020 85.960 179.290 ;
        RECT 86.325 179.245 86.500 179.785 ;
        RECT 86.670 179.660 86.920 180.460 ;
        RECT 87.090 179.830 87.700 180.630 ;
        RECT 86.670 179.490 87.620 179.660 ;
        RECT 87.890 179.560 88.450 180.460 ;
        RECT 87.450 179.320 87.620 179.490 ;
        RECT 86.325 179.070 87.275 179.245 ;
        RECT 85.510 178.900 85.860 179.020 ;
        RECT 84.015 178.630 84.680 178.800 ;
        RECT 84.010 178.080 84.340 178.460 ;
        RECT 84.510 178.340 84.680 178.630 ;
        RECT 84.940 178.730 85.860 178.900 ;
        RECT 86.325 178.850 86.500 179.070 ;
        RECT 87.450 178.985 87.905 179.320 ;
        RECT 87.450 178.900 87.620 178.985 ;
        RECT 84.940 178.250 85.265 178.730 ;
        RECT 85.435 178.080 85.765 178.560 ;
        RECT 86.030 178.250 86.500 178.850 ;
        RECT 86.670 178.730 87.620 178.900 ;
        RECT 86.670 178.250 86.920 178.730 ;
        RECT 88.085 178.635 88.450 179.560 ;
        RECT 88.620 179.540 89.830 180.630 ;
        RECT 88.620 179.000 89.140 179.540 ;
        RECT 89.310 178.830 89.830 179.370 ;
        RECT 87.095 178.080 87.700 178.560 ;
        RECT 87.870 178.250 88.450 178.635 ;
        RECT 88.620 178.080 89.830 178.830 ;
        RECT 55.415 177.910 89.915 178.080 ;
        RECT 55.500 177.160 56.710 177.910 ;
        RECT 57.510 177.395 57.680 177.910 ;
        RECT 57.850 177.255 58.180 177.690 ;
        RECT 58.350 177.300 58.520 177.910 ;
        RECT 57.800 177.170 58.180 177.255 ;
        RECT 58.690 177.170 59.020 177.695 ;
        RECT 59.280 177.380 59.490 177.910 ;
        RECT 59.765 177.460 60.550 177.630 ;
        RECT 60.720 177.460 61.125 177.630 ;
        RECT 55.500 176.620 56.020 177.160 ;
        RECT 57.800 177.130 58.025 177.170 ;
        RECT 56.190 176.450 56.710 176.990 ;
        RECT 55.500 175.360 56.710 176.450 ;
        RECT 57.800 176.550 57.970 177.130 ;
        RECT 58.690 177.000 58.890 177.170 ;
        RECT 59.765 177.000 59.935 177.460 ;
        RECT 58.140 176.670 58.890 177.000 ;
        RECT 59.060 176.670 59.935 177.000 ;
        RECT 57.800 176.500 58.015 176.550 ;
        RECT 57.800 176.420 58.190 176.500 ;
        RECT 57.520 175.360 57.690 176.275 ;
        RECT 57.860 175.575 58.190 176.420 ;
        RECT 58.700 176.465 58.890 176.670 ;
        RECT 58.360 175.360 58.530 176.370 ;
        RECT 58.700 176.090 59.595 176.465 ;
        RECT 58.700 175.530 59.040 176.090 ;
        RECT 59.270 175.360 59.585 175.860 ;
        RECT 59.765 175.830 59.935 176.670 ;
        RECT 60.105 176.960 60.570 177.290 ;
        RECT 60.955 177.230 61.125 177.460 ;
        RECT 61.305 177.410 61.675 177.910 ;
        RECT 61.995 177.460 62.670 177.630 ;
        RECT 62.865 177.460 63.200 177.630 ;
        RECT 60.105 176.000 60.425 176.960 ;
        RECT 60.955 176.930 61.785 177.230 ;
        RECT 60.595 176.030 60.785 176.750 ;
        RECT 60.955 175.860 61.125 176.930 ;
        RECT 61.585 176.900 61.785 176.930 ;
        RECT 61.295 176.680 61.465 176.750 ;
        RECT 61.995 176.680 62.165 177.460 ;
        RECT 63.030 177.320 63.200 177.460 ;
        RECT 63.370 177.450 63.620 177.910 ;
        RECT 61.295 176.510 62.165 176.680 ;
        RECT 62.335 177.040 62.860 177.260 ;
        RECT 63.030 177.190 63.255 177.320 ;
        RECT 61.295 176.420 61.805 176.510 ;
        RECT 59.765 175.660 60.650 175.830 ;
        RECT 60.875 175.530 61.125 175.860 ;
        RECT 61.295 175.360 61.465 176.160 ;
        RECT 61.635 175.805 61.805 176.420 ;
        RECT 62.335 176.340 62.505 177.040 ;
        RECT 61.975 175.975 62.505 176.340 ;
        RECT 62.675 176.275 62.915 176.870 ;
        RECT 63.085 176.085 63.255 177.190 ;
        RECT 63.425 176.330 63.705 177.280 ;
        RECT 62.950 175.955 63.255 176.085 ;
        RECT 61.635 175.635 62.740 175.805 ;
        RECT 62.950 175.530 63.200 175.955 ;
        RECT 63.370 175.360 63.635 175.820 ;
        RECT 63.875 175.530 64.060 177.650 ;
        RECT 64.230 177.530 64.560 177.910 ;
        RECT 64.730 177.360 64.900 177.650 ;
        RECT 65.265 177.440 65.435 177.910 ;
        RECT 64.235 177.190 64.900 177.360 ;
        RECT 65.605 177.270 65.935 177.740 ;
        RECT 66.105 177.440 66.275 177.910 ;
        RECT 66.445 177.270 66.775 177.740 ;
        RECT 66.945 177.440 67.115 177.910 ;
        RECT 64.235 176.200 64.465 177.190 ;
        RECT 65.195 177.090 66.775 177.270 ;
        RECT 67.385 177.270 67.715 177.740 ;
        RECT 67.885 177.440 68.055 177.910 ;
        RECT 68.225 177.520 69.455 177.740 ;
        RECT 68.225 177.270 68.475 177.520 ;
        RECT 69.720 177.440 69.890 177.910 ;
        RECT 70.560 177.440 70.730 177.910 ;
        RECT 67.385 177.090 68.475 177.270 ;
        RECT 68.700 177.270 69.030 177.350 ;
        RECT 70.060 177.270 70.390 177.350 ;
        RECT 68.700 177.090 70.970 177.270 ;
        RECT 72.060 177.160 73.270 177.910 ;
        RECT 64.635 176.370 64.985 177.020 ;
        RECT 65.195 176.210 65.365 177.090 ;
        RECT 69.360 177.060 69.530 177.090 ;
        RECT 65.620 176.720 65.950 176.920 ;
        RECT 66.120 176.720 66.615 176.920 ;
        RECT 66.785 176.720 68.305 176.920 ;
        RECT 68.495 176.720 69.165 176.920 ;
        RECT 69.690 176.750 70.350 176.920 ;
        RECT 65.780 176.550 65.950 176.720 ;
        RECT 66.785 176.550 66.955 176.720 ;
        RECT 69.690 176.550 69.860 176.750 ;
        RECT 70.560 176.580 70.970 177.090 ;
        RECT 65.780 176.380 66.955 176.550 ;
        RECT 67.125 176.380 69.860 176.550 ;
        RECT 67.125 176.210 67.295 176.380 ;
        RECT 70.100 176.370 70.970 176.580 ;
        RECT 72.060 176.450 72.580 176.990 ;
        RECT 72.750 176.620 73.270 177.160 ;
        RECT 73.465 177.155 73.700 177.485 ;
        RECT 73.870 177.170 74.200 177.910 ;
        RECT 74.435 177.530 75.630 177.740 ;
        RECT 73.465 176.500 73.635 177.155 ;
        RECT 74.435 177.090 74.710 177.530 ;
        RECT 74.880 177.190 75.210 177.360 ;
        RECT 74.885 177.090 75.210 177.190 ;
        RECT 75.380 177.300 75.630 177.530 ;
        RECT 75.800 177.470 75.970 177.910 ;
        RECT 76.140 177.300 76.490 177.740 ;
        RECT 75.380 177.090 76.490 177.300 ;
        RECT 76.660 177.185 76.950 177.910 ;
        RECT 78.040 177.160 79.250 177.910 ;
        RECT 73.810 176.670 74.155 177.000 ;
        RECT 74.385 176.500 74.715 176.920 ;
        RECT 64.235 176.030 64.900 176.200 ;
        RECT 65.195 176.040 67.295 176.210 ;
        RECT 67.465 176.040 69.930 176.210 ;
        RECT 64.230 175.360 64.560 175.860 ;
        RECT 64.730 175.530 64.900 176.030 ;
        RECT 66.485 175.870 66.735 176.040 ;
        RECT 67.465 175.870 67.675 176.040 ;
        RECT 65.220 175.860 65.390 175.870 ;
        RECT 66.140 175.860 66.310 175.870 ;
        RECT 65.195 175.530 65.475 175.860 ;
        RECT 65.645 175.360 65.895 175.860 ;
        RECT 66.065 175.700 66.315 175.860 ;
        RECT 66.905 175.700 67.155 175.860 ;
        RECT 66.065 175.530 67.155 175.700 ;
        RECT 67.360 175.530 67.675 175.870 ;
        RECT 67.845 175.360 68.095 175.860 ;
        RECT 68.265 175.530 68.515 176.040 ;
        RECT 68.685 175.360 68.990 175.860 ;
        RECT 69.160 175.700 69.930 176.040 ;
        RECT 70.100 175.870 70.350 176.370 ;
        RECT 70.520 175.700 70.770 176.200 ;
        RECT 69.160 175.530 70.770 175.700 ;
        RECT 72.060 175.360 73.270 176.450 ;
        RECT 73.465 176.330 74.715 176.500 ;
        RECT 73.465 176.135 73.765 176.330 ;
        RECT 74.885 176.160 75.165 177.090 ;
        RECT 75.345 176.720 76.490 176.920 ;
        RECT 75.345 176.550 75.535 176.720 ;
        RECT 75.340 176.380 75.535 176.550 ;
        RECT 75.345 176.340 75.535 176.380 ;
        RECT 75.715 176.160 75.990 176.500 ;
        RECT 73.935 175.360 74.190 176.160 ;
        RECT 74.390 175.990 75.990 176.160 ;
        RECT 74.390 175.530 74.720 175.990 ;
        RECT 74.890 175.360 75.465 175.820 ;
        RECT 75.635 175.530 75.990 175.990 ;
        RECT 76.160 175.360 76.490 176.500 ;
        RECT 76.660 175.360 76.950 176.525 ;
        RECT 78.040 176.450 78.560 176.990 ;
        RECT 78.730 176.620 79.250 177.160 ;
        RECT 79.535 177.280 79.820 177.740 ;
        RECT 79.990 177.450 80.260 177.910 ;
        RECT 79.535 177.110 80.490 177.280 ;
        RECT 78.040 175.360 79.250 176.450 ;
        RECT 79.420 176.380 80.110 176.940 ;
        RECT 80.280 176.210 80.490 177.110 ;
        RECT 79.535 175.990 80.490 176.210 ;
        RECT 80.660 176.940 81.060 177.740 ;
        RECT 81.250 177.280 81.530 177.740 ;
        RECT 82.050 177.450 82.375 177.910 ;
        RECT 81.250 177.110 82.375 177.280 ;
        RECT 82.545 177.170 82.930 177.740 ;
        RECT 81.925 177.000 82.375 177.110 ;
        RECT 80.660 176.380 81.755 176.940 ;
        RECT 81.925 176.670 82.480 177.000 ;
        RECT 79.535 175.530 79.820 175.990 ;
        RECT 79.990 175.360 80.260 175.820 ;
        RECT 80.660 175.530 81.060 176.380 ;
        RECT 81.925 176.210 82.375 176.670 ;
        RECT 82.650 176.500 82.930 177.170 ;
        RECT 83.560 177.160 84.770 177.910 ;
        RECT 81.250 175.990 82.375 176.210 ;
        RECT 81.250 175.530 81.530 175.990 ;
        RECT 82.050 175.360 82.375 175.820 ;
        RECT 82.545 175.530 82.930 176.500 ;
        RECT 83.560 176.450 84.080 176.990 ;
        RECT 84.250 176.620 84.770 177.160 ;
        RECT 84.940 177.260 85.265 177.740 ;
        RECT 85.435 177.430 85.765 177.910 ;
        RECT 84.940 177.090 85.860 177.260 ;
        RECT 86.030 177.140 86.500 177.740 ;
        RECT 85.510 176.970 85.860 177.090 ;
        RECT 84.940 176.675 85.340 176.920 ;
        RECT 85.510 176.700 85.960 176.970 ;
        RECT 86.325 176.920 86.500 177.140 ;
        RECT 86.670 177.260 86.920 177.740 ;
        RECT 87.095 177.430 87.700 177.910 ;
        RECT 87.870 177.355 88.450 177.740 ;
        RECT 86.670 177.090 87.620 177.260 ;
        RECT 87.450 177.005 87.620 177.090 ;
        RECT 86.325 176.745 87.275 176.920 ;
        RECT 85.510 176.505 85.860 176.700 ;
        RECT 83.560 175.360 84.770 176.450 ;
        RECT 84.940 176.335 85.860 176.505 ;
        RECT 84.940 175.530 85.285 176.335 ;
        RECT 86.325 176.205 86.500 176.745 ;
        RECT 87.450 176.670 87.905 177.005 ;
        RECT 87.450 176.500 87.620 176.670 ;
        RECT 85.455 175.360 85.780 176.165 ;
        RECT 86.050 175.530 86.500 176.205 ;
        RECT 86.670 176.330 87.620 176.500 ;
        RECT 88.085 176.430 88.450 177.355 ;
        RECT 88.620 177.160 89.830 177.910 ;
        RECT 86.670 175.530 86.920 176.330 ;
        RECT 87.090 175.360 87.700 176.160 ;
        RECT 87.890 175.530 88.450 176.430 ;
        RECT 88.620 176.450 89.140 176.990 ;
        RECT 89.310 176.620 89.830 177.160 ;
        RECT 88.620 175.360 89.830 176.450 ;
        RECT 55.415 175.190 89.915 175.360 ;
        RECT 55.500 174.100 56.710 175.190 ;
        RECT 55.500 173.390 56.020 173.930 ;
        RECT 56.190 173.560 56.710 174.100 ;
        RECT 56.880 174.120 57.440 175.020 ;
        RECT 57.630 174.390 58.240 175.190 ;
        RECT 58.410 174.220 58.660 175.020 ;
        RECT 55.500 172.640 56.710 173.390 ;
        RECT 56.880 173.195 57.245 174.120 ;
        RECT 57.710 174.050 58.660 174.220 ;
        RECT 58.830 174.345 59.280 175.020 ;
        RECT 59.550 174.385 59.875 175.190 ;
        RECT 57.710 173.880 57.880 174.050 ;
        RECT 57.425 173.545 57.880 173.880 ;
        RECT 58.830 173.805 59.005 174.345 ;
        RECT 60.045 174.215 60.390 175.020 ;
        RECT 59.470 174.045 60.390 174.215 ;
        RECT 60.560 174.050 60.890 175.190 ;
        RECT 61.060 174.560 61.415 175.020 ;
        RECT 61.585 174.730 62.160 175.190 ;
        RECT 62.330 174.560 62.660 175.020 ;
        RECT 61.060 174.390 62.660 174.560 ;
        RECT 62.860 174.390 63.115 175.190 ;
        RECT 61.060 174.050 61.335 174.390 ;
        RECT 61.515 174.170 61.705 174.210 ;
        RECT 59.470 173.850 59.820 174.045 ;
        RECT 61.515 174.000 61.710 174.170 ;
        RECT 58.055 173.630 59.005 173.805 ;
        RECT 57.710 173.460 57.880 173.545 ;
        RECT 57.710 173.290 58.660 173.460 ;
        RECT 56.880 172.810 57.460 173.195 ;
        RECT 57.630 172.640 58.235 173.120 ;
        RECT 58.410 172.810 58.660 173.290 ;
        RECT 58.830 173.410 59.005 173.630 ;
        RECT 59.370 173.580 59.820 173.850 ;
        RECT 59.990 173.630 60.390 173.875 ;
        RECT 61.515 173.830 61.705 174.000 ;
        RECT 60.560 173.630 61.705 173.830 ;
        RECT 59.470 173.460 59.820 173.580 ;
        RECT 61.885 173.490 62.165 174.390 ;
        RECT 63.285 174.220 63.585 174.415 ;
        RECT 62.335 174.050 63.585 174.220 ;
        RECT 62.335 173.630 62.665 174.050 ;
        RECT 62.895 173.550 63.240 173.880 ;
        RECT 61.885 173.460 62.170 173.490 ;
        RECT 58.830 172.810 59.300 173.410 ;
        RECT 59.470 173.290 60.390 173.460 ;
        RECT 59.565 172.640 59.895 173.120 ;
        RECT 60.065 172.810 60.390 173.290 ;
        RECT 60.560 173.250 61.670 173.460 ;
        RECT 60.560 172.810 60.910 173.250 ;
        RECT 61.080 172.640 61.250 173.080 ;
        RECT 61.420 173.020 61.670 173.250 ;
        RECT 61.840 173.190 62.170 173.460 ;
        RECT 62.340 173.020 62.615 173.460 ;
        RECT 63.415 173.395 63.585 174.050 ;
        RECT 63.780 174.025 64.070 175.190 ;
        RECT 64.240 174.215 64.585 175.020 ;
        RECT 64.755 174.385 65.080 175.190 ;
        RECT 65.350 174.345 65.800 175.020 ;
        RECT 64.240 174.045 65.160 174.215 ;
        RECT 64.240 173.630 64.640 173.875 ;
        RECT 64.810 173.850 65.160 174.045 ;
        RECT 64.810 173.580 65.260 173.850 ;
        RECT 65.625 173.805 65.800 174.345 ;
        RECT 65.970 174.220 66.220 175.020 ;
        RECT 66.390 174.390 67.000 175.190 ;
        RECT 65.970 174.050 66.920 174.220 ;
        RECT 67.190 174.120 67.750 175.020 ;
        RECT 66.750 173.880 66.920 174.050 ;
        RECT 65.625 173.630 66.575 173.805 ;
        RECT 64.810 173.460 65.160 173.580 ;
        RECT 61.420 172.810 62.615 173.020 ;
        RECT 62.850 172.640 63.180 173.380 ;
        RECT 63.350 173.065 63.585 173.395 ;
        RECT 63.780 172.640 64.070 173.365 ;
        RECT 64.240 173.290 65.160 173.460 ;
        RECT 65.625 173.410 65.800 173.630 ;
        RECT 66.750 173.545 67.205 173.880 ;
        RECT 66.750 173.460 66.920 173.545 ;
        RECT 64.240 172.810 64.565 173.290 ;
        RECT 64.735 172.640 65.065 173.120 ;
        RECT 65.330 172.810 65.800 173.410 ;
        RECT 65.970 173.290 66.920 173.460 ;
        RECT 65.970 172.810 66.220 173.290 ;
        RECT 67.385 173.195 67.750 174.120 ;
        RECT 67.920 174.100 69.130 175.190 ;
        RECT 69.300 174.100 70.510 175.190 ;
        RECT 70.680 174.520 70.995 175.020 ;
        RECT 71.165 174.690 71.415 175.190 ;
        RECT 71.585 174.520 71.835 175.020 ;
        RECT 72.005 174.690 72.255 175.190 ;
        RECT 72.425 174.520 72.675 175.020 ;
        RECT 72.985 174.680 73.235 175.020 ;
        RECT 73.405 174.690 73.655 175.190 ;
        RECT 73.825 174.850 74.950 175.020 ;
        RECT 73.825 174.680 74.150 174.850 ;
        RECT 74.700 174.690 74.950 174.850 ;
        RECT 75.220 174.690 75.470 175.190 ;
        RECT 70.680 174.510 72.675 174.520 ;
        RECT 74.320 174.520 74.530 174.680 ;
        RECT 75.640 174.520 75.890 174.680 ;
        RECT 70.680 174.340 74.075 174.510 ;
        RECT 74.320 174.350 75.890 174.520 ;
        RECT 76.060 174.350 76.490 175.190 ;
        RECT 67.920 173.560 68.440 174.100 ;
        RECT 68.610 173.390 69.130 173.930 ;
        RECT 69.300 173.560 69.820 174.100 ;
        RECT 69.990 173.390 70.510 173.930 ;
        RECT 66.395 172.640 67.000 173.120 ;
        RECT 67.170 172.810 67.750 173.195 ;
        RECT 67.920 172.640 69.130 173.390 ;
        RECT 69.300 172.640 70.510 173.390 ;
        RECT 70.680 173.450 70.910 174.340 ;
        RECT 73.905 174.180 74.075 174.340 ;
        RECT 75.640 174.180 75.890 174.350 ;
        RECT 71.385 174.000 73.695 174.170 ;
        RECT 73.905 174.010 75.400 174.180 ;
        RECT 71.385 173.840 71.555 174.000 ;
        RECT 71.080 173.630 71.555 173.840 ;
        RECT 73.525 173.840 73.695 174.000 ;
        RECT 71.850 173.630 73.300 173.830 ;
        RECT 73.525 173.630 74.550 173.840 ;
        RECT 75.230 173.800 75.400 174.010 ;
        RECT 75.640 173.970 76.490 174.180 ;
        RECT 76.660 174.025 76.950 175.190 ;
        RECT 77.135 174.205 77.460 175.190 ;
        RECT 78.030 174.560 78.290 175.020 ;
        RECT 78.460 174.740 79.310 175.190 ;
        RECT 77.645 174.510 77.850 174.540 ;
        RECT 77.640 174.340 77.850 174.510 ;
        RECT 78.030 174.340 79.150 174.560 ;
        RECT 75.230 173.630 75.890 173.800 ;
        RECT 70.680 173.200 71.455 173.450 ;
        RECT 71.625 173.280 72.715 173.460 ;
        RECT 71.625 173.030 71.875 173.280 ;
        RECT 70.700 172.810 71.875 173.030 ;
        RECT 72.045 172.640 72.215 173.110 ;
        RECT 72.385 172.810 72.715 173.280 ;
        RECT 73.025 172.640 73.195 173.460 ;
        RECT 73.365 173.280 75.930 173.460 ;
        RECT 73.365 172.810 73.695 173.280 ;
        RECT 73.865 172.640 74.035 173.110 ;
        RECT 74.205 172.810 74.570 173.280 ;
        RECT 75.600 173.200 75.930 173.280 ;
        RECT 74.740 172.640 74.910 173.110 ;
        RECT 76.100 173.030 76.490 173.970 ;
        RECT 77.130 173.550 77.390 174.005 ;
        RECT 77.645 173.955 77.850 174.340 ;
        RECT 77.645 173.580 78.230 173.955 ;
        RECT 78.400 173.565 78.810 174.170 ;
        RECT 78.980 173.885 79.150 174.340 ;
        RECT 78.980 173.395 79.310 173.885 ;
        RECT 75.180 172.860 76.490 173.030 ;
        RECT 76.660 172.640 76.950 173.365 ;
        RECT 77.135 173.190 78.290 173.380 ;
        RECT 77.135 173.050 77.410 173.190 ;
        RECT 78.080 173.020 78.290 173.190 ;
        RECT 78.460 173.190 79.310 173.395 ;
        RECT 77.580 172.640 77.910 173.020 ;
        RECT 78.460 172.810 78.790 173.190 ;
        RECT 78.980 172.640 79.310 173.020 ;
        RECT 79.480 172.810 79.725 175.020 ;
        RECT 79.910 174.190 80.165 175.190 ;
        RECT 80.340 174.050 80.670 175.190 ;
        RECT 80.840 174.560 81.195 175.020 ;
        RECT 81.365 174.730 81.940 175.190 ;
        RECT 82.110 174.560 82.440 175.020 ;
        RECT 80.840 174.390 82.440 174.560 ;
        RECT 82.640 174.390 82.895 175.190 ;
        RECT 80.840 174.050 81.115 174.390 ;
        RECT 81.295 174.170 81.485 174.210 ;
        RECT 81.295 174.000 81.490 174.170 ;
        RECT 81.295 173.830 81.485 174.000 ;
        RECT 80.340 173.630 81.485 173.830 ;
        RECT 81.665 173.460 81.945 174.390 ;
        RECT 83.065 174.220 83.365 174.415 ;
        RECT 82.115 174.050 83.365 174.220 ;
        RECT 83.565 174.190 83.820 175.190 ;
        RECT 82.115 173.630 82.445 174.050 ;
        RECT 82.675 173.550 83.020 173.880 ;
        RECT 79.910 172.640 80.150 173.440 ;
        RECT 80.340 173.250 81.450 173.460 ;
        RECT 80.340 172.810 80.690 173.250 ;
        RECT 80.860 172.640 81.030 173.080 ;
        RECT 81.200 173.020 81.450 173.250 ;
        RECT 81.620 173.360 81.945 173.460 ;
        RECT 81.620 173.190 81.950 173.360 ;
        RECT 82.120 173.020 82.395 173.460 ;
        RECT 83.195 173.395 83.365 174.050 ;
        RECT 81.200 172.810 82.395 173.020 ;
        RECT 82.630 172.640 82.960 173.380 ;
        RECT 83.130 173.065 83.365 173.395 ;
        RECT 83.580 172.640 83.820 173.440 ;
        RECT 84.005 172.810 84.250 175.020 ;
        RECT 84.420 174.740 85.270 175.190 ;
        RECT 85.440 174.560 85.700 175.020 ;
        RECT 84.580 174.340 85.700 174.560 ;
        RECT 85.880 174.510 86.085 174.540 ;
        RECT 85.880 174.340 86.090 174.510 ;
        RECT 84.580 173.885 84.750 174.340 ;
        RECT 84.420 173.395 84.750 173.885 ;
        RECT 84.920 173.565 85.330 174.170 ;
        RECT 85.880 173.955 86.085 174.340 ;
        RECT 86.270 174.205 86.595 175.190 ;
        RECT 87.240 174.100 88.450 175.190 ;
        RECT 88.620 174.100 89.830 175.190 ;
        RECT 85.500 173.580 86.085 173.955 ;
        RECT 86.340 173.550 86.600 174.005 ;
        RECT 87.240 173.560 87.760 174.100 ;
        RECT 84.420 173.190 85.270 173.395 ;
        RECT 87.930 173.390 88.450 173.930 ;
        RECT 88.620 173.560 89.140 174.100 ;
        RECT 89.310 173.390 89.830 173.930 ;
        RECT 84.420 172.640 84.750 173.020 ;
        RECT 84.940 172.810 85.270 173.190 ;
        RECT 85.440 173.190 86.595 173.380 ;
        RECT 85.440 173.020 85.650 173.190 ;
        RECT 86.320 173.050 86.595 173.190 ;
        RECT 85.820 172.640 86.150 173.020 ;
        RECT 87.240 172.640 88.450 173.390 ;
        RECT 88.620 172.640 89.830 173.390 ;
        RECT 55.415 172.470 89.915 172.640 ;
        RECT 16.820 155.995 19.295 156.245 ;
        RECT 138.765 156.110 142.895 156.360 ;
        RECT 139.110 155.585 142.520 155.915 ;
        RECT 17.300 154.445 17.470 154.995 ;
        RECT 17.905 154.445 18.075 154.995 ;
        RECT 19.085 154.445 19.255 154.995 ;
        RECT 19.600 154.880 138.460 155.130 ;
        RECT 19.655 154.395 19.825 154.880 ;
        RECT 30.465 154.395 30.635 154.880 ;
        RECT 41.275 154.395 41.445 154.880 ;
        RECT 52.085 154.395 52.255 154.880 ;
        RECT 62.895 154.395 63.065 154.880 ;
        RECT 73.705 154.395 73.875 154.880 ;
        RECT 84.515 154.395 84.685 154.880 ;
        RECT 95.325 154.395 95.495 154.880 ;
        RECT 106.135 154.395 106.305 154.880 ;
        RECT 116.945 154.395 117.115 154.880 ;
        RECT 127.755 154.395 127.925 154.880 ;
        RECT 17.530 153.950 17.860 154.120 ;
        RECT 18.235 153.995 18.925 154.165 ;
        RECT 19.655 154.065 29.645 154.395 ;
        RECT 30.465 154.065 40.455 154.395 ;
        RECT 41.275 154.065 51.265 154.395 ;
        RECT 52.085 154.065 62.075 154.395 ;
        RECT 62.895 154.065 72.885 154.395 ;
        RECT 73.705 154.065 83.695 154.395 ;
        RECT 84.515 154.065 94.505 154.395 ;
        RECT 95.325 154.065 105.315 154.395 ;
        RECT 106.135 154.065 116.125 154.395 ;
        RECT 116.945 154.065 126.935 154.395 ;
        RECT 127.755 154.065 137.745 154.395 ;
        RECT 138.805 154.345 138.975 154.895 ;
        RECT 142.685 154.345 142.855 154.895 ;
        RECT 19.655 153.380 19.825 154.065 ;
        RECT 29.935 153.380 30.105 153.800 ;
        RECT 30.465 153.380 30.635 154.065 ;
        RECT 40.745 153.380 40.915 153.800 ;
        RECT 41.275 153.380 41.445 154.065 ;
        RECT 51.555 153.380 51.725 153.800 ;
        RECT 52.085 153.380 52.255 154.065 ;
        RECT 62.365 153.380 62.535 153.800 ;
        RECT 62.895 153.380 63.065 154.065 ;
        RECT 73.175 153.380 73.345 153.800 ;
        RECT 73.705 153.380 73.875 154.065 ;
        RECT 83.985 153.380 84.155 153.800 ;
        RECT 84.515 153.380 84.685 154.065 ;
        RECT 94.795 153.380 94.965 153.800 ;
        RECT 95.325 153.380 95.495 154.065 ;
        RECT 105.605 153.380 105.775 153.800 ;
        RECT 106.135 153.380 106.305 154.065 ;
        RECT 116.415 153.380 116.585 153.800 ;
        RECT 116.945 153.380 117.115 154.065 ;
        RECT 127.225 153.380 127.395 153.800 ;
        RECT 127.755 153.380 127.925 154.065 ;
        RECT 138.035 153.380 138.205 153.800 ;
        RECT 139.915 153.670 140.335 153.840 ;
        RECT 141.320 153.670 141.740 153.840 ;
        RECT 24.715 152.770 25.045 152.940 ;
        RECT 35.525 152.770 35.855 152.940 ;
        RECT 46.335 152.770 46.665 152.940 ;
        RECT 57.145 152.770 57.475 152.940 ;
        RECT 67.955 152.770 68.285 152.940 ;
        RECT 78.765 152.770 79.095 152.940 ;
        RECT 89.575 152.770 89.905 152.940 ;
        RECT 100.385 152.770 100.715 152.940 ;
        RECT 111.195 152.770 111.525 152.940 ;
        RECT 122.005 152.770 122.335 152.940 ;
        RECT 132.815 152.770 133.145 152.940 ;
        RECT 139.915 152.790 140.335 152.960 ;
        RECT 141.320 152.790 141.740 152.960 ;
        RECT 24.580 152.010 24.750 152.430 ;
        RECT 25.010 152.010 25.180 152.430 ;
        RECT 35.390 152.010 35.560 152.430 ;
        RECT 35.820 152.010 35.990 152.430 ;
        RECT 46.200 152.010 46.370 152.430 ;
        RECT 46.630 152.010 46.800 152.430 ;
        RECT 57.010 152.010 57.180 152.430 ;
        RECT 57.440 152.010 57.610 152.430 ;
        RECT 67.820 152.010 67.990 152.430 ;
        RECT 68.250 152.010 68.420 152.430 ;
        RECT 78.630 152.010 78.800 152.430 ;
        RECT 79.060 152.010 79.230 152.430 ;
        RECT 89.440 152.010 89.610 152.430 ;
        RECT 89.870 152.010 90.040 152.430 ;
        RECT 100.250 152.010 100.420 152.430 ;
        RECT 100.680 152.010 100.850 152.430 ;
        RECT 111.060 152.010 111.230 152.430 ;
        RECT 111.490 152.010 111.660 152.430 ;
        RECT 121.870 152.010 122.040 152.430 ;
        RECT 122.300 152.010 122.470 152.430 ;
        RECT 132.680 152.010 132.850 152.430 ;
        RECT 133.110 152.010 133.280 152.430 ;
        RECT 138.725 152.045 138.895 152.375 ;
        RECT 142.745 152.065 142.915 152.395 ;
        RECT 140.275 151.890 140.695 152.060 ;
        RECT 140.965 151.890 141.385 152.060 ;
        RECT 29.255 151.495 29.585 151.665 ;
        RECT 40.065 151.495 40.395 151.665 ;
        RECT 50.875 151.495 51.205 151.665 ;
        RECT 61.685 151.495 62.015 151.665 ;
        RECT 72.495 151.495 72.825 151.665 ;
        RECT 83.305 151.495 83.635 151.665 ;
        RECT 94.115 151.495 94.445 151.665 ;
        RECT 104.925 151.495 105.255 151.665 ;
        RECT 115.735 151.495 116.065 151.665 ;
        RECT 126.545 151.495 126.875 151.665 ;
        RECT 137.355 151.495 137.685 151.665 ;
        RECT 17.520 151.210 18.020 151.380 ;
        RECT 18.290 151.210 18.790 151.380 ;
        RECT 17.000 150.995 17.330 151.165 ;
        RECT 17.520 150.780 18.020 150.950 ;
        RECT 18.290 150.780 18.790 150.950 ;
        RECT 24.580 150.925 24.750 151.425 ;
        RECT 25.010 150.460 25.180 151.425 ;
        RECT 25.440 150.925 25.610 151.425 ;
        RECT 25.870 150.460 26.040 151.425 ;
        RECT 26.300 150.925 26.470 151.425 ;
        RECT 26.730 150.460 26.900 151.425 ;
        RECT 27.160 150.925 27.330 151.425 ;
        RECT 27.590 150.460 27.760 151.425 ;
        RECT 28.020 150.925 28.190 151.425 ;
        RECT 28.450 150.460 28.620 151.425 ;
        RECT 28.880 150.925 29.050 151.425 ;
        RECT 35.390 150.925 35.560 151.425 ;
        RECT 35.820 150.460 35.990 151.425 ;
        RECT 36.250 150.925 36.420 151.425 ;
        RECT 36.680 150.460 36.850 151.425 ;
        RECT 37.110 150.925 37.280 151.425 ;
        RECT 37.540 150.460 37.710 151.425 ;
        RECT 37.970 150.925 38.140 151.425 ;
        RECT 38.400 150.460 38.570 151.425 ;
        RECT 38.830 150.925 39.000 151.425 ;
        RECT 39.260 150.460 39.430 151.425 ;
        RECT 39.690 150.925 39.860 151.425 ;
        RECT 46.200 150.925 46.370 151.425 ;
        RECT 46.630 150.460 46.800 151.425 ;
        RECT 47.060 150.925 47.230 151.425 ;
        RECT 47.490 150.460 47.660 151.425 ;
        RECT 47.920 150.925 48.090 151.425 ;
        RECT 48.350 150.460 48.520 151.425 ;
        RECT 48.780 150.925 48.950 151.425 ;
        RECT 49.210 150.460 49.380 151.425 ;
        RECT 49.640 150.925 49.810 151.425 ;
        RECT 50.070 150.460 50.240 151.425 ;
        RECT 50.500 150.925 50.670 151.425 ;
        RECT 57.010 150.925 57.180 151.425 ;
        RECT 57.440 150.460 57.610 151.425 ;
        RECT 57.870 150.925 58.040 151.425 ;
        RECT 58.300 150.460 58.470 151.425 ;
        RECT 58.730 150.925 58.900 151.425 ;
        RECT 59.160 150.460 59.330 151.425 ;
        RECT 59.590 150.925 59.760 151.425 ;
        RECT 60.020 150.460 60.190 151.425 ;
        RECT 60.450 150.925 60.620 151.425 ;
        RECT 60.880 150.460 61.050 151.425 ;
        RECT 61.310 150.925 61.480 151.425 ;
        RECT 67.820 150.925 67.990 151.425 ;
        RECT 68.250 150.460 68.420 151.425 ;
        RECT 68.680 150.925 68.850 151.425 ;
        RECT 69.110 150.460 69.280 151.425 ;
        RECT 69.540 150.925 69.710 151.425 ;
        RECT 69.970 150.460 70.140 151.425 ;
        RECT 70.400 150.925 70.570 151.425 ;
        RECT 70.830 150.460 71.000 151.425 ;
        RECT 71.260 150.925 71.430 151.425 ;
        RECT 71.690 150.460 71.860 151.425 ;
        RECT 72.120 150.925 72.290 151.425 ;
        RECT 78.630 150.925 78.800 151.425 ;
        RECT 79.060 150.460 79.230 151.425 ;
        RECT 79.490 150.925 79.660 151.425 ;
        RECT 79.920 150.460 80.090 151.425 ;
        RECT 80.350 150.925 80.520 151.425 ;
        RECT 80.780 150.460 80.950 151.425 ;
        RECT 81.210 150.925 81.380 151.425 ;
        RECT 81.640 150.460 81.810 151.425 ;
        RECT 82.070 150.925 82.240 151.425 ;
        RECT 82.500 150.460 82.670 151.425 ;
        RECT 82.930 150.925 83.100 151.425 ;
        RECT 89.440 150.925 89.610 151.425 ;
        RECT 89.870 150.460 90.040 151.425 ;
        RECT 90.300 150.925 90.470 151.425 ;
        RECT 90.730 150.460 90.900 151.425 ;
        RECT 91.160 150.925 91.330 151.425 ;
        RECT 91.590 150.460 91.760 151.425 ;
        RECT 92.020 150.925 92.190 151.425 ;
        RECT 92.450 150.460 92.620 151.425 ;
        RECT 92.880 150.925 93.050 151.425 ;
        RECT 93.310 150.460 93.480 151.425 ;
        RECT 93.740 150.925 93.910 151.425 ;
        RECT 100.250 150.925 100.420 151.425 ;
        RECT 100.680 150.460 100.850 151.425 ;
        RECT 101.110 150.925 101.280 151.425 ;
        RECT 101.540 150.460 101.710 151.425 ;
        RECT 101.970 150.925 102.140 151.425 ;
        RECT 102.400 150.460 102.570 151.425 ;
        RECT 102.830 150.925 103.000 151.425 ;
        RECT 103.260 150.460 103.430 151.425 ;
        RECT 103.690 150.925 103.860 151.425 ;
        RECT 104.120 150.460 104.290 151.425 ;
        RECT 104.550 150.925 104.720 151.425 ;
        RECT 111.060 150.925 111.230 151.425 ;
        RECT 111.490 150.460 111.660 151.425 ;
        RECT 111.920 150.925 112.090 151.425 ;
        RECT 112.350 150.460 112.520 151.425 ;
        RECT 112.780 150.925 112.950 151.425 ;
        RECT 113.210 150.460 113.380 151.425 ;
        RECT 113.640 150.925 113.810 151.425 ;
        RECT 114.070 150.460 114.240 151.425 ;
        RECT 114.500 150.925 114.670 151.425 ;
        RECT 114.930 150.460 115.100 151.425 ;
        RECT 115.360 150.925 115.530 151.425 ;
        RECT 121.870 150.925 122.040 151.425 ;
        RECT 122.300 150.460 122.470 151.425 ;
        RECT 122.730 150.925 122.900 151.425 ;
        RECT 123.160 150.460 123.330 151.425 ;
        RECT 123.590 150.925 123.760 151.425 ;
        RECT 124.020 150.460 124.190 151.425 ;
        RECT 124.450 150.925 124.620 151.425 ;
        RECT 124.880 150.460 125.050 151.425 ;
        RECT 125.310 150.925 125.480 151.425 ;
        RECT 125.740 150.460 125.910 151.425 ;
        RECT 126.170 150.925 126.340 151.425 ;
        RECT 132.680 150.925 132.850 151.425 ;
        RECT 133.110 150.460 133.280 151.425 ;
        RECT 133.540 150.925 133.710 151.425 ;
        RECT 133.970 150.460 134.140 151.425 ;
        RECT 134.400 150.925 134.570 151.425 ;
        RECT 134.830 150.460 135.000 151.425 ;
        RECT 135.260 150.925 135.430 151.425 ;
        RECT 135.690 150.460 135.860 151.425 ;
        RECT 136.120 150.925 136.290 151.425 ;
        RECT 136.550 150.460 136.720 151.425 ;
        RECT 136.980 150.925 137.150 151.425 ;
        RECT 139.855 151.120 140.025 151.810 ;
        RECT 140.275 150.860 140.695 151.030 ;
        RECT 140.965 150.860 141.385 151.030 ;
        RECT 16.765 150.210 142.950 150.460 ;
        RECT 16.845 144.820 19.320 145.070 ;
        RECT 138.790 144.935 142.920 145.185 ;
        RECT 139.135 144.410 142.545 144.740 ;
        RECT 17.325 143.270 17.495 143.820 ;
        RECT 17.930 143.270 18.100 143.820 ;
        RECT 19.110 143.270 19.280 143.820 ;
        RECT 19.625 143.705 138.485 143.955 ;
        RECT 19.680 143.220 19.850 143.705 ;
        RECT 30.490 143.220 30.660 143.705 ;
        RECT 41.300 143.220 41.470 143.705 ;
        RECT 52.110 143.220 52.280 143.705 ;
        RECT 62.920 143.220 63.090 143.705 ;
        RECT 73.730 143.220 73.900 143.705 ;
        RECT 84.540 143.220 84.710 143.705 ;
        RECT 95.350 143.220 95.520 143.705 ;
        RECT 106.160 143.220 106.330 143.705 ;
        RECT 116.970 143.220 117.140 143.705 ;
        RECT 127.780 143.220 127.950 143.705 ;
        RECT 17.555 142.775 17.885 142.945 ;
        RECT 18.260 142.820 18.950 142.990 ;
        RECT 19.680 142.890 29.670 143.220 ;
        RECT 30.490 142.890 40.480 143.220 ;
        RECT 41.300 142.890 51.290 143.220 ;
        RECT 52.110 142.890 62.100 143.220 ;
        RECT 62.920 142.890 72.910 143.220 ;
        RECT 73.730 142.890 83.720 143.220 ;
        RECT 84.540 142.890 94.530 143.220 ;
        RECT 95.350 142.890 105.340 143.220 ;
        RECT 106.160 142.890 116.150 143.220 ;
        RECT 116.970 142.890 126.960 143.220 ;
        RECT 127.780 142.890 137.770 143.220 ;
        RECT 138.830 143.170 139.000 143.720 ;
        RECT 142.710 143.170 142.880 143.720 ;
        RECT 19.680 142.205 19.850 142.890 ;
        RECT 29.960 142.205 30.130 142.625 ;
        RECT 30.490 142.205 30.660 142.890 ;
        RECT 40.770 142.205 40.940 142.625 ;
        RECT 41.300 142.205 41.470 142.890 ;
        RECT 51.580 142.205 51.750 142.625 ;
        RECT 52.110 142.205 52.280 142.890 ;
        RECT 62.390 142.205 62.560 142.625 ;
        RECT 62.920 142.205 63.090 142.890 ;
        RECT 73.200 142.205 73.370 142.625 ;
        RECT 73.730 142.205 73.900 142.890 ;
        RECT 84.010 142.205 84.180 142.625 ;
        RECT 84.540 142.205 84.710 142.890 ;
        RECT 94.820 142.205 94.990 142.625 ;
        RECT 95.350 142.205 95.520 142.890 ;
        RECT 105.630 142.205 105.800 142.625 ;
        RECT 106.160 142.205 106.330 142.890 ;
        RECT 116.440 142.205 116.610 142.625 ;
        RECT 116.970 142.205 117.140 142.890 ;
        RECT 127.250 142.205 127.420 142.625 ;
        RECT 127.780 142.205 127.950 142.890 ;
        RECT 138.060 142.205 138.230 142.625 ;
        RECT 139.940 142.495 140.360 142.665 ;
        RECT 141.345 142.495 141.765 142.665 ;
        RECT 24.740 141.595 25.070 141.765 ;
        RECT 35.550 141.595 35.880 141.765 ;
        RECT 46.360 141.595 46.690 141.765 ;
        RECT 57.170 141.595 57.500 141.765 ;
        RECT 67.980 141.595 68.310 141.765 ;
        RECT 78.790 141.595 79.120 141.765 ;
        RECT 89.600 141.595 89.930 141.765 ;
        RECT 100.410 141.595 100.740 141.765 ;
        RECT 111.220 141.595 111.550 141.765 ;
        RECT 122.030 141.595 122.360 141.765 ;
        RECT 132.840 141.595 133.170 141.765 ;
        RECT 139.940 141.615 140.360 141.785 ;
        RECT 141.345 141.615 141.765 141.785 ;
        RECT 24.605 140.835 24.775 141.255 ;
        RECT 25.035 140.835 25.205 141.255 ;
        RECT 35.415 140.835 35.585 141.255 ;
        RECT 35.845 140.835 36.015 141.255 ;
        RECT 46.225 140.835 46.395 141.255 ;
        RECT 46.655 140.835 46.825 141.255 ;
        RECT 57.035 140.835 57.205 141.255 ;
        RECT 57.465 140.835 57.635 141.255 ;
        RECT 67.845 140.835 68.015 141.255 ;
        RECT 68.275 140.835 68.445 141.255 ;
        RECT 78.655 140.835 78.825 141.255 ;
        RECT 79.085 140.835 79.255 141.255 ;
        RECT 89.465 140.835 89.635 141.255 ;
        RECT 89.895 140.835 90.065 141.255 ;
        RECT 100.275 140.835 100.445 141.255 ;
        RECT 100.705 140.835 100.875 141.255 ;
        RECT 111.085 140.835 111.255 141.255 ;
        RECT 111.515 140.835 111.685 141.255 ;
        RECT 121.895 140.835 122.065 141.255 ;
        RECT 122.325 140.835 122.495 141.255 ;
        RECT 132.705 140.835 132.875 141.255 ;
        RECT 133.135 140.835 133.305 141.255 ;
        RECT 138.750 140.870 138.920 141.200 ;
        RECT 142.770 140.890 142.940 141.220 ;
        RECT 140.300 140.715 140.720 140.885 ;
        RECT 140.990 140.715 141.410 140.885 ;
        RECT 29.280 140.320 29.610 140.490 ;
        RECT 40.090 140.320 40.420 140.490 ;
        RECT 50.900 140.320 51.230 140.490 ;
        RECT 61.710 140.320 62.040 140.490 ;
        RECT 72.520 140.320 72.850 140.490 ;
        RECT 83.330 140.320 83.660 140.490 ;
        RECT 94.140 140.320 94.470 140.490 ;
        RECT 104.950 140.320 105.280 140.490 ;
        RECT 115.760 140.320 116.090 140.490 ;
        RECT 126.570 140.320 126.900 140.490 ;
        RECT 137.380 140.320 137.710 140.490 ;
        RECT 17.545 140.035 18.045 140.205 ;
        RECT 18.315 140.035 18.815 140.205 ;
        RECT 17.025 139.820 17.355 139.990 ;
        RECT 17.545 139.605 18.045 139.775 ;
        RECT 18.315 139.605 18.815 139.775 ;
        RECT 24.605 139.750 24.775 140.250 ;
        RECT 25.035 139.285 25.205 140.250 ;
        RECT 25.465 139.750 25.635 140.250 ;
        RECT 25.895 139.285 26.065 140.250 ;
        RECT 26.325 139.750 26.495 140.250 ;
        RECT 26.755 139.285 26.925 140.250 ;
        RECT 27.185 139.750 27.355 140.250 ;
        RECT 27.615 139.285 27.785 140.250 ;
        RECT 28.045 139.750 28.215 140.250 ;
        RECT 28.475 139.285 28.645 140.250 ;
        RECT 28.905 139.750 29.075 140.250 ;
        RECT 35.415 139.750 35.585 140.250 ;
        RECT 35.845 139.285 36.015 140.250 ;
        RECT 36.275 139.750 36.445 140.250 ;
        RECT 36.705 139.285 36.875 140.250 ;
        RECT 37.135 139.750 37.305 140.250 ;
        RECT 37.565 139.285 37.735 140.250 ;
        RECT 37.995 139.750 38.165 140.250 ;
        RECT 38.425 139.285 38.595 140.250 ;
        RECT 38.855 139.750 39.025 140.250 ;
        RECT 39.285 139.285 39.455 140.250 ;
        RECT 39.715 139.750 39.885 140.250 ;
        RECT 46.225 139.750 46.395 140.250 ;
        RECT 46.655 139.285 46.825 140.250 ;
        RECT 47.085 139.750 47.255 140.250 ;
        RECT 47.515 139.285 47.685 140.250 ;
        RECT 47.945 139.750 48.115 140.250 ;
        RECT 48.375 139.285 48.545 140.250 ;
        RECT 48.805 139.750 48.975 140.250 ;
        RECT 49.235 139.285 49.405 140.250 ;
        RECT 49.665 139.750 49.835 140.250 ;
        RECT 50.095 139.285 50.265 140.250 ;
        RECT 50.525 139.750 50.695 140.250 ;
        RECT 57.035 139.750 57.205 140.250 ;
        RECT 57.465 139.285 57.635 140.250 ;
        RECT 57.895 139.750 58.065 140.250 ;
        RECT 58.325 139.285 58.495 140.250 ;
        RECT 58.755 139.750 58.925 140.250 ;
        RECT 59.185 139.285 59.355 140.250 ;
        RECT 59.615 139.750 59.785 140.250 ;
        RECT 60.045 139.285 60.215 140.250 ;
        RECT 60.475 139.750 60.645 140.250 ;
        RECT 60.905 139.285 61.075 140.250 ;
        RECT 61.335 139.750 61.505 140.250 ;
        RECT 67.845 139.750 68.015 140.250 ;
        RECT 68.275 139.285 68.445 140.250 ;
        RECT 68.705 139.750 68.875 140.250 ;
        RECT 69.135 139.285 69.305 140.250 ;
        RECT 69.565 139.750 69.735 140.250 ;
        RECT 69.995 139.285 70.165 140.250 ;
        RECT 70.425 139.750 70.595 140.250 ;
        RECT 70.855 139.285 71.025 140.250 ;
        RECT 71.285 139.750 71.455 140.250 ;
        RECT 71.715 139.285 71.885 140.250 ;
        RECT 72.145 139.750 72.315 140.250 ;
        RECT 78.655 139.750 78.825 140.250 ;
        RECT 79.085 139.285 79.255 140.250 ;
        RECT 79.515 139.750 79.685 140.250 ;
        RECT 79.945 139.285 80.115 140.250 ;
        RECT 80.375 139.750 80.545 140.250 ;
        RECT 80.805 139.285 80.975 140.250 ;
        RECT 81.235 139.750 81.405 140.250 ;
        RECT 81.665 139.285 81.835 140.250 ;
        RECT 82.095 139.750 82.265 140.250 ;
        RECT 82.525 139.285 82.695 140.250 ;
        RECT 82.955 139.750 83.125 140.250 ;
        RECT 89.465 139.750 89.635 140.250 ;
        RECT 89.895 139.285 90.065 140.250 ;
        RECT 90.325 139.750 90.495 140.250 ;
        RECT 90.755 139.285 90.925 140.250 ;
        RECT 91.185 139.750 91.355 140.250 ;
        RECT 91.615 139.285 91.785 140.250 ;
        RECT 92.045 139.750 92.215 140.250 ;
        RECT 92.475 139.285 92.645 140.250 ;
        RECT 92.905 139.750 93.075 140.250 ;
        RECT 93.335 139.285 93.505 140.250 ;
        RECT 93.765 139.750 93.935 140.250 ;
        RECT 100.275 139.750 100.445 140.250 ;
        RECT 100.705 139.285 100.875 140.250 ;
        RECT 101.135 139.750 101.305 140.250 ;
        RECT 101.565 139.285 101.735 140.250 ;
        RECT 101.995 139.750 102.165 140.250 ;
        RECT 102.425 139.285 102.595 140.250 ;
        RECT 102.855 139.750 103.025 140.250 ;
        RECT 103.285 139.285 103.455 140.250 ;
        RECT 103.715 139.750 103.885 140.250 ;
        RECT 104.145 139.285 104.315 140.250 ;
        RECT 104.575 139.750 104.745 140.250 ;
        RECT 111.085 139.750 111.255 140.250 ;
        RECT 111.515 139.285 111.685 140.250 ;
        RECT 111.945 139.750 112.115 140.250 ;
        RECT 112.375 139.285 112.545 140.250 ;
        RECT 112.805 139.750 112.975 140.250 ;
        RECT 113.235 139.285 113.405 140.250 ;
        RECT 113.665 139.750 113.835 140.250 ;
        RECT 114.095 139.285 114.265 140.250 ;
        RECT 114.525 139.750 114.695 140.250 ;
        RECT 114.955 139.285 115.125 140.250 ;
        RECT 115.385 139.750 115.555 140.250 ;
        RECT 121.895 139.750 122.065 140.250 ;
        RECT 122.325 139.285 122.495 140.250 ;
        RECT 122.755 139.750 122.925 140.250 ;
        RECT 123.185 139.285 123.355 140.250 ;
        RECT 123.615 139.750 123.785 140.250 ;
        RECT 124.045 139.285 124.215 140.250 ;
        RECT 124.475 139.750 124.645 140.250 ;
        RECT 124.905 139.285 125.075 140.250 ;
        RECT 125.335 139.750 125.505 140.250 ;
        RECT 125.765 139.285 125.935 140.250 ;
        RECT 126.195 139.750 126.365 140.250 ;
        RECT 132.705 139.750 132.875 140.250 ;
        RECT 133.135 139.285 133.305 140.250 ;
        RECT 133.565 139.750 133.735 140.250 ;
        RECT 133.995 139.285 134.165 140.250 ;
        RECT 134.425 139.750 134.595 140.250 ;
        RECT 134.855 139.285 135.025 140.250 ;
        RECT 135.285 139.750 135.455 140.250 ;
        RECT 135.715 139.285 135.885 140.250 ;
        RECT 136.145 139.750 136.315 140.250 ;
        RECT 136.575 139.285 136.745 140.250 ;
        RECT 137.005 139.750 137.175 140.250 ;
        RECT 139.880 139.945 140.050 140.635 ;
        RECT 140.300 139.685 140.720 139.855 ;
        RECT 140.990 139.685 141.410 139.855 ;
        RECT 16.790 139.035 142.975 139.285 ;
        RECT 16.875 134.985 19.350 135.235 ;
        RECT 138.820 135.100 142.950 135.350 ;
        RECT 139.165 134.575 142.575 134.905 ;
        RECT 17.355 133.435 17.525 133.985 ;
        RECT 17.960 133.435 18.130 133.985 ;
        RECT 19.140 133.435 19.310 133.985 ;
        RECT 19.655 133.870 138.515 134.120 ;
        RECT 19.710 133.385 19.880 133.870 ;
        RECT 30.520 133.385 30.690 133.870 ;
        RECT 41.330 133.385 41.500 133.870 ;
        RECT 52.140 133.385 52.310 133.870 ;
        RECT 62.950 133.385 63.120 133.870 ;
        RECT 73.760 133.385 73.930 133.870 ;
        RECT 84.570 133.385 84.740 133.870 ;
        RECT 95.380 133.385 95.550 133.870 ;
        RECT 106.190 133.385 106.360 133.870 ;
        RECT 117.000 133.385 117.170 133.870 ;
        RECT 127.810 133.385 127.980 133.870 ;
        RECT 17.585 132.940 17.915 133.110 ;
        RECT 18.290 132.985 18.980 133.155 ;
        RECT 19.710 133.055 29.700 133.385 ;
        RECT 30.520 133.055 40.510 133.385 ;
        RECT 41.330 133.055 51.320 133.385 ;
        RECT 52.140 133.055 62.130 133.385 ;
        RECT 62.950 133.055 72.940 133.385 ;
        RECT 73.760 133.055 83.750 133.385 ;
        RECT 84.570 133.055 94.560 133.385 ;
        RECT 95.380 133.055 105.370 133.385 ;
        RECT 106.190 133.055 116.180 133.385 ;
        RECT 117.000 133.055 126.990 133.385 ;
        RECT 127.810 133.055 137.800 133.385 ;
        RECT 138.860 133.335 139.030 133.885 ;
        RECT 142.740 133.335 142.910 133.885 ;
        RECT 19.710 132.370 19.880 133.055 ;
        RECT 29.990 132.370 30.160 132.790 ;
        RECT 30.520 132.370 30.690 133.055 ;
        RECT 40.800 132.370 40.970 132.790 ;
        RECT 41.330 132.370 41.500 133.055 ;
        RECT 51.610 132.370 51.780 132.790 ;
        RECT 52.140 132.370 52.310 133.055 ;
        RECT 62.420 132.370 62.590 132.790 ;
        RECT 62.950 132.370 63.120 133.055 ;
        RECT 73.230 132.370 73.400 132.790 ;
        RECT 73.760 132.370 73.930 133.055 ;
        RECT 84.040 132.370 84.210 132.790 ;
        RECT 84.570 132.370 84.740 133.055 ;
        RECT 94.850 132.370 95.020 132.790 ;
        RECT 95.380 132.370 95.550 133.055 ;
        RECT 105.660 132.370 105.830 132.790 ;
        RECT 106.190 132.370 106.360 133.055 ;
        RECT 116.470 132.370 116.640 132.790 ;
        RECT 117.000 132.370 117.170 133.055 ;
        RECT 127.280 132.370 127.450 132.790 ;
        RECT 127.810 132.370 127.980 133.055 ;
        RECT 138.090 132.370 138.260 132.790 ;
        RECT 139.970 132.660 140.390 132.830 ;
        RECT 141.375 132.660 141.795 132.830 ;
        RECT 24.770 131.760 25.100 131.930 ;
        RECT 35.580 131.760 35.910 131.930 ;
        RECT 46.390 131.760 46.720 131.930 ;
        RECT 57.200 131.760 57.530 131.930 ;
        RECT 68.010 131.760 68.340 131.930 ;
        RECT 78.820 131.760 79.150 131.930 ;
        RECT 89.630 131.760 89.960 131.930 ;
        RECT 100.440 131.760 100.770 131.930 ;
        RECT 111.250 131.760 111.580 131.930 ;
        RECT 122.060 131.760 122.390 131.930 ;
        RECT 132.870 131.760 133.200 131.930 ;
        RECT 139.970 131.780 140.390 131.950 ;
        RECT 141.375 131.780 141.795 131.950 ;
        RECT 24.635 131.000 24.805 131.420 ;
        RECT 25.065 131.000 25.235 131.420 ;
        RECT 35.445 131.000 35.615 131.420 ;
        RECT 35.875 131.000 36.045 131.420 ;
        RECT 46.255 131.000 46.425 131.420 ;
        RECT 46.685 131.000 46.855 131.420 ;
        RECT 57.065 131.000 57.235 131.420 ;
        RECT 57.495 131.000 57.665 131.420 ;
        RECT 67.875 131.000 68.045 131.420 ;
        RECT 68.305 131.000 68.475 131.420 ;
        RECT 78.685 131.000 78.855 131.420 ;
        RECT 79.115 131.000 79.285 131.420 ;
        RECT 89.495 131.000 89.665 131.420 ;
        RECT 89.925 131.000 90.095 131.420 ;
        RECT 100.305 131.000 100.475 131.420 ;
        RECT 100.735 131.000 100.905 131.420 ;
        RECT 111.115 131.000 111.285 131.420 ;
        RECT 111.545 131.000 111.715 131.420 ;
        RECT 121.925 131.000 122.095 131.420 ;
        RECT 122.355 131.000 122.525 131.420 ;
        RECT 132.735 131.000 132.905 131.420 ;
        RECT 133.165 131.000 133.335 131.420 ;
        RECT 138.780 131.035 138.950 131.365 ;
        RECT 142.800 131.055 142.970 131.385 ;
        RECT 140.330 130.880 140.750 131.050 ;
        RECT 141.020 130.880 141.440 131.050 ;
        RECT 29.310 130.485 29.640 130.655 ;
        RECT 40.120 130.485 40.450 130.655 ;
        RECT 50.930 130.485 51.260 130.655 ;
        RECT 61.740 130.485 62.070 130.655 ;
        RECT 72.550 130.485 72.880 130.655 ;
        RECT 83.360 130.485 83.690 130.655 ;
        RECT 94.170 130.485 94.500 130.655 ;
        RECT 104.980 130.485 105.310 130.655 ;
        RECT 115.790 130.485 116.120 130.655 ;
        RECT 126.600 130.485 126.930 130.655 ;
        RECT 137.410 130.485 137.740 130.655 ;
        RECT 17.575 130.200 18.075 130.370 ;
        RECT 18.345 130.200 18.845 130.370 ;
        RECT 17.055 129.985 17.385 130.155 ;
        RECT 17.575 129.770 18.075 129.940 ;
        RECT 18.345 129.770 18.845 129.940 ;
        RECT 24.635 129.915 24.805 130.415 ;
        RECT 25.065 129.450 25.235 130.415 ;
        RECT 25.495 129.915 25.665 130.415 ;
        RECT 25.925 129.450 26.095 130.415 ;
        RECT 26.355 129.915 26.525 130.415 ;
        RECT 26.785 129.450 26.955 130.415 ;
        RECT 27.215 129.915 27.385 130.415 ;
        RECT 27.645 129.450 27.815 130.415 ;
        RECT 28.075 129.915 28.245 130.415 ;
        RECT 28.505 129.450 28.675 130.415 ;
        RECT 28.935 129.915 29.105 130.415 ;
        RECT 35.445 129.915 35.615 130.415 ;
        RECT 35.875 129.450 36.045 130.415 ;
        RECT 36.305 129.915 36.475 130.415 ;
        RECT 36.735 129.450 36.905 130.415 ;
        RECT 37.165 129.915 37.335 130.415 ;
        RECT 37.595 129.450 37.765 130.415 ;
        RECT 38.025 129.915 38.195 130.415 ;
        RECT 38.455 129.450 38.625 130.415 ;
        RECT 38.885 129.915 39.055 130.415 ;
        RECT 39.315 129.450 39.485 130.415 ;
        RECT 39.745 129.915 39.915 130.415 ;
        RECT 46.255 129.915 46.425 130.415 ;
        RECT 46.685 129.450 46.855 130.415 ;
        RECT 47.115 129.915 47.285 130.415 ;
        RECT 47.545 129.450 47.715 130.415 ;
        RECT 47.975 129.915 48.145 130.415 ;
        RECT 48.405 129.450 48.575 130.415 ;
        RECT 48.835 129.915 49.005 130.415 ;
        RECT 49.265 129.450 49.435 130.415 ;
        RECT 49.695 129.915 49.865 130.415 ;
        RECT 50.125 129.450 50.295 130.415 ;
        RECT 50.555 129.915 50.725 130.415 ;
        RECT 57.065 129.915 57.235 130.415 ;
        RECT 57.495 129.450 57.665 130.415 ;
        RECT 57.925 129.915 58.095 130.415 ;
        RECT 58.355 129.450 58.525 130.415 ;
        RECT 58.785 129.915 58.955 130.415 ;
        RECT 59.215 129.450 59.385 130.415 ;
        RECT 59.645 129.915 59.815 130.415 ;
        RECT 60.075 129.450 60.245 130.415 ;
        RECT 60.505 129.915 60.675 130.415 ;
        RECT 60.935 129.450 61.105 130.415 ;
        RECT 61.365 129.915 61.535 130.415 ;
        RECT 67.875 129.915 68.045 130.415 ;
        RECT 68.305 129.450 68.475 130.415 ;
        RECT 68.735 129.915 68.905 130.415 ;
        RECT 69.165 129.450 69.335 130.415 ;
        RECT 69.595 129.915 69.765 130.415 ;
        RECT 70.025 129.450 70.195 130.415 ;
        RECT 70.455 129.915 70.625 130.415 ;
        RECT 70.885 129.450 71.055 130.415 ;
        RECT 71.315 129.915 71.485 130.415 ;
        RECT 71.745 129.450 71.915 130.415 ;
        RECT 72.175 129.915 72.345 130.415 ;
        RECT 78.685 129.915 78.855 130.415 ;
        RECT 79.115 129.450 79.285 130.415 ;
        RECT 79.545 129.915 79.715 130.415 ;
        RECT 79.975 129.450 80.145 130.415 ;
        RECT 80.405 129.915 80.575 130.415 ;
        RECT 80.835 129.450 81.005 130.415 ;
        RECT 81.265 129.915 81.435 130.415 ;
        RECT 81.695 129.450 81.865 130.415 ;
        RECT 82.125 129.915 82.295 130.415 ;
        RECT 82.555 129.450 82.725 130.415 ;
        RECT 82.985 129.915 83.155 130.415 ;
        RECT 89.495 129.915 89.665 130.415 ;
        RECT 89.925 129.450 90.095 130.415 ;
        RECT 90.355 129.915 90.525 130.415 ;
        RECT 90.785 129.450 90.955 130.415 ;
        RECT 91.215 129.915 91.385 130.415 ;
        RECT 91.645 129.450 91.815 130.415 ;
        RECT 92.075 129.915 92.245 130.415 ;
        RECT 92.505 129.450 92.675 130.415 ;
        RECT 92.935 129.915 93.105 130.415 ;
        RECT 93.365 129.450 93.535 130.415 ;
        RECT 93.795 129.915 93.965 130.415 ;
        RECT 100.305 129.915 100.475 130.415 ;
        RECT 100.735 129.450 100.905 130.415 ;
        RECT 101.165 129.915 101.335 130.415 ;
        RECT 101.595 129.450 101.765 130.415 ;
        RECT 102.025 129.915 102.195 130.415 ;
        RECT 102.455 129.450 102.625 130.415 ;
        RECT 102.885 129.915 103.055 130.415 ;
        RECT 103.315 129.450 103.485 130.415 ;
        RECT 103.745 129.915 103.915 130.415 ;
        RECT 104.175 129.450 104.345 130.415 ;
        RECT 104.605 129.915 104.775 130.415 ;
        RECT 111.115 129.915 111.285 130.415 ;
        RECT 111.545 129.450 111.715 130.415 ;
        RECT 111.975 129.915 112.145 130.415 ;
        RECT 112.405 129.450 112.575 130.415 ;
        RECT 112.835 129.915 113.005 130.415 ;
        RECT 113.265 129.450 113.435 130.415 ;
        RECT 113.695 129.915 113.865 130.415 ;
        RECT 114.125 129.450 114.295 130.415 ;
        RECT 114.555 129.915 114.725 130.415 ;
        RECT 114.985 129.450 115.155 130.415 ;
        RECT 115.415 129.915 115.585 130.415 ;
        RECT 121.925 129.915 122.095 130.415 ;
        RECT 122.355 129.450 122.525 130.415 ;
        RECT 122.785 129.915 122.955 130.415 ;
        RECT 123.215 129.450 123.385 130.415 ;
        RECT 123.645 129.915 123.815 130.415 ;
        RECT 124.075 129.450 124.245 130.415 ;
        RECT 124.505 129.915 124.675 130.415 ;
        RECT 124.935 129.450 125.105 130.415 ;
        RECT 125.365 129.915 125.535 130.415 ;
        RECT 125.795 129.450 125.965 130.415 ;
        RECT 126.225 129.915 126.395 130.415 ;
        RECT 132.735 129.915 132.905 130.415 ;
        RECT 133.165 129.450 133.335 130.415 ;
        RECT 133.595 129.915 133.765 130.415 ;
        RECT 134.025 129.450 134.195 130.415 ;
        RECT 134.455 129.915 134.625 130.415 ;
        RECT 134.885 129.450 135.055 130.415 ;
        RECT 135.315 129.915 135.485 130.415 ;
        RECT 135.745 129.450 135.915 130.415 ;
        RECT 136.175 129.915 136.345 130.415 ;
        RECT 136.605 129.450 136.775 130.415 ;
        RECT 137.035 129.915 137.205 130.415 ;
        RECT 139.910 130.110 140.080 130.800 ;
        RECT 140.330 129.850 140.750 130.020 ;
        RECT 141.020 129.850 141.440 130.020 ;
        RECT 16.820 129.200 143.005 129.450 ;
        RECT 16.760 120.645 140.690 120.895 ;
        RECT 139.145 120.100 139.475 120.270 ;
        RECT 17.240 119.095 17.410 119.645 ;
        RECT 17.845 119.095 18.015 119.645 ;
        RECT 19.025 119.095 19.195 119.645 ;
        RECT 21.040 119.225 21.210 119.555 ;
        RECT 21.760 119.535 22.860 119.705 ;
        RECT 21.760 119.075 22.860 119.245 ;
        RECT 31.850 119.225 32.020 119.555 ;
        RECT 32.570 119.535 33.670 119.705 ;
        RECT 32.570 119.075 33.670 119.245 ;
        RECT 42.660 119.225 42.830 119.555 ;
        RECT 43.380 119.535 44.480 119.705 ;
        RECT 43.380 119.075 44.480 119.245 ;
        RECT 53.470 119.225 53.640 119.555 ;
        RECT 54.190 119.535 55.290 119.705 ;
        RECT 54.190 119.075 55.290 119.245 ;
        RECT 64.280 119.225 64.450 119.555 ;
        RECT 65.000 119.535 66.100 119.705 ;
        RECT 65.000 119.075 66.100 119.245 ;
        RECT 75.090 119.225 75.260 119.555 ;
        RECT 75.810 119.535 76.910 119.705 ;
        RECT 75.810 119.075 76.910 119.245 ;
        RECT 85.900 119.225 86.070 119.555 ;
        RECT 86.620 119.535 87.720 119.705 ;
        RECT 86.620 119.075 87.720 119.245 ;
        RECT 96.710 119.225 96.880 119.555 ;
        RECT 97.430 119.535 98.530 119.705 ;
        RECT 97.430 119.075 98.530 119.245 ;
        RECT 107.520 119.225 107.690 119.555 ;
        RECT 108.240 119.535 109.340 119.705 ;
        RECT 108.240 119.075 109.340 119.245 ;
        RECT 118.330 119.225 118.500 119.555 ;
        RECT 119.050 119.535 120.150 119.705 ;
        RECT 119.050 119.075 120.150 119.245 ;
        RECT 129.140 119.225 129.310 119.555 ;
        RECT 129.860 119.535 130.960 119.705 ;
        RECT 138.920 119.400 139.090 119.820 ;
        RECT 139.700 119.400 139.870 120.645 ;
        RECT 140.095 120.100 140.425 120.270 ;
        RECT 140.480 119.400 140.650 119.820 ;
        RECT 129.860 119.075 130.960 119.245 ;
        RECT 22.125 118.840 22.415 119.075 ;
        RECT 32.935 118.840 33.225 119.075 ;
        RECT 43.745 118.840 44.035 119.075 ;
        RECT 54.555 118.840 54.845 119.075 ;
        RECT 65.365 118.840 65.655 119.075 ;
        RECT 76.175 118.840 76.465 119.075 ;
        RECT 86.985 118.840 87.275 119.075 ;
        RECT 97.795 118.840 98.085 119.075 ;
        RECT 108.605 118.840 108.895 119.075 ;
        RECT 119.415 118.840 119.705 119.075 ;
        RECT 130.225 118.840 130.515 119.075 ;
        RECT 17.470 118.600 17.800 118.770 ;
        RECT 18.175 118.645 18.865 118.815 ;
        RECT 20.025 118.510 23.795 118.840 ;
        RECT 30.835 118.510 34.605 118.840 ;
        RECT 41.645 118.510 45.415 118.840 ;
        RECT 52.455 118.510 56.225 118.840 ;
        RECT 63.265 118.510 67.035 118.840 ;
        RECT 74.075 118.510 77.845 118.840 ;
        RECT 84.885 118.510 88.655 118.840 ;
        RECT 95.695 118.510 99.465 118.840 ;
        RECT 106.505 118.510 110.275 118.840 ;
        RECT 117.315 118.510 121.085 118.840 ;
        RECT 128.125 118.510 131.895 118.840 ;
        RECT 19.595 116.170 19.765 118.305 ;
        RECT 20.025 117.305 20.195 118.510 ;
        RECT 20.455 117.305 20.625 118.305 ;
        RECT 20.885 117.305 21.055 118.510 ;
        RECT 21.315 117.305 21.485 118.305 ;
        RECT 21.745 117.305 21.915 118.510 ;
        RECT 22.175 117.305 22.345 118.305 ;
        RECT 22.605 117.305 22.775 118.510 ;
        RECT 23.035 117.305 23.205 118.305 ;
        RECT 23.465 117.305 23.635 118.510 ;
        RECT 23.895 117.305 24.065 118.305 ;
        RECT 25.020 117.480 25.190 117.810 ;
        RECT 17.460 115.860 17.960 116.030 ;
        RECT 18.230 115.860 18.730 116.030 ;
        RECT 16.940 115.645 17.270 115.815 ;
        RECT 29.875 115.775 30.045 116.720 ;
        RECT 30.405 116.170 30.575 118.305 ;
        RECT 30.835 117.305 31.005 118.510 ;
        RECT 31.265 117.305 31.435 118.305 ;
        RECT 31.695 117.305 31.865 118.510 ;
        RECT 32.125 117.305 32.295 118.305 ;
        RECT 32.555 117.305 32.725 118.510 ;
        RECT 32.985 117.305 33.155 118.305 ;
        RECT 33.415 117.305 33.585 118.510 ;
        RECT 33.845 117.305 34.015 118.305 ;
        RECT 34.275 117.305 34.445 118.510 ;
        RECT 34.705 117.305 34.875 118.305 ;
        RECT 35.830 117.480 36.000 117.810 ;
        RECT 40.685 115.775 40.855 116.720 ;
        RECT 41.215 116.170 41.385 118.305 ;
        RECT 41.645 117.305 41.815 118.510 ;
        RECT 42.075 117.305 42.245 118.305 ;
        RECT 42.505 117.305 42.675 118.510 ;
        RECT 42.935 117.305 43.105 118.305 ;
        RECT 43.365 117.305 43.535 118.510 ;
        RECT 43.795 117.305 43.965 118.305 ;
        RECT 44.225 117.305 44.395 118.510 ;
        RECT 44.655 117.305 44.825 118.305 ;
        RECT 45.085 117.305 45.255 118.510 ;
        RECT 45.515 117.305 45.685 118.305 ;
        RECT 46.640 117.480 46.810 117.810 ;
        RECT 51.495 115.775 51.665 116.720 ;
        RECT 52.025 116.170 52.195 118.305 ;
        RECT 52.455 117.305 52.625 118.510 ;
        RECT 52.885 117.305 53.055 118.305 ;
        RECT 53.315 117.305 53.485 118.510 ;
        RECT 53.745 117.305 53.915 118.305 ;
        RECT 54.175 117.305 54.345 118.510 ;
        RECT 54.605 117.305 54.775 118.305 ;
        RECT 55.035 117.305 55.205 118.510 ;
        RECT 55.465 117.305 55.635 118.305 ;
        RECT 55.895 117.305 56.065 118.510 ;
        RECT 56.325 117.305 56.495 118.305 ;
        RECT 57.450 117.480 57.620 117.810 ;
        RECT 62.305 115.775 62.475 116.720 ;
        RECT 62.835 116.170 63.005 118.305 ;
        RECT 63.265 117.305 63.435 118.510 ;
        RECT 63.695 117.305 63.865 118.305 ;
        RECT 64.125 117.305 64.295 118.510 ;
        RECT 64.555 117.305 64.725 118.305 ;
        RECT 64.985 117.305 65.155 118.510 ;
        RECT 65.415 117.305 65.585 118.305 ;
        RECT 65.845 117.305 66.015 118.510 ;
        RECT 66.275 117.305 66.445 118.305 ;
        RECT 66.705 117.305 66.875 118.510 ;
        RECT 67.135 117.305 67.305 118.305 ;
        RECT 68.260 117.480 68.430 117.810 ;
        RECT 73.115 115.775 73.285 116.720 ;
        RECT 73.645 116.170 73.815 118.305 ;
        RECT 74.075 117.305 74.245 118.510 ;
        RECT 74.505 117.305 74.675 118.305 ;
        RECT 74.935 117.305 75.105 118.510 ;
        RECT 75.365 117.305 75.535 118.305 ;
        RECT 75.795 117.305 75.965 118.510 ;
        RECT 76.225 117.305 76.395 118.305 ;
        RECT 76.655 117.305 76.825 118.510 ;
        RECT 77.085 117.305 77.255 118.305 ;
        RECT 77.515 117.305 77.685 118.510 ;
        RECT 77.945 117.305 78.115 118.305 ;
        RECT 79.070 117.480 79.240 117.810 ;
        RECT 83.925 115.775 84.095 116.720 ;
        RECT 84.455 116.170 84.625 118.305 ;
        RECT 84.885 117.305 85.055 118.510 ;
        RECT 85.315 117.305 85.485 118.305 ;
        RECT 85.745 117.305 85.915 118.510 ;
        RECT 86.175 117.305 86.345 118.305 ;
        RECT 86.605 117.305 86.775 118.510 ;
        RECT 87.035 117.305 87.205 118.305 ;
        RECT 87.465 117.305 87.635 118.510 ;
        RECT 87.895 117.305 88.065 118.305 ;
        RECT 88.325 117.305 88.495 118.510 ;
        RECT 88.755 117.305 88.925 118.305 ;
        RECT 89.880 117.480 90.050 117.810 ;
        RECT 94.735 115.775 94.905 116.720 ;
        RECT 95.265 116.170 95.435 118.305 ;
        RECT 95.695 117.305 95.865 118.510 ;
        RECT 96.125 117.305 96.295 118.305 ;
        RECT 96.555 117.305 96.725 118.510 ;
        RECT 96.985 117.305 97.155 118.305 ;
        RECT 97.415 117.305 97.585 118.510 ;
        RECT 97.845 117.305 98.015 118.305 ;
        RECT 98.275 117.305 98.445 118.510 ;
        RECT 98.705 117.305 98.875 118.305 ;
        RECT 99.135 117.305 99.305 118.510 ;
        RECT 99.565 117.305 99.735 118.305 ;
        RECT 100.690 117.480 100.860 117.810 ;
        RECT 105.545 115.775 105.715 116.720 ;
        RECT 106.075 116.170 106.245 118.305 ;
        RECT 106.505 117.305 106.675 118.510 ;
        RECT 106.935 117.305 107.105 118.305 ;
        RECT 107.365 117.305 107.535 118.510 ;
        RECT 107.795 117.305 107.965 118.305 ;
        RECT 108.225 117.305 108.395 118.510 ;
        RECT 108.655 117.305 108.825 118.305 ;
        RECT 109.085 117.305 109.255 118.510 ;
        RECT 109.515 117.305 109.685 118.305 ;
        RECT 109.945 117.305 110.115 118.510 ;
        RECT 110.375 117.305 110.545 118.305 ;
        RECT 111.500 117.480 111.670 117.810 ;
        RECT 116.355 115.775 116.525 116.720 ;
        RECT 116.885 116.170 117.055 118.305 ;
        RECT 117.315 117.305 117.485 118.510 ;
        RECT 117.745 117.305 117.915 118.305 ;
        RECT 118.175 117.305 118.345 118.510 ;
        RECT 118.605 117.305 118.775 118.305 ;
        RECT 119.035 117.305 119.205 118.510 ;
        RECT 119.465 117.305 119.635 118.305 ;
        RECT 119.895 117.305 120.065 118.510 ;
        RECT 120.325 117.305 120.495 118.305 ;
        RECT 120.755 117.305 120.925 118.510 ;
        RECT 121.185 117.305 121.355 118.305 ;
        RECT 122.310 117.480 122.480 117.810 ;
        RECT 127.165 115.775 127.335 116.720 ;
        RECT 127.695 116.170 127.865 118.305 ;
        RECT 128.125 117.305 128.295 118.510 ;
        RECT 128.555 117.305 128.725 118.305 ;
        RECT 128.985 117.305 129.155 118.510 ;
        RECT 129.415 117.305 129.585 118.305 ;
        RECT 129.845 117.305 130.015 118.510 ;
        RECT 130.275 117.305 130.445 118.305 ;
        RECT 130.705 117.305 130.875 118.510 ;
        RECT 131.135 117.305 131.305 118.305 ;
        RECT 131.565 117.305 131.735 118.510 ;
        RECT 131.995 117.305 132.165 118.305 ;
        RECT 133.120 117.480 133.290 117.810 ;
        RECT 138.920 117.590 139.090 118.010 ;
        RECT 139.700 117.590 139.870 118.010 ;
        RECT 140.480 117.590 140.650 118.010 ;
        RECT 139.145 117.140 139.475 117.310 ;
        RECT 140.095 117.140 140.425 117.310 ;
        RECT 137.975 115.775 138.145 116.720 ;
        RECT 17.460 115.430 17.960 115.600 ;
        RECT 18.230 115.430 18.730 115.600 ;
        RECT 20.055 115.445 30.045 115.775 ;
        RECT 30.865 115.445 40.855 115.775 ;
        RECT 41.675 115.445 51.665 115.775 ;
        RECT 52.485 115.445 62.475 115.775 ;
        RECT 63.295 115.445 73.285 115.775 ;
        RECT 74.105 115.445 84.095 115.775 ;
        RECT 84.915 115.445 94.905 115.775 ;
        RECT 95.725 115.445 105.715 115.775 ;
        RECT 106.535 115.445 116.525 115.775 ;
        RECT 117.345 115.445 127.335 115.775 ;
        RECT 128.155 115.445 138.145 115.775 ;
        RECT 29.875 115.110 30.045 115.445 ;
        RECT 40.685 115.110 40.855 115.445 ;
        RECT 51.495 115.110 51.665 115.445 ;
        RECT 62.305 115.110 62.475 115.445 ;
        RECT 73.115 115.110 73.285 115.445 ;
        RECT 83.925 115.110 84.095 115.445 ;
        RECT 94.735 115.110 94.905 115.445 ;
        RECT 105.545 115.110 105.715 115.445 ;
        RECT 116.355 115.110 116.525 115.445 ;
        RECT 127.165 115.110 127.335 115.445 ;
        RECT 137.975 115.110 138.145 115.445 ;
        RECT 138.960 115.110 139.130 116.730 ;
        RECT 140.440 116.310 140.610 116.730 ;
        RECT 139.620 115.860 139.950 116.030 ;
        RECT 16.705 114.860 19.285 115.110 ;
        RECT 19.560 114.860 138.185 115.110 ;
        RECT 138.865 114.860 140.705 115.110 ;
        RECT 16.745 111.830 140.675 112.080 ;
        RECT 139.130 111.285 139.460 111.455 ;
        RECT 17.225 110.280 17.395 110.830 ;
        RECT 17.830 110.280 18.000 110.830 ;
        RECT 19.010 110.280 19.180 110.830 ;
        RECT 21.025 110.410 21.195 110.740 ;
        RECT 21.745 110.720 22.845 110.890 ;
        RECT 21.745 110.260 22.845 110.430 ;
        RECT 31.835 110.410 32.005 110.740 ;
        RECT 32.555 110.720 33.655 110.890 ;
        RECT 32.555 110.260 33.655 110.430 ;
        RECT 42.645 110.410 42.815 110.740 ;
        RECT 43.365 110.720 44.465 110.890 ;
        RECT 43.365 110.260 44.465 110.430 ;
        RECT 53.455 110.410 53.625 110.740 ;
        RECT 54.175 110.720 55.275 110.890 ;
        RECT 54.175 110.260 55.275 110.430 ;
        RECT 64.265 110.410 64.435 110.740 ;
        RECT 64.985 110.720 66.085 110.890 ;
        RECT 64.985 110.260 66.085 110.430 ;
        RECT 75.075 110.410 75.245 110.740 ;
        RECT 75.795 110.720 76.895 110.890 ;
        RECT 75.795 110.260 76.895 110.430 ;
        RECT 85.885 110.410 86.055 110.740 ;
        RECT 86.605 110.720 87.705 110.890 ;
        RECT 86.605 110.260 87.705 110.430 ;
        RECT 96.695 110.410 96.865 110.740 ;
        RECT 97.415 110.720 98.515 110.890 ;
        RECT 97.415 110.260 98.515 110.430 ;
        RECT 107.505 110.410 107.675 110.740 ;
        RECT 108.225 110.720 109.325 110.890 ;
        RECT 108.225 110.260 109.325 110.430 ;
        RECT 118.315 110.410 118.485 110.740 ;
        RECT 119.035 110.720 120.135 110.890 ;
        RECT 119.035 110.260 120.135 110.430 ;
        RECT 129.125 110.410 129.295 110.740 ;
        RECT 129.845 110.720 130.945 110.890 ;
        RECT 138.905 110.585 139.075 111.005 ;
        RECT 139.685 110.585 139.855 111.830 ;
        RECT 140.080 111.285 140.410 111.455 ;
        RECT 140.465 110.585 140.635 111.005 ;
        RECT 129.845 110.260 130.945 110.430 ;
        RECT 22.110 110.025 22.400 110.260 ;
        RECT 32.920 110.025 33.210 110.260 ;
        RECT 43.730 110.025 44.020 110.260 ;
        RECT 54.540 110.025 54.830 110.260 ;
        RECT 65.350 110.025 65.640 110.260 ;
        RECT 76.160 110.025 76.450 110.260 ;
        RECT 86.970 110.025 87.260 110.260 ;
        RECT 97.780 110.025 98.070 110.260 ;
        RECT 108.590 110.025 108.880 110.260 ;
        RECT 119.400 110.025 119.690 110.260 ;
        RECT 130.210 110.025 130.500 110.260 ;
        RECT 17.455 109.785 17.785 109.955 ;
        RECT 18.160 109.830 18.850 110.000 ;
        RECT 20.010 109.695 23.780 110.025 ;
        RECT 30.820 109.695 34.590 110.025 ;
        RECT 41.630 109.695 45.400 110.025 ;
        RECT 52.440 109.695 56.210 110.025 ;
        RECT 63.250 109.695 67.020 110.025 ;
        RECT 74.060 109.695 77.830 110.025 ;
        RECT 84.870 109.695 88.640 110.025 ;
        RECT 95.680 109.695 99.450 110.025 ;
        RECT 106.490 109.695 110.260 110.025 ;
        RECT 117.300 109.695 121.070 110.025 ;
        RECT 128.110 109.695 131.880 110.025 ;
        RECT 19.580 107.355 19.750 109.490 ;
        RECT 20.010 108.490 20.180 109.695 ;
        RECT 20.440 108.490 20.610 109.490 ;
        RECT 20.870 108.490 21.040 109.695 ;
        RECT 21.300 108.490 21.470 109.490 ;
        RECT 21.730 108.490 21.900 109.695 ;
        RECT 22.160 108.490 22.330 109.490 ;
        RECT 22.590 108.490 22.760 109.695 ;
        RECT 23.020 108.490 23.190 109.490 ;
        RECT 23.450 108.490 23.620 109.695 ;
        RECT 23.880 108.490 24.050 109.490 ;
        RECT 25.005 108.665 25.175 108.995 ;
        RECT 17.445 107.045 17.945 107.215 ;
        RECT 18.215 107.045 18.715 107.215 ;
        RECT 16.925 106.830 17.255 107.000 ;
        RECT 29.860 106.960 30.030 107.905 ;
        RECT 30.390 107.355 30.560 109.490 ;
        RECT 30.820 108.490 30.990 109.695 ;
        RECT 31.250 108.490 31.420 109.490 ;
        RECT 31.680 108.490 31.850 109.695 ;
        RECT 32.110 108.490 32.280 109.490 ;
        RECT 32.540 108.490 32.710 109.695 ;
        RECT 32.970 108.490 33.140 109.490 ;
        RECT 33.400 108.490 33.570 109.695 ;
        RECT 33.830 108.490 34.000 109.490 ;
        RECT 34.260 108.490 34.430 109.695 ;
        RECT 34.690 108.490 34.860 109.490 ;
        RECT 35.815 108.665 35.985 108.995 ;
        RECT 40.670 106.960 40.840 107.905 ;
        RECT 41.200 107.355 41.370 109.490 ;
        RECT 41.630 108.490 41.800 109.695 ;
        RECT 42.060 108.490 42.230 109.490 ;
        RECT 42.490 108.490 42.660 109.695 ;
        RECT 42.920 108.490 43.090 109.490 ;
        RECT 43.350 108.490 43.520 109.695 ;
        RECT 43.780 108.490 43.950 109.490 ;
        RECT 44.210 108.490 44.380 109.695 ;
        RECT 44.640 108.490 44.810 109.490 ;
        RECT 45.070 108.490 45.240 109.695 ;
        RECT 45.500 108.490 45.670 109.490 ;
        RECT 46.625 108.665 46.795 108.995 ;
        RECT 51.480 106.960 51.650 107.905 ;
        RECT 52.010 107.355 52.180 109.490 ;
        RECT 52.440 108.490 52.610 109.695 ;
        RECT 52.870 108.490 53.040 109.490 ;
        RECT 53.300 108.490 53.470 109.695 ;
        RECT 53.730 108.490 53.900 109.490 ;
        RECT 54.160 108.490 54.330 109.695 ;
        RECT 54.590 108.490 54.760 109.490 ;
        RECT 55.020 108.490 55.190 109.695 ;
        RECT 55.450 108.490 55.620 109.490 ;
        RECT 55.880 108.490 56.050 109.695 ;
        RECT 56.310 108.490 56.480 109.490 ;
        RECT 57.435 108.665 57.605 108.995 ;
        RECT 62.290 106.960 62.460 107.905 ;
        RECT 62.820 107.355 62.990 109.490 ;
        RECT 63.250 108.490 63.420 109.695 ;
        RECT 63.680 108.490 63.850 109.490 ;
        RECT 64.110 108.490 64.280 109.695 ;
        RECT 64.540 108.490 64.710 109.490 ;
        RECT 64.970 108.490 65.140 109.695 ;
        RECT 65.400 108.490 65.570 109.490 ;
        RECT 65.830 108.490 66.000 109.695 ;
        RECT 66.260 108.490 66.430 109.490 ;
        RECT 66.690 108.490 66.860 109.695 ;
        RECT 67.120 108.490 67.290 109.490 ;
        RECT 68.245 108.665 68.415 108.995 ;
        RECT 73.100 106.960 73.270 107.905 ;
        RECT 73.630 107.355 73.800 109.490 ;
        RECT 74.060 108.490 74.230 109.695 ;
        RECT 74.490 108.490 74.660 109.490 ;
        RECT 74.920 108.490 75.090 109.695 ;
        RECT 75.350 108.490 75.520 109.490 ;
        RECT 75.780 108.490 75.950 109.695 ;
        RECT 76.210 108.490 76.380 109.490 ;
        RECT 76.640 108.490 76.810 109.695 ;
        RECT 77.070 108.490 77.240 109.490 ;
        RECT 77.500 108.490 77.670 109.695 ;
        RECT 77.930 108.490 78.100 109.490 ;
        RECT 79.055 108.665 79.225 108.995 ;
        RECT 83.910 106.960 84.080 107.905 ;
        RECT 84.440 107.355 84.610 109.490 ;
        RECT 84.870 108.490 85.040 109.695 ;
        RECT 85.300 108.490 85.470 109.490 ;
        RECT 85.730 108.490 85.900 109.695 ;
        RECT 86.160 108.490 86.330 109.490 ;
        RECT 86.590 108.490 86.760 109.695 ;
        RECT 87.020 108.490 87.190 109.490 ;
        RECT 87.450 108.490 87.620 109.695 ;
        RECT 87.880 108.490 88.050 109.490 ;
        RECT 88.310 108.490 88.480 109.695 ;
        RECT 88.740 108.490 88.910 109.490 ;
        RECT 89.865 108.665 90.035 108.995 ;
        RECT 94.720 106.960 94.890 107.905 ;
        RECT 95.250 107.355 95.420 109.490 ;
        RECT 95.680 108.490 95.850 109.695 ;
        RECT 96.110 108.490 96.280 109.490 ;
        RECT 96.540 108.490 96.710 109.695 ;
        RECT 96.970 108.490 97.140 109.490 ;
        RECT 97.400 108.490 97.570 109.695 ;
        RECT 97.830 108.490 98.000 109.490 ;
        RECT 98.260 108.490 98.430 109.695 ;
        RECT 98.690 108.490 98.860 109.490 ;
        RECT 99.120 108.490 99.290 109.695 ;
        RECT 99.550 108.490 99.720 109.490 ;
        RECT 100.675 108.665 100.845 108.995 ;
        RECT 105.530 106.960 105.700 107.905 ;
        RECT 106.060 107.355 106.230 109.490 ;
        RECT 106.490 108.490 106.660 109.695 ;
        RECT 106.920 108.490 107.090 109.490 ;
        RECT 107.350 108.490 107.520 109.695 ;
        RECT 107.780 108.490 107.950 109.490 ;
        RECT 108.210 108.490 108.380 109.695 ;
        RECT 108.640 108.490 108.810 109.490 ;
        RECT 109.070 108.490 109.240 109.695 ;
        RECT 109.500 108.490 109.670 109.490 ;
        RECT 109.930 108.490 110.100 109.695 ;
        RECT 110.360 108.490 110.530 109.490 ;
        RECT 111.485 108.665 111.655 108.995 ;
        RECT 116.340 106.960 116.510 107.905 ;
        RECT 116.870 107.355 117.040 109.490 ;
        RECT 117.300 108.490 117.470 109.695 ;
        RECT 117.730 108.490 117.900 109.490 ;
        RECT 118.160 108.490 118.330 109.695 ;
        RECT 118.590 108.490 118.760 109.490 ;
        RECT 119.020 108.490 119.190 109.695 ;
        RECT 119.450 108.490 119.620 109.490 ;
        RECT 119.880 108.490 120.050 109.695 ;
        RECT 120.310 108.490 120.480 109.490 ;
        RECT 120.740 108.490 120.910 109.695 ;
        RECT 121.170 108.490 121.340 109.490 ;
        RECT 122.295 108.665 122.465 108.995 ;
        RECT 127.150 106.960 127.320 107.905 ;
        RECT 127.680 107.355 127.850 109.490 ;
        RECT 128.110 108.490 128.280 109.695 ;
        RECT 128.540 108.490 128.710 109.490 ;
        RECT 128.970 108.490 129.140 109.695 ;
        RECT 129.400 108.490 129.570 109.490 ;
        RECT 129.830 108.490 130.000 109.695 ;
        RECT 130.260 108.490 130.430 109.490 ;
        RECT 130.690 108.490 130.860 109.695 ;
        RECT 131.120 108.490 131.290 109.490 ;
        RECT 131.550 108.490 131.720 109.695 ;
        RECT 131.980 108.490 132.150 109.490 ;
        RECT 133.105 108.665 133.275 108.995 ;
        RECT 138.905 108.775 139.075 109.195 ;
        RECT 139.685 108.775 139.855 109.195 ;
        RECT 140.465 108.775 140.635 109.195 ;
        RECT 139.130 108.325 139.460 108.495 ;
        RECT 140.080 108.325 140.410 108.495 ;
        RECT 137.960 106.960 138.130 107.905 ;
        RECT 17.445 106.615 17.945 106.785 ;
        RECT 18.215 106.615 18.715 106.785 ;
        RECT 20.040 106.630 30.030 106.960 ;
        RECT 30.850 106.630 40.840 106.960 ;
        RECT 41.660 106.630 51.650 106.960 ;
        RECT 52.470 106.630 62.460 106.960 ;
        RECT 63.280 106.630 73.270 106.960 ;
        RECT 74.090 106.630 84.080 106.960 ;
        RECT 84.900 106.630 94.890 106.960 ;
        RECT 95.710 106.630 105.700 106.960 ;
        RECT 106.520 106.630 116.510 106.960 ;
        RECT 117.330 106.630 127.320 106.960 ;
        RECT 128.140 106.630 138.130 106.960 ;
        RECT 29.860 106.295 30.030 106.630 ;
        RECT 40.670 106.295 40.840 106.630 ;
        RECT 51.480 106.295 51.650 106.630 ;
        RECT 62.290 106.295 62.460 106.630 ;
        RECT 73.100 106.295 73.270 106.630 ;
        RECT 83.910 106.295 84.080 106.630 ;
        RECT 94.720 106.295 94.890 106.630 ;
        RECT 105.530 106.295 105.700 106.630 ;
        RECT 116.340 106.295 116.510 106.630 ;
        RECT 127.150 106.295 127.320 106.630 ;
        RECT 137.960 106.295 138.130 106.630 ;
        RECT 138.945 106.295 139.115 107.915 ;
        RECT 140.425 107.495 140.595 107.915 ;
        RECT 139.605 107.045 139.935 107.215 ;
        RECT 16.690 106.045 19.270 106.295 ;
        RECT 19.545 106.045 138.170 106.295 ;
        RECT 138.850 106.045 140.690 106.295 ;
        RECT 16.375 101.995 140.305 102.245 ;
        RECT 138.760 101.450 139.090 101.620 ;
        RECT 16.855 100.445 17.025 100.995 ;
        RECT 17.460 100.445 17.630 100.995 ;
        RECT 18.640 100.445 18.810 100.995 ;
        RECT 20.655 100.575 20.825 100.905 ;
        RECT 21.375 100.885 22.475 101.055 ;
        RECT 21.375 100.425 22.475 100.595 ;
        RECT 31.465 100.575 31.635 100.905 ;
        RECT 32.185 100.885 33.285 101.055 ;
        RECT 32.185 100.425 33.285 100.595 ;
        RECT 42.275 100.575 42.445 100.905 ;
        RECT 42.995 100.885 44.095 101.055 ;
        RECT 42.995 100.425 44.095 100.595 ;
        RECT 53.085 100.575 53.255 100.905 ;
        RECT 53.805 100.885 54.905 101.055 ;
        RECT 53.805 100.425 54.905 100.595 ;
        RECT 63.895 100.575 64.065 100.905 ;
        RECT 64.615 100.885 65.715 101.055 ;
        RECT 64.615 100.425 65.715 100.595 ;
        RECT 74.705 100.575 74.875 100.905 ;
        RECT 75.425 100.885 76.525 101.055 ;
        RECT 75.425 100.425 76.525 100.595 ;
        RECT 85.515 100.575 85.685 100.905 ;
        RECT 86.235 100.885 87.335 101.055 ;
        RECT 86.235 100.425 87.335 100.595 ;
        RECT 96.325 100.575 96.495 100.905 ;
        RECT 97.045 100.885 98.145 101.055 ;
        RECT 97.045 100.425 98.145 100.595 ;
        RECT 107.135 100.575 107.305 100.905 ;
        RECT 107.855 100.885 108.955 101.055 ;
        RECT 107.855 100.425 108.955 100.595 ;
        RECT 117.945 100.575 118.115 100.905 ;
        RECT 118.665 100.885 119.765 101.055 ;
        RECT 118.665 100.425 119.765 100.595 ;
        RECT 128.755 100.575 128.925 100.905 ;
        RECT 129.475 100.885 130.575 101.055 ;
        RECT 138.535 100.750 138.705 101.170 ;
        RECT 139.315 100.750 139.485 101.995 ;
        RECT 139.710 101.450 140.040 101.620 ;
        RECT 140.095 100.750 140.265 101.170 ;
        RECT 129.475 100.425 130.575 100.595 ;
        RECT 21.740 100.190 22.030 100.425 ;
        RECT 32.550 100.190 32.840 100.425 ;
        RECT 43.360 100.190 43.650 100.425 ;
        RECT 54.170 100.190 54.460 100.425 ;
        RECT 64.980 100.190 65.270 100.425 ;
        RECT 75.790 100.190 76.080 100.425 ;
        RECT 86.600 100.190 86.890 100.425 ;
        RECT 97.410 100.190 97.700 100.425 ;
        RECT 108.220 100.190 108.510 100.425 ;
        RECT 119.030 100.190 119.320 100.425 ;
        RECT 129.840 100.190 130.130 100.425 ;
        RECT 17.085 99.950 17.415 100.120 ;
        RECT 17.790 99.995 18.480 100.165 ;
        RECT 19.640 99.860 23.410 100.190 ;
        RECT 30.450 99.860 34.220 100.190 ;
        RECT 41.260 99.860 45.030 100.190 ;
        RECT 52.070 99.860 55.840 100.190 ;
        RECT 62.880 99.860 66.650 100.190 ;
        RECT 73.690 99.860 77.460 100.190 ;
        RECT 84.500 99.860 88.270 100.190 ;
        RECT 95.310 99.860 99.080 100.190 ;
        RECT 106.120 99.860 109.890 100.190 ;
        RECT 116.930 99.860 120.700 100.190 ;
        RECT 127.740 99.860 131.510 100.190 ;
        RECT 19.210 97.520 19.380 99.655 ;
        RECT 19.640 98.655 19.810 99.860 ;
        RECT 20.070 98.655 20.240 99.655 ;
        RECT 20.500 98.655 20.670 99.860 ;
        RECT 20.930 98.655 21.100 99.655 ;
        RECT 21.360 98.655 21.530 99.860 ;
        RECT 21.790 98.655 21.960 99.655 ;
        RECT 22.220 98.655 22.390 99.860 ;
        RECT 22.650 98.655 22.820 99.655 ;
        RECT 23.080 98.655 23.250 99.860 ;
        RECT 23.510 98.655 23.680 99.655 ;
        RECT 24.635 98.830 24.805 99.160 ;
        RECT 17.075 97.210 17.575 97.380 ;
        RECT 17.845 97.210 18.345 97.380 ;
        RECT 16.555 96.995 16.885 97.165 ;
        RECT 29.490 97.125 29.660 98.070 ;
        RECT 30.020 97.520 30.190 99.655 ;
        RECT 30.450 98.655 30.620 99.860 ;
        RECT 30.880 98.655 31.050 99.655 ;
        RECT 31.310 98.655 31.480 99.860 ;
        RECT 31.740 98.655 31.910 99.655 ;
        RECT 32.170 98.655 32.340 99.860 ;
        RECT 32.600 98.655 32.770 99.655 ;
        RECT 33.030 98.655 33.200 99.860 ;
        RECT 33.460 98.655 33.630 99.655 ;
        RECT 33.890 98.655 34.060 99.860 ;
        RECT 34.320 98.655 34.490 99.655 ;
        RECT 35.445 98.830 35.615 99.160 ;
        RECT 40.300 97.125 40.470 98.070 ;
        RECT 40.830 97.520 41.000 99.655 ;
        RECT 41.260 98.655 41.430 99.860 ;
        RECT 41.690 98.655 41.860 99.655 ;
        RECT 42.120 98.655 42.290 99.860 ;
        RECT 42.550 98.655 42.720 99.655 ;
        RECT 42.980 98.655 43.150 99.860 ;
        RECT 43.410 98.655 43.580 99.655 ;
        RECT 43.840 98.655 44.010 99.860 ;
        RECT 44.270 98.655 44.440 99.655 ;
        RECT 44.700 98.655 44.870 99.860 ;
        RECT 45.130 98.655 45.300 99.655 ;
        RECT 46.255 98.830 46.425 99.160 ;
        RECT 51.110 97.125 51.280 98.070 ;
        RECT 51.640 97.520 51.810 99.655 ;
        RECT 52.070 98.655 52.240 99.860 ;
        RECT 52.500 98.655 52.670 99.655 ;
        RECT 52.930 98.655 53.100 99.860 ;
        RECT 53.360 98.655 53.530 99.655 ;
        RECT 53.790 98.655 53.960 99.860 ;
        RECT 54.220 98.655 54.390 99.655 ;
        RECT 54.650 98.655 54.820 99.860 ;
        RECT 55.080 98.655 55.250 99.655 ;
        RECT 55.510 98.655 55.680 99.860 ;
        RECT 55.940 98.655 56.110 99.655 ;
        RECT 57.065 98.830 57.235 99.160 ;
        RECT 61.920 97.125 62.090 98.070 ;
        RECT 62.450 97.520 62.620 99.655 ;
        RECT 62.880 98.655 63.050 99.860 ;
        RECT 63.310 98.655 63.480 99.655 ;
        RECT 63.740 98.655 63.910 99.860 ;
        RECT 64.170 98.655 64.340 99.655 ;
        RECT 64.600 98.655 64.770 99.860 ;
        RECT 65.030 98.655 65.200 99.655 ;
        RECT 65.460 98.655 65.630 99.860 ;
        RECT 65.890 98.655 66.060 99.655 ;
        RECT 66.320 98.655 66.490 99.860 ;
        RECT 66.750 98.655 66.920 99.655 ;
        RECT 67.875 98.830 68.045 99.160 ;
        RECT 72.730 97.125 72.900 98.070 ;
        RECT 73.260 97.520 73.430 99.655 ;
        RECT 73.690 98.655 73.860 99.860 ;
        RECT 74.120 98.655 74.290 99.655 ;
        RECT 74.550 98.655 74.720 99.860 ;
        RECT 74.980 98.655 75.150 99.655 ;
        RECT 75.410 98.655 75.580 99.860 ;
        RECT 75.840 98.655 76.010 99.655 ;
        RECT 76.270 98.655 76.440 99.860 ;
        RECT 76.700 98.655 76.870 99.655 ;
        RECT 77.130 98.655 77.300 99.860 ;
        RECT 77.560 98.655 77.730 99.655 ;
        RECT 78.685 98.830 78.855 99.160 ;
        RECT 83.540 97.125 83.710 98.070 ;
        RECT 84.070 97.520 84.240 99.655 ;
        RECT 84.500 98.655 84.670 99.860 ;
        RECT 84.930 98.655 85.100 99.655 ;
        RECT 85.360 98.655 85.530 99.860 ;
        RECT 85.790 98.655 85.960 99.655 ;
        RECT 86.220 98.655 86.390 99.860 ;
        RECT 86.650 98.655 86.820 99.655 ;
        RECT 87.080 98.655 87.250 99.860 ;
        RECT 87.510 98.655 87.680 99.655 ;
        RECT 87.940 98.655 88.110 99.860 ;
        RECT 88.370 98.655 88.540 99.655 ;
        RECT 89.495 98.830 89.665 99.160 ;
        RECT 94.350 97.125 94.520 98.070 ;
        RECT 94.880 97.520 95.050 99.655 ;
        RECT 95.310 98.655 95.480 99.860 ;
        RECT 95.740 98.655 95.910 99.655 ;
        RECT 96.170 98.655 96.340 99.860 ;
        RECT 96.600 98.655 96.770 99.655 ;
        RECT 97.030 98.655 97.200 99.860 ;
        RECT 97.460 98.655 97.630 99.655 ;
        RECT 97.890 98.655 98.060 99.860 ;
        RECT 98.320 98.655 98.490 99.655 ;
        RECT 98.750 98.655 98.920 99.860 ;
        RECT 99.180 98.655 99.350 99.655 ;
        RECT 100.305 98.830 100.475 99.160 ;
        RECT 105.160 97.125 105.330 98.070 ;
        RECT 105.690 97.520 105.860 99.655 ;
        RECT 106.120 98.655 106.290 99.860 ;
        RECT 106.550 98.655 106.720 99.655 ;
        RECT 106.980 98.655 107.150 99.860 ;
        RECT 107.410 98.655 107.580 99.655 ;
        RECT 107.840 98.655 108.010 99.860 ;
        RECT 108.270 98.655 108.440 99.655 ;
        RECT 108.700 98.655 108.870 99.860 ;
        RECT 109.130 98.655 109.300 99.655 ;
        RECT 109.560 98.655 109.730 99.860 ;
        RECT 109.990 98.655 110.160 99.655 ;
        RECT 111.115 98.830 111.285 99.160 ;
        RECT 115.970 97.125 116.140 98.070 ;
        RECT 116.500 97.520 116.670 99.655 ;
        RECT 116.930 98.655 117.100 99.860 ;
        RECT 117.360 98.655 117.530 99.655 ;
        RECT 117.790 98.655 117.960 99.860 ;
        RECT 118.220 98.655 118.390 99.655 ;
        RECT 118.650 98.655 118.820 99.860 ;
        RECT 119.080 98.655 119.250 99.655 ;
        RECT 119.510 98.655 119.680 99.860 ;
        RECT 119.940 98.655 120.110 99.655 ;
        RECT 120.370 98.655 120.540 99.860 ;
        RECT 120.800 98.655 120.970 99.655 ;
        RECT 121.925 98.830 122.095 99.160 ;
        RECT 126.780 97.125 126.950 98.070 ;
        RECT 127.310 97.520 127.480 99.655 ;
        RECT 127.740 98.655 127.910 99.860 ;
        RECT 128.170 98.655 128.340 99.655 ;
        RECT 128.600 98.655 128.770 99.860 ;
        RECT 129.030 98.655 129.200 99.655 ;
        RECT 129.460 98.655 129.630 99.860 ;
        RECT 129.890 98.655 130.060 99.655 ;
        RECT 130.320 98.655 130.490 99.860 ;
        RECT 130.750 98.655 130.920 99.655 ;
        RECT 131.180 98.655 131.350 99.860 ;
        RECT 131.610 98.655 131.780 99.655 ;
        RECT 132.735 98.830 132.905 99.160 ;
        RECT 138.535 98.940 138.705 99.360 ;
        RECT 139.315 98.940 139.485 99.360 ;
        RECT 140.095 98.940 140.265 99.360 ;
        RECT 138.760 98.490 139.090 98.660 ;
        RECT 139.710 98.490 140.040 98.660 ;
        RECT 137.590 97.125 137.760 98.070 ;
        RECT 17.075 96.780 17.575 96.950 ;
        RECT 17.845 96.780 18.345 96.950 ;
        RECT 19.670 96.795 29.660 97.125 ;
        RECT 30.480 96.795 40.470 97.125 ;
        RECT 41.290 96.795 51.280 97.125 ;
        RECT 52.100 96.795 62.090 97.125 ;
        RECT 62.910 96.795 72.900 97.125 ;
        RECT 73.720 96.795 83.710 97.125 ;
        RECT 84.530 96.795 94.520 97.125 ;
        RECT 95.340 96.795 105.330 97.125 ;
        RECT 106.150 96.795 116.140 97.125 ;
        RECT 116.960 96.795 126.950 97.125 ;
        RECT 127.770 96.795 137.760 97.125 ;
        RECT 29.490 96.460 29.660 96.795 ;
        RECT 40.300 96.460 40.470 96.795 ;
        RECT 51.110 96.460 51.280 96.795 ;
        RECT 61.920 96.460 62.090 96.795 ;
        RECT 72.730 96.460 72.900 96.795 ;
        RECT 83.540 96.460 83.710 96.795 ;
        RECT 94.350 96.460 94.520 96.795 ;
        RECT 105.160 96.460 105.330 96.795 ;
        RECT 115.970 96.460 116.140 96.795 ;
        RECT 126.780 96.460 126.950 96.795 ;
        RECT 137.590 96.460 137.760 96.795 ;
        RECT 138.575 96.460 138.745 98.080 ;
        RECT 140.055 97.660 140.225 98.080 ;
        RECT 139.235 97.210 139.565 97.380 ;
        RECT 16.320 96.210 18.900 96.460 ;
        RECT 19.175 96.210 137.800 96.460 ;
        RECT 138.480 96.210 140.320 96.460 ;
      LAYER met1 ;
        RECT 51.850 217.450 89.600 217.850 ;
        RECT 51.850 213.140 52.250 217.450 ;
        RECT 52.850 216.710 53.235 217.000 ;
        RECT 52.850 214.805 53.080 216.710 ;
        RECT 53.220 214.945 53.480 216.185 ;
        RECT 52.850 214.155 53.235 214.805 ;
        RECT 53.865 214.155 54.095 217.000 ;
        RECT 54.725 215.845 54.955 217.000 ;
        RECT 55.585 215.845 55.815 217.000 ;
        RECT 56.445 215.845 56.675 217.000 ;
        RECT 57.305 215.845 57.535 217.000 ;
        RECT 58.165 215.845 58.395 217.000 ;
        RECT 59.025 215.845 59.255 217.000 ;
        RECT 59.885 215.845 60.115 217.000 ;
        RECT 60.580 215.990 60.975 217.000 ;
        RECT 62.050 216.710 62.435 217.000 ;
        RECT 60.580 215.845 60.845 215.990 ;
        RECT 54.725 215.615 60.975 215.845 ;
        RECT 54.725 214.155 54.955 215.615 ;
        RECT 55.585 214.155 55.815 215.615 ;
        RECT 56.445 214.155 56.675 215.615 ;
        RECT 57.305 214.155 57.535 215.615 ;
        RECT 58.165 214.155 58.395 215.615 ;
        RECT 59.025 214.155 59.255 215.615 ;
        RECT 59.885 214.155 60.115 215.615 ;
        RECT 60.580 215.065 60.845 215.615 ;
        RECT 60.580 214.805 60.840 215.065 ;
        RECT 62.050 214.805 62.280 216.710 ;
        RECT 62.420 214.945 62.680 216.185 ;
        RECT 60.580 214.155 60.975 214.805 ;
        RECT 62.050 214.155 62.435 214.805 ;
        RECT 63.065 214.155 63.295 217.000 ;
        RECT 63.925 215.845 64.155 217.000 ;
        RECT 64.785 215.845 65.015 217.000 ;
        RECT 65.645 215.845 65.875 217.000 ;
        RECT 66.505 215.845 66.735 217.000 ;
        RECT 67.365 215.845 67.595 217.000 ;
        RECT 68.225 215.845 68.455 217.000 ;
        RECT 69.085 215.845 69.315 217.000 ;
        RECT 69.780 216.025 70.175 217.000 ;
        RECT 69.775 215.990 70.175 216.025 ;
        RECT 71.250 216.710 71.635 217.000 ;
        RECT 69.775 215.845 70.040 215.990 ;
        RECT 63.925 215.615 70.175 215.845 ;
        RECT 63.925 214.155 64.155 215.615 ;
        RECT 64.785 214.155 65.015 215.615 ;
        RECT 65.645 214.155 65.875 215.615 ;
        RECT 66.505 214.155 66.735 215.615 ;
        RECT 67.365 214.155 67.595 215.615 ;
        RECT 68.225 214.155 68.455 215.615 ;
        RECT 69.085 214.155 69.315 215.615 ;
        RECT 69.775 215.065 70.040 215.615 ;
        RECT 69.780 214.805 70.040 215.065 ;
        RECT 71.250 214.805 71.480 216.710 ;
        RECT 71.620 214.945 71.880 216.185 ;
        RECT 69.780 214.155 70.175 214.805 ;
        RECT 71.250 214.155 71.635 214.805 ;
        RECT 72.265 214.155 72.495 217.000 ;
        RECT 73.125 215.845 73.355 217.000 ;
        RECT 73.985 215.845 74.215 217.000 ;
        RECT 74.845 215.845 75.075 217.000 ;
        RECT 75.705 215.845 75.935 217.000 ;
        RECT 76.565 215.845 76.795 217.000 ;
        RECT 77.425 215.845 77.655 217.000 ;
        RECT 78.285 215.845 78.515 217.000 ;
        RECT 78.980 215.990 79.375 217.000 ;
        RECT 80.450 216.710 80.835 217.000 ;
        RECT 78.980 215.845 79.240 215.990 ;
        RECT 73.125 215.615 79.375 215.845 ;
        RECT 73.125 214.155 73.355 215.615 ;
        RECT 73.985 214.155 74.215 215.615 ;
        RECT 74.845 214.155 75.075 215.615 ;
        RECT 75.705 214.155 75.935 215.615 ;
        RECT 76.565 214.155 76.795 215.615 ;
        RECT 77.425 214.155 77.655 215.615 ;
        RECT 78.285 214.155 78.515 215.615 ;
        RECT 78.980 214.805 79.240 215.615 ;
        RECT 80.450 214.805 80.680 216.710 ;
        RECT 80.820 216.025 81.080 216.185 ;
        RECT 80.820 215.065 81.085 216.025 ;
        RECT 80.820 214.945 81.080 215.065 ;
        RECT 78.980 214.155 79.375 214.805 ;
        RECT 80.450 214.155 80.835 214.805 ;
        RECT 81.465 214.155 81.695 217.000 ;
        RECT 82.325 215.845 82.555 217.000 ;
        RECT 83.185 215.845 83.415 217.000 ;
        RECT 84.045 215.845 84.275 217.000 ;
        RECT 84.905 215.845 85.135 217.000 ;
        RECT 85.765 215.845 85.995 217.000 ;
        RECT 86.625 215.845 86.855 217.000 ;
        RECT 87.485 215.845 87.715 217.000 ;
        RECT 88.180 215.990 88.575 217.000 ;
        RECT 88.180 215.845 88.440 215.990 ;
        RECT 82.325 215.615 88.575 215.845 ;
        RECT 82.325 214.155 82.555 215.615 ;
        RECT 83.185 214.155 83.415 215.615 ;
        RECT 84.045 214.155 84.275 215.615 ;
        RECT 84.905 214.155 85.135 215.615 ;
        RECT 85.765 214.155 85.995 215.615 ;
        RECT 86.625 214.155 86.855 215.615 ;
        RECT 87.485 214.155 87.715 215.615 ;
        RECT 88.180 214.805 88.440 215.615 ;
        RECT 88.180 214.155 88.575 214.805 ;
        RECT 52.430 213.310 89.810 213.710 ;
        RECT 51.850 212.740 89.230 213.140 ;
        RECT 52.850 212.000 53.235 212.290 ;
        RECT 52.850 210.095 53.080 212.000 ;
        RECT 53.220 210.235 53.480 211.475 ;
        RECT 52.850 209.445 53.235 210.095 ;
        RECT 53.865 209.445 54.095 212.290 ;
        RECT 54.725 211.135 54.955 212.290 ;
        RECT 55.585 211.135 55.815 212.290 ;
        RECT 56.445 211.135 56.675 212.290 ;
        RECT 57.305 211.135 57.535 212.290 ;
        RECT 58.165 211.135 58.395 212.290 ;
        RECT 59.025 211.135 59.255 212.290 ;
        RECT 59.885 211.135 60.115 212.290 ;
        RECT 60.580 211.280 60.975 212.290 ;
        RECT 62.050 212.000 62.435 212.290 ;
        RECT 60.580 211.135 60.845 211.280 ;
        RECT 54.725 210.905 60.975 211.135 ;
        RECT 54.725 209.445 54.955 210.905 ;
        RECT 55.585 209.445 55.815 210.905 ;
        RECT 56.445 209.445 56.675 210.905 ;
        RECT 57.305 209.445 57.535 210.905 ;
        RECT 58.165 209.445 58.395 210.905 ;
        RECT 59.025 209.445 59.255 210.905 ;
        RECT 59.885 209.445 60.115 210.905 ;
        RECT 60.580 210.355 60.845 210.905 ;
        RECT 60.580 210.095 60.840 210.355 ;
        RECT 62.050 210.095 62.280 212.000 ;
        RECT 62.420 210.235 62.680 211.475 ;
        RECT 60.580 209.445 60.975 210.095 ;
        RECT 62.050 209.445 62.435 210.095 ;
        RECT 63.065 209.445 63.295 212.290 ;
        RECT 63.925 211.135 64.155 212.290 ;
        RECT 64.785 211.135 65.015 212.290 ;
        RECT 65.645 211.135 65.875 212.290 ;
        RECT 66.505 211.135 66.735 212.290 ;
        RECT 67.365 211.135 67.595 212.290 ;
        RECT 68.225 211.135 68.455 212.290 ;
        RECT 69.085 211.135 69.315 212.290 ;
        RECT 69.780 211.315 70.175 212.290 ;
        RECT 69.775 211.280 70.175 211.315 ;
        RECT 71.250 212.000 71.635 212.290 ;
        RECT 69.775 211.135 70.040 211.280 ;
        RECT 63.925 210.905 70.175 211.135 ;
        RECT 63.925 209.445 64.155 210.905 ;
        RECT 64.785 209.445 65.015 210.905 ;
        RECT 65.645 209.445 65.875 210.905 ;
        RECT 66.505 209.445 66.735 210.905 ;
        RECT 67.365 209.445 67.595 210.905 ;
        RECT 68.225 209.445 68.455 210.905 ;
        RECT 69.085 209.445 69.315 210.905 ;
        RECT 69.775 210.355 70.040 210.905 ;
        RECT 69.780 210.095 70.040 210.355 ;
        RECT 71.250 210.095 71.480 212.000 ;
        RECT 71.620 210.235 71.880 211.475 ;
        RECT 69.780 209.445 70.175 210.095 ;
        RECT 71.250 209.445 71.635 210.095 ;
        RECT 72.265 209.445 72.495 212.290 ;
        RECT 73.125 211.135 73.355 212.290 ;
        RECT 73.985 211.135 74.215 212.290 ;
        RECT 74.845 211.135 75.075 212.290 ;
        RECT 75.705 211.135 75.935 212.290 ;
        RECT 76.565 211.135 76.795 212.290 ;
        RECT 77.425 211.135 77.655 212.290 ;
        RECT 78.285 211.135 78.515 212.290 ;
        RECT 78.980 211.280 79.375 212.290 ;
        RECT 80.450 212.000 80.835 212.290 ;
        RECT 78.980 211.135 79.240 211.280 ;
        RECT 73.125 210.905 79.375 211.135 ;
        RECT 73.125 209.445 73.355 210.905 ;
        RECT 73.985 209.445 74.215 210.905 ;
        RECT 74.845 209.445 75.075 210.905 ;
        RECT 75.705 209.445 75.935 210.905 ;
        RECT 76.565 209.445 76.795 210.905 ;
        RECT 77.425 209.445 77.655 210.905 ;
        RECT 78.285 209.445 78.515 210.905 ;
        RECT 78.980 210.095 79.240 210.905 ;
        RECT 80.450 210.095 80.680 212.000 ;
        RECT 80.820 211.315 81.080 211.475 ;
        RECT 80.820 210.355 81.085 211.315 ;
        RECT 80.820 210.235 81.080 210.355 ;
        RECT 78.980 209.445 79.375 210.095 ;
        RECT 80.450 209.445 80.835 210.095 ;
        RECT 81.465 209.445 81.695 212.290 ;
        RECT 82.325 211.135 82.555 212.290 ;
        RECT 83.185 211.135 83.415 212.290 ;
        RECT 84.045 211.135 84.275 212.290 ;
        RECT 84.905 211.135 85.135 212.290 ;
        RECT 85.765 211.135 85.995 212.290 ;
        RECT 86.625 211.135 86.855 212.290 ;
        RECT 87.485 211.135 87.715 212.290 ;
        RECT 88.180 211.280 88.575 212.290 ;
        RECT 88.180 211.135 88.440 211.280 ;
        RECT 82.325 210.905 88.575 211.135 ;
        RECT 82.325 209.445 82.555 210.905 ;
        RECT 83.185 209.445 83.415 210.905 ;
        RECT 84.045 209.445 84.275 210.905 ;
        RECT 84.905 209.445 85.135 210.905 ;
        RECT 85.765 209.445 85.995 210.905 ;
        RECT 86.625 209.445 86.855 210.905 ;
        RECT 87.485 209.445 87.715 210.905 ;
        RECT 88.180 210.095 88.440 210.905 ;
        RECT 88.180 209.445 88.575 210.095 ;
        RECT 89.410 209.000 89.810 213.310 ;
        RECT 52.430 208.600 105.330 209.000 ;
        RECT 91.585 208.020 105.330 208.600 ;
        RECT 58.705 206.985 59.025 207.045 ;
        RECT 83.085 206.985 83.405 207.045 ;
        RECT 58.705 206.845 83.405 206.985 ;
        RECT 58.705 206.785 59.025 206.845 ;
        RECT 83.085 206.785 83.405 206.845 ;
        RECT 58.245 206.115 58.565 206.175 ;
        RECT 76.645 206.115 76.965 206.175 ;
        RECT 58.245 205.975 76.965 206.115 ;
        RECT 58.245 205.915 58.565 205.975 ;
        RECT 76.645 205.915 76.965 205.975 ;
        RECT 59.625 205.775 59.945 205.835 ;
        RECT 83.545 205.775 83.865 205.835 ;
        RECT 59.625 205.635 83.865 205.775 ;
        RECT 59.625 205.575 59.945 205.635 ;
        RECT 83.545 205.575 83.865 205.635 ;
        RECT 55.415 204.955 89.915 205.435 ;
        RECT 63.320 204.755 63.610 204.800 ;
        RECT 64.225 204.755 64.545 204.815 ;
        RECT 67.905 204.755 68.225 204.815 ;
        RECT 63.320 204.615 64.545 204.755 ;
        RECT 63.320 204.570 63.610 204.615 ;
        RECT 64.225 204.555 64.545 204.615 ;
        RECT 65.235 204.615 68.225 204.755 ;
        RECT 65.235 204.415 65.375 204.615 ;
        RECT 67.905 204.555 68.225 204.615 ;
        RECT 71.585 204.755 71.905 204.815 ;
        RECT 72.060 204.755 72.350 204.800 ;
        RECT 71.585 204.615 72.350 204.755 ;
        RECT 71.585 204.555 71.905 204.615 ;
        RECT 72.060 204.570 72.350 204.615 ;
        RECT 75.265 204.555 75.585 204.815 ;
        RECT 60.865 204.275 65.375 204.415 ;
        RECT 65.575 204.415 65.865 204.460 ;
        RECT 67.445 204.415 67.765 204.475 ;
        RECT 65.575 204.275 67.765 204.415 ;
        RECT 75.355 204.415 75.495 204.555 ;
        RECT 87.700 204.415 87.990 204.460 ;
        RECT 75.355 204.275 87.990 204.415 ;
        RECT 58.245 203.875 58.565 204.135 ;
        RECT 59.625 203.875 59.945 204.135 ;
        RECT 60.100 204.075 60.390 204.120 ;
        RECT 60.865 204.075 61.005 204.275 ;
        RECT 65.575 204.230 65.865 204.275 ;
        RECT 67.445 204.215 67.765 204.275 ;
        RECT 87.700 204.230 87.990 204.275 ;
        RECT 60.100 203.935 61.005 204.075 ;
        RECT 60.100 203.890 60.390 203.935 ;
        RECT 64.225 203.875 64.545 204.135 ;
        RECT 64.775 203.935 75.035 204.075 ;
        RECT 59.180 203.735 59.470 203.780 ;
        RECT 64.775 203.735 64.915 203.935 ;
        RECT 59.180 203.595 64.915 203.735 ;
        RECT 65.120 203.735 65.410 203.780 ;
        RECT 66.310 203.735 66.600 203.780 ;
        RECT 68.830 203.735 69.120 203.780 ;
        RECT 65.120 203.595 69.120 203.735 ;
        RECT 74.895 203.735 75.035 203.935 ;
        RECT 75.265 203.875 75.585 204.135 ;
        RECT 77.565 204.075 77.885 204.135 ;
        RECT 78.960 204.075 79.250 204.120 ;
        RECT 77.565 203.935 79.250 204.075 ;
        RECT 77.565 203.875 77.885 203.935 ;
        RECT 78.960 203.890 79.250 203.935 ;
        RECT 79.865 203.875 80.185 204.135 ;
        RECT 84.480 204.075 84.770 204.120 ;
        RECT 84.925 204.075 85.245 204.135 ;
        RECT 84.480 203.935 85.245 204.075 ;
        RECT 84.480 203.890 84.770 203.935 ;
        RECT 84.925 203.875 85.245 203.935 ;
        RECT 91.585 203.910 92.965 208.020 ;
        RECT 97.500 205.695 97.730 207.645 ;
        RECT 93.395 205.555 97.730 205.695 ;
        RECT 77.105 203.735 77.425 203.795 ;
        RECT 74.895 203.595 77.425 203.735 ;
        RECT 59.180 203.550 59.470 203.595 ;
        RECT 65.120 203.550 65.410 203.595 ;
        RECT 66.310 203.550 66.600 203.595 ;
        RECT 68.830 203.550 69.120 203.595 ;
        RECT 77.105 203.535 77.425 203.595 ;
        RECT 78.485 203.735 78.805 203.795 ;
        RECT 80.325 203.735 80.645 203.795 ;
        RECT 83.560 203.735 83.850 203.780 ;
        RECT 78.485 203.595 83.850 203.735 ;
        RECT 78.485 203.535 78.805 203.595 ;
        RECT 80.325 203.535 80.645 203.595 ;
        RECT 83.560 203.550 83.850 203.595 ;
        RECT 91.915 203.480 92.390 203.500 ;
        RECT 64.725 203.395 65.015 203.440 ;
        RECT 66.825 203.395 67.115 203.440 ;
        RECT 68.395 203.395 68.685 203.440 ;
        RECT 64.725 203.255 68.685 203.395 ;
        RECT 64.725 203.210 65.015 203.255 ;
        RECT 66.825 203.210 67.115 203.255 ;
        RECT 68.395 203.210 68.685 203.255 ;
        RECT 71.140 203.395 71.430 203.440 ;
        RECT 78.025 203.395 78.345 203.455 ;
        RECT 71.140 203.255 78.345 203.395 ;
        RECT 71.140 203.210 71.430 203.255 ;
        RECT 78.025 203.195 78.345 203.255 ;
        RECT 91.910 203.210 92.390 203.480 ;
        RECT 57.340 203.055 57.630 203.100 ;
        RECT 79.405 203.055 79.725 203.115 ;
        RECT 57.340 202.915 79.725 203.055 ;
        RECT 57.340 202.870 57.630 202.915 ;
        RECT 79.405 202.855 79.725 202.915 ;
        RECT 80.820 203.055 81.110 203.100 ;
        RECT 81.740 203.055 82.030 203.100 ;
        RECT 80.820 202.915 82.030 203.055 ;
        RECT 80.820 202.870 81.110 202.915 ;
        RECT 81.740 202.870 82.030 202.915 ;
        RECT 55.415 202.235 89.915 202.715 ;
        RECT 56.865 201.835 57.185 202.095 ;
        RECT 62.860 202.035 63.150 202.080 ;
        RECT 70.665 202.035 70.985 202.095 ;
        RECT 62.860 201.895 75.495 202.035 ;
        RECT 62.860 201.850 63.150 201.895 ;
        RECT 70.665 201.835 70.985 201.895 ;
        RECT 61.925 201.495 62.245 201.755 ;
        RECT 67.445 201.695 67.735 201.740 ;
        RECT 69.015 201.695 69.305 201.740 ;
        RECT 71.115 201.695 71.405 201.740 ;
        RECT 67.445 201.555 71.405 201.695 ;
        RECT 67.445 201.510 67.735 201.555 ;
        RECT 69.015 201.510 69.305 201.555 ;
        RECT 71.115 201.510 71.405 201.555 ;
        RECT 67.010 201.355 67.300 201.400 ;
        RECT 69.530 201.355 69.820 201.400 ;
        RECT 70.720 201.355 71.010 201.400 ;
        RECT 67.010 201.215 71.010 201.355 ;
        RECT 67.010 201.170 67.300 201.215 ;
        RECT 69.530 201.170 69.820 201.215 ;
        RECT 70.720 201.170 71.010 201.215 ;
        RECT 71.600 201.170 71.890 201.400 ;
        RECT 60.100 201.015 60.390 201.060 ;
        RECT 68.825 201.015 69.145 201.075 ;
        RECT 70.205 201.060 70.525 201.075 ;
        RECT 70.205 201.015 70.555 201.060 ;
        RECT 71.675 201.015 71.815 201.170 ;
        RECT 60.100 200.875 69.145 201.015 ;
        RECT 70.055 200.875 70.555 201.015 ;
        RECT 60.100 200.830 60.390 200.875 ;
        RECT 68.825 200.815 69.145 200.875 ;
        RECT 70.205 200.830 70.555 200.875 ;
        RECT 70.755 200.875 71.815 201.015 ;
        RECT 70.205 200.815 70.525 200.830 ;
        RECT 60.560 200.675 60.850 200.720 ;
        RECT 61.005 200.675 61.325 200.735 ;
        RECT 60.560 200.535 61.325 200.675 ;
        RECT 60.560 200.490 60.850 200.535 ;
        RECT 61.005 200.475 61.325 200.535 ;
        RECT 65.145 200.675 65.465 200.735 ;
        RECT 70.755 200.675 70.895 200.875 ;
        RECT 72.045 200.815 72.365 201.075 ;
        RECT 73.885 200.815 74.205 201.075 ;
        RECT 75.355 201.060 75.495 201.895 ;
        RECT 77.105 201.835 77.425 202.095 ;
        RECT 81.280 202.035 81.570 202.080 ;
        RECT 82.200 202.035 82.490 202.080 ;
        RECT 81.280 201.895 82.490 202.035 ;
        RECT 81.280 201.850 81.570 201.895 ;
        RECT 82.200 201.850 82.490 201.895 ;
        RECT 83.085 202.035 83.405 202.095 ;
        RECT 88.160 202.035 88.450 202.080 ;
        RECT 83.085 201.895 88.450 202.035 ;
        RECT 83.085 201.835 83.405 201.895 ;
        RECT 88.160 201.850 88.450 201.895 ;
        RECT 91.910 201.560 92.175 203.210 ;
        RECT 92.375 202.305 92.635 202.820 ;
        RECT 93.395 202.305 93.535 205.555 ;
        RECT 99.205 204.395 99.495 207.735 ;
        RECT 101.975 204.465 102.205 207.635 ;
        RECT 97.750 203.545 99.495 204.395 ;
        RECT 97.750 202.820 98.600 203.545 ;
        RECT 99.750 203.090 100.970 203.110 ;
        RECT 99.410 202.820 101.390 203.090 ;
        RECT 97.880 202.790 98.460 202.820 ;
        RECT 99.750 202.790 100.970 202.820 ;
        RECT 102.020 202.320 102.160 204.465 ;
        RECT 102.905 204.075 103.805 204.085 ;
        RECT 102.875 203.785 103.825 204.075 ;
        RECT 102.905 203.765 103.805 203.785 ;
        RECT 92.375 202.165 93.535 202.305 ;
        RECT 92.375 201.580 92.635 202.165 ;
        RECT 91.915 201.375 92.175 201.560 ;
        RECT 75.280 200.830 75.570 201.060 ;
        RECT 76.645 200.815 76.965 201.075 ;
        RECT 78.040 200.830 78.330 201.060 ;
        RECT 65.145 200.535 70.895 200.675 ;
        RECT 71.585 200.675 71.905 200.735 ;
        RECT 73.440 200.675 73.730 200.720 ;
        RECT 71.585 200.535 73.730 200.675 ;
        RECT 65.145 200.475 65.465 200.535 ;
        RECT 71.585 200.475 71.905 200.535 ;
        RECT 73.440 200.490 73.730 200.535 ;
        RECT 60.085 200.335 60.405 200.395 ;
        RECT 64.700 200.335 64.990 200.380 ;
        RECT 60.085 200.195 64.990 200.335 ;
        RECT 60.085 200.135 60.405 200.195 ;
        RECT 64.700 200.150 64.990 200.195 ;
        RECT 67.905 200.335 68.225 200.395 ;
        RECT 70.205 200.335 70.525 200.395 ;
        RECT 72.965 200.335 73.285 200.395 ;
        RECT 67.905 200.195 73.285 200.335 ;
        RECT 78.115 200.335 78.255 200.830 ;
        RECT 79.405 200.815 79.725 201.075 ;
        RECT 80.325 200.815 80.645 201.075 ;
        RECT 81.245 201.015 81.565 201.075 ;
        RECT 84.940 201.015 85.230 201.060 ;
        RECT 81.245 200.875 85.230 201.015 ;
        RECT 81.245 200.815 81.565 200.875 ;
        RECT 84.940 200.830 85.230 200.875 ;
        RECT 91.915 200.725 92.390 201.375 ;
        RECT 93.395 200.755 93.535 202.165 ;
        RECT 98.570 202.050 102.810 202.320 ;
        RECT 95.215 201.320 96.115 201.640 ;
        RECT 96.885 201.315 97.785 201.635 ;
        RECT 84.005 200.335 84.325 200.395 ;
        RECT 78.115 200.195 84.325 200.335 ;
        RECT 67.905 200.135 68.225 200.195 ;
        RECT 70.205 200.135 70.525 200.195 ;
        RECT 72.965 200.135 73.285 200.195 ;
        RECT 84.005 200.135 84.325 200.195 ;
        RECT 84.465 200.135 84.785 200.395 ;
        RECT 55.415 199.515 89.915 199.995 ;
        RECT 91.585 199.770 92.965 200.170 ;
        RECT 61.020 199.315 61.310 199.360 ;
        RECT 67.445 199.315 67.765 199.375 ;
        RECT 61.020 199.175 67.765 199.315 ;
        RECT 61.020 199.130 61.310 199.175 ;
        RECT 67.445 199.115 67.765 199.175 ;
        RECT 68.825 199.115 69.145 199.375 ;
        RECT 72.965 199.315 73.285 199.375 ;
        RECT 77.565 199.315 77.885 199.375 ;
        RECT 72.965 199.175 77.885 199.315 ;
        RECT 72.965 199.115 73.285 199.175 ;
        RECT 77.565 199.115 77.885 199.175 ;
        RECT 78.025 199.315 78.345 199.375 ;
        RECT 85.385 199.315 85.705 199.375 ;
        RECT 88.160 199.315 88.450 199.360 ;
        RECT 78.025 199.175 85.155 199.315 ;
        RECT 78.025 199.115 78.345 199.175 ;
        RECT 65.145 198.975 65.465 199.035 ;
        RECT 66.585 198.975 66.875 199.020 ;
        RECT 65.145 198.835 66.875 198.975 ;
        RECT 65.145 198.775 65.465 198.835 ;
        RECT 66.585 198.790 66.875 198.835 ;
        RECT 70.665 198.975 70.985 199.035 ;
        RECT 74.515 198.975 74.805 199.020 ;
        RECT 81.245 198.975 81.565 199.035 ;
        RECT 70.665 198.835 81.565 198.975 ;
        RECT 70.665 198.775 70.985 198.835 ;
        RECT 74.515 198.790 74.805 198.835 ;
        RECT 81.245 198.775 81.565 198.835 ;
        RECT 83.255 198.975 83.545 199.020 ;
        RECT 84.465 198.975 84.785 199.035 ;
        RECT 83.255 198.835 84.785 198.975 ;
        RECT 83.255 198.790 83.545 198.835 ;
        RECT 84.465 198.775 84.785 198.835 ;
        RECT 60.085 198.435 60.405 198.695 ;
        RECT 64.225 198.635 64.545 198.695 ;
        RECT 85.015 198.680 85.155 199.175 ;
        RECT 85.385 199.175 88.450 199.315 ;
        RECT 85.385 199.115 85.705 199.175 ;
        RECT 88.160 199.130 88.450 199.175 ;
        RECT 67.920 198.635 68.210 198.680 ;
        RECT 64.225 198.495 84.695 198.635 ;
        RECT 64.225 198.435 64.545 198.495 ;
        RECT 67.920 198.450 68.210 198.495 ;
        RECT 84.555 198.355 84.695 198.495 ;
        RECT 84.940 198.450 85.230 198.680 ;
        RECT 63.330 198.295 63.620 198.340 ;
        RECT 65.850 198.295 66.140 198.340 ;
        RECT 67.040 198.295 67.330 198.340 ;
        RECT 63.330 198.155 67.330 198.295 ;
        RECT 63.330 198.110 63.620 198.155 ;
        RECT 65.850 198.110 66.140 198.155 ;
        RECT 67.040 198.110 67.330 198.155 ;
        RECT 71.150 198.295 71.440 198.340 ;
        RECT 73.670 198.295 73.960 198.340 ;
        RECT 74.860 198.295 75.150 198.340 ;
        RECT 71.150 198.155 75.150 198.295 ;
        RECT 71.150 198.110 71.440 198.155 ;
        RECT 73.670 198.110 73.960 198.155 ;
        RECT 74.860 198.110 75.150 198.155 ;
        RECT 75.740 198.110 76.030 198.340 ;
        RECT 79.890 198.295 80.180 198.340 ;
        RECT 82.410 198.295 82.700 198.340 ;
        RECT 83.600 198.295 83.890 198.340 ;
        RECT 79.890 198.155 83.890 198.295 ;
        RECT 79.890 198.110 80.180 198.155 ;
        RECT 82.410 198.110 82.700 198.155 ;
        RECT 83.600 198.110 83.890 198.155 ;
        RECT 56.865 197.755 57.185 198.015 ;
        RECT 63.765 197.955 64.055 198.000 ;
        RECT 65.335 197.955 65.625 198.000 ;
        RECT 67.435 197.955 67.725 198.000 ;
        RECT 63.765 197.815 67.725 197.955 ;
        RECT 63.765 197.770 64.055 197.815 ;
        RECT 65.335 197.770 65.625 197.815 ;
        RECT 67.435 197.770 67.725 197.815 ;
        RECT 71.585 197.955 71.875 198.000 ;
        RECT 73.155 197.955 73.445 198.000 ;
        RECT 75.255 197.955 75.545 198.000 ;
        RECT 71.585 197.815 75.545 197.955 ;
        RECT 71.585 197.770 71.875 197.815 ;
        RECT 73.155 197.770 73.445 197.815 ;
        RECT 75.255 197.770 75.545 197.815 ;
        RECT 64.685 197.615 65.005 197.675 ;
        RECT 75.815 197.615 75.955 198.110 ;
        RECT 84.465 198.095 84.785 198.355 ;
        RECT 80.325 197.955 80.615 198.000 ;
        RECT 81.895 197.955 82.185 198.000 ;
        RECT 83.995 197.955 84.285 198.000 ;
        RECT 80.325 197.815 84.285 197.955 ;
        RECT 80.325 197.770 80.615 197.815 ;
        RECT 81.895 197.770 82.185 197.815 ;
        RECT 83.995 197.770 84.285 197.815 ;
        RECT 64.685 197.475 75.955 197.615 ;
        RECT 64.685 197.415 65.005 197.475 ;
        RECT 55.415 196.795 89.915 197.275 ;
        RECT 60.120 196.595 60.410 196.640 ;
        RECT 61.040 196.595 61.330 196.640 ;
        RECT 60.120 196.455 61.330 196.595 ;
        RECT 60.120 196.410 60.410 196.455 ;
        RECT 61.040 196.410 61.330 196.455 ;
        RECT 70.665 196.595 70.985 196.655 ;
        RECT 71.140 196.595 71.430 196.640 ;
        RECT 70.665 196.455 71.430 196.595 ;
        RECT 70.665 196.395 70.985 196.455 ;
        RECT 71.140 196.410 71.430 196.455 ;
        RECT 74.805 196.595 75.125 196.655 ;
        RECT 84.480 196.595 84.770 196.640 ;
        RECT 74.805 196.455 84.770 196.595 ;
        RECT 74.805 196.395 75.125 196.455 ;
        RECT 84.480 196.410 84.770 196.455 ;
        RECT 64.725 196.255 65.015 196.300 ;
        RECT 66.825 196.255 67.115 196.300 ;
        RECT 68.395 196.255 68.685 196.300 ;
        RECT 64.725 196.115 68.685 196.255 ;
        RECT 64.725 196.070 65.015 196.115 ;
        RECT 66.825 196.070 67.115 196.115 ;
        RECT 68.395 196.070 68.685 196.115 ;
        RECT 73.900 196.255 74.190 196.300 ;
        RECT 75.265 196.255 75.585 196.315 ;
        RECT 73.900 196.115 75.585 196.255 ;
        RECT 73.900 196.070 74.190 196.115 ;
        RECT 75.265 196.055 75.585 196.115 ;
        RECT 76.645 196.255 76.935 196.300 ;
        RECT 78.215 196.255 78.505 196.300 ;
        RECT 80.315 196.255 80.605 196.300 ;
        RECT 76.645 196.115 80.605 196.255 ;
        RECT 76.645 196.070 76.935 196.115 ;
        RECT 78.215 196.070 78.505 196.115 ;
        RECT 80.315 196.070 80.605 196.115 ;
        RECT 81.245 196.255 81.565 196.315 ;
        RECT 83.100 196.255 83.390 196.300 ;
        RECT 81.245 196.115 83.390 196.255 ;
        RECT 81.245 196.055 81.565 196.115 ;
        RECT 83.100 196.070 83.390 196.115 ;
        RECT 84.005 196.255 84.325 196.315 ;
        RECT 86.780 196.255 87.070 196.300 ;
        RECT 84.005 196.115 87.070 196.255 ;
        RECT 84.005 196.055 84.325 196.115 ;
        RECT 86.780 196.070 87.070 196.115 ;
        RECT 60.545 195.715 60.865 195.975 ;
        RECT 64.225 195.715 64.545 195.975 ;
        RECT 65.120 195.915 65.410 195.960 ;
        RECT 66.310 195.915 66.600 195.960 ;
        RECT 68.830 195.915 69.120 195.960 ;
        RECT 65.120 195.775 69.120 195.915 ;
        RECT 65.120 195.730 65.410 195.775 ;
        RECT 66.310 195.730 66.600 195.775 ;
        RECT 68.830 195.730 69.120 195.775 ;
        RECT 76.210 195.915 76.500 195.960 ;
        RECT 78.730 195.915 79.020 195.960 ;
        RECT 79.920 195.915 80.210 195.960 ;
        RECT 76.210 195.775 80.210 195.915 ;
        RECT 76.210 195.730 76.500 195.775 ;
        RECT 78.730 195.730 79.020 195.775 ;
        RECT 79.920 195.730 80.210 195.775 ;
        RECT 80.800 195.915 81.090 195.960 ;
        RECT 81.705 195.915 82.025 195.975 ;
        RECT 84.465 195.915 84.785 195.975 ;
        RECT 80.800 195.775 84.785 195.915 ;
        RECT 80.800 195.730 81.090 195.775 ;
        RECT 81.705 195.715 82.025 195.775 ;
        RECT 84.465 195.715 84.785 195.775 ;
        RECT 60.085 195.375 60.405 195.635 ;
        RECT 63.320 195.575 63.610 195.620 ;
        RECT 65.520 195.575 65.810 195.620 ;
        RECT 63.320 195.435 65.810 195.575 ;
        RECT 63.320 195.390 63.610 195.435 ;
        RECT 65.520 195.390 65.810 195.435 ;
        RECT 76.645 195.575 76.965 195.635 ;
        RECT 80.325 195.575 80.645 195.635 ;
        RECT 81.260 195.575 81.550 195.620 ;
        RECT 76.645 195.435 81.550 195.575 ;
        RECT 76.645 195.375 76.965 195.435 ;
        RECT 80.325 195.375 80.645 195.435 ;
        RECT 81.260 195.390 81.550 195.435 ;
        RECT 82.165 195.375 82.485 195.635 ;
        RECT 82.625 195.375 82.945 195.635 ;
        RECT 83.545 195.375 83.865 195.635 ;
        RECT 84.005 195.575 84.325 195.635 ;
        RECT 85.860 195.575 86.150 195.620 ;
        RECT 84.005 195.435 86.150 195.575 ;
        RECT 84.005 195.375 84.325 195.435 ;
        RECT 85.860 195.390 86.150 195.435 ;
        RECT 86.305 195.575 86.625 195.635 ;
        RECT 87.240 195.575 87.530 195.620 ;
        RECT 86.305 195.435 87.530 195.575 ;
        RECT 86.305 195.375 86.625 195.435 ;
        RECT 87.240 195.390 87.530 195.435 ;
        RECT 78.945 195.235 79.265 195.295 ;
        RECT 79.465 195.235 79.755 195.280 ;
        RECT 78.945 195.095 79.755 195.235 ;
        RECT 78.945 195.035 79.265 195.095 ;
        RECT 79.465 195.050 79.755 195.095 ;
        RECT 53.185 194.895 53.505 194.955 ;
        RECT 86.765 194.895 87.085 194.955 ;
        RECT 53.185 194.755 87.085 194.895 ;
        RECT 53.185 194.695 53.505 194.755 ;
        RECT 86.765 194.695 87.085 194.755 ;
        RECT 55.415 194.075 89.915 194.555 ;
        RECT 65.145 193.675 65.465 193.935 ;
        RECT 75.265 193.875 75.585 193.935 ;
        RECT 67.075 193.735 75.585 193.875 ;
        RECT 63.475 193.535 63.765 193.580 ;
        RECT 67.075 193.535 67.215 193.735 ;
        RECT 75.265 193.675 75.585 193.735 ;
        RECT 75.740 193.875 76.030 193.920 ;
        RECT 82.625 193.875 82.945 193.935 ;
        RECT 75.740 193.735 82.945 193.875 ;
        RECT 75.740 193.690 76.030 193.735 ;
        RECT 82.625 193.675 82.945 193.735 ;
        RECT 86.765 193.675 87.085 193.935 ;
        RECT 63.475 193.395 67.215 193.535 ;
        RECT 67.445 193.535 67.765 193.595 ;
        RECT 78.485 193.535 78.805 193.595 ;
        RECT 67.445 193.395 72.275 193.535 ;
        RECT 63.475 193.350 63.765 193.395 ;
        RECT 67.445 193.335 67.765 193.395 ;
        RECT 69.300 193.195 69.590 193.240 ;
        RECT 71.585 193.195 71.905 193.255 ;
        RECT 69.300 193.055 71.905 193.195 ;
        RECT 69.300 193.010 69.590 193.055 ;
        RECT 71.585 192.995 71.905 193.055 ;
        RECT 60.110 192.855 60.400 192.900 ;
        RECT 62.630 192.855 62.920 192.900 ;
        RECT 63.820 192.855 64.110 192.900 ;
        RECT 60.110 192.715 64.110 192.855 ;
        RECT 60.110 192.670 60.400 192.715 ;
        RECT 62.630 192.670 62.920 192.715 ;
        RECT 63.820 192.670 64.110 192.715 ;
        RECT 64.685 192.655 65.005 192.915 ;
        RECT 69.745 192.655 70.065 192.915 ;
        RECT 60.545 192.515 60.835 192.560 ;
        RECT 62.115 192.515 62.405 192.560 ;
        RECT 64.215 192.515 64.505 192.560 ;
        RECT 60.545 192.375 64.505 192.515 ;
        RECT 60.545 192.330 60.835 192.375 ;
        RECT 62.115 192.330 62.405 192.375 ;
        RECT 64.215 192.330 64.505 192.375 ;
        RECT 65.605 192.515 65.925 192.575 ;
        RECT 71.140 192.515 71.430 192.560 ;
        RECT 65.605 192.375 71.430 192.515 ;
        RECT 72.135 192.515 72.275 193.395 ;
        RECT 76.275 193.395 78.805 193.535 ;
        RECT 76.275 193.240 76.415 193.395 ;
        RECT 78.485 193.335 78.805 193.395 ;
        RECT 78.945 193.335 79.265 193.595 ;
        RECT 81.245 193.335 81.565 193.595 ;
        RECT 74.360 193.010 74.650 193.240 ;
        RECT 76.200 193.010 76.490 193.240 ;
        RECT 77.105 193.195 77.425 193.255 ;
        RECT 79.420 193.195 79.710 193.240 ;
        RECT 81.335 193.195 81.475 193.335 ;
        RECT 82.180 193.195 82.470 193.240 ;
        RECT 77.105 193.055 82.470 193.195 ;
        RECT 74.435 192.855 74.575 193.010 ;
        RECT 77.105 192.995 77.425 193.055 ;
        RECT 79.420 193.010 79.710 193.055 ;
        RECT 82.180 193.010 82.470 193.055 ;
        RECT 82.640 193.195 82.930 193.240 ;
        RECT 83.085 193.195 83.405 193.255 ;
        RECT 82.640 193.055 83.405 193.195 ;
        RECT 82.640 193.010 82.930 193.055 ;
        RECT 83.085 192.995 83.405 193.055 ;
        RECT 83.560 193.010 83.850 193.240 ;
        RECT 81.245 192.855 81.565 192.915 ;
        RECT 74.435 192.715 81.565 192.855 ;
        RECT 81.245 192.655 81.565 192.715 ;
        RECT 83.635 192.515 83.775 193.010 ;
        RECT 72.135 192.375 83.775 192.515 ;
        RECT 65.605 192.315 65.925 192.375 ;
        RECT 71.140 192.330 71.430 192.375 ;
        RECT 57.785 191.975 58.105 192.235 ;
        RECT 67.440 192.175 67.730 192.220 ;
        RECT 68.360 192.175 68.650 192.220 ;
        RECT 67.440 192.035 68.650 192.175 ;
        RECT 67.440 191.990 67.730 192.035 ;
        RECT 68.360 191.990 68.650 192.035 ;
        RECT 82.180 192.175 82.470 192.220 ;
        RECT 83.100 192.175 83.390 192.220 ;
        RECT 82.180 192.035 83.390 192.175 ;
        RECT 82.180 191.990 82.470 192.035 ;
        RECT 83.100 191.990 83.390 192.035 ;
        RECT 55.415 191.355 89.915 191.835 ;
        RECT 56.865 190.955 57.185 191.215 ;
        RECT 64.240 191.155 64.530 191.200 ;
        RECT 65.160 191.155 65.450 191.200 ;
        RECT 64.240 191.015 65.450 191.155 ;
        RECT 64.240 190.970 64.530 191.015 ;
        RECT 65.160 190.970 65.450 191.015 ;
        RECT 77.580 191.155 77.870 191.200 ;
        RECT 78.500 191.155 78.790 191.200 ;
        RECT 77.580 191.015 78.790 191.155 ;
        RECT 77.580 190.970 77.870 191.015 ;
        RECT 78.500 190.970 78.790 191.015 ;
        RECT 61.005 190.815 61.325 190.875 ;
        RECT 62.400 190.815 62.690 190.860 ;
        RECT 61.005 190.675 62.690 190.815 ;
        RECT 61.005 190.615 61.325 190.675 ;
        RECT 62.400 190.630 62.690 190.675 ;
        RECT 62.860 190.815 63.150 190.860 ;
        RECT 72.045 190.815 72.365 190.875 ;
        RECT 62.860 190.675 72.365 190.815 ;
        RECT 62.860 190.630 63.150 190.675 ;
        RECT 72.045 190.615 72.365 190.675 ;
        RECT 60.560 190.475 60.850 190.520 ;
        RECT 61.925 190.475 62.245 190.535 ;
        RECT 65.605 190.475 65.925 190.535 ;
        RECT 60.560 190.335 65.925 190.475 ;
        RECT 60.560 190.290 60.850 190.335 ;
        RECT 61.925 190.275 62.245 190.335 ;
        RECT 65.605 190.275 65.925 190.335 ;
        RECT 69.745 190.275 70.065 190.535 ;
        RECT 57.785 190.135 58.105 190.195 ;
        RECT 60.100 190.135 60.390 190.180 ;
        RECT 57.785 189.995 60.390 190.135 ;
        RECT 57.785 189.935 58.105 189.995 ;
        RECT 60.100 189.950 60.390 189.995 ;
        RECT 65.160 190.135 65.450 190.180 ;
        RECT 67.445 190.135 67.765 190.195 ;
        RECT 67.920 190.135 68.210 190.180 ;
        RECT 65.160 189.995 68.210 190.135 ;
        RECT 65.160 189.950 65.450 189.995 ;
        RECT 67.445 189.935 67.765 189.995 ;
        RECT 67.920 189.950 68.210 189.995 ;
        RECT 71.125 189.935 71.445 190.195 ;
        RECT 72.135 190.180 72.275 190.615 ;
        RECT 77.105 190.275 77.425 190.535 ;
        RECT 72.060 189.950 72.350 190.180 ;
        RECT 74.820 190.135 75.110 190.180 ;
        RECT 76.185 190.135 76.505 190.195 ;
        RECT 77.580 190.135 77.870 190.180 ;
        RECT 74.820 189.995 77.870 190.135 ;
        RECT 74.820 189.950 75.110 189.995 ;
        RECT 76.185 189.935 76.505 189.995 ;
        RECT 77.580 189.950 77.870 189.995 ;
        RECT 81.245 190.135 81.565 190.195 ;
        RECT 82.180 190.135 82.470 190.180 ;
        RECT 84.940 190.135 85.230 190.180 ;
        RECT 81.245 189.995 85.230 190.135 ;
        RECT 81.245 189.935 81.565 189.995 ;
        RECT 82.180 189.950 82.470 189.995 ;
        RECT 84.940 189.950 85.230 189.995 ;
        RECT 88.145 189.935 88.465 190.195 ;
        RECT 71.585 189.795 71.905 189.855 ;
        RECT 72.980 189.795 73.270 189.840 ;
        RECT 71.585 189.655 73.270 189.795 ;
        RECT 71.585 189.595 71.905 189.655 ;
        RECT 72.980 189.610 73.270 189.655 ;
        RECT 78.945 189.795 79.265 189.855 ;
        RECT 79.865 189.795 80.185 189.855 ;
        RECT 78.945 189.655 80.185 189.795 ;
        RECT 78.945 189.595 79.265 189.655 ;
        RECT 79.865 189.595 80.185 189.655 ;
        RECT 60.085 189.455 60.405 189.515 ;
        RECT 70.680 189.455 70.970 189.500 ;
        RECT 60.085 189.315 70.970 189.455 ;
        RECT 60.085 189.255 60.405 189.315 ;
        RECT 70.680 189.270 70.970 189.315 ;
        RECT 75.265 189.455 75.585 189.515 ;
        RECT 81.245 189.455 81.565 189.515 ;
        RECT 84.005 189.455 84.325 189.515 ;
        RECT 75.265 189.315 84.325 189.455 ;
        RECT 75.265 189.255 75.585 189.315 ;
        RECT 81.245 189.255 81.565 189.315 ;
        RECT 84.005 189.255 84.325 189.315 ;
        RECT 55.415 188.635 89.915 189.115 ;
        RECT 66.540 188.250 66.830 188.480 ;
        RECT 75.265 188.435 75.585 188.495 ;
        RECT 73.055 188.295 75.585 188.435 ;
        RECT 63.475 188.095 63.765 188.140 ;
        RECT 66.615 188.095 66.755 188.250 ;
        RECT 63.475 187.955 66.755 188.095 ;
        RECT 72.215 188.095 72.505 188.140 ;
        RECT 73.055 188.095 73.195 188.295 ;
        RECT 75.265 188.235 75.585 188.295 ;
        RECT 80.340 188.435 80.630 188.480 ;
        RECT 80.785 188.435 81.105 188.495 ;
        RECT 80.340 188.295 81.105 188.435 ;
        RECT 80.340 188.250 80.630 188.295 ;
        RECT 80.785 188.235 81.105 188.295 ;
        RECT 81.705 188.235 82.025 188.495 ;
        RECT 74.805 188.095 75.125 188.155 ;
        RECT 81.795 188.095 81.935 188.235 ;
        RECT 72.215 187.955 73.195 188.095 ;
        RECT 73.515 187.955 81.935 188.095 ;
        RECT 63.475 187.910 63.765 187.955 ;
        RECT 72.215 187.910 72.505 187.955 ;
        RECT 73.515 187.800 73.655 187.955 ;
        RECT 74.805 187.895 75.125 187.955 ;
        RECT 73.440 187.570 73.730 187.800 ;
        RECT 75.280 187.755 75.570 187.800 ;
        RECT 75.725 187.755 76.045 187.815 ;
        RECT 75.280 187.615 76.045 187.755 ;
        RECT 75.280 187.570 75.570 187.615 ;
        RECT 75.725 187.555 76.045 187.615 ;
        RECT 76.200 187.755 76.490 187.800 ;
        RECT 76.645 187.755 76.965 187.815 ;
        RECT 76.200 187.615 76.965 187.755 ;
        RECT 76.200 187.570 76.490 187.615 ;
        RECT 76.645 187.555 76.965 187.615 ;
        RECT 77.120 187.755 77.410 187.800 ;
        RECT 77.565 187.755 77.885 187.815 ;
        RECT 77.120 187.615 77.885 187.755 ;
        RECT 77.120 187.570 77.410 187.615 ;
        RECT 77.565 187.555 77.885 187.615 ;
        RECT 78.945 187.755 79.265 187.815 ;
        RECT 81.720 187.755 82.010 187.800 ;
        RECT 84.480 187.755 84.770 187.800 ;
        RECT 86.305 187.755 86.625 187.815 ;
        RECT 78.945 187.615 86.625 187.755 ;
        RECT 78.945 187.555 79.265 187.615 ;
        RECT 81.720 187.570 82.010 187.615 ;
        RECT 84.480 187.570 84.770 187.615 ;
        RECT 86.305 187.555 86.625 187.615 ;
        RECT 60.110 187.415 60.400 187.460 ;
        RECT 62.630 187.415 62.920 187.460 ;
        RECT 63.820 187.415 64.110 187.460 ;
        RECT 60.110 187.275 64.110 187.415 ;
        RECT 60.110 187.230 60.400 187.275 ;
        RECT 62.630 187.230 62.920 187.275 ;
        RECT 63.820 187.230 64.110 187.275 ;
        RECT 64.685 187.215 65.005 187.475 ;
        RECT 68.850 187.415 69.140 187.460 ;
        RECT 71.370 187.415 71.660 187.460 ;
        RECT 72.560 187.415 72.850 187.460 ;
        RECT 68.850 187.275 72.850 187.415 ;
        RECT 68.850 187.230 69.140 187.275 ;
        RECT 71.370 187.230 71.660 187.275 ;
        RECT 72.560 187.230 72.850 187.275 ;
        RECT 82.165 187.215 82.485 187.475 ;
        RECT 85.385 187.415 85.705 187.475 ;
        RECT 85.860 187.415 86.150 187.460 ;
        RECT 85.385 187.275 86.150 187.415 ;
        RECT 85.385 187.215 85.705 187.275 ;
        RECT 85.860 187.230 86.150 187.275 ;
        RECT 60.545 187.075 60.835 187.120 ;
        RECT 62.115 187.075 62.405 187.120 ;
        RECT 64.215 187.075 64.505 187.120 ;
        RECT 60.545 186.935 64.505 187.075 ;
        RECT 60.545 186.890 60.835 186.935 ;
        RECT 62.115 186.890 62.405 186.935 ;
        RECT 64.215 186.890 64.505 186.935 ;
        RECT 69.285 187.075 69.575 187.120 ;
        RECT 70.855 187.075 71.145 187.120 ;
        RECT 72.955 187.075 73.245 187.120 ;
        RECT 84.925 187.075 85.245 187.135 ;
        RECT 69.285 186.935 73.245 187.075 ;
        RECT 69.285 186.890 69.575 186.935 ;
        RECT 70.855 186.890 71.145 186.935 ;
        RECT 72.955 186.890 73.245 186.935 ;
        RECT 75.355 186.935 85.245 187.075 ;
        RECT 57.785 186.535 58.105 186.795 ;
        RECT 66.540 186.735 66.830 186.780 ;
        RECT 68.365 186.735 68.685 186.795 ;
        RECT 75.355 186.735 75.495 186.935 ;
        RECT 84.925 186.875 85.245 186.935 ;
        RECT 66.540 186.595 75.495 186.735 ;
        RECT 75.740 186.735 76.030 186.780 ;
        RECT 76.185 186.735 76.505 186.795 ;
        RECT 75.740 186.595 76.505 186.735 ;
        RECT 66.540 186.550 66.830 186.595 ;
        RECT 68.365 186.535 68.685 186.595 ;
        RECT 75.740 186.550 76.030 186.595 ;
        RECT 76.185 186.535 76.505 186.595 ;
        RECT 80.800 186.735 81.090 186.780 ;
        RECT 81.720 186.735 82.010 186.780 ;
        RECT 80.800 186.595 82.010 186.735 ;
        RECT 80.800 186.550 81.090 186.595 ;
        RECT 81.720 186.550 82.010 186.595 ;
        RECT 55.415 185.915 89.915 186.395 ;
        RECT 77.100 185.715 77.390 185.760 ;
        RECT 78.020 185.715 78.310 185.760 ;
        RECT 77.100 185.575 78.310 185.715 ;
        RECT 77.100 185.530 77.390 185.575 ;
        RECT 78.020 185.530 78.310 185.575 ;
        RECT 83.080 185.715 83.370 185.760 ;
        RECT 84.000 185.715 84.290 185.760 ;
        RECT 83.080 185.575 84.290 185.715 ;
        RECT 83.080 185.530 83.370 185.575 ;
        RECT 84.000 185.530 84.290 185.575 ;
        RECT 67.460 185.375 67.750 185.420 ;
        RECT 70.205 185.375 70.495 185.420 ;
        RECT 71.775 185.375 72.065 185.420 ;
        RECT 73.875 185.375 74.165 185.420 ;
        RECT 67.460 185.235 69.515 185.375 ;
        RECT 67.460 185.190 67.750 185.235 ;
        RECT 61.480 185.035 61.770 185.080 ;
        RECT 68.365 185.035 68.685 185.095 ;
        RECT 61.480 184.895 68.685 185.035 ;
        RECT 61.480 184.850 61.770 184.895 ;
        RECT 68.365 184.835 68.685 184.895 ;
        RECT 56.865 184.495 57.185 184.755 ;
        RECT 57.785 184.695 58.105 184.755 ;
        RECT 60.100 184.695 60.390 184.740 ;
        RECT 57.785 184.555 60.390 184.695 ;
        RECT 57.785 184.495 58.105 184.555 ;
        RECT 60.100 184.510 60.390 184.555 ;
        RECT 62.845 184.495 63.165 184.755 ;
        RECT 69.375 184.695 69.515 185.235 ;
        RECT 70.205 185.235 74.165 185.375 ;
        RECT 70.205 185.190 70.495 185.235 ;
        RECT 71.775 185.190 72.065 185.235 ;
        RECT 73.875 185.190 74.165 185.235 ;
        RECT 69.770 185.035 70.060 185.080 ;
        RECT 72.290 185.035 72.580 185.080 ;
        RECT 73.480 185.035 73.770 185.080 ;
        RECT 69.770 184.895 73.770 185.035 ;
        RECT 69.770 184.850 70.060 184.895 ;
        RECT 72.290 184.850 72.580 184.895 ;
        RECT 73.480 184.850 73.770 184.895 ;
        RECT 74.360 185.035 74.650 185.080 ;
        RECT 74.805 185.035 75.125 185.095 ;
        RECT 74.360 184.895 75.125 185.035 ;
        RECT 74.360 184.850 74.650 184.895 ;
        RECT 74.805 184.835 75.125 184.895 ;
        RECT 75.265 184.835 75.585 185.095 ;
        RECT 79.405 184.835 79.725 185.095 ;
        RECT 85.385 184.835 85.705 185.095 ;
        RECT 71.585 184.695 71.905 184.755 ;
        RECT 73.025 184.695 73.315 184.740 ;
        RECT 69.375 184.555 71.355 184.695 ;
        RECT 71.215 184.415 71.355 184.555 ;
        RECT 71.585 184.555 73.315 184.695 ;
        RECT 71.585 184.495 71.905 184.555 ;
        RECT 73.025 184.510 73.315 184.555 ;
        RECT 73.885 184.695 74.205 184.755 ;
        RECT 77.565 184.695 77.885 184.755 ;
        RECT 73.885 184.555 77.885 184.695 ;
        RECT 73.885 184.495 74.205 184.555 ;
        RECT 77.565 184.495 77.885 184.555 ;
        RECT 78.025 184.495 78.345 184.755 ;
        RECT 84.940 184.695 85.230 184.740 ;
        RECT 86.305 184.695 86.625 184.755 ;
        RECT 84.940 184.555 86.625 184.695 ;
        RECT 84.940 184.510 85.230 184.555 ;
        RECT 86.305 184.495 86.625 184.555 ;
        RECT 61.940 184.355 62.230 184.400 ;
        RECT 67.445 184.355 67.765 184.415 ;
        RECT 61.940 184.215 67.765 184.355 ;
        RECT 61.940 184.170 62.230 184.215 ;
        RECT 67.445 184.155 67.765 184.215 ;
        RECT 71.125 184.355 71.445 184.415 ;
        RECT 73.975 184.355 74.115 184.495 ;
        RECT 71.125 184.215 74.115 184.355 ;
        RECT 71.125 184.155 71.445 184.215 ;
        RECT 62.845 184.015 63.165 184.075 ;
        RECT 75.265 184.015 75.585 184.075 ;
        RECT 78.945 184.015 79.265 184.075 ;
        RECT 62.845 183.875 79.265 184.015 ;
        RECT 62.845 183.815 63.165 183.875 ;
        RECT 75.265 183.815 75.585 183.875 ;
        RECT 78.945 183.815 79.265 183.875 ;
        RECT 80.785 183.815 81.105 184.075 ;
        RECT 55.415 183.195 89.915 183.675 ;
        RECT 57.785 182.795 58.105 183.055 ;
        RECT 78.960 182.995 79.250 183.040 ;
        RECT 70.755 182.855 79.250 182.995 ;
        RECT 63.475 182.655 63.765 182.700 ;
        RECT 70.755 182.655 70.895 182.855 ;
        RECT 78.960 182.810 79.250 182.855 ;
        RECT 91.585 182.830 92.885 199.770 ;
        RECT 93.350 184.625 93.580 200.755 ;
        RECT 94.975 200.415 95.205 200.495 ;
        RECT 94.960 190.495 95.220 200.415 ;
        RECT 94.975 190.485 95.205 190.495 ;
        RECT 96.365 184.695 96.595 200.755 ;
        RECT 97.825 200.415 98.055 200.495 ;
        RECT 97.825 190.495 98.090 200.415 ;
        RECT 97.825 190.485 98.055 190.495 ;
        RECT 99.415 184.695 99.645 200.620 ;
        RECT 96.365 184.555 99.645 184.695 ;
        RECT 99.415 184.490 99.645 184.555 ;
        RECT 103.860 182.830 105.110 185.325 ;
        RECT 74.805 182.655 75.125 182.715 ;
        RECT 84.635 182.655 84.925 182.700 ;
        RECT 86.780 182.655 87.070 182.700 ;
        RECT 63.475 182.515 70.895 182.655 ;
        RECT 72.595 182.515 80.555 182.655 ;
        RECT 63.475 182.470 63.765 182.515 ;
        RECT 65.605 182.315 65.925 182.375 ;
        RECT 72.595 182.360 72.735 182.515 ;
        RECT 74.805 182.455 75.125 182.515 ;
        RECT 71.185 182.315 71.475 182.360 ;
        RECT 65.605 182.175 71.475 182.315 ;
        RECT 65.605 182.115 65.925 182.175 ;
        RECT 71.185 182.130 71.475 182.175 ;
        RECT 72.520 182.130 72.810 182.360 ;
        RECT 73.885 182.115 74.205 182.375 ;
        RECT 75.265 182.115 75.585 182.375 ;
        RECT 77.565 182.115 77.885 182.375 ;
        RECT 78.025 182.115 78.345 182.375 ;
        RECT 60.110 181.975 60.400 182.020 ;
        RECT 62.630 181.975 62.920 182.020 ;
        RECT 63.820 181.975 64.110 182.020 ;
        RECT 60.110 181.835 64.110 181.975 ;
        RECT 60.110 181.790 60.400 181.835 ;
        RECT 62.630 181.790 62.920 181.835 ;
        RECT 63.820 181.790 64.110 181.835 ;
        RECT 64.685 181.775 65.005 182.035 ;
        RECT 67.930 181.975 68.220 182.020 ;
        RECT 70.450 181.975 70.740 182.020 ;
        RECT 71.640 181.975 71.930 182.020 ;
        RECT 75.725 181.975 76.045 182.035 ;
        RECT 67.930 181.835 71.930 181.975 ;
        RECT 67.930 181.790 68.220 181.835 ;
        RECT 70.450 181.790 70.740 181.835 ;
        RECT 71.640 181.790 71.930 181.835 ;
        RECT 74.895 181.835 76.045 181.975 ;
        RECT 80.415 181.975 80.555 182.515 ;
        RECT 84.635 182.515 87.070 182.655 ;
        RECT 84.635 182.470 84.925 182.515 ;
        RECT 86.780 182.470 87.070 182.515 ;
        RECT 86.305 182.115 86.625 182.375 ;
        RECT 81.270 181.975 81.560 182.020 ;
        RECT 83.790 181.975 84.080 182.020 ;
        RECT 84.980 181.975 85.270 182.020 ;
        RECT 80.415 181.835 81.015 181.975 ;
        RECT 74.895 181.680 75.035 181.835 ;
        RECT 75.725 181.775 76.045 181.835 ;
        RECT 60.545 181.635 60.835 181.680 ;
        RECT 62.115 181.635 62.405 181.680 ;
        RECT 64.215 181.635 64.505 181.680 ;
        RECT 60.545 181.495 64.505 181.635 ;
        RECT 60.545 181.450 60.835 181.495 ;
        RECT 62.115 181.450 62.405 181.495 ;
        RECT 64.215 181.450 64.505 181.495 ;
        RECT 68.365 181.635 68.655 181.680 ;
        RECT 69.935 181.635 70.225 181.680 ;
        RECT 72.035 181.635 72.325 181.680 ;
        RECT 74.820 181.645 75.110 181.680 ;
        RECT 68.365 181.495 72.325 181.635 ;
        RECT 74.710 181.505 75.110 181.645 ;
        RECT 68.365 181.450 68.655 181.495 ;
        RECT 69.935 181.450 70.225 181.495 ;
        RECT 72.035 181.450 72.325 181.495 ;
        RECT 74.820 181.450 75.110 181.505 ;
        RECT 65.620 181.295 65.910 181.340 ;
        RECT 66.065 181.295 66.385 181.355 ;
        RECT 65.620 181.155 66.385 181.295 ;
        RECT 65.620 181.110 65.910 181.155 ;
        RECT 66.065 181.095 66.385 181.155 ;
        RECT 71.585 181.295 71.905 181.355 ;
        RECT 75.265 181.295 75.585 181.355 ;
        RECT 71.585 181.155 75.585 181.295 ;
        RECT 71.585 181.095 71.905 181.155 ;
        RECT 75.265 181.095 75.585 181.155 ;
        RECT 78.945 181.095 79.265 181.355 ;
        RECT 80.875 181.295 81.015 181.835 ;
        RECT 81.270 181.835 85.270 181.975 ;
        RECT 81.270 181.790 81.560 181.835 ;
        RECT 83.790 181.790 84.080 181.835 ;
        RECT 84.980 181.790 85.270 181.835 ;
        RECT 85.860 181.790 86.150 182.020 ;
        RECT 81.705 181.635 81.995 181.680 ;
        RECT 83.275 181.635 83.565 181.680 ;
        RECT 85.375 181.635 85.665 181.680 ;
        RECT 81.705 181.495 85.665 181.635 ;
        RECT 81.705 181.450 81.995 181.495 ;
        RECT 83.275 181.450 83.565 181.495 ;
        RECT 85.375 181.450 85.665 181.495 ;
        RECT 85.935 181.635 86.075 181.790 ;
        RECT 86.765 181.775 87.085 182.035 ;
        RECT 91.585 181.880 105.110 182.830 ;
        RECT 88.145 181.635 88.465 181.695 ;
        RECT 85.935 181.495 88.465 181.635 ;
        RECT 85.935 181.295 86.075 181.495 ;
        RECT 88.145 181.435 88.465 181.495 ;
        RECT 80.875 181.155 86.075 181.295 ;
        RECT 55.415 180.475 89.915 180.955 ;
        RECT 62.385 180.075 62.705 180.335 ;
        RECT 64.685 180.275 65.005 180.335 ;
        RECT 76.645 180.275 76.965 180.335 ;
        RECT 83.085 180.275 83.405 180.335 ;
        RECT 64.685 180.135 71.815 180.275 ;
        RECT 64.685 180.075 65.005 180.135 ;
        RECT 67.445 179.935 67.735 179.980 ;
        RECT 69.015 179.935 69.305 179.980 ;
        RECT 71.115 179.935 71.405 179.980 ;
        RECT 67.445 179.795 71.405 179.935 ;
        RECT 67.445 179.750 67.735 179.795 ;
        RECT 69.015 179.750 69.305 179.795 ;
        RECT 71.115 179.750 71.405 179.795 ;
        RECT 71.675 179.640 71.815 180.135 ;
        RECT 73.055 180.135 76.965 180.275 ;
        RECT 61.480 179.595 61.770 179.640 ;
        RECT 67.010 179.595 67.300 179.640 ;
        RECT 69.530 179.595 69.820 179.640 ;
        RECT 70.720 179.595 71.010 179.640 ;
        RECT 61.480 179.455 66.755 179.595 ;
        RECT 61.480 179.410 61.770 179.455 ;
        RECT 60.100 179.255 60.390 179.300 ;
        RECT 60.100 179.115 61.005 179.255 ;
        RECT 60.100 179.070 60.390 179.115 ;
        RECT 56.865 178.375 57.185 178.635 ;
        RECT 60.865 178.575 61.005 179.115 ;
        RECT 62.845 179.055 63.165 179.315 ;
        RECT 66.615 179.255 66.755 179.455 ;
        RECT 67.010 179.455 71.010 179.595 ;
        RECT 67.010 179.410 67.300 179.455 ;
        RECT 69.530 179.410 69.820 179.455 ;
        RECT 70.720 179.410 71.010 179.455 ;
        RECT 71.600 179.410 71.890 179.640 ;
        RECT 67.905 179.255 68.225 179.315 ;
        RECT 66.615 179.115 68.225 179.255 ;
        RECT 67.905 179.055 68.225 179.115 ;
        RECT 70.320 179.255 70.610 179.300 ;
        RECT 71.125 179.255 71.445 179.315 ;
        RECT 73.055 179.300 73.195 180.135 ;
        RECT 76.645 180.075 76.965 180.135 ;
        RECT 79.955 180.135 83.405 180.275 ;
        RECT 76.200 179.935 76.490 179.980 ;
        RECT 79.955 179.935 80.095 180.135 ;
        RECT 83.085 180.075 83.405 180.135 ;
        RECT 87.225 180.275 87.545 180.335 ;
        RECT 88.160 180.275 88.450 180.320 ;
        RECT 87.225 180.135 88.450 180.275 ;
        RECT 87.225 180.075 87.545 180.135 ;
        RECT 88.160 180.090 88.450 180.135 ;
        RECT 76.200 179.795 80.095 179.935 ;
        RECT 80.325 179.935 80.615 179.980 ;
        RECT 81.895 179.935 82.185 179.980 ;
        RECT 83.995 179.935 84.285 179.980 ;
        RECT 80.325 179.795 84.285 179.935 ;
        RECT 76.200 179.750 76.490 179.795 ;
        RECT 80.325 179.750 80.615 179.795 ;
        RECT 81.895 179.750 82.185 179.795 ;
        RECT 83.995 179.750 84.285 179.795 ;
        RECT 74.360 179.595 74.650 179.640 ;
        RECT 77.565 179.595 77.885 179.655 ;
        RECT 74.360 179.455 77.885 179.595 ;
        RECT 74.360 179.410 74.650 179.455 ;
        RECT 77.565 179.395 77.885 179.455 ;
        RECT 79.890 179.595 80.180 179.640 ;
        RECT 82.410 179.595 82.700 179.640 ;
        RECT 83.600 179.595 83.890 179.640 ;
        RECT 79.890 179.455 83.890 179.595 ;
        RECT 79.890 179.410 80.180 179.455 ;
        RECT 82.410 179.410 82.700 179.455 ;
        RECT 83.600 179.410 83.890 179.455 ;
        RECT 84.480 179.595 84.770 179.640 ;
        RECT 88.145 179.595 88.465 179.655 ;
        RECT 84.480 179.455 88.465 179.595 ;
        RECT 84.480 179.410 84.770 179.455 ;
        RECT 88.145 179.395 88.465 179.455 ;
        RECT 70.320 179.115 71.445 179.255 ;
        RECT 70.320 179.070 70.610 179.115 ;
        RECT 71.125 179.055 71.445 179.115 ;
        RECT 72.980 179.070 73.270 179.300 ;
        RECT 73.900 179.070 74.190 179.300 ;
        RECT 67.445 178.915 67.765 178.975 ;
        RECT 73.975 178.915 74.115 179.070 ;
        RECT 74.805 179.055 75.125 179.315 ;
        RECT 75.265 179.255 75.585 179.315 ;
        RECT 77.105 179.255 77.425 179.315 ;
        RECT 75.265 179.115 77.425 179.255 ;
        RECT 75.265 179.055 75.585 179.115 ;
        RECT 77.105 179.055 77.425 179.115 ;
        RECT 80.785 179.255 81.105 179.315 ;
        RECT 83.145 179.255 83.435 179.300 ;
        RECT 80.785 179.115 83.435 179.255 ;
        RECT 80.785 179.055 81.105 179.115 ;
        RECT 83.145 179.070 83.435 179.115 ;
        RECT 84.940 179.070 85.230 179.300 ;
        RECT 85.015 178.915 85.155 179.070 ;
        RECT 67.445 178.775 74.115 178.915 ;
        RECT 82.255 178.775 85.155 178.915 ;
        RECT 67.445 178.715 67.765 178.775 ;
        RECT 82.255 178.635 82.395 178.775 ;
        RECT 64.700 178.575 64.990 178.620 ;
        RECT 60.865 178.435 64.990 178.575 ;
        RECT 64.700 178.390 64.990 178.435 ;
        RECT 65.145 178.575 65.465 178.635 ;
        RECT 77.580 178.575 77.870 178.620 ;
        RECT 82.165 178.575 82.485 178.635 ;
        RECT 65.145 178.435 82.485 178.575 ;
        RECT 65.145 178.375 65.465 178.435 ;
        RECT 77.580 178.390 77.870 178.435 ;
        RECT 82.165 178.375 82.485 178.435 ;
        RECT 55.415 177.755 89.915 178.235 ;
        RECT 64.685 177.555 65.005 177.615 ;
        RECT 82.640 177.555 82.930 177.600 ;
        RECT 86.305 177.555 86.625 177.615 ;
        RECT 64.685 177.415 69.515 177.555 ;
        RECT 64.685 177.355 65.005 177.415 ;
        RECT 65.145 177.215 65.465 177.275 ;
        RECT 69.375 177.260 69.515 177.415 ;
        RECT 82.640 177.415 86.625 177.555 ;
        RECT 82.640 177.370 82.930 177.415 ;
        RECT 86.305 177.355 86.625 177.415 ;
        RECT 87.685 177.555 88.005 177.615 ;
        RECT 88.160 177.555 88.450 177.600 ;
        RECT 87.685 177.415 88.450 177.555 ;
        RECT 87.685 177.355 88.005 177.415 ;
        RECT 88.160 177.370 88.450 177.415 ;
        RECT 64.315 177.075 65.465 177.215 ;
        RECT 61.465 176.875 61.785 176.935 ;
        RECT 63.365 176.875 63.655 176.920 ;
        RECT 64.315 176.875 64.455 177.075 ;
        RECT 65.145 177.015 65.465 177.075 ;
        RECT 69.300 177.030 69.590 177.260 ;
        RECT 61.465 176.735 64.455 176.875 ;
        RECT 61.465 176.675 61.785 176.735 ;
        RECT 63.365 176.690 63.655 176.735 ;
        RECT 64.685 176.675 65.005 176.935 ;
        RECT 65.605 176.675 65.925 176.935 ;
        RECT 66.095 176.920 66.355 176.965 ;
        RECT 66.080 176.875 66.370 176.920 ;
        RECT 68.840 176.875 69.130 176.920 ;
        RECT 66.080 176.735 69.130 176.875 ;
        RECT 66.080 176.690 66.370 176.735 ;
        RECT 68.840 176.690 69.130 176.735 ;
        RECT 72.045 176.875 72.365 176.935 ;
        RECT 73.900 176.875 74.190 176.920 ;
        RECT 72.045 176.735 74.190 176.875 ;
        RECT 66.095 176.645 66.355 176.690 ;
        RECT 72.045 176.675 72.365 176.735 ;
        RECT 73.900 176.690 74.190 176.735 ;
        RECT 78.945 176.875 79.265 176.935 ;
        RECT 79.420 176.875 79.710 176.920 ;
        RECT 84.940 176.875 85.230 176.920 ;
        RECT 78.945 176.735 85.230 176.875 ;
        RECT 78.945 176.675 79.265 176.735 ;
        RECT 79.420 176.690 79.710 176.735 ;
        RECT 84.940 176.690 85.230 176.735 ;
        RECT 60.110 176.535 60.400 176.580 ;
        RECT 62.630 176.535 62.920 176.580 ;
        RECT 63.820 176.535 64.110 176.580 ;
        RECT 60.110 176.395 64.110 176.535 ;
        RECT 60.110 176.350 60.400 176.395 ;
        RECT 62.630 176.350 62.920 176.395 ;
        RECT 63.820 176.350 64.110 176.395 ;
        RECT 71.125 176.535 71.445 176.595 ;
        RECT 75.280 176.535 75.570 176.580 ;
        RECT 71.125 176.395 75.570 176.535 ;
        RECT 71.125 176.335 71.445 176.395 ;
        RECT 75.280 176.350 75.570 176.395 ;
        RECT 60.545 176.195 60.835 176.240 ;
        RECT 62.115 176.195 62.405 176.240 ;
        RECT 64.215 176.195 64.505 176.240 ;
        RECT 60.545 176.055 64.505 176.195 ;
        RECT 60.545 176.010 60.835 176.055 ;
        RECT 62.115 176.010 62.405 176.055 ;
        RECT 64.215 176.010 64.505 176.055 ;
        RECT 57.800 175.855 58.090 175.900 ;
        RECT 60.085 175.855 60.405 175.915 ;
        RECT 57.800 175.715 60.405 175.855 ;
        RECT 57.800 175.670 58.090 175.715 ;
        RECT 60.085 175.655 60.405 175.715 ;
        RECT 65.160 175.855 65.450 175.900 ;
        RECT 66.080 175.855 66.370 175.900 ;
        RECT 65.160 175.715 66.370 175.855 ;
        RECT 65.160 175.670 65.450 175.715 ;
        RECT 66.080 175.670 66.370 175.715 ;
        RECT 75.740 175.855 76.030 175.900 ;
        RECT 76.645 175.855 76.965 175.915 ;
        RECT 78.485 175.855 78.805 175.915 ;
        RECT 75.740 175.715 78.805 175.855 ;
        RECT 75.740 175.670 76.030 175.715 ;
        RECT 76.645 175.655 76.965 175.715 ;
        RECT 78.485 175.655 78.805 175.715 ;
        RECT 55.415 175.035 89.915 175.515 ;
        RECT 73.000 174.835 73.290 174.880 ;
        RECT 73.920 174.835 74.210 174.880 ;
        RECT 84.020 174.835 84.310 174.880 ;
        RECT 73.000 174.695 74.210 174.835 ;
        RECT 73.000 174.650 73.290 174.695 ;
        RECT 73.920 174.650 74.210 174.695 ;
        RECT 79.035 174.695 84.310 174.835 ;
        RECT 57.785 174.495 58.105 174.555 ;
        RECT 74.805 174.495 75.125 174.555 ;
        RECT 77.580 174.495 77.870 174.540 ;
        RECT 57.785 174.355 64.455 174.495 ;
        RECT 57.785 174.295 58.105 174.355 ;
        RECT 61.465 173.955 61.785 174.215 ;
        RECT 60.085 173.615 60.405 173.875 ;
        RECT 62.845 173.615 63.165 173.875 ;
        RECT 64.315 173.860 64.455 174.355 ;
        RECT 74.805 174.355 77.870 174.495 ;
        RECT 74.805 174.295 75.125 174.355 ;
        RECT 77.580 174.310 77.870 174.355 ;
        RECT 76.200 174.155 76.490 174.200 ;
        RECT 78.025 174.155 78.345 174.215 ;
        RECT 71.675 174.015 75.035 174.155 ;
        RECT 64.240 173.630 64.530 173.860 ;
        RECT 68.365 173.815 68.685 173.875 ;
        RECT 71.140 173.815 71.430 173.860 ;
        RECT 68.365 173.675 71.430 173.815 ;
        RECT 68.365 173.615 68.685 173.675 ;
        RECT 71.140 173.630 71.430 173.675 ;
        RECT 61.940 173.475 62.230 173.520 ;
        RECT 71.675 173.475 71.815 174.015 ;
        RECT 72.045 173.815 72.365 173.875 ;
        RECT 72.980 173.815 73.270 173.860 ;
        RECT 72.045 173.675 74.575 173.815 ;
        RECT 72.045 173.615 72.365 173.675 ;
        RECT 72.980 173.630 73.270 173.675 ;
        RECT 61.940 173.335 71.815 173.475 ;
        RECT 61.940 173.290 62.230 173.335 ;
        RECT 56.865 172.935 57.185 173.195 ;
        RECT 67.445 172.935 67.765 173.195 ;
        RECT 74.435 173.135 74.575 173.675 ;
        RECT 74.895 173.475 75.035 174.015 ;
        RECT 76.200 174.015 78.345 174.155 ;
        RECT 76.200 173.970 76.490 174.015 ;
        RECT 78.025 173.955 78.345 174.015 ;
        RECT 78.485 173.955 78.805 174.215 ;
        RECT 75.265 173.815 75.585 173.875 ;
        RECT 77.120 173.815 77.410 173.860 ;
        RECT 79.035 173.815 79.175 174.695 ;
        RECT 84.020 174.650 84.310 174.695 ;
        RECT 79.405 174.295 79.725 174.555 ;
        RECT 80.325 174.495 80.645 174.555 ;
        RECT 80.800 174.495 81.090 174.540 ;
        RECT 85.385 174.495 85.705 174.555 ;
        RECT 85.860 174.495 86.150 174.540 ;
        RECT 80.325 174.355 81.090 174.495 ;
        RECT 80.325 174.295 80.645 174.355 ;
        RECT 80.800 174.310 81.090 174.355 ;
        RECT 82.255 174.355 85.155 174.495 ;
        RECT 81.245 173.955 81.565 174.215 ;
        RECT 75.265 173.675 79.175 173.815 ;
        RECT 75.265 173.615 75.585 173.675 ;
        RECT 77.120 173.630 77.410 173.675 ;
        RECT 82.255 173.475 82.395 174.355 ;
        RECT 85.015 174.200 85.155 174.355 ;
        RECT 85.385 174.355 86.150 174.495 ;
        RECT 85.385 174.295 85.705 174.355 ;
        RECT 85.860 174.310 86.150 174.355 ;
        RECT 84.940 173.970 85.230 174.200 ;
        RECT 82.790 173.815 83.080 173.860 ;
        RECT 86.320 173.815 86.610 173.860 ;
        RECT 86.765 173.815 87.085 173.875 ;
        RECT 82.790 173.675 83.775 173.815 ;
        RECT 82.790 173.630 83.080 173.675 ;
        RECT 74.895 173.335 82.395 173.475 ;
        RECT 83.635 173.135 83.775 173.675 ;
        RECT 86.320 173.675 87.085 173.815 ;
        RECT 86.320 173.630 86.610 173.675 ;
        RECT 86.765 173.615 87.085 173.675 ;
        RECT 74.435 172.995 83.775 173.135 ;
        RECT 55.415 172.315 89.915 172.795 ;
        RECT 16.820 155.920 20.000 156.320 ;
        RECT 17.020 154.445 17.500 154.995 ;
        RECT 17.020 151.380 17.310 154.445 ;
        RECT 17.875 154.370 18.105 155.920 ;
        RECT 19.600 155.205 20.000 155.920 ;
        RECT 138.060 156.035 142.950 156.435 ;
        RECT 138.060 155.205 138.460 156.035 ;
        RECT 139.115 155.605 142.515 155.895 ;
        RECT 139.245 155.575 142.385 155.605 ;
        RECT 19.055 154.195 19.285 154.865 ;
        RECT 19.600 154.805 138.460 155.205 ;
        RECT 17.550 154.165 17.860 154.170 ;
        RECT 17.535 153.905 17.860 154.165 ;
        RECT 18.255 153.965 19.285 154.195 ;
        RECT 20.085 154.085 29.675 154.375 ;
        RECT 30.895 154.085 40.485 154.375 ;
        RECT 41.705 154.085 51.295 154.375 ;
        RECT 52.515 154.085 62.105 154.375 ;
        RECT 63.325 154.085 72.915 154.375 ;
        RECT 74.135 154.085 83.725 154.375 ;
        RECT 84.945 154.085 94.535 154.375 ;
        RECT 95.755 154.085 105.345 154.375 ;
        RECT 106.565 154.085 116.155 154.375 ;
        RECT 117.375 154.085 126.965 154.375 ;
        RECT 128.185 154.085 137.775 154.375 ;
        RECT 17.550 153.900 17.860 153.905 ;
        RECT 18.395 153.495 18.685 153.965 ;
        RECT 138.775 153.870 139.005 154.765 ;
        RECT 142.655 154.475 142.885 156.035 ;
        RECT 18.395 153.175 19.090 153.495 ;
        RECT 29.905 153.445 30.135 153.735 ;
        RECT 40.715 153.445 40.945 153.735 ;
        RECT 51.525 153.445 51.755 153.735 ;
        RECT 62.335 153.445 62.565 153.735 ;
        RECT 73.145 153.445 73.375 153.735 ;
        RECT 83.955 153.445 84.185 153.735 ;
        RECT 94.765 153.445 94.995 153.735 ;
        RECT 105.575 153.445 105.805 153.735 ;
        RECT 116.385 153.445 116.615 153.735 ;
        RECT 127.195 153.445 127.425 153.735 ;
        RECT 138.005 153.445 138.235 153.735 ;
        RECT 138.745 153.640 141.675 153.870 ;
        RECT 17.625 151.380 17.915 151.410 ;
        RECT 17.020 151.210 17.915 151.380 ;
        RECT 17.020 150.965 17.310 151.210 ;
        RECT 17.625 151.180 17.915 151.210 ;
        RECT 18.395 151.180 18.685 153.175 ;
        RECT 24.735 152.695 25.590 153.015 ;
        RECT 29.955 152.970 30.095 153.445 ;
        RECT 40.765 152.970 40.905 153.445 ;
        RECT 51.575 152.970 51.715 153.445 ;
        RECT 62.385 152.970 62.525 153.445 ;
        RECT 73.195 152.970 73.335 153.445 ;
        RECT 84.005 152.970 84.145 153.445 ;
        RECT 94.815 152.970 94.955 153.445 ;
        RECT 105.625 152.970 105.765 153.445 ;
        RECT 116.435 152.970 116.575 153.445 ;
        RECT 127.245 152.970 127.385 153.445 ;
        RECT 138.055 153.015 138.195 153.445 ;
        RECT 29.955 152.740 35.835 152.970 ;
        RECT 40.765 152.740 46.645 152.970 ;
        RECT 51.575 152.740 57.455 152.970 ;
        RECT 62.385 152.740 68.265 152.970 ;
        RECT 73.195 152.740 79.075 152.970 ;
        RECT 84.005 152.740 89.885 152.970 ;
        RECT 94.815 152.740 100.695 152.970 ;
        RECT 105.625 152.740 111.505 152.970 ;
        RECT 116.435 152.740 122.315 152.970 ;
        RECT 127.245 152.740 133.125 152.970 ;
        RECT 29.955 152.365 30.095 152.740 ;
        RECT 40.765 152.365 40.905 152.740 ;
        RECT 51.575 152.365 51.715 152.740 ;
        RECT 62.385 152.365 62.525 152.740 ;
        RECT 73.195 152.365 73.335 152.740 ;
        RECT 84.005 152.365 84.145 152.740 ;
        RECT 94.815 152.365 94.955 152.740 ;
        RECT 105.625 152.365 105.765 152.740 ;
        RECT 116.435 152.365 116.575 152.740 ;
        RECT 127.245 152.365 127.385 152.740 ;
        RECT 137.995 152.695 138.255 153.015 ;
        RECT 138.055 152.365 138.195 152.695 ;
        RECT 24.550 151.320 24.780 152.365 ;
        RECT 24.980 152.225 30.095 152.365 ;
        RECT 24.980 152.075 25.210 152.225 ;
        RECT 29.275 151.420 30.150 151.740 ;
        RECT 35.360 151.320 35.590 152.365 ;
        RECT 35.790 152.225 40.905 152.365 ;
        RECT 35.790 152.075 36.020 152.225 ;
        RECT 40.085 151.420 40.960 151.740 ;
        RECT 46.170 151.320 46.400 152.365 ;
        RECT 46.600 152.225 51.715 152.365 ;
        RECT 46.600 152.075 46.830 152.225 ;
        RECT 50.895 151.420 51.770 151.740 ;
        RECT 56.980 151.320 57.210 152.365 ;
        RECT 57.410 152.225 62.525 152.365 ;
        RECT 57.410 152.075 57.640 152.225 ;
        RECT 61.705 151.420 62.580 151.740 ;
        RECT 67.790 151.320 68.020 152.365 ;
        RECT 68.220 152.225 73.335 152.365 ;
        RECT 68.220 152.075 68.450 152.225 ;
        RECT 72.515 151.420 73.390 151.740 ;
        RECT 78.600 151.320 78.830 152.365 ;
        RECT 79.030 152.225 84.145 152.365 ;
        RECT 79.030 152.075 79.260 152.225 ;
        RECT 83.325 151.420 84.200 151.740 ;
        RECT 89.410 151.320 89.640 152.365 ;
        RECT 89.840 152.225 94.955 152.365 ;
        RECT 89.840 152.075 90.070 152.225 ;
        RECT 94.135 151.420 95.010 151.740 ;
        RECT 100.220 151.320 100.450 152.365 ;
        RECT 100.650 152.225 105.765 152.365 ;
        RECT 100.650 152.075 100.880 152.225 ;
        RECT 105.560 151.695 105.820 151.740 ;
        RECT 104.945 151.465 105.820 151.695 ;
        RECT 105.560 151.420 105.820 151.465 ;
        RECT 111.030 151.320 111.260 152.365 ;
        RECT 111.460 152.225 116.575 152.365 ;
        RECT 111.460 152.075 111.690 152.225 ;
        RECT 116.370 151.695 116.630 151.740 ;
        RECT 115.755 151.465 116.630 151.695 ;
        RECT 116.370 151.420 116.630 151.465 ;
        RECT 121.840 151.320 122.070 152.365 ;
        RECT 122.270 152.225 127.385 152.365 ;
        RECT 122.270 152.075 122.500 152.225 ;
        RECT 127.180 151.695 127.440 151.740 ;
        RECT 126.565 151.465 127.440 151.695 ;
        RECT 127.180 151.420 127.440 151.465 ;
        RECT 132.650 151.320 132.880 152.365 ;
        RECT 133.080 152.225 138.195 152.365 ;
        RECT 133.080 152.075 133.310 152.225 ;
        RECT 138.675 152.045 138.945 152.395 ;
        RECT 139.980 152.090 140.270 152.990 ;
        RECT 141.385 152.130 141.675 152.990 ;
        RECT 141.060 152.090 141.675 152.130 ;
        RECT 139.825 151.860 140.630 152.090 ;
        RECT 141.030 151.860 141.675 152.090 ;
        RECT 142.645 152.045 143.015 152.415 ;
        RECT 137.990 151.695 138.250 151.740 ;
        RECT 137.375 151.465 138.250 151.695 ;
        RECT 137.990 151.420 138.250 151.465 ;
        RECT 24.550 151.030 29.080 151.320 ;
        RECT 35.360 151.030 39.890 151.320 ;
        RECT 46.170 151.030 50.700 151.320 ;
        RECT 56.980 151.030 61.510 151.320 ;
        RECT 67.790 151.030 72.320 151.320 ;
        RECT 78.600 151.030 83.130 151.320 ;
        RECT 89.410 151.030 93.940 151.320 ;
        RECT 100.220 151.030 104.750 151.320 ;
        RECT 111.030 151.030 115.560 151.320 ;
        RECT 121.840 151.030 126.370 151.320 ;
        RECT 132.650 151.030 137.180 151.320 ;
        RECT 139.825 151.140 140.055 151.860 ;
        RECT 141.060 151.810 141.640 151.860 ;
        RECT 17.600 150.750 18.685 150.980 ;
        RECT 18.085 150.535 18.225 150.750 ;
        RECT 140.340 150.535 141.320 151.060 ;
        RECT 16.765 150.135 142.950 150.535 ;
        RECT 16.845 144.745 20.025 145.145 ;
        RECT 17.045 143.270 17.525 143.820 ;
        RECT 17.045 140.205 17.335 143.270 ;
        RECT 17.900 143.195 18.130 144.745 ;
        RECT 19.625 144.030 20.025 144.745 ;
        RECT 138.085 144.860 142.975 145.260 ;
        RECT 138.085 144.030 138.485 144.860 ;
        RECT 139.140 144.430 142.540 144.720 ;
        RECT 139.270 144.400 142.410 144.430 ;
        RECT 19.080 143.020 19.310 143.690 ;
        RECT 19.625 143.630 138.485 144.030 ;
        RECT 17.575 142.990 17.885 142.995 ;
        RECT 17.560 142.730 17.885 142.990 ;
        RECT 18.280 142.790 19.310 143.020 ;
        RECT 20.110 142.910 29.700 143.200 ;
        RECT 30.920 142.910 40.510 143.200 ;
        RECT 41.730 142.910 51.320 143.200 ;
        RECT 52.540 142.910 62.130 143.200 ;
        RECT 63.350 142.910 72.940 143.200 ;
        RECT 74.160 142.910 83.750 143.200 ;
        RECT 84.970 142.910 94.560 143.200 ;
        RECT 95.780 142.910 105.370 143.200 ;
        RECT 106.590 142.910 116.180 143.200 ;
        RECT 117.400 142.910 126.990 143.200 ;
        RECT 128.210 142.910 137.800 143.200 ;
        RECT 17.575 142.725 17.885 142.730 ;
        RECT 18.420 142.320 18.710 142.790 ;
        RECT 138.800 142.695 139.030 143.590 ;
        RECT 142.680 143.300 142.910 144.860 ;
        RECT 18.420 142.000 19.115 142.320 ;
        RECT 29.930 142.270 30.160 142.560 ;
        RECT 40.740 142.270 40.970 142.560 ;
        RECT 51.550 142.270 51.780 142.560 ;
        RECT 62.360 142.270 62.590 142.560 ;
        RECT 73.170 142.270 73.400 142.560 ;
        RECT 83.980 142.270 84.210 142.560 ;
        RECT 94.790 142.270 95.020 142.560 ;
        RECT 105.600 142.270 105.830 142.560 ;
        RECT 116.410 142.270 116.640 142.560 ;
        RECT 127.220 142.270 127.450 142.560 ;
        RECT 138.030 142.270 138.260 142.560 ;
        RECT 138.770 142.465 141.700 142.695 ;
        RECT 17.650 140.205 17.940 140.235 ;
        RECT 17.045 140.035 17.940 140.205 ;
        RECT 17.045 139.790 17.335 140.035 ;
        RECT 17.650 140.005 17.940 140.035 ;
        RECT 18.420 140.005 18.710 142.000 ;
        RECT 24.760 141.520 25.615 141.840 ;
        RECT 29.980 141.795 30.120 142.270 ;
        RECT 40.790 141.795 40.930 142.270 ;
        RECT 51.600 141.795 51.740 142.270 ;
        RECT 62.410 141.795 62.550 142.270 ;
        RECT 73.220 141.795 73.360 142.270 ;
        RECT 84.030 141.795 84.170 142.270 ;
        RECT 94.840 141.795 94.980 142.270 ;
        RECT 105.650 141.795 105.790 142.270 ;
        RECT 116.460 141.795 116.600 142.270 ;
        RECT 127.270 141.795 127.410 142.270 ;
        RECT 138.080 141.840 138.220 142.270 ;
        RECT 29.980 141.565 35.860 141.795 ;
        RECT 40.790 141.565 46.670 141.795 ;
        RECT 51.600 141.565 57.480 141.795 ;
        RECT 62.410 141.565 68.290 141.795 ;
        RECT 73.220 141.565 79.100 141.795 ;
        RECT 84.030 141.565 89.910 141.795 ;
        RECT 94.840 141.565 100.720 141.795 ;
        RECT 105.650 141.565 111.530 141.795 ;
        RECT 116.460 141.565 122.340 141.795 ;
        RECT 127.270 141.565 133.150 141.795 ;
        RECT 29.980 141.190 30.120 141.565 ;
        RECT 40.790 141.190 40.930 141.565 ;
        RECT 51.600 141.190 51.740 141.565 ;
        RECT 62.410 141.190 62.550 141.565 ;
        RECT 73.220 141.190 73.360 141.565 ;
        RECT 84.030 141.190 84.170 141.565 ;
        RECT 94.840 141.190 94.980 141.565 ;
        RECT 105.650 141.190 105.790 141.565 ;
        RECT 116.460 141.190 116.600 141.565 ;
        RECT 127.270 141.190 127.410 141.565 ;
        RECT 138.020 141.520 138.280 141.840 ;
        RECT 138.080 141.190 138.220 141.520 ;
        RECT 24.575 140.145 24.805 141.190 ;
        RECT 25.005 141.050 30.120 141.190 ;
        RECT 25.005 140.900 25.235 141.050 ;
        RECT 29.300 140.245 30.175 140.565 ;
        RECT 35.385 140.145 35.615 141.190 ;
        RECT 35.815 141.050 40.930 141.190 ;
        RECT 35.815 140.900 36.045 141.050 ;
        RECT 40.110 140.245 40.985 140.565 ;
        RECT 46.195 140.145 46.425 141.190 ;
        RECT 46.625 141.050 51.740 141.190 ;
        RECT 46.625 140.900 46.855 141.050 ;
        RECT 50.920 140.245 51.795 140.565 ;
        RECT 57.005 140.145 57.235 141.190 ;
        RECT 57.435 141.050 62.550 141.190 ;
        RECT 57.435 140.900 57.665 141.050 ;
        RECT 61.730 140.245 62.605 140.565 ;
        RECT 67.815 140.145 68.045 141.190 ;
        RECT 68.245 141.050 73.360 141.190 ;
        RECT 68.245 140.900 68.475 141.050 ;
        RECT 72.540 140.245 73.415 140.565 ;
        RECT 78.625 140.145 78.855 141.190 ;
        RECT 79.055 141.050 84.170 141.190 ;
        RECT 79.055 140.900 79.285 141.050 ;
        RECT 83.350 140.245 84.225 140.565 ;
        RECT 89.435 140.145 89.665 141.190 ;
        RECT 89.865 141.050 94.980 141.190 ;
        RECT 89.865 140.900 90.095 141.050 ;
        RECT 94.160 140.245 95.035 140.565 ;
        RECT 100.245 140.145 100.475 141.190 ;
        RECT 100.675 141.050 105.790 141.190 ;
        RECT 100.675 140.900 100.905 141.050 ;
        RECT 105.585 140.520 105.845 140.565 ;
        RECT 104.970 140.290 105.845 140.520 ;
        RECT 105.585 140.245 105.845 140.290 ;
        RECT 111.055 140.145 111.285 141.190 ;
        RECT 111.485 141.050 116.600 141.190 ;
        RECT 111.485 140.900 111.715 141.050 ;
        RECT 116.395 140.520 116.655 140.565 ;
        RECT 115.780 140.290 116.655 140.520 ;
        RECT 116.395 140.245 116.655 140.290 ;
        RECT 121.865 140.145 122.095 141.190 ;
        RECT 122.295 141.050 127.410 141.190 ;
        RECT 122.295 140.900 122.525 141.050 ;
        RECT 127.205 140.520 127.465 140.565 ;
        RECT 126.590 140.290 127.465 140.520 ;
        RECT 127.205 140.245 127.465 140.290 ;
        RECT 132.675 140.145 132.905 141.190 ;
        RECT 133.105 141.050 138.220 141.190 ;
        RECT 133.105 140.900 133.335 141.050 ;
        RECT 138.700 140.870 138.970 141.220 ;
        RECT 140.005 140.915 140.295 141.815 ;
        RECT 141.410 140.960 141.700 141.815 ;
        RECT 141.060 140.915 141.700 140.960 ;
        RECT 139.850 140.685 140.655 140.915 ;
        RECT 141.055 140.685 141.700 140.915 ;
        RECT 142.670 140.870 143.040 141.240 ;
        RECT 138.015 140.520 138.275 140.565 ;
        RECT 137.400 140.290 138.275 140.520 ;
        RECT 138.015 140.245 138.275 140.290 ;
        RECT 24.575 139.855 29.105 140.145 ;
        RECT 35.385 139.855 39.915 140.145 ;
        RECT 46.195 139.855 50.725 140.145 ;
        RECT 57.005 139.855 61.535 140.145 ;
        RECT 67.815 139.855 72.345 140.145 ;
        RECT 78.625 139.855 83.155 140.145 ;
        RECT 89.435 139.855 93.965 140.145 ;
        RECT 100.245 139.855 104.775 140.145 ;
        RECT 111.055 139.855 115.585 140.145 ;
        RECT 121.865 139.855 126.395 140.145 ;
        RECT 132.675 139.855 137.205 140.145 ;
        RECT 139.850 139.965 140.080 140.685 ;
        RECT 141.060 140.640 141.640 140.685 ;
        RECT 17.625 139.575 18.710 139.805 ;
        RECT 18.110 139.360 18.250 139.575 ;
        RECT 140.365 139.360 141.345 139.885 ;
        RECT 16.790 138.960 142.975 139.360 ;
        RECT 16.875 134.910 20.055 135.310 ;
        RECT 17.075 133.435 17.555 133.985 ;
        RECT 17.075 130.370 17.365 133.435 ;
        RECT 17.930 133.360 18.160 134.910 ;
        RECT 19.655 134.195 20.055 134.910 ;
        RECT 138.115 135.025 143.005 135.425 ;
        RECT 138.115 134.195 138.515 135.025 ;
        RECT 139.170 134.595 142.570 134.885 ;
        RECT 139.300 134.565 142.440 134.595 ;
        RECT 19.110 133.185 19.340 133.855 ;
        RECT 19.655 133.795 138.515 134.195 ;
        RECT 17.605 133.155 17.915 133.160 ;
        RECT 17.590 132.895 17.915 133.155 ;
        RECT 18.310 132.955 19.340 133.185 ;
        RECT 20.140 133.075 29.730 133.365 ;
        RECT 30.950 133.075 40.540 133.365 ;
        RECT 41.760 133.075 51.350 133.365 ;
        RECT 52.570 133.075 62.160 133.365 ;
        RECT 63.380 133.075 72.970 133.365 ;
        RECT 74.190 133.075 83.780 133.365 ;
        RECT 85.000 133.075 94.590 133.365 ;
        RECT 95.810 133.075 105.400 133.365 ;
        RECT 106.620 133.075 116.210 133.365 ;
        RECT 117.430 133.075 127.020 133.365 ;
        RECT 128.240 133.075 137.830 133.365 ;
        RECT 17.605 132.890 17.915 132.895 ;
        RECT 18.450 132.485 18.740 132.955 ;
        RECT 138.830 132.860 139.060 133.755 ;
        RECT 142.710 133.465 142.940 135.025 ;
        RECT 18.450 132.165 19.145 132.485 ;
        RECT 29.960 132.435 30.190 132.725 ;
        RECT 40.770 132.435 41.000 132.725 ;
        RECT 51.580 132.435 51.810 132.725 ;
        RECT 62.390 132.435 62.620 132.725 ;
        RECT 73.200 132.435 73.430 132.725 ;
        RECT 84.010 132.435 84.240 132.725 ;
        RECT 94.820 132.435 95.050 132.725 ;
        RECT 105.630 132.435 105.860 132.725 ;
        RECT 116.440 132.435 116.670 132.725 ;
        RECT 127.250 132.435 127.480 132.725 ;
        RECT 138.060 132.435 138.290 132.725 ;
        RECT 138.800 132.630 141.730 132.860 ;
        RECT 17.680 130.370 17.970 130.400 ;
        RECT 17.075 130.200 17.970 130.370 ;
        RECT 17.075 129.955 17.365 130.200 ;
        RECT 17.680 130.170 17.970 130.200 ;
        RECT 18.450 130.170 18.740 132.165 ;
        RECT 24.790 131.685 25.645 132.005 ;
        RECT 30.010 131.960 30.150 132.435 ;
        RECT 40.820 131.960 40.960 132.435 ;
        RECT 51.630 131.960 51.770 132.435 ;
        RECT 62.440 131.960 62.580 132.435 ;
        RECT 73.250 131.960 73.390 132.435 ;
        RECT 84.060 131.960 84.200 132.435 ;
        RECT 94.870 131.960 95.010 132.435 ;
        RECT 105.680 131.960 105.820 132.435 ;
        RECT 116.490 131.960 116.630 132.435 ;
        RECT 127.300 131.960 127.440 132.435 ;
        RECT 138.110 132.005 138.250 132.435 ;
        RECT 30.010 131.730 35.890 131.960 ;
        RECT 40.820 131.730 46.700 131.960 ;
        RECT 51.630 131.730 57.510 131.960 ;
        RECT 62.440 131.730 68.320 131.960 ;
        RECT 73.250 131.730 79.130 131.960 ;
        RECT 84.060 131.730 89.940 131.960 ;
        RECT 94.870 131.730 100.750 131.960 ;
        RECT 105.680 131.730 111.560 131.960 ;
        RECT 116.490 131.730 122.370 131.960 ;
        RECT 127.300 131.730 133.180 131.960 ;
        RECT 30.010 131.355 30.150 131.730 ;
        RECT 40.820 131.355 40.960 131.730 ;
        RECT 51.630 131.355 51.770 131.730 ;
        RECT 62.440 131.355 62.580 131.730 ;
        RECT 73.250 131.355 73.390 131.730 ;
        RECT 84.060 131.355 84.200 131.730 ;
        RECT 94.870 131.355 95.010 131.730 ;
        RECT 105.680 131.355 105.820 131.730 ;
        RECT 116.490 131.355 116.630 131.730 ;
        RECT 127.300 131.355 127.440 131.730 ;
        RECT 138.050 131.685 138.310 132.005 ;
        RECT 138.110 131.355 138.250 131.685 ;
        RECT 24.605 130.310 24.835 131.355 ;
        RECT 25.035 131.215 30.150 131.355 ;
        RECT 25.035 131.065 25.265 131.215 ;
        RECT 29.330 130.410 30.205 130.730 ;
        RECT 35.415 130.310 35.645 131.355 ;
        RECT 35.845 131.215 40.960 131.355 ;
        RECT 35.845 131.065 36.075 131.215 ;
        RECT 40.140 130.410 41.015 130.730 ;
        RECT 46.225 130.310 46.455 131.355 ;
        RECT 46.655 131.215 51.770 131.355 ;
        RECT 46.655 131.065 46.885 131.215 ;
        RECT 50.950 130.410 51.825 130.730 ;
        RECT 57.035 130.310 57.265 131.355 ;
        RECT 57.465 131.215 62.580 131.355 ;
        RECT 57.465 131.065 57.695 131.215 ;
        RECT 61.760 130.410 62.635 130.730 ;
        RECT 67.845 130.310 68.075 131.355 ;
        RECT 68.275 131.215 73.390 131.355 ;
        RECT 68.275 131.065 68.505 131.215 ;
        RECT 72.570 130.410 73.445 130.730 ;
        RECT 78.655 130.310 78.885 131.355 ;
        RECT 79.085 131.215 84.200 131.355 ;
        RECT 79.085 131.065 79.315 131.215 ;
        RECT 83.380 130.410 84.255 130.730 ;
        RECT 89.465 130.310 89.695 131.355 ;
        RECT 89.895 131.215 95.010 131.355 ;
        RECT 89.895 131.065 90.125 131.215 ;
        RECT 94.190 130.410 95.065 130.730 ;
        RECT 100.275 130.310 100.505 131.355 ;
        RECT 100.705 131.215 105.820 131.355 ;
        RECT 100.705 131.065 100.935 131.215 ;
        RECT 105.615 130.685 105.875 130.730 ;
        RECT 105.000 130.455 105.875 130.685 ;
        RECT 105.615 130.410 105.875 130.455 ;
        RECT 111.085 130.310 111.315 131.355 ;
        RECT 111.515 131.215 116.630 131.355 ;
        RECT 111.515 131.065 111.745 131.215 ;
        RECT 116.425 130.685 116.685 130.730 ;
        RECT 115.810 130.455 116.685 130.685 ;
        RECT 116.425 130.410 116.685 130.455 ;
        RECT 121.895 130.310 122.125 131.355 ;
        RECT 122.325 131.215 127.440 131.355 ;
        RECT 122.325 131.065 122.555 131.215 ;
        RECT 127.235 130.685 127.495 130.730 ;
        RECT 126.620 130.455 127.495 130.685 ;
        RECT 127.235 130.410 127.495 130.455 ;
        RECT 132.705 130.310 132.935 131.355 ;
        RECT 133.135 131.215 138.250 131.355 ;
        RECT 133.135 131.065 133.365 131.215 ;
        RECT 138.730 131.035 139.000 131.385 ;
        RECT 140.035 131.080 140.325 131.980 ;
        RECT 141.440 131.130 141.730 131.980 ;
        RECT 139.880 130.850 140.685 131.080 ;
        RECT 141.060 130.850 141.730 131.130 ;
        RECT 142.700 131.035 143.070 131.405 ;
        RECT 138.045 130.685 138.305 130.730 ;
        RECT 137.430 130.455 138.305 130.685 ;
        RECT 138.045 130.410 138.305 130.455 ;
        RECT 24.605 130.020 29.135 130.310 ;
        RECT 35.415 130.020 39.945 130.310 ;
        RECT 46.225 130.020 50.755 130.310 ;
        RECT 57.035 130.020 61.565 130.310 ;
        RECT 67.845 130.020 72.375 130.310 ;
        RECT 78.655 130.020 83.185 130.310 ;
        RECT 89.465 130.020 93.995 130.310 ;
        RECT 100.275 130.020 104.805 130.310 ;
        RECT 111.085 130.020 115.615 130.310 ;
        RECT 121.895 130.020 126.425 130.310 ;
        RECT 132.705 130.020 137.235 130.310 ;
        RECT 139.880 130.130 140.110 130.850 ;
        RECT 141.060 130.810 141.640 130.850 ;
        RECT 17.655 129.740 18.740 129.970 ;
        RECT 18.140 129.525 18.280 129.740 ;
        RECT 140.395 129.525 141.375 130.050 ;
        RECT 16.820 129.125 143.005 129.525 ;
        RECT 16.760 120.570 140.690 120.970 ;
        RECT 16.960 119.095 17.440 119.645 ;
        RECT 16.960 117.405 17.250 119.095 ;
        RECT 17.815 119.020 18.045 120.570 ;
        RECT 22.155 119.735 22.385 120.570 ;
        RECT 32.965 119.735 33.195 120.570 ;
        RECT 43.775 119.735 44.005 120.570 ;
        RECT 54.585 119.735 54.815 120.570 ;
        RECT 65.395 119.735 65.625 120.570 ;
        RECT 76.205 119.735 76.435 120.570 ;
        RECT 87.015 119.735 87.245 120.570 ;
        RECT 97.825 119.735 98.055 120.570 ;
        RECT 108.635 119.735 108.865 120.570 ;
        RECT 119.445 119.735 119.675 120.570 ;
        RECT 130.255 119.735 130.485 120.570 ;
        RECT 138.890 120.070 140.405 120.300 ;
        RECT 17.450 118.500 17.820 118.870 ;
        RECT 18.995 118.845 19.225 119.515 ;
        RECT 20.225 119.230 21.240 119.550 ;
        RECT 21.810 119.505 22.820 119.735 ;
        RECT 31.035 119.230 32.050 119.550 ;
        RECT 32.620 119.505 33.630 119.735 ;
        RECT 41.845 119.230 42.860 119.550 ;
        RECT 43.430 119.505 44.440 119.735 ;
        RECT 52.655 119.230 53.670 119.550 ;
        RECT 54.240 119.505 55.250 119.735 ;
        RECT 63.465 119.230 64.480 119.550 ;
        RECT 65.050 119.505 66.060 119.735 ;
        RECT 74.275 119.230 75.290 119.550 ;
        RECT 75.860 119.505 76.870 119.735 ;
        RECT 85.085 119.230 86.100 119.550 ;
        RECT 86.670 119.505 87.680 119.735 ;
        RECT 95.895 119.230 96.910 119.550 ;
        RECT 97.480 119.505 98.490 119.735 ;
        RECT 106.705 119.230 107.720 119.550 ;
        RECT 108.290 119.505 109.300 119.735 ;
        RECT 117.515 119.230 118.530 119.550 ;
        RECT 119.100 119.505 120.110 119.735 ;
        RECT 128.325 119.230 129.340 119.550 ;
        RECT 129.910 119.505 130.920 119.735 ;
        RECT 25.420 118.975 25.680 119.045 ;
        RECT 36.230 118.975 36.490 119.045 ;
        RECT 47.040 118.975 47.300 119.045 ;
        RECT 57.850 118.975 58.110 119.045 ;
        RECT 68.660 118.975 68.920 119.045 ;
        RECT 79.470 118.975 79.730 119.045 ;
        RECT 90.280 118.975 90.540 119.045 ;
        RECT 101.090 118.975 101.350 119.045 ;
        RECT 111.900 118.975 112.160 119.045 ;
        RECT 122.710 118.975 122.970 119.045 ;
        RECT 133.520 118.975 133.780 119.045 ;
        RECT 18.195 118.615 19.225 118.845 ;
        RECT 18.335 118.145 18.625 118.615 ;
        RECT 19.995 118.530 23.825 118.820 ;
        RECT 24.335 118.805 25.680 118.975 ;
        RECT 18.335 117.825 19.030 118.145 ;
        RECT 24.335 118.140 24.505 118.805 ;
        RECT 25.420 118.725 25.680 118.805 ;
        RECT 30.805 118.530 34.635 118.820 ;
        RECT 35.145 118.805 36.490 118.975 ;
        RECT 35.145 118.140 35.315 118.805 ;
        RECT 36.230 118.725 36.490 118.805 ;
        RECT 41.615 118.530 45.445 118.820 ;
        RECT 45.955 118.805 47.300 118.975 ;
        RECT 45.955 118.140 46.125 118.805 ;
        RECT 47.040 118.725 47.300 118.805 ;
        RECT 52.425 118.530 56.255 118.820 ;
        RECT 56.765 118.805 58.110 118.975 ;
        RECT 56.765 118.140 56.935 118.805 ;
        RECT 57.850 118.725 58.110 118.805 ;
        RECT 63.235 118.530 67.065 118.820 ;
        RECT 67.575 118.805 68.920 118.975 ;
        RECT 67.575 118.140 67.745 118.805 ;
        RECT 68.660 118.725 68.920 118.805 ;
        RECT 74.045 118.530 77.875 118.820 ;
        RECT 78.385 118.805 79.730 118.975 ;
        RECT 78.385 118.140 78.555 118.805 ;
        RECT 79.470 118.725 79.730 118.805 ;
        RECT 84.855 118.530 88.685 118.820 ;
        RECT 89.195 118.805 90.540 118.975 ;
        RECT 89.195 118.140 89.365 118.805 ;
        RECT 90.280 118.725 90.540 118.805 ;
        RECT 95.665 118.530 99.495 118.820 ;
        RECT 100.005 118.805 101.350 118.975 ;
        RECT 100.005 118.140 100.175 118.805 ;
        RECT 101.090 118.725 101.350 118.805 ;
        RECT 106.475 118.530 110.305 118.820 ;
        RECT 110.815 118.805 112.160 118.975 ;
        RECT 110.815 118.140 110.985 118.805 ;
        RECT 111.900 118.725 112.160 118.805 ;
        RECT 117.285 118.530 121.115 118.820 ;
        RECT 121.625 118.805 122.970 118.975 ;
        RECT 121.625 118.140 121.795 118.805 ;
        RECT 122.710 118.725 122.970 118.805 ;
        RECT 128.095 118.530 131.925 118.820 ;
        RECT 132.435 118.805 133.780 118.975 ;
        RECT 132.435 118.140 132.605 118.805 ;
        RECT 133.520 118.725 133.780 118.805 ;
        RECT 19.565 117.970 24.505 118.140 ;
        RECT 30.375 117.970 35.315 118.140 ;
        RECT 41.185 117.970 46.125 118.140 ;
        RECT 51.995 117.970 56.935 118.140 ;
        RECT 62.805 117.970 67.745 118.140 ;
        RECT 73.615 117.970 78.555 118.140 ;
        RECT 84.425 117.970 89.365 118.140 ;
        RECT 95.235 117.970 100.175 118.140 ;
        RECT 106.045 117.970 110.985 118.140 ;
        RECT 116.855 117.970 121.795 118.140 ;
        RECT 127.665 117.970 132.605 118.140 ;
        RECT 16.960 117.085 17.770 117.405 ;
        RECT 16.960 116.030 17.250 117.085 ;
        RECT 17.565 116.030 17.855 116.060 ;
        RECT 16.960 115.860 17.855 116.030 ;
        RECT 16.960 115.615 17.250 115.860 ;
        RECT 17.565 115.830 17.855 115.860 ;
        RECT 18.335 115.830 18.625 117.825 ;
        RECT 19.565 117.490 24.095 117.970 ;
        RECT 24.990 117.485 26.010 117.805 ;
        RECT 30.375 117.490 34.905 117.970 ;
        RECT 35.800 117.485 36.820 117.805 ;
        RECT 41.185 117.490 45.715 117.970 ;
        RECT 46.610 117.485 47.630 117.805 ;
        RECT 51.995 117.490 56.525 117.970 ;
        RECT 57.420 117.485 58.440 117.805 ;
        RECT 62.805 117.490 67.335 117.970 ;
        RECT 68.230 117.485 69.250 117.805 ;
        RECT 73.615 117.490 78.145 117.970 ;
        RECT 79.040 117.485 80.060 117.805 ;
        RECT 84.425 117.490 88.955 117.970 ;
        RECT 89.850 117.485 90.870 117.805 ;
        RECT 95.235 117.490 99.765 117.970 ;
        RECT 100.660 117.485 101.680 117.805 ;
        RECT 106.045 117.490 110.575 117.970 ;
        RECT 111.470 117.485 112.490 117.805 ;
        RECT 116.855 117.490 121.385 117.970 ;
        RECT 122.280 117.485 123.300 117.805 ;
        RECT 127.665 117.490 132.195 117.970 ;
        RECT 133.090 117.485 134.110 117.805 ;
        RECT 138.890 117.655 139.120 120.070 ;
        RECT 140.450 118.595 140.680 119.755 ;
        RECT 140.435 118.275 140.695 118.595 ;
        RECT 138.760 117.065 139.455 117.385 ;
        RECT 139.670 116.635 139.900 117.945 ;
        RECT 140.450 117.655 140.680 118.275 ;
        RECT 140.075 117.040 140.445 117.410 ;
        RECT 140.410 116.635 140.640 116.665 ;
        RECT 139.670 116.405 140.640 116.635 ;
        RECT 140.410 116.375 140.640 116.405 ;
        RECT 139.625 115.815 139.945 116.075 ;
        RECT 17.540 115.400 18.625 115.630 ;
        RECT 20.025 115.465 29.615 115.755 ;
        RECT 30.835 115.465 40.425 115.755 ;
        RECT 41.645 115.465 51.235 115.755 ;
        RECT 52.455 115.465 62.045 115.755 ;
        RECT 63.265 115.465 72.855 115.755 ;
        RECT 74.075 115.465 83.665 115.755 ;
        RECT 84.885 115.465 94.475 115.755 ;
        RECT 95.695 115.465 105.285 115.755 ;
        RECT 106.505 115.465 116.095 115.755 ;
        RECT 117.315 115.465 126.905 115.755 ;
        RECT 128.125 115.465 137.715 115.755 ;
        RECT 18.025 115.185 18.165 115.400 ;
        RECT 16.705 114.785 140.705 115.185 ;
        RECT 16.745 111.755 140.675 112.155 ;
        RECT 16.945 110.280 17.425 110.830 ;
        RECT 16.945 108.590 17.235 110.280 ;
        RECT 17.800 110.205 18.030 111.755 ;
        RECT 22.140 110.920 22.370 111.755 ;
        RECT 32.950 110.920 33.180 111.755 ;
        RECT 43.760 110.920 43.990 111.755 ;
        RECT 54.570 110.920 54.800 111.755 ;
        RECT 65.380 110.920 65.610 111.755 ;
        RECT 76.190 110.920 76.420 111.755 ;
        RECT 87.000 110.920 87.230 111.755 ;
        RECT 97.810 110.920 98.040 111.755 ;
        RECT 108.620 110.920 108.850 111.755 ;
        RECT 119.430 110.920 119.660 111.755 ;
        RECT 130.240 110.920 130.470 111.755 ;
        RECT 138.875 111.255 140.390 111.485 ;
        RECT 17.435 109.685 17.805 110.055 ;
        RECT 18.980 110.030 19.210 110.700 ;
        RECT 20.210 110.415 21.225 110.735 ;
        RECT 21.795 110.690 22.805 110.920 ;
        RECT 31.020 110.415 32.035 110.735 ;
        RECT 32.605 110.690 33.615 110.920 ;
        RECT 41.830 110.415 42.845 110.735 ;
        RECT 43.415 110.690 44.425 110.920 ;
        RECT 52.640 110.415 53.655 110.735 ;
        RECT 54.225 110.690 55.235 110.920 ;
        RECT 63.450 110.415 64.465 110.735 ;
        RECT 65.035 110.690 66.045 110.920 ;
        RECT 74.260 110.415 75.275 110.735 ;
        RECT 75.845 110.690 76.855 110.920 ;
        RECT 85.070 110.415 86.085 110.735 ;
        RECT 86.655 110.690 87.665 110.920 ;
        RECT 95.880 110.415 96.895 110.735 ;
        RECT 97.465 110.690 98.475 110.920 ;
        RECT 106.690 110.415 107.705 110.735 ;
        RECT 108.275 110.690 109.285 110.920 ;
        RECT 117.500 110.415 118.515 110.735 ;
        RECT 119.085 110.690 120.095 110.920 ;
        RECT 128.310 110.415 129.325 110.735 ;
        RECT 129.895 110.690 130.905 110.920 ;
        RECT 25.405 110.160 25.665 110.230 ;
        RECT 36.215 110.160 36.475 110.230 ;
        RECT 47.025 110.160 47.285 110.230 ;
        RECT 57.835 110.160 58.095 110.230 ;
        RECT 68.645 110.160 68.905 110.230 ;
        RECT 79.455 110.160 79.715 110.230 ;
        RECT 90.265 110.160 90.525 110.230 ;
        RECT 101.075 110.160 101.335 110.230 ;
        RECT 111.885 110.160 112.145 110.230 ;
        RECT 122.695 110.160 122.955 110.230 ;
        RECT 133.505 110.160 133.765 110.230 ;
        RECT 18.180 109.800 19.210 110.030 ;
        RECT 18.320 109.330 18.610 109.800 ;
        RECT 19.980 109.715 23.810 110.005 ;
        RECT 24.320 109.990 25.665 110.160 ;
        RECT 18.320 109.010 19.015 109.330 ;
        RECT 24.320 109.325 24.490 109.990 ;
        RECT 25.405 109.910 25.665 109.990 ;
        RECT 30.790 109.715 34.620 110.005 ;
        RECT 35.130 109.990 36.475 110.160 ;
        RECT 35.130 109.325 35.300 109.990 ;
        RECT 36.215 109.910 36.475 109.990 ;
        RECT 41.600 109.715 45.430 110.005 ;
        RECT 45.940 109.990 47.285 110.160 ;
        RECT 45.940 109.325 46.110 109.990 ;
        RECT 47.025 109.910 47.285 109.990 ;
        RECT 52.410 109.715 56.240 110.005 ;
        RECT 56.750 109.990 58.095 110.160 ;
        RECT 56.750 109.325 56.920 109.990 ;
        RECT 57.835 109.910 58.095 109.990 ;
        RECT 63.220 109.715 67.050 110.005 ;
        RECT 67.560 109.990 68.905 110.160 ;
        RECT 67.560 109.325 67.730 109.990 ;
        RECT 68.645 109.910 68.905 109.990 ;
        RECT 74.030 109.715 77.860 110.005 ;
        RECT 78.370 109.990 79.715 110.160 ;
        RECT 78.370 109.325 78.540 109.990 ;
        RECT 79.455 109.910 79.715 109.990 ;
        RECT 84.840 109.715 88.670 110.005 ;
        RECT 89.180 109.990 90.525 110.160 ;
        RECT 89.180 109.325 89.350 109.990 ;
        RECT 90.265 109.910 90.525 109.990 ;
        RECT 95.650 109.715 99.480 110.005 ;
        RECT 99.990 109.990 101.335 110.160 ;
        RECT 99.990 109.325 100.160 109.990 ;
        RECT 101.075 109.910 101.335 109.990 ;
        RECT 106.460 109.715 110.290 110.005 ;
        RECT 110.800 109.990 112.145 110.160 ;
        RECT 110.800 109.325 110.970 109.990 ;
        RECT 111.885 109.910 112.145 109.990 ;
        RECT 117.270 109.715 121.100 110.005 ;
        RECT 121.610 109.990 122.955 110.160 ;
        RECT 121.610 109.325 121.780 109.990 ;
        RECT 122.695 109.910 122.955 109.990 ;
        RECT 128.080 109.715 131.910 110.005 ;
        RECT 132.420 109.990 133.765 110.160 ;
        RECT 132.420 109.325 132.590 109.990 ;
        RECT 133.505 109.910 133.765 109.990 ;
        RECT 19.550 109.155 24.490 109.325 ;
        RECT 30.360 109.155 35.300 109.325 ;
        RECT 41.170 109.155 46.110 109.325 ;
        RECT 51.980 109.155 56.920 109.325 ;
        RECT 62.790 109.155 67.730 109.325 ;
        RECT 73.600 109.155 78.540 109.325 ;
        RECT 84.410 109.155 89.350 109.325 ;
        RECT 95.220 109.155 100.160 109.325 ;
        RECT 106.030 109.155 110.970 109.325 ;
        RECT 116.840 109.155 121.780 109.325 ;
        RECT 127.650 109.155 132.590 109.325 ;
        RECT 16.945 108.270 17.755 108.590 ;
        RECT 16.945 107.215 17.235 108.270 ;
        RECT 17.550 107.215 17.840 107.245 ;
        RECT 16.945 107.045 17.840 107.215 ;
        RECT 16.945 106.800 17.235 107.045 ;
        RECT 17.550 107.015 17.840 107.045 ;
        RECT 18.320 107.015 18.610 109.010 ;
        RECT 19.550 108.675 24.080 109.155 ;
        RECT 24.975 108.670 25.995 108.990 ;
        RECT 30.360 108.675 34.890 109.155 ;
        RECT 35.785 108.670 36.805 108.990 ;
        RECT 41.170 108.675 45.700 109.155 ;
        RECT 46.595 108.670 47.615 108.990 ;
        RECT 51.980 108.675 56.510 109.155 ;
        RECT 57.405 108.670 58.425 108.990 ;
        RECT 62.790 108.675 67.320 109.155 ;
        RECT 68.215 108.670 69.235 108.990 ;
        RECT 73.600 108.675 78.130 109.155 ;
        RECT 79.025 108.670 80.045 108.990 ;
        RECT 84.410 108.675 88.940 109.155 ;
        RECT 89.835 108.670 90.855 108.990 ;
        RECT 95.220 108.675 99.750 109.155 ;
        RECT 100.645 108.670 101.665 108.990 ;
        RECT 106.030 108.675 110.560 109.155 ;
        RECT 111.455 108.670 112.475 108.990 ;
        RECT 116.840 108.675 121.370 109.155 ;
        RECT 122.265 108.670 123.285 108.990 ;
        RECT 127.650 108.675 132.180 109.155 ;
        RECT 133.075 108.670 134.095 108.990 ;
        RECT 138.875 108.840 139.105 111.255 ;
        RECT 140.435 109.780 140.665 110.940 ;
        RECT 140.420 109.460 140.680 109.780 ;
        RECT 138.745 108.250 139.440 108.570 ;
        RECT 139.655 107.820 139.885 109.130 ;
        RECT 140.435 108.840 140.665 109.460 ;
        RECT 140.060 108.225 140.430 108.595 ;
        RECT 140.395 107.820 140.625 107.850 ;
        RECT 139.655 107.590 140.625 107.820 ;
        RECT 140.395 107.560 140.625 107.590 ;
        RECT 139.610 107.000 139.930 107.260 ;
        RECT 17.525 106.585 18.610 106.815 ;
        RECT 20.010 106.650 29.600 106.940 ;
        RECT 30.820 106.650 40.410 106.940 ;
        RECT 41.630 106.650 51.220 106.940 ;
        RECT 52.440 106.650 62.030 106.940 ;
        RECT 63.250 106.650 72.840 106.940 ;
        RECT 74.060 106.650 83.650 106.940 ;
        RECT 84.870 106.650 94.460 106.940 ;
        RECT 95.680 106.650 105.270 106.940 ;
        RECT 106.490 106.650 116.080 106.940 ;
        RECT 117.300 106.650 126.890 106.940 ;
        RECT 128.110 106.650 137.700 106.940 ;
        RECT 18.010 106.370 18.150 106.585 ;
        RECT 16.690 105.970 140.690 106.370 ;
        RECT 16.910 105.945 19.090 105.970 ;
        RECT 16.375 101.920 140.305 102.320 ;
        RECT 16.575 100.445 17.055 100.995 ;
        RECT 16.575 98.755 16.865 100.445 ;
        RECT 17.430 100.370 17.660 101.920 ;
        RECT 21.770 101.085 22.000 101.920 ;
        RECT 32.580 101.085 32.810 101.920 ;
        RECT 43.390 101.085 43.620 101.920 ;
        RECT 54.200 101.085 54.430 101.920 ;
        RECT 65.010 101.085 65.240 101.920 ;
        RECT 75.820 101.085 76.050 101.920 ;
        RECT 86.630 101.085 86.860 101.920 ;
        RECT 97.440 101.085 97.670 101.920 ;
        RECT 108.250 101.085 108.480 101.920 ;
        RECT 119.060 101.085 119.290 101.920 ;
        RECT 129.870 101.085 130.100 101.920 ;
        RECT 138.505 101.420 140.020 101.650 ;
        RECT 17.065 99.850 17.435 100.220 ;
        RECT 18.610 100.195 18.840 100.865 ;
        RECT 19.840 100.580 20.855 100.900 ;
        RECT 21.425 100.855 22.435 101.085 ;
        RECT 30.650 100.580 31.665 100.900 ;
        RECT 32.235 100.855 33.245 101.085 ;
        RECT 41.460 100.580 42.475 100.900 ;
        RECT 43.045 100.855 44.055 101.085 ;
        RECT 52.270 100.580 53.285 100.900 ;
        RECT 53.855 100.855 54.865 101.085 ;
        RECT 63.080 100.580 64.095 100.900 ;
        RECT 64.665 100.855 65.675 101.085 ;
        RECT 73.890 100.580 74.905 100.900 ;
        RECT 75.475 100.855 76.485 101.085 ;
        RECT 84.700 100.580 85.715 100.900 ;
        RECT 86.285 100.855 87.295 101.085 ;
        RECT 95.510 100.580 96.525 100.900 ;
        RECT 97.095 100.855 98.105 101.085 ;
        RECT 106.320 100.580 107.335 100.900 ;
        RECT 107.905 100.855 108.915 101.085 ;
        RECT 117.130 100.580 118.145 100.900 ;
        RECT 118.715 100.855 119.725 101.085 ;
        RECT 127.940 100.580 128.955 100.900 ;
        RECT 129.525 100.855 130.535 101.085 ;
        RECT 25.035 100.325 25.295 100.395 ;
        RECT 35.845 100.325 36.105 100.395 ;
        RECT 46.655 100.325 46.915 100.395 ;
        RECT 57.465 100.325 57.725 100.395 ;
        RECT 68.275 100.325 68.535 100.395 ;
        RECT 79.085 100.325 79.345 100.395 ;
        RECT 89.895 100.325 90.155 100.395 ;
        RECT 100.705 100.325 100.965 100.395 ;
        RECT 111.515 100.325 111.775 100.395 ;
        RECT 122.325 100.325 122.585 100.395 ;
        RECT 133.135 100.325 133.395 100.395 ;
        RECT 17.810 99.965 18.840 100.195 ;
        RECT 17.950 99.495 18.240 99.965 ;
        RECT 19.610 99.880 23.440 100.170 ;
        RECT 23.950 100.155 25.295 100.325 ;
        RECT 17.950 99.175 18.645 99.495 ;
        RECT 23.950 99.490 24.120 100.155 ;
        RECT 25.035 100.075 25.295 100.155 ;
        RECT 30.420 99.880 34.250 100.170 ;
        RECT 34.760 100.155 36.105 100.325 ;
        RECT 34.760 99.490 34.930 100.155 ;
        RECT 35.845 100.075 36.105 100.155 ;
        RECT 41.230 99.880 45.060 100.170 ;
        RECT 45.570 100.155 46.915 100.325 ;
        RECT 45.570 99.490 45.740 100.155 ;
        RECT 46.655 100.075 46.915 100.155 ;
        RECT 52.040 99.880 55.870 100.170 ;
        RECT 56.380 100.155 57.725 100.325 ;
        RECT 56.380 99.490 56.550 100.155 ;
        RECT 57.465 100.075 57.725 100.155 ;
        RECT 62.850 99.880 66.680 100.170 ;
        RECT 67.190 100.155 68.535 100.325 ;
        RECT 67.190 99.490 67.360 100.155 ;
        RECT 68.275 100.075 68.535 100.155 ;
        RECT 73.660 99.880 77.490 100.170 ;
        RECT 78.000 100.155 79.345 100.325 ;
        RECT 78.000 99.490 78.170 100.155 ;
        RECT 79.085 100.075 79.345 100.155 ;
        RECT 84.470 99.880 88.300 100.170 ;
        RECT 88.810 100.155 90.155 100.325 ;
        RECT 88.810 99.490 88.980 100.155 ;
        RECT 89.895 100.075 90.155 100.155 ;
        RECT 95.280 99.880 99.110 100.170 ;
        RECT 99.620 100.155 100.965 100.325 ;
        RECT 99.620 99.490 99.790 100.155 ;
        RECT 100.705 100.075 100.965 100.155 ;
        RECT 106.090 99.880 109.920 100.170 ;
        RECT 110.430 100.155 111.775 100.325 ;
        RECT 110.430 99.490 110.600 100.155 ;
        RECT 111.515 100.075 111.775 100.155 ;
        RECT 116.900 99.880 120.730 100.170 ;
        RECT 121.240 100.155 122.585 100.325 ;
        RECT 121.240 99.490 121.410 100.155 ;
        RECT 122.325 100.075 122.585 100.155 ;
        RECT 127.710 99.880 131.540 100.170 ;
        RECT 132.050 100.155 133.395 100.325 ;
        RECT 132.050 99.490 132.220 100.155 ;
        RECT 133.135 100.075 133.395 100.155 ;
        RECT 19.180 99.320 24.120 99.490 ;
        RECT 29.990 99.320 34.930 99.490 ;
        RECT 40.800 99.320 45.740 99.490 ;
        RECT 51.610 99.320 56.550 99.490 ;
        RECT 62.420 99.320 67.360 99.490 ;
        RECT 73.230 99.320 78.170 99.490 ;
        RECT 84.040 99.320 88.980 99.490 ;
        RECT 94.850 99.320 99.790 99.490 ;
        RECT 105.660 99.320 110.600 99.490 ;
        RECT 116.470 99.320 121.410 99.490 ;
        RECT 127.280 99.320 132.220 99.490 ;
        RECT 16.575 98.435 17.385 98.755 ;
        RECT 16.575 97.380 16.865 98.435 ;
        RECT 17.180 97.380 17.470 97.410 ;
        RECT 16.575 97.210 17.470 97.380 ;
        RECT 16.575 96.965 16.865 97.210 ;
        RECT 17.180 97.180 17.470 97.210 ;
        RECT 17.950 97.180 18.240 99.175 ;
        RECT 19.180 98.840 23.710 99.320 ;
        RECT 24.605 98.835 25.625 99.155 ;
        RECT 29.990 98.840 34.520 99.320 ;
        RECT 35.415 98.835 36.435 99.155 ;
        RECT 40.800 98.840 45.330 99.320 ;
        RECT 46.225 98.835 47.245 99.155 ;
        RECT 51.610 98.840 56.140 99.320 ;
        RECT 57.035 98.835 58.055 99.155 ;
        RECT 62.420 98.840 66.950 99.320 ;
        RECT 67.845 98.835 68.865 99.155 ;
        RECT 73.230 98.840 77.760 99.320 ;
        RECT 78.655 98.835 79.675 99.155 ;
        RECT 84.040 98.840 88.570 99.320 ;
        RECT 89.465 98.835 90.485 99.155 ;
        RECT 94.850 98.840 99.380 99.320 ;
        RECT 100.275 98.835 101.295 99.155 ;
        RECT 105.660 98.840 110.190 99.320 ;
        RECT 111.085 98.835 112.105 99.155 ;
        RECT 116.470 98.840 121.000 99.320 ;
        RECT 121.895 98.835 122.915 99.155 ;
        RECT 127.280 98.840 131.810 99.320 ;
        RECT 132.705 98.835 133.725 99.155 ;
        RECT 138.505 99.005 138.735 101.420 ;
        RECT 140.065 99.945 140.295 101.105 ;
        RECT 140.050 99.625 140.310 99.945 ;
        RECT 138.375 98.415 139.070 98.735 ;
        RECT 139.285 97.985 139.515 99.295 ;
        RECT 140.065 99.005 140.295 99.625 ;
        RECT 139.690 98.390 140.060 98.760 ;
        RECT 140.025 97.985 140.255 98.015 ;
        RECT 139.285 97.755 140.255 97.985 ;
        RECT 140.025 97.725 140.255 97.755 ;
        RECT 139.240 97.165 139.560 97.425 ;
        RECT 17.155 96.750 18.240 96.980 ;
        RECT 19.640 96.815 29.230 97.105 ;
        RECT 30.450 96.815 40.040 97.105 ;
        RECT 41.260 96.815 50.850 97.105 ;
        RECT 52.070 96.815 61.660 97.105 ;
        RECT 62.880 96.815 72.470 97.105 ;
        RECT 73.690 96.815 83.280 97.105 ;
        RECT 84.500 96.815 94.090 97.105 ;
        RECT 95.310 96.815 104.900 97.105 ;
        RECT 106.120 96.815 115.710 97.105 ;
        RECT 116.930 96.815 126.520 97.105 ;
        RECT 127.740 96.815 137.330 97.105 ;
        RECT 17.640 96.535 17.780 96.750 ;
        RECT 16.320 96.135 140.320 96.535 ;
      LAYER met2 ;
        RECT 119.005 224.645 119.285 225.015 ;
        RECT 52.665 222.165 53.115 223.385 ;
        RECT 52.855 219.645 52.995 222.165 ;
        RECT 55.475 222.150 55.880 223.385 ;
        RECT 58.175 222.150 58.700 223.395 ;
        RECT 60.950 222.440 61.495 223.420 ;
        RECT 60.950 222.300 61.885 222.440 ;
        RECT 60.950 222.150 61.495 222.300 ;
        RECT 55.575 220.045 55.715 222.150 ;
        RECT 58.370 220.455 58.510 222.150 ;
        RECT 58.370 220.315 61.230 220.455 ;
        RECT 55.575 219.905 60.785 220.045 ;
        RECT 52.855 219.505 59.240 219.645 ;
        RECT 53.220 215.615 53.480 216.025 ;
        RECT 53.220 215.475 55.205 215.615 ;
        RECT 53.220 215.065 53.480 215.475 ;
        RECT 53.220 210.355 53.480 211.315 ;
        RECT 53.280 208.095 53.420 210.355 ;
        RECT 55.065 208.870 55.205 215.475 ;
        RECT 59.100 210.905 59.240 219.505 ;
        RECT 60.645 216.025 60.785 219.905 ;
        RECT 61.090 218.410 61.230 220.315 ;
        RECT 61.745 218.815 61.885 222.300 ;
        RECT 63.710 222.120 64.225 223.380 ;
        RECT 66.475 222.155 66.980 223.395 ;
        RECT 63.865 219.435 64.005 222.120 ;
        RECT 66.620 219.890 66.760 222.155 ;
        RECT 69.240 222.145 69.735 223.370 ;
        RECT 69.380 220.440 69.520 222.145 ;
        RECT 71.990 222.130 72.545 223.375 ;
        RECT 72.100 221.235 72.360 222.130 ;
        RECT 72.100 220.975 88.440 221.235 ;
        RECT 69.380 220.300 85.435 220.440 ;
        RECT 66.620 219.750 79.180 219.890 ;
        RECT 63.865 219.295 77.370 219.435 ;
        RECT 61.745 218.675 69.975 218.815 ;
        RECT 61.090 218.270 68.300 218.410 ;
        RECT 60.585 215.065 60.845 216.025 ;
        RECT 62.420 215.615 62.680 216.025 ;
        RECT 62.420 215.475 64.455 215.615 ;
        RECT 62.420 215.065 62.680 215.475 ;
        RECT 60.585 210.905 60.845 211.315 ;
        RECT 59.100 210.765 60.845 210.905 ;
        RECT 60.585 210.355 60.845 210.765 ;
        RECT 62.420 210.355 62.680 211.315 ;
        RECT 55.065 208.730 58.940 208.870 ;
        RECT 58.800 208.165 58.940 208.730 ;
        RECT 62.480 208.525 62.620 210.355 ;
        RECT 64.315 208.870 64.455 215.475 ;
        RECT 68.160 210.905 68.300 218.270 ;
        RECT 69.835 216.025 69.975 218.675 ;
        RECT 69.775 215.065 70.035 216.025 ;
        RECT 71.620 215.615 71.880 216.025 ;
        RECT 71.620 215.475 73.380 215.615 ;
        RECT 71.620 215.065 71.880 215.475 ;
        RECT 69.775 210.905 70.035 211.315 ;
        RECT 68.160 210.765 70.035 210.905 ;
        RECT 69.775 210.355 70.035 210.765 ;
        RECT 71.620 210.355 71.880 211.315 ;
        RECT 64.315 208.730 71.220 208.870 ;
        RECT 62.480 208.385 64.460 208.525 ;
        RECT 53.205 194.665 53.485 208.095 ;
        RECT 58.725 206.755 59.005 208.165 ;
        RECT 64.320 208.095 64.460 208.385 ;
        RECT 71.080 208.095 71.220 208.730 ;
        RECT 71.680 208.535 71.820 210.355 ;
        RECT 73.240 208.870 73.380 215.475 ;
        RECT 77.230 210.905 77.370 219.295 ;
        RECT 79.040 216.025 79.180 219.750 ;
        RECT 80.955 217.395 83.025 217.535 ;
        RECT 78.980 215.065 79.240 216.025 ;
        RECT 80.825 215.065 81.085 216.025 ;
        RECT 82.885 211.775 83.025 217.395 ;
        RECT 85.295 214.225 85.435 220.300 ;
        RECT 88.180 215.065 88.440 220.975 ;
        RECT 88.645 217.490 89.725 217.860 ;
        RECT 85.295 214.085 88.380 214.225 ;
        RECT 88.240 211.775 88.380 214.085 ;
        RECT 82.885 211.635 88.940 211.775 ;
        RECT 88.240 211.315 88.380 211.635 ;
        RECT 78.980 210.905 79.240 211.315 ;
        RECT 77.230 210.765 79.240 210.905 ;
        RECT 78.980 210.355 79.240 210.765 ;
        RECT 80.825 210.355 81.085 211.315 ;
        RECT 88.180 210.355 88.440 211.315 ;
        RECT 80.885 209.265 81.025 210.355 ;
        RECT 80.885 209.125 87.455 209.265 ;
        RECT 73.240 208.730 81.015 208.870 ;
        RECT 71.680 208.395 75.505 208.535 ;
        RECT 75.365 208.095 75.505 208.395 ;
        RECT 80.875 208.095 81.015 208.730 ;
        RECT 87.315 208.095 87.455 209.125 ;
        RECT 88.800 208.095 88.940 211.635 ;
        RECT 58.275 205.885 58.535 206.205 ;
        RECT 56.885 204.670 57.165 205.040 ;
        RECT 56.955 202.125 57.095 204.670 ;
        RECT 58.335 204.165 58.475 205.885 ;
        RECT 59.655 205.545 59.915 205.865 ;
        RECT 59.715 204.165 59.855 205.545 ;
        RECT 64.245 204.525 64.525 208.095 ;
        RECT 71.080 207.955 71.885 208.095 ;
        RECT 69.525 205.010 71.065 205.380 ;
        RECT 67.935 204.525 68.195 204.845 ;
        RECT 71.605 204.525 71.885 207.955 ;
        RECT 75.285 204.525 75.565 208.095 ;
        RECT 76.675 205.885 76.935 206.205 ;
        RECT 67.475 204.185 67.735 204.505 ;
        RECT 58.275 203.845 58.535 204.165 ;
        RECT 59.655 203.845 59.915 204.165 ;
        RECT 64.255 204.075 64.515 204.165 ;
        RECT 64.255 203.935 64.915 204.075 ;
        RECT 64.255 203.845 64.515 203.935 ;
        RECT 56.895 201.805 57.155 202.125 ;
        RECT 61.955 201.465 62.215 201.785 ;
        RECT 60.565 200.590 60.845 200.960 ;
        RECT 60.115 200.105 60.375 200.425 ;
        RECT 60.175 198.725 60.315 200.105 ;
        RECT 60.115 198.405 60.375 198.725 ;
        RECT 56.885 197.870 57.165 198.240 ;
        RECT 56.895 197.725 57.155 197.870 ;
        RECT 60.635 196.005 60.775 200.590 ;
        RECT 61.035 200.445 61.295 200.765 ;
        RECT 61.095 198.920 61.235 200.445 ;
        RECT 61.025 198.550 61.305 198.920 ;
        RECT 60.575 195.685 60.835 196.005 ;
        RECT 60.115 195.345 60.375 195.665 ;
        RECT 57.815 191.945 58.075 192.265 ;
        RECT 56.885 191.070 57.165 191.440 ;
        RECT 56.895 190.925 57.155 191.070 ;
        RECT 57.875 190.225 58.015 191.945 ;
        RECT 57.815 189.905 58.075 190.225 ;
        RECT 60.175 189.545 60.315 195.345 ;
        RECT 61.095 190.905 61.235 198.550 ;
        RECT 61.035 190.585 61.295 190.905 ;
        RECT 62.015 190.565 62.155 201.465 ;
        RECT 64.775 200.845 64.915 203.935 ;
        RECT 64.775 200.765 65.375 200.845 ;
        RECT 64.775 200.705 65.435 200.765 ;
        RECT 64.255 198.405 64.515 198.725 ;
        RECT 62.405 195.830 62.685 196.200 ;
        RECT 64.315 196.005 64.455 198.405 ;
        RECT 64.775 197.705 64.915 200.705 ;
        RECT 65.175 200.445 65.435 200.705 ;
        RECT 67.535 199.405 67.675 204.185 ;
        RECT 67.995 200.425 68.135 204.525 ;
        RECT 75.295 203.845 75.555 204.165 ;
        RECT 72.825 202.290 74.365 202.660 ;
        RECT 70.695 201.805 70.955 202.125 ;
        RECT 68.855 200.785 69.115 201.105 ;
        RECT 70.235 200.785 70.495 201.105 ;
        RECT 67.935 200.105 68.195 200.425 ;
        RECT 67.475 199.085 67.735 199.405 ;
        RECT 65.175 198.745 65.435 199.065 ;
        RECT 64.715 197.385 64.975 197.705 ;
        RECT 61.955 190.245 62.215 190.565 ;
        RECT 60.115 189.225 60.375 189.545 ;
        RECT 57.815 186.505 58.075 186.825 ;
        RECT 57.875 184.785 58.015 186.505 ;
        RECT 56.895 184.640 57.155 184.785 ;
        RECT 56.885 184.270 57.165 184.640 ;
        RECT 57.815 184.465 58.075 184.785 ;
        RECT 57.815 182.765 58.075 183.085 ;
        RECT 56.895 178.345 57.155 178.665 ;
        RECT 56.955 177.840 57.095 178.345 ;
        RECT 56.885 177.470 57.165 177.840 ;
        RECT 57.875 174.585 58.015 182.765 ;
        RECT 62.475 180.365 62.615 195.830 ;
        RECT 64.255 195.685 64.515 196.005 ;
        RECT 64.775 192.945 64.915 197.385 ;
        RECT 65.235 193.965 65.375 198.745 ;
        RECT 65.175 193.645 65.435 193.965 ;
        RECT 67.535 193.625 67.675 199.085 ;
        RECT 67.475 193.305 67.735 193.625 ;
        RECT 64.715 192.625 64.975 192.945 ;
        RECT 64.775 187.505 64.915 192.625 ;
        RECT 65.635 192.285 65.895 192.605 ;
        RECT 65.695 190.565 65.835 192.285 ;
        RECT 65.635 190.245 65.895 190.565 ;
        RECT 64.715 187.185 64.975 187.505 ;
        RECT 62.875 184.465 63.135 184.785 ;
        RECT 62.935 184.105 63.075 184.465 ;
        RECT 62.875 183.785 63.135 184.105 ;
        RECT 62.415 180.045 62.675 180.365 ;
        RECT 62.935 179.345 63.075 183.785 ;
        RECT 64.775 182.065 64.915 187.185 ;
        RECT 65.695 182.405 65.835 190.245 ;
        RECT 67.535 190.225 67.675 193.305 ;
        RECT 67.475 189.905 67.735 190.225 ;
        RECT 67.475 184.125 67.735 184.445 ;
        RECT 65.635 182.085 65.895 182.405 ;
        RECT 64.715 181.745 64.975 182.065 ;
        RECT 64.775 180.365 64.915 181.745 ;
        RECT 64.715 180.045 64.975 180.365 ;
        RECT 62.875 179.025 63.135 179.345 ;
        RECT 61.495 176.645 61.755 176.965 ;
        RECT 60.115 175.625 60.375 175.945 ;
        RECT 57.815 174.265 58.075 174.585 ;
        RECT 60.175 173.905 60.315 175.625 ;
        RECT 61.555 174.245 61.695 176.645 ;
        RECT 61.495 173.925 61.755 174.245 ;
        RECT 62.935 173.905 63.075 179.025 ;
        RECT 64.775 177.645 64.915 180.045 ;
        RECT 65.175 178.345 65.435 178.665 ;
        RECT 64.715 177.325 64.975 177.645 ;
        RECT 64.775 176.965 64.915 177.325 ;
        RECT 65.235 177.305 65.375 178.345 ;
        RECT 65.175 176.985 65.435 177.305 ;
        RECT 65.695 176.965 65.835 182.085 ;
        RECT 66.095 181.065 66.355 181.385 ;
        RECT 66.155 176.965 66.295 181.065 ;
        RECT 67.535 179.005 67.675 184.125 ;
        RECT 67.995 179.345 68.135 200.105 ;
        RECT 68.915 199.405 69.055 200.785 ;
        RECT 70.295 200.425 70.435 200.785 ;
        RECT 70.235 200.105 70.495 200.425 ;
        RECT 70.755 200.335 70.895 201.805 ;
        RECT 72.075 200.785 72.335 201.105 ;
        RECT 73.915 200.960 74.175 201.105 ;
        RECT 73.905 200.845 74.185 200.960 ;
        RECT 71.615 200.445 71.875 200.765 ;
        RECT 70.755 200.195 71.355 200.335 ;
        RECT 69.525 199.570 71.065 199.940 ;
        RECT 68.855 199.085 69.115 199.405 ;
        RECT 70.695 198.920 70.955 199.065 ;
        RECT 70.685 198.550 70.965 198.920 ;
        RECT 70.755 196.685 70.895 198.550 ;
        RECT 70.695 196.365 70.955 196.685 ;
        RECT 69.525 194.130 71.065 194.500 ;
        RECT 69.775 192.625 70.035 192.945 ;
        RECT 69.835 190.565 69.975 192.625 ;
        RECT 69.775 190.245 70.035 190.565 ;
        RECT 71.215 190.225 71.355 200.195 ;
        RECT 71.675 193.285 71.815 200.445 ;
        RECT 71.615 192.965 71.875 193.285 ;
        RECT 72.135 190.905 72.275 200.785 ;
        RECT 73.905 200.705 74.575 200.845 ;
        RECT 73.905 200.590 74.185 200.705 ;
        RECT 72.995 200.105 73.255 200.425 ;
        RECT 73.055 199.405 73.195 200.105 ;
        RECT 72.995 199.085 73.255 199.405 ;
        RECT 74.435 198.125 74.575 200.705 ;
        RECT 74.435 197.985 75.035 198.125 ;
        RECT 72.825 196.850 74.365 197.220 ;
        RECT 74.895 196.685 75.035 197.985 ;
        RECT 74.835 196.365 75.095 196.685 ;
        RECT 75.355 196.345 75.495 203.845 ;
        RECT 76.735 201.105 76.875 205.885 ;
        RECT 77.595 203.845 77.855 204.165 ;
        RECT 79.895 203.845 80.155 204.165 ;
        RECT 77.135 203.505 77.395 203.825 ;
        RECT 77.195 202.125 77.335 203.505 ;
        RECT 77.135 201.805 77.395 202.125 ;
        RECT 76.675 200.785 76.935 201.105 ;
        RECT 75.295 196.025 75.555 196.345 ;
        RECT 75.355 193.965 75.495 196.025 ;
        RECT 76.735 195.665 76.875 200.785 ;
        RECT 76.675 195.345 76.935 195.665 ;
        RECT 75.295 193.645 75.555 193.965 ;
        RECT 72.825 191.410 74.365 191.780 ;
        RECT 72.075 190.585 72.335 190.905 ;
        RECT 71.155 189.905 71.415 190.225 ;
        RECT 71.615 189.565 71.875 189.885 ;
        RECT 69.525 188.690 71.065 189.060 ;
        RECT 68.395 186.505 68.655 186.825 ;
        RECT 68.455 185.125 68.595 186.505 ;
        RECT 68.395 184.805 68.655 185.125 ;
        RECT 67.935 179.025 68.195 179.345 ;
        RECT 67.475 178.685 67.735 179.005 ;
        RECT 64.715 176.645 64.975 176.965 ;
        RECT 65.635 176.645 65.895 176.965 ;
        RECT 66.095 176.645 66.355 176.965 ;
        RECT 68.455 173.905 68.595 184.805 ;
        RECT 71.675 184.785 71.815 189.565 ;
        RECT 75.355 189.545 75.495 193.645 ;
        RECT 77.195 193.285 77.335 201.805 ;
        RECT 77.655 199.405 77.795 203.845 ;
        RECT 78.515 203.505 78.775 203.825 ;
        RECT 78.055 203.165 78.315 203.485 ;
        RECT 78.115 199.405 78.255 203.165 ;
        RECT 77.595 199.085 77.855 199.405 ;
        RECT 78.055 199.085 78.315 199.405 ;
        RECT 78.575 193.625 78.715 203.505 ;
        RECT 79.435 202.825 79.695 203.145 ;
        RECT 79.495 201.105 79.635 202.825 ;
        RECT 79.435 200.785 79.695 201.105 ;
        RECT 78.975 195.005 79.235 195.325 ;
        RECT 79.035 193.625 79.175 195.005 ;
        RECT 78.515 193.305 78.775 193.625 ;
        RECT 78.975 193.305 79.235 193.625 ;
        RECT 77.135 192.965 77.395 193.285 ;
        RECT 77.135 190.245 77.395 190.565 ;
        RECT 76.215 189.905 76.475 190.225 ;
        RECT 75.295 189.225 75.555 189.545 ;
        RECT 75.295 188.205 75.555 188.525 ;
        RECT 74.835 187.865 75.095 188.185 ;
        RECT 72.825 185.970 74.365 186.340 ;
        RECT 74.895 185.125 75.035 187.865 ;
        RECT 75.355 185.125 75.495 188.205 ;
        RECT 75.755 187.525 76.015 187.845 ;
        RECT 74.835 184.805 75.095 185.125 ;
        RECT 75.295 184.805 75.555 185.125 ;
        RECT 71.615 184.465 71.875 184.785 ;
        RECT 73.915 184.465 74.175 184.785 ;
        RECT 71.155 184.125 71.415 184.445 ;
        RECT 69.525 183.250 71.065 183.620 ;
        RECT 71.215 179.345 71.355 184.125 ;
        RECT 73.975 182.405 74.115 184.465 ;
        RECT 74.895 182.745 75.035 184.805 ;
        RECT 75.295 183.785 75.555 184.105 ;
        RECT 74.835 182.425 75.095 182.745 ;
        RECT 75.355 182.405 75.495 183.785 ;
        RECT 73.915 182.085 74.175 182.405 ;
        RECT 75.295 182.085 75.555 182.405 ;
        RECT 75.355 181.385 75.495 182.085 ;
        RECT 75.815 182.065 75.955 187.525 ;
        RECT 76.275 186.825 76.415 189.905 ;
        RECT 76.675 187.525 76.935 187.845 ;
        RECT 76.215 186.505 76.475 186.825 ;
        RECT 75.755 181.745 76.015 182.065 ;
        RECT 71.615 181.065 71.875 181.385 ;
        RECT 75.295 181.065 75.555 181.385 ;
        RECT 71.675 180.445 71.815 181.065 ;
        RECT 72.825 180.530 74.365 180.900 ;
        RECT 71.675 180.305 72.275 180.445 ;
        RECT 71.155 179.025 71.415 179.345 ;
        RECT 69.525 177.810 71.065 178.180 ;
        RECT 71.215 176.625 71.355 179.025 ;
        RECT 72.135 176.965 72.275 180.305 ;
        RECT 76.275 179.765 76.415 186.505 ;
        RECT 76.735 180.365 76.875 187.525 ;
        RECT 76.675 180.045 76.935 180.365 ;
        RECT 74.895 179.625 76.415 179.765 ;
        RECT 74.895 179.345 75.035 179.625 ;
        RECT 74.835 179.025 75.095 179.345 ;
        RECT 75.295 179.025 75.555 179.345 ;
        RECT 72.075 176.645 72.335 176.965 ;
        RECT 71.155 176.305 71.415 176.625 ;
        RECT 72.135 173.905 72.275 176.645 ;
        RECT 72.825 175.090 74.365 175.460 ;
        RECT 74.895 174.585 75.035 179.025 ;
        RECT 74.835 174.265 75.095 174.585 ;
        RECT 75.355 173.905 75.495 179.025 ;
        RECT 76.735 175.945 76.875 180.045 ;
        RECT 77.195 179.345 77.335 190.245 ;
        RECT 79.955 189.885 80.095 203.845 ;
        RECT 80.355 203.505 80.615 203.825 ;
        RECT 80.415 201.105 80.555 203.505 ;
        RECT 80.355 200.785 80.615 201.105 ;
        RECT 80.355 195.345 80.615 195.665 ;
        RECT 78.975 189.565 79.235 189.885 ;
        RECT 79.895 189.565 80.155 189.885 ;
        RECT 79.035 187.845 79.175 189.565 ;
        RECT 77.595 187.525 77.855 187.845 ;
        RECT 78.975 187.525 79.235 187.845 ;
        RECT 77.655 184.785 77.795 187.525 ;
        RECT 77.595 184.465 77.855 184.785 ;
        RECT 78.055 184.465 78.315 184.785 ;
        RECT 78.115 182.405 78.255 184.465 ;
        RECT 79.035 184.105 79.175 187.525 ;
        RECT 79.435 184.805 79.695 185.125 ;
        RECT 78.975 183.785 79.235 184.105 ;
        RECT 77.595 182.085 77.855 182.405 ;
        RECT 78.055 182.085 78.315 182.405 ;
        RECT 77.655 179.685 77.795 182.085 ;
        RECT 77.595 179.365 77.855 179.685 ;
        RECT 77.135 179.025 77.395 179.345 ;
        RECT 76.675 175.625 76.935 175.945 ;
        RECT 78.115 174.245 78.255 182.085 ;
        RECT 78.975 181.065 79.235 181.385 ;
        RECT 79.035 176.965 79.175 181.065 ;
        RECT 78.975 176.645 79.235 176.965 ;
        RECT 78.515 175.625 78.775 175.945 ;
        RECT 78.575 174.245 78.715 175.625 ;
        RECT 79.495 174.585 79.635 184.805 ;
        RECT 80.415 174.585 80.555 195.345 ;
        RECT 80.805 188.205 81.085 208.095 ;
        RECT 83.115 206.755 83.375 207.075 ;
        RECT 83.175 202.125 83.315 206.755 ;
        RECT 85.380 206.300 85.710 206.795 ;
        RECT 83.575 205.545 83.835 205.865 ;
        RECT 83.115 201.720 83.375 202.125 ;
        RECT 81.275 200.785 81.535 201.105 ;
        RECT 81.335 199.065 81.475 200.785 ;
        RECT 81.275 198.745 81.535 199.065 ;
        RECT 81.275 196.025 81.535 196.345 ;
        RECT 81.335 193.625 81.475 196.025 ;
        RECT 81.735 195.685 81.995 196.005 ;
        RECT 82.185 195.830 82.465 196.200 ;
        RECT 81.275 193.305 81.535 193.625 ;
        RECT 81.275 192.625 81.535 192.945 ;
        RECT 81.335 190.225 81.475 192.625 ;
        RECT 81.275 189.905 81.535 190.225 ;
        RECT 81.275 189.225 81.535 189.545 ;
        RECT 80.815 183.785 81.075 184.105 ;
        RECT 80.875 179.345 81.015 183.785 ;
        RECT 80.815 179.025 81.075 179.345 ;
        RECT 79.435 174.265 79.695 174.585 ;
        RECT 80.355 174.265 80.615 174.585 ;
        RECT 81.335 174.245 81.475 189.225 ;
        RECT 81.795 188.525 81.935 195.685 ;
        RECT 82.255 195.665 82.395 195.830 ;
        RECT 83.635 195.665 83.775 205.545 ;
        RECT 84.955 203.845 85.215 204.165 ;
        RECT 84.035 200.105 84.295 200.425 ;
        RECT 84.495 200.105 84.755 200.425 ;
        RECT 84.095 196.345 84.235 200.105 ;
        RECT 84.555 199.065 84.695 200.105 ;
        RECT 84.495 198.745 84.755 199.065 ;
        RECT 84.495 198.065 84.755 198.385 ;
        RECT 84.035 196.025 84.295 196.345 ;
        RECT 84.555 196.005 84.695 198.065 ;
        RECT 84.495 195.685 84.755 196.005 ;
        RECT 82.195 195.345 82.455 195.665 ;
        RECT 82.655 195.345 82.915 195.665 ;
        RECT 83.575 195.575 83.835 195.665 ;
        RECT 83.175 195.435 83.835 195.575 ;
        RECT 82.715 193.965 82.855 195.345 ;
        RECT 82.655 193.645 82.915 193.965 ;
        RECT 83.175 193.285 83.315 195.435 ;
        RECT 83.575 195.345 83.835 195.435 ;
        RECT 84.035 195.345 84.295 195.665 ;
        RECT 83.115 192.965 83.375 193.285 ;
        RECT 81.735 188.205 81.995 188.525 ;
        RECT 82.195 187.185 82.455 187.505 ;
        RECT 82.255 178.665 82.395 187.185 ;
        RECT 83.175 180.365 83.315 192.965 ;
        RECT 84.095 189.545 84.235 195.345 ;
        RECT 84.035 189.225 84.295 189.545 ;
        RECT 85.015 187.165 85.155 203.845 ;
        RECT 85.415 199.085 85.675 206.300 ;
        RECT 86.335 195.345 86.595 195.665 ;
        RECT 86.395 187.845 86.535 195.345 ;
        RECT 86.795 194.665 87.055 194.985 ;
        RECT 86.855 193.965 86.995 194.665 ;
        RECT 86.795 193.645 87.055 193.965 ;
        RECT 86.335 187.525 86.595 187.845 ;
        RECT 85.415 187.185 85.675 187.505 ;
        RECT 84.955 186.845 85.215 187.165 ;
        RECT 85.475 185.125 85.615 187.185 ;
        RECT 85.415 184.805 85.675 185.125 ;
        RECT 83.115 180.045 83.375 180.365 ;
        RECT 82.195 178.345 82.455 178.665 ;
        RECT 85.475 174.585 85.615 184.805 ;
        RECT 86.335 184.465 86.595 184.785 ;
        RECT 86.395 182.405 86.535 184.465 ;
        RECT 86.335 182.085 86.595 182.405 ;
        RECT 86.395 177.645 86.535 182.085 ;
        RECT 86.795 181.745 87.055 182.065 ;
        RECT 86.335 177.325 86.595 177.645 ;
        RECT 85.415 174.265 85.675 174.585 ;
        RECT 78.055 173.925 78.315 174.245 ;
        RECT 78.515 173.925 78.775 174.245 ;
        RECT 81.275 173.925 81.535 174.245 ;
        RECT 86.855 173.905 86.995 181.745 ;
        RECT 87.255 180.045 87.515 208.095 ;
        RECT 88.745 205.865 89.025 208.095 ;
        RECT 87.715 205.605 89.025 205.865 ;
        RECT 87.715 177.325 87.975 205.605 ;
        RECT 91.770 204.275 92.850 208.265 ;
        RECT 103.005 204.085 103.685 204.115 ;
        RECT 102.905 203.765 103.805 204.085 ;
        RECT 103.005 203.745 103.685 203.765 ;
        RECT 88.165 201.950 88.445 202.320 ;
        RECT 88.235 190.225 88.375 201.950 ;
        RECT 91.895 201.550 92.175 203.520 ;
        RECT 94.165 202.790 98.460 203.110 ;
        RECT 99.750 202.790 100.970 203.110 ;
        RECT 94.165 200.415 94.485 202.790 ;
        RECT 95.155 201.305 96.235 201.675 ;
        RECT 96.820 201.300 97.900 201.670 ;
        RECT 94.165 200.095 95.220 200.415 ;
        RECT 91.770 195.295 92.850 199.265 ;
        RECT 94.960 190.495 95.220 200.095 ;
        RECT 97.830 199.780 98.090 200.415 ;
        RECT 100.355 199.780 100.495 202.790 ;
        RECT 97.830 199.640 100.495 199.780 ;
        RECT 97.830 190.495 98.090 199.640 ;
        RECT 88.175 189.905 88.435 190.225 ;
        RECT 88.175 181.405 88.435 181.725 ;
        RECT 88.235 179.685 88.375 181.405 ;
        RECT 88.175 179.365 88.435 179.685 ;
        RECT 60.115 173.585 60.375 173.905 ;
        RECT 62.875 173.585 63.135 173.905 ;
        RECT 68.395 173.585 68.655 173.905 ;
        RECT 72.075 173.585 72.335 173.905 ;
        RECT 75.295 173.585 75.555 173.905 ;
        RECT 86.795 173.585 87.055 173.905 ;
        RECT 88.235 173.760 88.375 179.365 ;
        RECT 88.165 173.390 88.445 173.760 ;
        RECT 94.995 173.630 95.275 173.755 ;
        RECT 119.065 173.630 119.205 224.645 ;
        RECT 94.995 173.490 119.205 173.630 ;
        RECT 94.995 173.385 95.275 173.490 ;
        RECT 56.895 172.905 57.155 173.225 ;
        RECT 56.955 171.040 57.095 172.905 ;
        RECT 56.885 170.670 57.165 171.040 ;
        RECT 67.475 169.280 67.735 173.225 ;
        RECT 69.525 172.370 71.065 172.740 ;
        RECT 67.440 168.910 67.770 169.280 ;
        RECT 1.680 156.255 2.760 156.290 ;
        RECT 16.910 156.255 19.090 156.265 ;
        RECT 1.680 155.955 19.090 156.255 ;
        RECT 1.680 155.920 2.760 155.955 ;
        RECT 16.910 155.945 19.090 155.955 ;
        RECT 139.245 155.575 142.385 155.895 ;
        RECT 17.555 154.165 17.835 154.240 ;
        RECT 17.535 153.905 17.855 154.165 ;
        RECT 17.555 153.870 17.835 153.905 ;
        RECT 139.245 153.495 139.565 155.575 ;
        RECT 18.830 153.175 139.565 153.495 ;
        RECT 25.330 152.695 138.945 153.015 ;
        RECT 138.675 152.045 138.945 152.695 ;
        RECT 142.645 152.305 143.015 152.415 ;
        RECT 17.020 151.420 138.250 151.740 ;
        RECT 140.880 151.725 141.815 152.225 ;
        RECT 142.645 152.165 145.110 152.305 ;
        RECT 142.645 152.045 143.015 152.165 ;
        RECT 4.400 150.495 5.480 150.530 ;
        RECT 16.910 150.495 19.090 150.505 ;
        RECT 4.400 150.195 19.090 150.495 ;
        RECT 4.400 150.160 5.480 150.195 ;
        RECT 16.910 150.185 19.090 150.195 ;
        RECT 1.680 145.095 2.760 145.130 ;
        RECT 16.910 145.095 19.090 145.105 ;
        RECT 1.680 144.795 19.090 145.095 ;
        RECT 1.680 144.760 2.760 144.795 ;
        RECT 16.910 144.785 19.090 144.795 ;
        RECT 139.270 144.400 142.410 144.720 ;
        RECT 17.575 142.990 17.855 143.065 ;
        RECT 17.560 142.730 17.880 142.990 ;
        RECT 17.575 142.695 17.855 142.730 ;
        RECT 139.270 142.320 139.590 144.400 ;
        RECT 18.855 142.000 139.590 142.320 ;
        RECT 25.355 141.520 138.970 141.840 ;
        RECT 138.700 140.870 138.970 141.520 ;
        RECT 142.670 141.105 143.040 141.240 ;
        RECT 144.970 141.105 145.110 152.165 ;
        RECT 17.045 140.245 138.275 140.565 ;
        RECT 140.910 140.530 141.815 141.025 ;
        RECT 142.670 140.965 145.110 141.105 ;
        RECT 142.670 140.870 143.040 140.965 ;
        RECT 4.400 139.320 5.480 139.355 ;
        RECT 16.910 139.320 19.090 139.330 ;
        RECT 4.400 139.020 19.090 139.320 ;
        RECT 4.400 138.985 5.480 139.020 ;
        RECT 16.910 139.010 19.090 139.020 ;
        RECT 1.680 135.255 2.760 135.290 ;
        RECT 16.910 135.255 19.090 135.265 ;
        RECT 1.680 134.955 19.090 135.255 ;
        RECT 1.680 134.920 2.760 134.955 ;
        RECT 16.910 134.945 19.090 134.955 ;
        RECT 139.300 134.565 142.440 134.885 ;
        RECT 17.605 133.155 17.885 133.220 ;
        RECT 17.590 132.895 17.910 133.155 ;
        RECT 17.605 132.850 17.885 132.895 ;
        RECT 139.300 132.485 139.620 134.565 ;
        RECT 18.885 132.165 139.620 132.485 ;
        RECT 25.385 131.685 139.000 132.005 ;
        RECT 138.730 131.035 139.000 131.685 ;
        RECT 142.700 131.270 143.070 131.405 ;
        RECT 144.970 131.270 145.110 140.965 ;
        RECT 140.920 130.735 141.790 131.205 ;
        RECT 142.700 131.130 147.620 131.270 ;
        RECT 142.700 131.035 143.070 131.130 ;
        RECT 17.075 130.410 138.305 130.730 ;
        RECT 4.400 129.460 5.480 129.495 ;
        RECT 16.910 129.460 19.090 129.470 ;
        RECT 4.400 129.160 19.090 129.460 ;
        RECT 4.400 129.125 5.480 129.160 ;
        RECT 16.910 129.150 19.090 129.160 ;
        RECT 1.680 120.925 2.760 120.960 ;
        RECT 16.910 120.925 19.090 120.935 ;
        RECT 1.680 120.625 19.090 120.925 ;
        RECT 1.680 120.590 2.760 120.625 ;
        RECT 16.910 120.615 19.090 120.625 ;
        RECT 18.740 119.230 128.605 119.550 ;
        RECT 17.450 118.500 17.820 118.870 ;
        RECT 18.740 117.985 19.060 119.230 ;
        RECT 25.405 118.725 27.965 119.045 ;
        RECT 36.215 118.725 38.775 119.045 ;
        RECT 47.025 118.725 49.585 119.045 ;
        RECT 57.835 118.725 60.395 119.045 ;
        RECT 68.645 118.725 71.205 119.045 ;
        RECT 79.455 118.725 82.015 119.045 ;
        RECT 90.265 118.725 92.825 119.045 ;
        RECT 101.075 118.725 103.635 119.045 ;
        RECT 111.885 118.725 114.445 119.045 ;
        RECT 122.695 118.725 125.255 119.045 ;
        RECT 133.505 118.725 134.940 119.045 ;
        RECT 18.770 117.825 19.030 117.985 ;
        RECT 27.645 117.805 27.965 118.725 ;
        RECT 38.455 117.805 38.775 118.725 ;
        RECT 49.265 117.805 49.585 118.725 ;
        RECT 60.075 117.805 60.395 118.725 ;
        RECT 70.885 117.805 71.205 118.725 ;
        RECT 81.695 117.805 82.015 118.725 ;
        RECT 92.505 117.805 92.825 118.725 ;
        RECT 103.315 117.805 103.635 118.725 ;
        RECT 114.125 117.805 114.445 118.725 ;
        RECT 124.935 117.805 125.255 118.725 ;
        RECT 17.510 117.085 18.175 117.405 ;
        RECT 17.855 115.770 18.175 117.085 ;
        RECT 25.690 116.610 26.010 117.805 ;
        RECT 27.645 117.485 36.820 117.805 ;
        RECT 38.455 117.485 47.630 117.805 ;
        RECT 49.265 117.485 58.440 117.805 ;
        RECT 60.075 117.485 69.250 117.805 ;
        RECT 70.885 117.485 80.060 117.805 ;
        RECT 81.695 117.485 90.870 117.805 ;
        RECT 92.505 117.485 101.680 117.805 ;
        RECT 103.315 117.485 112.490 117.805 ;
        RECT 114.125 117.485 123.300 117.805 ;
        RECT 124.935 117.485 134.110 117.805 ;
        RECT 134.620 117.385 134.940 118.725 ;
        RECT 140.140 118.195 141.045 118.680 ;
        RECT 134.620 117.065 139.455 117.385 ;
        RECT 140.075 117.305 140.445 117.410 ;
        RECT 140.075 117.165 143.400 117.305 ;
        RECT 134.620 116.610 134.940 117.065 ;
        RECT 140.075 117.040 140.445 117.165 ;
        RECT 25.690 116.290 134.940 116.610 ;
        RECT 139.625 115.770 139.945 116.075 ;
        RECT 17.855 115.450 139.945 115.770 ;
        RECT 4.400 115.130 5.480 115.165 ;
        RECT 16.910 115.130 19.090 115.140 ;
        RECT 4.400 114.830 19.090 115.130 ;
        RECT 4.400 114.795 5.480 114.830 ;
        RECT 16.910 114.820 19.090 114.830 ;
        RECT 1.680 112.115 2.760 112.150 ;
        RECT 16.910 112.115 19.090 112.125 ;
        RECT 1.680 111.815 19.090 112.115 ;
        RECT 1.680 111.780 2.760 111.815 ;
        RECT 16.910 111.805 19.090 111.815 ;
        RECT 18.725 110.415 128.590 110.735 ;
        RECT 17.435 109.685 17.805 110.055 ;
        RECT 17.485 109.670 17.765 109.685 ;
        RECT 18.725 109.170 19.045 110.415 ;
        RECT 25.390 109.910 27.950 110.230 ;
        RECT 36.200 109.910 38.760 110.230 ;
        RECT 47.010 109.910 49.570 110.230 ;
        RECT 57.820 109.910 60.380 110.230 ;
        RECT 68.630 109.910 71.190 110.230 ;
        RECT 79.440 109.910 82.000 110.230 ;
        RECT 90.250 109.910 92.810 110.230 ;
        RECT 101.060 109.910 103.620 110.230 ;
        RECT 111.870 109.910 114.430 110.230 ;
        RECT 122.680 109.910 125.240 110.230 ;
        RECT 133.490 109.910 134.925 110.230 ;
        RECT 18.755 109.010 19.015 109.170 ;
        RECT 27.630 108.990 27.950 109.910 ;
        RECT 38.440 108.990 38.760 109.910 ;
        RECT 49.250 108.990 49.570 109.910 ;
        RECT 60.060 108.990 60.380 109.910 ;
        RECT 70.870 108.990 71.190 109.910 ;
        RECT 81.680 108.990 82.000 109.910 ;
        RECT 92.490 108.990 92.810 109.910 ;
        RECT 103.300 108.990 103.620 109.910 ;
        RECT 114.110 108.990 114.430 109.910 ;
        RECT 124.920 108.990 125.240 109.910 ;
        RECT 17.495 108.270 18.160 108.590 ;
        RECT 17.840 106.955 18.160 108.270 ;
        RECT 25.675 107.795 25.995 108.990 ;
        RECT 27.630 108.670 36.805 108.990 ;
        RECT 38.440 108.670 47.615 108.990 ;
        RECT 49.250 108.670 58.425 108.990 ;
        RECT 60.060 108.670 69.235 108.990 ;
        RECT 70.870 108.670 80.045 108.990 ;
        RECT 81.680 108.670 90.855 108.990 ;
        RECT 92.490 108.670 101.665 108.990 ;
        RECT 103.300 108.670 112.475 108.990 ;
        RECT 114.110 108.670 123.285 108.990 ;
        RECT 124.920 108.670 134.095 108.990 ;
        RECT 134.605 108.570 134.925 109.910 ;
        RECT 140.165 109.420 140.995 109.845 ;
        RECT 134.605 108.250 139.440 108.570 ;
        RECT 140.060 108.470 140.430 108.595 ;
        RECT 143.260 108.470 143.400 117.165 ;
        RECT 140.060 108.330 143.400 108.470 ;
        RECT 134.605 107.795 134.925 108.250 ;
        RECT 140.060 108.225 140.430 108.330 ;
        RECT 25.675 107.475 134.925 107.795 ;
        RECT 139.610 106.955 139.930 107.260 ;
        RECT 17.840 106.635 139.930 106.955 ;
        RECT 4.400 106.255 5.480 106.290 ;
        RECT 16.910 106.255 19.090 106.265 ;
        RECT 4.400 105.955 19.090 106.255 ;
        RECT 4.400 105.920 5.480 105.955 ;
        RECT 16.910 105.945 19.090 105.955 ;
        RECT 1.680 102.280 2.760 102.315 ;
        RECT 16.910 102.280 19.090 102.290 ;
        RECT 1.680 101.980 19.090 102.280 ;
        RECT 1.680 101.945 2.760 101.980 ;
        RECT 16.910 101.970 19.090 101.980 ;
        RECT 18.355 100.580 128.220 100.900 ;
        RECT 17.110 100.220 17.390 100.255 ;
        RECT 17.065 99.850 17.435 100.220 ;
        RECT 18.355 99.335 18.675 100.580 ;
        RECT 25.020 100.075 27.580 100.395 ;
        RECT 35.830 100.075 38.390 100.395 ;
        RECT 46.640 100.075 49.200 100.395 ;
        RECT 57.450 100.075 60.010 100.395 ;
        RECT 68.260 100.075 70.820 100.395 ;
        RECT 79.070 100.075 81.630 100.395 ;
        RECT 89.880 100.075 92.440 100.395 ;
        RECT 100.690 100.075 103.250 100.395 ;
        RECT 111.500 100.075 114.060 100.395 ;
        RECT 122.310 100.075 124.870 100.395 ;
        RECT 133.120 100.075 134.555 100.395 ;
        RECT 18.385 99.175 18.645 99.335 ;
        RECT 27.260 99.155 27.580 100.075 ;
        RECT 38.070 99.155 38.390 100.075 ;
        RECT 48.880 99.155 49.200 100.075 ;
        RECT 59.690 99.155 60.010 100.075 ;
        RECT 70.500 99.155 70.820 100.075 ;
        RECT 81.310 99.155 81.630 100.075 ;
        RECT 92.120 99.155 92.440 100.075 ;
        RECT 102.930 99.155 103.250 100.075 ;
        RECT 113.740 99.155 114.060 100.075 ;
        RECT 124.550 99.155 124.870 100.075 ;
        RECT 17.125 98.435 17.790 98.755 ;
        RECT 17.470 97.120 17.790 98.435 ;
        RECT 25.305 97.960 25.625 99.155 ;
        RECT 27.260 98.835 36.435 99.155 ;
        RECT 38.070 98.835 47.245 99.155 ;
        RECT 48.880 98.835 58.055 99.155 ;
        RECT 59.690 98.835 68.865 99.155 ;
        RECT 70.500 98.835 79.675 99.155 ;
        RECT 81.310 98.835 90.485 99.155 ;
        RECT 92.120 98.835 101.295 99.155 ;
        RECT 102.930 98.835 112.105 99.155 ;
        RECT 113.740 98.835 122.915 99.155 ;
        RECT 124.550 98.835 133.725 99.155 ;
        RECT 134.235 98.735 134.555 100.075 ;
        RECT 139.730 99.515 140.590 100.020 ;
        RECT 134.235 98.415 139.070 98.735 ;
        RECT 139.690 98.650 140.060 98.760 ;
        RECT 143.260 98.650 143.400 108.330 ;
        RECT 139.690 98.510 143.400 98.650 ;
        RECT 134.235 97.960 134.555 98.415 ;
        RECT 139.690 98.390 140.060 98.510 ;
        RECT 25.305 97.640 134.555 97.960 ;
        RECT 139.240 97.120 139.560 97.425 ;
        RECT 17.470 96.800 139.560 97.120 ;
        RECT 4.400 96.460 5.480 96.495 ;
        RECT 16.910 96.460 19.090 96.470 ;
        RECT 4.400 96.160 19.090 96.460 ;
        RECT 4.400 96.125 5.480 96.160 ;
        RECT 16.910 96.150 19.090 96.160 ;
        RECT 143.260 92.685 143.400 98.510 ;
        RECT 132.925 92.545 143.400 92.685 ;
        RECT 132.925 2.560 133.065 92.545 ;
        RECT 147.480 89.180 147.620 131.130 ;
        RECT 147.480 89.040 152.370 89.180 ;
        RECT 132.630 1.390 133.310 2.560 ;
        RECT 152.230 2.555 152.370 89.040 ;
        RECT 151.930 1.385 152.610 2.555 ;
      LAYER met3 ;
        RECT 52.550 222.040 53.210 223.520 ;
        RECT 55.230 222.070 56.185 223.565 ;
        RECT 57.940 222.050 58.890 223.535 ;
        RECT 60.640 222.015 61.650 223.585 ;
        RECT 63.510 222.025 64.430 223.525 ;
        RECT 66.340 222.040 67.180 223.500 ;
        RECT 69.110 221.935 69.955 223.560 ;
        RECT 71.735 221.985 72.790 223.535 ;
        RECT 74.665 223.220 75.295 224.760 ;
        RECT 77.425 223.220 78.055 224.760 ;
        RECT 80.185 223.220 80.815 224.760 ;
        RECT 82.945 223.220 83.575 224.760 ;
        RECT 85.705 223.220 86.335 224.760 ;
        RECT 88.465 223.910 89.095 224.760 ;
        RECT 118.905 224.570 119.415 225.120 ;
        RECT 88.465 223.610 150.475 223.910 ;
        RECT 74.830 219.110 75.130 223.220 ;
        RECT 77.590 219.975 77.890 223.220 ;
        RECT 80.350 221.230 80.650 223.220 ;
        RECT 83.110 222.155 83.410 223.220 ;
        RECT 85.870 223.000 86.335 223.220 ;
        RECT 85.870 222.700 148.550 223.000 ;
        RECT 83.110 221.855 146.890 222.155 ;
        RECT 80.350 220.930 145.405 221.230 ;
        RECT 77.590 219.675 143.210 219.975 ;
        RECT 74.830 218.810 141.510 219.110 ;
        RECT 88.620 217.540 94.190 217.840 ;
        RECT 88.620 217.510 89.750 217.540 ;
        RECT 91.760 208.225 92.880 208.240 ;
        RECT 49.620 206.615 50.220 206.765 ;
        RECT 85.380 206.615 85.710 206.630 ;
        RECT 49.620 206.315 85.710 206.615 ;
        RECT 49.620 206.165 50.220 206.315 ;
        RECT 85.380 206.300 85.710 206.315 ;
        RECT 49.620 205.005 50.220 205.155 ;
        RECT 69.505 205.030 71.085 205.360 ;
        RECT 56.860 205.005 57.190 205.020 ;
        RECT 49.620 204.705 57.190 205.005 ;
        RECT 49.620 204.555 50.220 204.705 ;
        RECT 56.860 204.690 57.190 204.705 ;
        RECT 91.745 204.295 92.880 208.225 ;
        RECT 91.760 204.260 92.880 204.295 ;
        RECT 72.805 202.310 74.385 202.640 ;
        RECT 91.870 202.435 92.200 203.500 ;
        RECT 88.140 201.835 92.200 202.435 ;
        RECT 91.870 201.570 92.200 201.835 ;
        RECT 60.540 200.925 60.870 200.940 ;
        RECT 73.880 200.925 74.210 200.940 ;
        RECT 60.540 200.625 74.210 200.925 ;
        RECT 60.540 200.610 60.870 200.625 ;
        RECT 73.880 200.610 74.210 200.625 ;
        RECT 69.505 199.590 71.085 199.920 ;
        RECT 93.890 199.260 94.190 217.540 ;
        RECT 102.980 203.765 103.710 204.095 ;
        RECT 95.130 201.325 96.260 201.655 ;
        RECT 91.760 199.245 94.190 199.260 ;
        RECT 91.745 198.960 94.190 199.245 ;
        RECT 61.000 198.885 61.330 198.900 ;
        RECT 70.660 198.885 70.990 198.900 ;
        RECT 61.000 198.585 70.990 198.885 ;
        RECT 61.000 198.570 61.330 198.585 ;
        RECT 70.660 198.570 70.990 198.585 ;
        RECT 49.620 198.205 50.220 198.355 ;
        RECT 56.860 198.205 57.190 198.220 ;
        RECT 49.620 197.905 57.190 198.205 ;
        RECT 49.620 197.755 50.220 197.905 ;
        RECT 56.860 197.890 57.190 197.905 ;
        RECT 72.805 196.870 74.385 197.200 ;
        RECT 62.380 196.165 62.710 196.180 ;
        RECT 82.160 196.165 82.490 196.180 ;
        RECT 62.380 195.865 82.490 196.165 ;
        RECT 62.380 195.850 62.710 195.865 ;
        RECT 82.160 195.850 82.490 195.865 ;
        RECT 91.745 195.315 92.880 198.960 ;
        RECT 91.760 195.280 92.880 195.315 ;
        RECT 69.505 194.150 71.085 194.480 ;
        RECT 49.620 191.405 50.220 191.555 ;
        RECT 72.805 191.430 74.385 191.760 ;
        RECT 56.860 191.405 57.190 191.420 ;
        RECT 49.620 191.105 57.190 191.405 ;
        RECT 49.620 190.955 50.220 191.105 ;
        RECT 56.860 191.090 57.190 191.105 ;
        RECT 69.505 188.710 71.085 189.040 ;
        RECT 72.805 185.990 74.385 186.320 ;
        RECT 49.620 184.605 50.220 184.755 ;
        RECT 56.860 184.605 57.190 184.620 ;
        RECT 49.620 184.305 57.190 184.605 ;
        RECT 49.620 184.155 50.220 184.305 ;
        RECT 56.860 184.290 57.190 184.305 ;
        RECT 69.505 183.270 71.085 183.600 ;
        RECT 72.805 180.550 74.385 180.880 ;
        RECT 49.620 177.805 50.220 177.955 ;
        RECT 69.505 177.830 71.085 178.160 ;
        RECT 56.860 177.805 57.190 177.820 ;
        RECT 49.620 177.505 57.190 177.805 ;
        RECT 49.620 177.355 50.220 177.505 ;
        RECT 56.860 177.490 57.190 177.505 ;
        RECT 95.645 177.425 95.945 201.325 ;
        RECT 96.795 201.320 97.925 201.650 ;
        RECT 97.225 180.230 97.525 201.320 ;
        RECT 97.225 179.930 100.510 180.230 ;
        RECT 95.645 177.125 99.305 177.425 ;
        RECT 72.805 175.110 74.385 175.440 ;
        RECT 88.140 173.725 88.470 173.740 ;
        RECT 94.835 173.725 95.435 173.875 ;
        RECT 88.140 173.425 95.435 173.725 ;
        RECT 88.140 173.410 88.470 173.425 ;
        RECT 94.835 173.275 95.435 173.425 ;
        RECT 69.505 172.390 71.085 172.720 ;
        RECT 49.620 171.005 50.220 171.155 ;
        RECT 56.860 171.005 57.190 171.020 ;
        RECT 49.620 170.705 57.190 171.005 ;
        RECT 49.620 170.555 50.220 170.705 ;
        RECT 56.860 170.690 57.190 170.705 ;
        RECT 49.620 169.245 50.220 169.395 ;
        RECT 67.440 169.245 67.770 169.260 ;
        RECT 49.620 168.945 67.770 169.245 ;
        RECT 49.620 168.795 50.220 168.945 ;
        RECT 67.440 168.930 67.770 168.945 ;
        RECT 99.005 166.940 99.305 177.125 ;
        RECT 6.530 166.640 99.305 166.940 ;
        RECT 1.680 156.270 2.800 156.315 ;
        RECT 1.655 155.940 2.800 156.270 ;
        RECT 1.680 155.935 2.800 155.940 ;
        RECT 4.400 150.510 5.520 150.555 ;
        RECT 4.375 150.180 5.520 150.510 ;
        RECT 4.400 150.175 5.520 150.180 ;
        RECT 1.680 145.110 2.800 145.155 ;
        RECT 1.655 144.780 2.800 145.110 ;
        RECT 1.680 144.775 2.800 144.780 ;
        RECT 4.400 139.335 5.520 139.380 ;
        RECT 4.375 139.005 5.520 139.335 ;
        RECT 4.400 139.000 5.520 139.005 ;
        RECT 1.680 135.270 2.800 135.315 ;
        RECT 1.655 134.940 2.800 135.270 ;
        RECT 1.680 134.935 2.800 134.940 ;
        RECT 4.400 129.475 5.520 129.520 ;
        RECT 4.375 129.145 5.520 129.475 ;
        RECT 4.400 129.140 5.520 129.145 ;
        RECT 1.680 120.940 2.800 120.985 ;
        RECT 1.655 120.610 2.800 120.940 ;
        RECT 1.680 120.605 2.800 120.610 ;
        RECT 4.400 115.145 5.520 115.190 ;
        RECT 4.375 114.815 5.520 115.145 ;
        RECT 4.400 114.810 5.520 114.815 ;
        RECT 1.680 112.130 2.800 112.175 ;
        RECT 1.655 111.800 2.800 112.130 ;
        RECT 1.680 111.795 2.800 111.800 ;
        RECT 4.400 106.270 5.520 106.315 ;
        RECT 4.375 105.940 5.520 106.270 ;
        RECT 4.400 105.935 5.520 105.940 ;
        RECT 1.680 102.295 2.800 102.340 ;
        RECT 1.655 101.965 2.800 102.295 ;
        RECT 1.680 101.960 2.800 101.965 ;
        RECT 4.400 96.475 5.520 96.520 ;
        RECT 4.375 96.145 5.520 96.475 ;
        RECT 4.400 96.140 5.520 96.145 ;
        RECT 6.530 2.560 6.830 166.640 ;
        RECT 100.210 166.220 100.510 179.930 ;
        RECT 7.215 165.920 100.510 166.220 ;
        RECT 7.215 3.915 7.515 165.920 ;
        RECT 103.195 162.220 103.495 203.765 ;
        RECT 17.100 161.920 103.495 162.220 ;
        RECT 17.100 154.275 17.400 161.920 ;
        RECT 17.100 153.865 17.890 154.275 ;
        RECT 17.100 143.070 17.400 153.865 ;
        RECT 141.210 152.130 141.510 218.810 ;
        RECT 140.995 151.800 141.725 152.130 ;
        RECT 17.100 142.690 17.905 143.070 ;
        RECT 17.100 133.235 17.400 142.690 ;
        RECT 140.995 140.945 141.725 140.960 ;
        RECT 142.910 140.945 143.210 219.675 ;
        RECT 140.995 140.645 143.210 140.945 ;
        RECT 140.995 140.630 141.725 140.645 ;
        RECT 17.100 132.860 17.930 133.235 ;
        RECT 17.100 118.905 17.400 132.860 ;
        RECT 140.995 131.115 141.725 131.130 ;
        RECT 145.105 131.115 145.405 220.930 ;
        RECT 140.995 130.815 145.405 131.115 ;
        RECT 140.995 130.800 141.725 130.815 ;
        RECT 17.100 118.480 17.845 118.905 ;
        RECT 140.225 118.590 140.955 118.605 ;
        RECT 146.590 118.590 146.890 221.855 ;
        RECT 17.100 110.055 17.400 118.480 ;
        RECT 140.225 118.290 146.890 118.590 ;
        RECT 140.225 118.275 140.955 118.290 ;
        RECT 17.100 109.665 17.815 110.055 ;
        RECT 140.185 109.775 140.980 109.825 ;
        RECT 148.250 109.775 148.550 222.700 ;
        RECT 17.100 100.255 17.400 109.665 ;
        RECT 140.185 109.475 148.550 109.775 ;
        RECT 140.185 109.435 140.980 109.475 ;
        RECT 17.045 99.840 17.495 100.255 ;
        RECT 139.815 99.935 140.545 99.950 ;
        RECT 150.175 99.935 150.475 223.610 ;
        RECT 139.795 99.635 150.475 99.935 ;
        RECT 139.815 99.620 140.545 99.635 ;
        RECT 7.215 3.615 152.240 3.915 ;
        RECT 151.940 2.560 152.240 3.615 ;
        RECT 6.530 2.260 133.340 2.560 ;
        RECT 151.940 2.535 152.660 2.560 ;
        RECT 132.605 1.410 133.340 2.260 ;
        RECT 132.620 1.380 133.340 1.410 ;
        RECT 151.905 1.405 152.660 2.535 ;
        RECT 151.940 1.380 152.660 1.405 ;
      LAYER met4 ;
        RECT 118.975 224.760 118.990 225.000 ;
        RECT 119.290 224.760 119.305 225.000 ;
        RECT 1.000 222.775 13.940 224.340 ;
        RECT 30.670 222.775 30.970 224.760 ;
        RECT 33.430 222.775 33.730 224.760 ;
        RECT 36.190 222.775 36.490 224.760 ;
        RECT 38.950 222.775 39.250 224.760 ;
        RECT 41.710 222.775 42.010 224.760 ;
        RECT 44.470 222.775 44.770 224.760 ;
        RECT 47.230 222.775 47.530 224.760 ;
        RECT 49.990 222.775 50.290 224.760 ;
        RECT 52.750 223.430 53.050 224.760 ;
        RECT 55.510 223.430 55.810 224.760 ;
        RECT 58.270 223.475 58.570 224.760 ;
        RECT 1.000 222.475 50.290 222.775 ;
        RECT 1.000 222.340 13.940 222.475 ;
        RECT 1.000 220.760 3.000 222.340 ;
        RECT 11.940 215.430 13.940 222.340 ;
        RECT 52.620 222.100 53.145 223.430 ;
        RECT 55.415 222.150 55.960 223.430 ;
        RECT 58.130 222.135 58.690 223.475 ;
        RECT 61.030 223.450 61.330 224.760 ;
        RECT 60.905 222.110 61.490 223.450 ;
        RECT 63.790 223.425 64.090 224.760 ;
        RECT 63.690 222.110 64.235 223.425 ;
        RECT 66.550 223.420 66.850 224.760 ;
        RECT 69.310 223.425 69.610 224.760 ;
        RECT 66.445 222.115 66.980 223.420 ;
        RECT 69.195 222.095 69.760 223.425 ;
        RECT 72.070 223.420 72.370 224.760 ;
        RECT 71.875 222.070 72.650 223.420 ;
        RECT 74.665 223.220 75.295 224.760 ;
        RECT 77.425 223.220 78.055 224.760 ;
        RECT 80.185 223.220 80.815 224.760 ;
        RECT 82.945 223.220 83.575 224.760 ;
        RECT 85.705 223.220 86.335 224.760 ;
        RECT 88.465 223.610 89.095 224.760 ;
        RECT 118.975 224.670 119.305 224.760 ;
        RECT 11.940 213.430 110.520 215.430 ;
        RECT 6.000 208.215 17.980 208.220 ;
        RECT 6.000 206.220 92.885 208.215 ;
        RECT 15.980 206.215 92.885 206.220 ;
        RECT 69.500 205.435 71.100 206.215 ;
        RECT 71.095 204.385 71.100 205.435 ;
        RECT 91.755 204.285 92.885 206.215 ;
        RECT 108.520 199.235 110.520 213.430 ;
        RECT 74.395 197.235 110.520 199.235 ;
        RECT 74.395 195.305 92.885 197.235 ;
        RECT 132.490 1.000 133.390 2.790 ;
        RECT 151.810 1.000 152.710 2.790 ;
  END
END tt_um_usfq_adc_procmon
END LIBRARY

